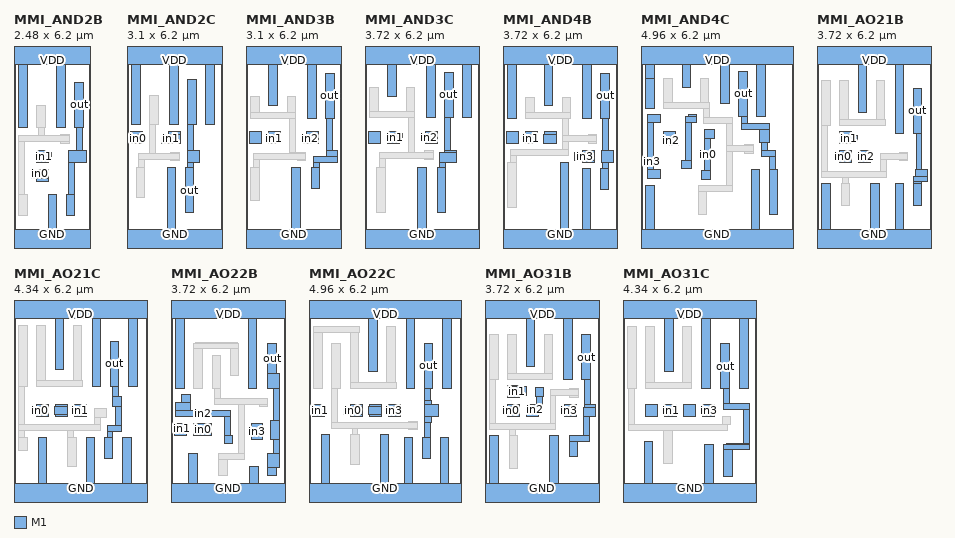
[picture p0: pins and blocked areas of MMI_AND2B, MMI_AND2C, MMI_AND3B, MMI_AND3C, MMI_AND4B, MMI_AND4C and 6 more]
MACRO MMI_AND2B
	CLASS CORE ;
	FOREIGN MMI_AND2B 0 0 ;
	SIZE 2.48 BY 6.2 ;
	SYMMETRY X Y ;
	SITE CORE1 ;
	PIN out
		DIRECTION output ;
		USE SIGNAL ;
		PORT
			LAYER M1 ;
			RECT 1.99 3.745 2.27 5.215 ;
			LAYER M1 ;
			RECT 2.04 2.98 2.23 3.745 ;
			LAYER M1 ;
			RECT 1.785 2.6 2.36 2.98 ;
			LAYER M1 ;
			RECT 1.785 1.55 1.98 2.6 ;
			LAYER M1 ;
			RECT 1.71 0.85 1.99 1.55 ;
		END
		AntennaDiffArea 0.91245 ;
	END out
	PIN in1
		DIRECTION input ;
		USE SIGNAL ;
		PORT
			LAYER M1 ;
			RECT 0.74 2.93 1.12 2.98 ;
			LAYER M1 ;
			RECT 0.74 2.65 1.225 2.93 ;
			LAYER M1 ;
			RECT 0.74 2.6 1.12 2.65 ;
		END
		AntennaGateArea 0.231 ;
	END in1
	PIN GND
		DIRECTION inout ;
		USE GROUND ;
		PORT
			LAYER M1 ;
			RECT 1.12 0.42 1.4 1.55 ;
			LAYER M1 ;
			RECT 0.0 -0.42 2.48 0.42 ;
		END
	END GND
	PIN VDD
		DIRECTION inout ;
		USE POWER ;
		PORT
			LAYER M1 ;
			RECT 0.0 5.78 2.48 6.62 ;
			LAYER M1 ;
			RECT 0.16 3.745 0.44 5.78 ;
			LAYER M1 ;
			RECT 1.4 3.745 1.68 5.78 ;
		END
	END VDD
	PIN in0
		DIRECTION input ;
		USE SIGNAL ;
		PORT
			LAYER M1 ;
			RECT 0.56 2.08 1.12 2.36 ;
			LAYER M1 ;
			RECT 0.74 1.98 1.12 2.08 ;
		END
		AntennaGateArea 0.231 ;
	END in0
	OBS
		LAYER M1 ;
		RECT 0.75 3.745 1.03 4.445 ;
		LAYER M1 ;
		RECT 0.79 3.465 0.98 3.745 ;
		LAYER M1 ;
		RECT 1.52 3.465 1.8 3.51 ;
		LAYER M1 ;
		RECT 0.16 3.27 1.8 3.465 ;
		LAYER M1 ;
		RECT 0.16 1.55 0.355 3.27 ;
		LAYER M1 ;
		RECT 1.52 3.23 1.8 3.27 ;
		LAYER M1 ;
		RECT 0.16 0.85 0.44 1.55 ;
	END
END MMI_AND2B
MACRO MMI_AND2C
	CLASS CORE ;
	FOREIGN MMI_AND2C 0 0 ;
	SIZE 3.1 BY 6.2 ;
	SYMMETRY X Y ;
	SITE CORE1 ;
	PIN out
		DIRECTION output ;
		USE SIGNAL ;
		PORT
			LAYER M1 ;
			RECT 1.985 3.82 2.265 5.29 ;
			LAYER M1 ;
			RECT 1.99 2.98 2.18 3.82 ;
			LAYER M1 ;
			RECT 1.99 2.6 2.36 2.98 ;
			LAYER M1 ;
			RECT 1.99 2.43 2.18 2.6 ;
			LAYER M1 ;
			RECT 1.9 0.96 2.18 2.43 ;
		END
		AntennaDiffArea 1.2859 ;
	END out
	PIN in1
		DIRECTION input ;
		USE SIGNAL ;
		PORT
			LAYER M1 ;
			RECT 1.36 3.51 1.74 3.6 ;
			LAYER M1 ;
			RECT 1.135 3.23 1.74 3.51 ;
			LAYER M1 ;
			RECT 1.36 3.22 1.74 3.23 ;
		END
		AntennaGateArea 0.312 ;
	END in1
	PIN GND
		DIRECTION inout ;
		USE GROUND ;
		PORT
			LAYER M1 ;
			RECT 1.31 0.42 1.59 2.43 ;
			LAYER M1 ;
			RECT 0.0 -0.42 3.1 0.42 ;
		END
	END GND
	PIN VDD
		DIRECTION inout ;
		USE POWER ;
		PORT
			LAYER M1 ;
			RECT 0.0 5.78 3.1 6.62 ;
			LAYER M1 ;
			RECT 0.155 3.82 0.435 5.78 ;
			LAYER M1 ;
			RECT 1.395 3.82 1.675 5.78 ;
			LAYER M1 ;
			RECT 2.575 3.82 2.855 5.78 ;
		END
	END VDD
	PIN in0
		DIRECTION input ;
		USE SIGNAL ;
		PORT
			LAYER M1 ;
			RECT 0.12 3.51 0.5 3.6 ;
			LAYER M1 ;
			RECT 0.12 3.23 0.505 3.51 ;
			LAYER M1 ;
			RECT 0.12 3.22 0.5 3.23 ;
		END
		AntennaGateArea 0.312 ;
	END in0
	OBS
		LAYER M1 ;
		RECT 0.745 3.82 1.025 4.79 ;
		LAYER M1 ;
		RECT 0.745 2.885 0.935 3.82 ;
		LAYER M1 ;
		RECT 1.435 2.885 1.715 2.93 ;
		LAYER M1 ;
		RECT 0.39 2.695 1.715 2.885 ;
		LAYER M1 ;
		RECT 0.39 2.435 0.58 2.695 ;
		LAYER M1 ;
		RECT 1.435 2.65 1.715 2.695 ;
		LAYER M1 ;
		RECT 0.3 1.465 0.58 2.435 ;
	END
END MMI_AND2C
MACRO MMI_AND3B
	CLASS CORE ;
	FOREIGN MMI_AND3B 0 0 ;
	SIZE 3.1 BY 6.2 ;
	SYMMETRY X Y ;
	SITE CORE1 ;
	PIN out
		DIRECTION output ;
		USE SIGNAL ;
		PORT
			LAYER M1 ;
			RECT 2.595 4.04 2.875 5.51 ;
			LAYER M1 ;
			RECT 2.635 2.98 2.825 4.04 ;
			LAYER M1 ;
			RECT 2.635 2.795 2.98 2.98 ;
			LAYER M1 ;
			RECT 2.215 2.6 2.98 2.795 ;
			LAYER M1 ;
			RECT 2.215 2.445 2.405 2.6 ;
			LAYER M1 ;
			RECT 2.125 1.745 2.405 2.445 ;
		END
		AntennaDiffArea 0.91245 ;
	END out
	PIN in1
		DIRECTION input ;
		USE SIGNAL ;
		PORT
			LAYER M1 ;
			RECT 0.74 3.51 1.12 3.6 ;
			LAYER M1 ;
			RECT 0.725 3.23 1.12 3.51 ;
			LAYER M1 ;
			RECT 0.74 3.22 1.12 3.23 ;
		END
		AntennaGateArea 0.28875 ;
	END in1
	PIN GND
		DIRECTION inout ;
		USE GROUND ;
		PORT
			LAYER M1 ;
			RECT 1.49 0.42 1.77 2.445 ;
			LAYER M1 ;
			RECT 0.0 -0.42 3.1 0.42 ;
		END
	END GND
	PIN in2
		DIRECTION input ;
		USE SIGNAL ;
		PORT
			LAYER M1 ;
			RECT 1.98 3.51 2.36 3.6 ;
			LAYER M1 ;
			RECT 1.83 3.23 2.36 3.51 ;
			LAYER M1 ;
			RECT 1.98 3.22 2.36 3.23 ;
		END
		AntennaGateArea 0.28875 ;
	END in2
	PIN VDD
		DIRECTION inout ;
		USE POWER ;
		PORT
			LAYER M1 ;
			RECT 0.0 5.78 3.1 6.62 ;
			LAYER M1 ;
			RECT 0.75 4.46 1.03 5.78 ;
			LAYER M1 ;
			RECT 2.005 4.04 2.285 5.78 ;
		END
	END VDD
	PIN in0
		DIRECTION input ;
		USE SIGNAL ;
		PORT
			LAYER M1 ;
			RECT 0.12 3.22 0.5 3.6 ;
		END
		AntennaGateArea 0.28875 ;
	END in0
	OBS
		LAYER M1 ;
		RECT 0.16 4.23 0.44 4.74 ;
		LAYER M1 ;
		RECT 1.34 4.23 1.62 4.74 ;
		LAYER M1 ;
		RECT 0.15 4.04 1.62 4.23 ;
		LAYER M1 ;
		RECT 1.42 2.93 1.61 4.04 ;
		LAYER M1 ;
		RECT 1.42 2.885 1.945 2.93 ;
		LAYER M1 ;
		RECT 0.245 2.695 1.945 2.885 ;
		LAYER M1 ;
		RECT 0.245 2.445 0.435 2.695 ;
		LAYER M1 ;
		RECT 1.665 2.65 1.945 2.695 ;
		LAYER M1 ;
		RECT 0.16 1.36 0.44 2.445 ;
	END
END MMI_AND3B
MACRO MMI_AND3C
	CLASS CORE ;
	FOREIGN MMI_AND3C 0 0 ;
	SIZE 3.72 BY 6.2 ;
	SYMMETRY X Y ;
	SITE CORE1 ;
	PIN out
		DIRECTION output ;
		USE SIGNAL ;
		PORT
			LAYER M1 ;
			RECT 2.595 4.07 2.875 5.54 ;
			LAYER M1 ;
			RECT 2.6 2.98 2.79 4.07 ;
			LAYER M1 ;
			RECT 2.6 2.93 2.98 2.98 ;
			LAYER M1 ;
			RECT 2.435 2.6 2.98 2.93 ;
			LAYER M1 ;
			RECT 2.435 2.445 2.63 2.6 ;
			LAYER M1 ;
			RECT 2.35 0.975 2.63 2.445 ;
		END
		AntennaDiffArea 1.2859 ;
	END out
	PIN in1
		DIRECTION input ;
		USE SIGNAL ;
		PORT
			LAYER M1 ;
			RECT 0.74 3.545 1.12 3.6 ;
			LAYER M1 ;
			RECT 0.74 3.265 1.23 3.545 ;
			LAYER M1 ;
			RECT 0.74 3.22 1.12 3.265 ;
		END
		AntennaGateArea 0.39 ;
	END in1
	PIN GND
		DIRECTION inout ;
		USE GROUND ;
		PORT
			LAYER M1 ;
			RECT 1.715 0.42 1.995 2.445 ;
			LAYER M1 ;
			RECT 0.0 -0.42 3.72 0.42 ;
		END
	END GND
	PIN in2
		DIRECTION input ;
		USE SIGNAL ;
		PORT
			LAYER M1 ;
			RECT 1.98 3.55 2.36 3.6 ;
			LAYER M1 ;
			RECT 1.82 3.27 2.36 3.55 ;
			LAYER M1 ;
			RECT 1.98 3.22 2.36 3.27 ;
		END
		AntennaGateArea 0.39 ;
	END in2
	PIN VDD
		DIRECTION inout ;
		USE POWER ;
		PORT
			LAYER M1 ;
			RECT 0.0 5.78 3.72 6.62 ;
			LAYER M1 ;
			RECT 0.75 4.76 1.03 5.78 ;
			LAYER M1 ;
			RECT 2.005 4.07 2.285 5.78 ;
			LAYER M1 ;
			RECT 3.185 4.07 3.465 5.78 ;
		END
	END VDD
	PIN in0
		DIRECTION input ;
		USE SIGNAL ;
		PORT
			LAYER M1 ;
			RECT 0.12 3.22 0.5 3.6 ;
		END
		AntennaGateArea 0.39 ;
	END in0
	OBS
		LAYER M1 ;
		RECT 0.16 4.26 0.44 5.04 ;
		LAYER M1 ;
		RECT 1.34 4.26 1.62 5.04 ;
		LAYER M1 ;
		RECT 0.16 4.07 1.62 4.26 ;
		LAYER M1 ;
		RECT 1.43 2.93 1.62 4.07 ;
		LAYER M1 ;
		RECT 1.95 2.93 2.23 2.97 ;
		LAYER M1 ;
		RECT 0.465 2.735 2.23 2.93 ;
		LAYER M1 ;
		RECT 0.465 2.445 0.66 2.735 ;
		LAYER M1 ;
		RECT 1.95 2.69 2.23 2.735 ;
		LAYER M1 ;
		RECT 0.385 0.955 0.665 2.445 ;
	END
END MMI_AND3C
MACRO MMI_AND4B
	CLASS CORE ;
	FOREIGN MMI_AND4B 0 0 ;
	SIZE 3.72 BY 6.2 ;
	SYMMETRY X Y ;
	SITE CORE1 ;
	PIN out
		DIRECTION output ;
		USE SIGNAL ;
		PORT
			LAYER M1 ;
			RECT 3.195 4.03 3.475 5.5 ;
			LAYER M1 ;
			RECT 3.26 2.98 3.455 4.03 ;
			LAYER M1 ;
			RECT 3.22 2.6 3.6 2.98 ;
			LAYER M1 ;
			RECT 3.26 2.4 3.455 2.6 ;
			LAYER M1 ;
			RECT 3.175 1.7 3.455 2.4 ;
		END
		AntennaDiffArea 0.91245 ;
	END out
	PIN in1
		DIRECTION input ;
		USE SIGNAL ;
		PORT
			LAYER M1 ;
			RECT 0.74 3.505 1.12 3.6 ;
			LAYER M1 ;
			RECT 0.725 3.225 1.12 3.505 ;
			LAYER M1 ;
			RECT 0.74 3.22 1.12 3.225 ;
		END
		AntennaGateArea 0.3465 ;
	END in1
	PIN GND
		DIRECTION inout ;
		USE GROUND ;
		PORT
			LAYER M1 ;
			RECT 1.86 0.42 2.14 2.605 ;
			LAYER M1 ;
			RECT 2.585 0.42 2.865 2.4 ;
			LAYER M1 ;
			RECT 0.0 -0.42 3.72 0.42 ;
		END
	END GND
	PIN in2
		DIRECTION input ;
		USE SIGNAL ;
		PORT
			LAYER M1 ;
			RECT 1.36 3.5 1.74 3.6 ;
			LAYER M1 ;
			RECT 1.32 3.22 1.74 3.5 ;
		END
		AntennaGateArea 0.3465 ;
	END in2
	PIN VDD
		DIRECTION inout ;
		USE POWER ;
		PORT
			LAYER M1 ;
			RECT 0.0 5.78 3.72 6.62 ;
			LAYER M1 ;
			RECT 0.16 4.03 0.44 5.78 ;
			LAYER M1 ;
			RECT 1.34 4.45 1.62 5.78 ;
			LAYER M1 ;
			RECT 2.605 4.03 2.885 5.78 ;
		END
	END VDD
	PIN in3
		DIRECTION input ;
		USE SIGNAL ;
		PORT
			LAYER M1 ;
			RECT 2.6 2.93 2.98 2.98 ;
			LAYER M1 ;
			RECT 2.34 2.65 2.98 2.93 ;
			LAYER M1 ;
			RECT 2.6 2.6 2.98 2.65 ;
		END
		AntennaGateArea 0.3465 ;
	END in3
	PIN in0
		DIRECTION input ;
		USE SIGNAL ;
		PORT
			LAYER M1 ;
			RECT 0.12 3.22 0.5 3.6 ;
		END
		AntennaGateArea 0.3465 ;
	END in0
	OBS
		LAYER M1 ;
		RECT 0.75 4.225 1.03 4.73 ;
		LAYER M1 ;
		RECT 1.93 4.225 2.21 4.73 ;
		LAYER M1 ;
		RECT 0.75 4.03 2.21 4.225 ;
		LAYER M1 ;
		RECT 1.94 3.465 2.135 4.03 ;
		LAYER M1 ;
		RECT 2.775 3.465 3.055 3.51 ;
		LAYER M1 ;
		RECT 1.94 3.27 3.055 3.465 ;
		LAYER M1 ;
		RECT 1.94 3.015 2.135 3.27 ;
		LAYER M1 ;
		RECT 2.775 3.23 3.055 3.27 ;
		LAYER M1 ;
		RECT 0.245 2.82 2.135 3.015 ;
		LAYER M1 ;
		RECT 0.245 2.605 0.435 2.82 ;
		LAYER M1 ;
		RECT 0.16 1.135 0.44 2.605 ;
	END
END MMI_AND4B
MACRO MMI_AND4C
	CLASS CORE ;
	FOREIGN MMI_AND4C 0 0 ;
	SIZE 4.96 BY 6.2 ;
	SYMMETRY X Y ;
	SITE CORE1 ;
	PIN out
		DIRECTION output ;
		USE SIGNAL ;
		PORT
			LAYER M1 ;
			RECT 3.195 4.11 3.475 5.58 ;
			LAYER M1 ;
			RECT 3.275 3.875 3.465 4.11 ;
			LAYER M1 ;
			RECT 3.275 3.68 4.19 3.875 ;
			LAYER M1 ;
			RECT 3.865 3.255 4.19 3.68 ;
			LAYER M1 ;
			RECT 3.935 2.985 4.125 3.255 ;
			LAYER M1 ;
			RECT 3.935 2.79 4.385 2.985 ;
			LAYER M1 ;
			RECT 4.19 2.355 4.385 2.79 ;
			LAYER M1 ;
			RECT 4.19 0.885 4.47 2.355 ;
		END
		AntennaDiffArea 1.2859 ;
	END out
	PIN in1
		DIRECTION input ;
		USE SIGNAL ;
		PORT
			LAYER M1 ;
			RECT 1.535 4.08 1.815 4.165 ;
			LAYER M1 ;
			RECT 1.455 3.885 1.815 4.08 ;
			LAYER M1 ;
			RECT 1.455 2.675 1.645 3.885 ;
			LAYER M1 ;
			RECT 1.33 2.395 1.645 2.675 ;
		END
		AntennaGateArea 0.468 ;
	END in1
	PIN GND
		DIRECTION inout ;
		USE GROUND ;
		PORT
			LAYER M1 ;
			RECT 0.16 0.42 0.44 1.855 ;
			LAYER M1 ;
			RECT 3.6 0.42 3.88 2.355 ;
			LAYER M1 ;
			RECT 0.0 -0.42 4.96 0.42 ;
		END
	END GND
	PIN in2
		DIRECTION input ;
		USE SIGNAL ;
		PORT
			LAYER M1 ;
			RECT 0.74 3.43 1.12 3.6 ;
			LAYER M1 ;
			RECT 0.74 3.22 1.21 3.43 ;
			LAYER M1 ;
			RECT 0.93 3.15 1.21 3.22 ;
		END
		AntennaGateArea 0.468 ;
	END in2
	PIN VDD
		DIRECTION inout ;
		USE POWER ;
		PORT
			LAYER M1 ;
			RECT 0.0 5.78 4.96 6.62 ;
			LAYER M1 ;
			RECT 0.15 5.335 0.43 5.78 ;
			LAYER M1 ;
			RECT 0.16 4.365 0.44 5.335 ;
			LAYER M1 ;
			RECT 1.34 5.055 1.62 5.78 ;
			LAYER M1 ;
			RECT 2.605 4.52 2.885 5.78 ;
			LAYER M1 ;
			RECT 3.785 4.11 4.065 5.78 ;
		END
	END VDD
	PIN in3
		DIRECTION input ;
		USE SIGNAL ;
		PORT
			LAYER M1 ;
			RECT 0.215 3.885 0.635 4.165 ;
			LAYER M1 ;
			RECT 0.215 2.355 0.405 3.885 ;
			LAYER M1 ;
			RECT 0.215 2.075 0.635 2.355 ;
		END
		AntennaGateArea 0.468 ;
	END in3
	PIN in0
		DIRECTION input ;
		USE SIGNAL ;
		PORT
			LAYER M1 ;
			RECT 2.075 3.375 2.405 3.655 ;
			LAYER M1 ;
			RECT 2.075 2.335 2.265 3.375 ;
			LAYER M1 ;
			RECT 1.985 2.055 2.265 2.335 ;
		END
		AntennaGateArea 0.468 ;
	END in0
	OBS
		LAYER M1 ;
		RECT 0.75 4.56 1.03 5.335 ;
		LAYER M1 ;
		RECT 1.93 4.56 2.21 5.335 ;
		LAYER M1 ;
		RECT 0.75 4.365 2.245 4.56 ;
		LAYER M1 ;
		RECT 2.055 4.06 2.245 4.365 ;
		LAYER M1 ;
		RECT 2.055 3.865 2.99 4.06 ;
		LAYER M1 ;
		RECT 2.8 3.14 2.99 3.865 ;
		LAYER M1 ;
		RECT 3.385 3.14 3.665 3.18 ;
		LAYER M1 ;
		RECT 2.8 2.945 3.665 3.14 ;
		LAYER M1 ;
		RECT 2.8 1.855 2.99 2.945 ;
		LAYER M1 ;
		RECT 3.385 2.9 3.665 2.945 ;
		LAYER M1 ;
		RECT 1.86 1.66 2.99 1.855 ;
		LAYER M1 ;
		RECT 1.86 0.885 2.14 1.66 ;
	END
END MMI_AND4C
MACRO MMI_AO21B
	CLASS CORE ;
	FOREIGN MMI_AO21B 0 0 ;
	SIZE 3.72 BY 6.2 ;
	SYMMETRY X Y ;
	SITE CORE1 ;
	PIN out
		DIRECTION output ;
		USE SIGNAL ;
		PORT
			LAYER M1 ;
			RECT 3.145 3.54 3.425 5.01 ;
			LAYER M1 ;
			RECT 3.235 2.36 3.425 3.54 ;
			LAYER M1 ;
			RECT 3.22 2.13 3.6 2.36 ;
			LAYER M1 ;
			RECT 3.15 1.98 3.6 2.13 ;
			LAYER M1 ;
			RECT 3.15 1.905 3.425 1.98 ;
			LAYER M1 ;
			RECT 3.145 1.205 3.425 1.905 ;
		END
		AntennaDiffArea 0.91245 ;
	END out
	PIN in1
		DIRECTION input ;
		USE SIGNAL ;
		PORT
			LAYER M1 ;
			RECT 0.74 3.51 1.12 3.6 ;
			LAYER M1 ;
			RECT 0.74 3.465 1.27 3.51 ;
			LAYER M1 ;
			RECT 0.74 3.27 1.33 3.465 ;
			LAYER M1 ;
			RECT 0.74 3.23 1.27 3.27 ;
			LAYER M1 ;
			RECT 0.74 3.22 1.12 3.23 ;
		END
		AntennaGateArea 0.3465 ;
	END in1
	PIN GND
		DIRECTION inout ;
		USE GROUND ;
		PORT
			LAYER M1 ;
			RECT 0.16 0.42 0.44 1.905 ;
			LAYER M1 ;
			RECT 1.755 0.42 2.035 1.905 ;
			LAYER M1 ;
			RECT 2.555 0.42 2.835 1.905 ;
			LAYER M1 ;
			RECT 0.0 -0.42 3.72 0.42 ;
		END
	END GND
	PIN in2
		DIRECTION input ;
		USE SIGNAL ;
		PORT
			LAYER M1 ;
			RECT 1.36 2.93 1.74 2.98 ;
			LAYER M1 ;
			RECT 1.36 2.65 1.84 2.93 ;
			LAYER M1 ;
			RECT 1.36 2.6 1.74 2.65 ;
		END
		AntennaGateArea 0.3465 ;
	END in2
	PIN VDD
		DIRECTION inout ;
		USE POWER ;
		PORT
			LAYER M1 ;
			RECT 0.0 5.78 3.72 6.62 ;
			LAYER M1 ;
			RECT 1.34 4.225 1.62 5.78 ;
			LAYER M1 ;
			RECT 2.555 3.54 2.835 5.78 ;
		END
	END VDD
	PIN in0
		DIRECTION input ;
		USE SIGNAL ;
		PORT
			LAYER M1 ;
			RECT 0.74 2.93 1.12 2.98 ;
			LAYER M1 ;
			RECT 0.56 2.65 1.12 2.93 ;
			LAYER M1 ;
			RECT 0.74 2.6 1.12 2.65 ;
		END
		AntennaGateArea 0.28875 ;
	END in0
	OBS
		LAYER M1 ;
		RECT 0.16 3.815 0.44 5.285 ;
		LAYER M1 ;
		RECT 0.75 4.005 1.03 5.285 ;
		LAYER M1 ;
		RECT 1.93 4.005 2.21 5.285 ;
		LAYER M1 ;
		RECT 0.75 3.815 2.245 4.005 ;
		LAYER M1 ;
		RECT 0.16 2.31 0.355 3.815 ;
		LAYER M1 ;
		RECT 2.68 2.885 2.96 2.93 ;
		LAYER M1 ;
		RECT 2.075 2.695 2.96 2.885 ;
		LAYER M1 ;
		RECT 2.075 2.31 2.265 2.695 ;
		LAYER M1 ;
		RECT 2.68 2.65 2.96 2.695 ;
		LAYER M1 ;
		RECT 0.16 2.115 2.265 2.31 ;
		LAYER M1 ;
		RECT 0.84 1.905 1.03 2.115 ;
		LAYER M1 ;
		RECT 0.795 1.205 1.075 1.905 ;
	END
END MMI_AO21B
MACRO MMI_AO21C
	CLASS CORE ;
	FOREIGN MMI_AO21C 0 0 ;
	SIZE 4.34 BY 6.2 ;
	SYMMETRY X Y ;
	SITE CORE1 ;
	PIN out
		DIRECTION output ;
		USE SIGNAL ;
		PORT
			LAYER M1 ;
			RECT 3.145 3.58 3.425 5.05 ;
			LAYER M1 ;
			RECT 3.23 3.24 3.425 3.58 ;
			LAYER M1 ;
			RECT 3.23 2.915 3.515 3.24 ;
			LAYER M1 ;
			RECT 3.325 2.315 3.515 2.915 ;
			LAYER M1 ;
			RECT 3.035 2.12 3.515 2.315 ;
			LAYER M1 ;
			RECT 3.035 1.915 3.225 2.12 ;
			LAYER M1 ;
			RECT 2.95 1.215 3.23 1.915 ;
		END
		AntennaDiffArea 1.0164 ;
	END out
	PIN in1
		DIRECTION input ;
		USE SIGNAL ;
		PORT
			LAYER M1 ;
			RECT 1.98 2.93 2.36 2.98 ;
			LAYER M1 ;
			RECT 1.95 2.65 2.36 2.93 ;
			LAYER M1 ;
			RECT 1.98 2.6 2.36 2.65 ;
		END
		AntennaGateArea 0.468 ;
	END in1
	PIN GND
		DIRECTION inout ;
		USE GROUND ;
		PORT
			LAYER M1 ;
			RECT 0.795 0.42 1.075 1.92 ;
			LAYER M1 ;
			RECT 2.36 0.42 2.64 1.915 ;
			LAYER M1 ;
			RECT 3.54 0.42 3.82 1.915 ;
			LAYER M1 ;
			RECT 0.0 -0.42 4.34 0.42 ;
		END
	END GND
	PIN in2
		DIRECTION input ;
		USE SIGNAL ;
		PORT
			LAYER M1 ;
			RECT 1.36 2.93 1.74 2.98 ;
			LAYER M1 ;
			RECT 1.33 2.65 1.74 2.93 ;
			LAYER M1 ;
			RECT 1.36 2.6 1.74 2.65 ;
		END
		AntennaGateArea 0.468 ;
	END in2
	PIN VDD
		DIRECTION inout ;
		USE POWER ;
		PORT
			LAYER M1 ;
			RECT 0.0 5.78 4.34 6.62 ;
			LAYER M1 ;
			RECT 1.34 4.13 1.62 5.78 ;
			LAYER M1 ;
			RECT 2.555 3.58 2.835 5.78 ;
			LAYER M1 ;
			RECT 3.735 3.58 4.015 5.78 ;
		END
	END VDD
	PIN in0
		DIRECTION input ;
		USE SIGNAL ;
		PORT
			LAYER M1 ;
			RECT 0.74 2.93 1.12 2.98 ;
			LAYER M1 ;
			RECT 0.555 2.65 1.12 2.93 ;
			LAYER M1 ;
			RECT 0.74 2.6 1.12 2.65 ;
		END
		AntennaGateArea 0.39 ;
	END in0
	OBS
		LAYER M1 ;
		RECT 0.16 3.57 0.44 5.58 ;
		LAYER M1 ;
		RECT 0.75 3.76 1.03 5.58 ;
		LAYER M1 ;
		RECT 1.93 3.76 2.21 5.58 ;
		LAYER M1 ;
		RECT 0.75 3.57 2.245 3.76 ;
		LAYER M1 ;
		RECT 0.16 2.32 0.355 3.57 ;
		LAYER M1 ;
		RECT 2.62 2.565 3.03 2.845 ;
		LAYER M1 ;
		RECT 2.62 2.32 2.81 2.565 ;
		LAYER M1 ;
		RECT 0.16 2.125 2.81 2.32 ;
		LAYER M1 ;
		RECT 0.16 1.92 0.355 2.125 ;
		LAYER M1 ;
		RECT 1.75 1.92 1.945 2.125 ;
		LAYER M1 ;
		RECT 0.16 1.47 0.44 1.92 ;
		LAYER M1 ;
		RECT 1.755 0.95 2.035 1.92 ;
	END
END MMI_AO21C
MACRO MMI_AO22B
	CLASS CORE ;
	FOREIGN MMI_AO22B 0 0 ;
	SIZE 3.72 BY 6.2 ;
	SYMMETRY X Y ;
	SITE CORE1 ;
	PIN out
		DIRECTION output ;
		USE SIGNAL ;
		PORT
			LAYER M1 ;
			RECT 3.165 4.01 3.445 4.99 ;
			LAYER M1 ;
			RECT 3.165 3.52 3.555 4.01 ;
			LAYER M1 ;
			RECT 3.36 2.48 3.555 3.52 ;
			LAYER M1 ;
			RECT 3.245 1.86 3.555 2.48 ;
			LAYER M1 ;
			RECT 3.36 1.385 3.555 1.86 ;
			LAYER M1 ;
			RECT 3.165 0.935 3.555 1.385 ;
			LAYER M1 ;
			RECT 3.165 0.685 3.445 0.935 ;
		END
		AntennaDiffArea 0.91245 ;
	END out
	PIN in1
		DIRECTION input ;
		USE SIGNAL ;
		PORT
			LAYER M1 ;
			RECT 0.12 2.35 0.5 2.36 ;
			LAYER M1 ;
			RECT 0.12 2.07 0.53 2.35 ;
			LAYER M1 ;
			RECT 0.12 1.98 0.5 2.07 ;
		END
		AntennaGateArea 0.3465 ;
	END in1
	PIN GND
		DIRECTION inout ;
		USE GROUND ;
		PORT
			LAYER M1 ;
			RECT 0.58 0.42 0.86 1.385 ;
			LAYER M1 ;
			RECT 2.575 0.42 2.855 0.965 ;
			LAYER M1 ;
			RECT 0.0 -0.42 3.72 0.42 ;
		END
	END GND
	PIN in2
		DIRECTION input ;
		USE SIGNAL ;
		PORT
			LAYER M1 ;
			RECT 0.355 3.04 0.635 3.315 ;
			LAYER M1 ;
			RECT 0.16 2.8 0.635 3.04 ;
			LAYER M1 ;
			RECT 0.16 2.605 1.945 2.8 ;
			LAYER M1 ;
			RECT 1.75 1.98 1.945 2.605 ;
			LAYER M1 ;
			RECT 1.73 1.7 2.01 1.98 ;
		END
		AntennaGateArea 0.3465 ;
	END in2
	PIN VDD
		DIRECTION inout ;
		USE POWER ;
		PORT
			LAYER M1 ;
			RECT 0.0 5.78 3.72 6.62 ;
			LAYER M1 ;
			RECT 0.16 3.52 0.44 5.78 ;
			LAYER M1 ;
			RECT 2.52 3.52 2.8 5.78 ;
		END
	END VDD
	PIN in3
		DIRECTION input ;
		USE SIGNAL ;
		PORT
			LAYER M1 ;
			RECT 2.625 1.845 2.98 2.36 ;
		END
		AntennaGateArea 0.3465 ;
	END in3
	PIN in0
		DIRECTION input ;
		USE SIGNAL ;
		PORT
			LAYER M1 ;
			RECT 0.74 1.98 1.33 2.36 ;
		END
		AntennaGateArea 0.3465 ;
	END in0
	OBS
		LAYER M1 ;
		RECT 0.81 4.99 2.185 4.995 ;
		LAYER M1 ;
		RECT 0.75 4.8 2.21 4.99 ;
		LAYER M1 ;
		RECT 0.75 3.52 1.03 4.8 ;
		LAYER M1 ;
		RECT 1.34 3.52 1.62 4.58 ;
		LAYER M1 ;
		RECT 1.93 3.93 2.21 4.8 ;
		LAYER M1 ;
		RECT 1.42 3.195 1.615 3.52 ;
		LAYER M1 ;
		RECT 1.42 3.0 3.16 3.195 ;
		LAYER M1 ;
		RECT 2.21 1.385 2.4 3.0 ;
		LAYER M1 ;
		RECT 2.88 2.915 3.16 3.0 ;
		LAYER M1 ;
		RECT 1.56 1.195 2.4 1.385 ;
		LAYER M1 ;
		RECT 1.56 0.685 1.84 1.195 ;
	END
END MMI_AO22B
MACRO MMI_AO22C
	CLASS CORE ;
	FOREIGN MMI_AO22C 0 0 ;
	SIZE 4.96 BY 6.2 ;
	SYMMETRY X Y ;
	SITE CORE1 ;
	PIN out
		DIRECTION output ;
		USE SIGNAL ;
		PORT
			LAYER M1 ;
			RECT 3.765 3.515 4.045 4.985 ;
			LAYER M1 ;
			RECT 3.78 3.13 3.97 3.515 ;
			LAYER M1 ;
			RECT 3.78 2.98 3.985 3.13 ;
			LAYER M1 ;
			RECT 3.78 2.6 4.22 2.98 ;
			LAYER M1 ;
			RECT 3.78 2.39 3.985 2.6 ;
			LAYER M1 ;
			RECT 3.78 1.91 3.97 2.39 ;
			LAYER M1 ;
			RECT 3.695 1.21 3.975 1.91 ;
		END
		AntennaDiffArea 1.0164 ;
	END out
	PIN in1
		DIRECTION input ;
		USE SIGNAL ;
		PORT
			LAYER M1 ;
			RECT 0.12 2.6 0.5 2.98 ;
		END
		AntennaGateArea 0.468 ;
	END in1
	PIN GND
		DIRECTION inout ;
		USE GROUND ;
		PORT
			LAYER M1 ;
			RECT 0.395 0.42 0.675 2.01 ;
			LAYER M1 ;
			RECT 2.325 0.42 2.605 2.01 ;
			LAYER M1 ;
			RECT 3.105 0.42 3.385 1.91 ;
			LAYER M1 ;
			RECT 4.285 0.42 4.565 1.91 ;
			LAYER M1 ;
			RECT 0.0 -0.42 4.96 0.42 ;
		END
	END GND
	PIN in2
		DIRECTION input ;
		USE SIGNAL ;
		PORT
			LAYER M1 ;
			RECT 1.98 2.93 2.36 2.98 ;
			LAYER M1 ;
			RECT 1.94 2.65 2.36 2.93 ;
			LAYER M1 ;
			RECT 1.98 2.6 2.36 2.65 ;
		END
		AntennaGateArea 0.468 ;
	END in2
	PIN VDD
		DIRECTION inout ;
		USE POWER ;
		PORT
			LAYER M1 ;
			RECT 0.0 5.78 4.96 6.62 ;
			LAYER M1 ;
			RECT 1.955 4.075 2.235 5.78 ;
			LAYER M1 ;
			RECT 3.175 3.515 3.455 5.78 ;
			LAYER M1 ;
			RECT 4.355 3.515 4.635 5.78 ;
		END
	END VDD
	PIN in3
		DIRECTION input ;
		USE SIGNAL ;
		PORT
			LAYER M1 ;
			RECT 2.6 2.935 2.98 2.98 ;
			LAYER M1 ;
			RECT 2.57 2.655 2.98 2.935 ;
			LAYER M1 ;
			RECT 2.6 2.6 2.98 2.655 ;
		END
		AntennaGateArea 0.468 ;
	END in3
	PIN in0
		DIRECTION input ;
		USE SIGNAL ;
		PORT
			LAYER M1 ;
			RECT 1.36 2.93 1.74 2.98 ;
			LAYER M1 ;
			RECT 1.14 2.65 1.74 2.93 ;
			LAYER M1 ;
			RECT 1.36 2.6 1.74 2.65 ;
		END
		AntennaGateArea 0.468 ;
	END in0
	OBS
		LAYER M1 ;
		RECT 0.16 5.52 0.44 5.525 ;
		LAYER M1 ;
		RECT 1.34 5.52 1.62 5.525 ;
		LAYER M1 ;
		RECT 0.15 5.33 1.64 5.52 ;
		LAYER M1 ;
		RECT 0.16 3.515 0.44 5.33 ;
		LAYER M1 ;
		RECT 0.75 3.515 1.03 4.965 ;
		LAYER M1 ;
		RECT 1.34 3.705 1.62 5.33 ;
		LAYER M1 ;
		RECT 2.545 3.705 2.825 5.525 ;
		LAYER M1 ;
		RECT 1.34 3.515 2.85 3.705 ;
		LAYER M1 ;
		RECT 0.75 2.4 0.94 3.515 ;
		LAYER M1 ;
		RECT 1.36 3.51 2.85 3.515 ;
		LAYER M1 ;
		RECT 3.25 2.4 3.53 2.435 ;
		LAYER M1 ;
		RECT 0.75 2.21 3.53 2.4 ;
		LAYER M1 ;
		RECT 1.405 2.01 1.595 2.21 ;
		LAYER M1 ;
		RECT 3.25 2.155 3.53 2.21 ;
		LAYER M1 ;
		RECT 1.365 1.04 1.645 2.01 ;
	END
END MMI_AO22C
MACRO MMI_AO31B
	CLASS CORE ;
	FOREIGN MMI_AO31B 0 0 ;
	SIZE 3.72 BY 6.2 ;
	SYMMETRY X Y ;
	SITE CORE1 ;
	PIN out
		DIRECTION output ;
		USE SIGNAL ;
		PORT
			LAYER M1 ;
			RECT 3.165 3.8 3.445 5.27 ;
			LAYER M1 ;
			RECT 3.25 2.98 3.445 3.8 ;
			LAYER M1 ;
			RECT 3.25 2.885 3.6 2.98 ;
			LAYER M1 ;
			RECT 3.22 2.6 3.6 2.885 ;
			LAYER M1 ;
			RECT 3.22 1.98 3.415 2.6 ;
			LAYER M1 ;
			RECT 2.84 1.975 3.415 1.98 ;
			LAYER M1 ;
			RECT 2.75 1.785 3.415 1.975 ;
			LAYER M1 ;
			RECT 2.75 1.275 3.03 1.785 ;
		END
		AntennaDiffArea 0.91245 ;
	END out
	PIN in1
		DIRECTION input ;
		USE SIGNAL ;
		PORT
			LAYER M1 ;
			RECT 0.74 3.56 1.12 3.6 ;
			LAYER M1 ;
			RECT 0.74 3.28 1.345 3.56 ;
			LAYER M1 ;
			RECT 0.74 3.27 1.33 3.28 ;
			LAYER M1 ;
			RECT 0.74 3.22 1.12 3.27 ;
		END
		AntennaGateArea 0.40425 ;
	END in1
	PIN GND
		DIRECTION inout ;
		USE GROUND ;
		PORT
			LAYER M1 ;
			RECT 0.16 0.42 0.44 1.975 ;
			LAYER M1 ;
			RECT 2.12 0.42 2.4 1.975 ;
			LAYER M1 ;
			RECT 0.0 -0.42 3.72 0.42 ;
		END
	END GND
	PIN in2
		DIRECTION input ;
		USE SIGNAL ;
		PORT
			LAYER M1 ;
			RECT 1.645 3.245 1.925 3.525 ;
			LAYER M1 ;
			RECT 1.695 2.98 1.89 3.245 ;
			LAYER M1 ;
			RECT 1.36 2.695 1.89 2.98 ;
			LAYER M1 ;
			RECT 1.36 2.6 1.74 2.695 ;
		END
		AntennaGateArea 0.40425 ;
	END in2
	PIN VDD
		DIRECTION inout ;
		USE POWER ;
		PORT
			LAYER M1 ;
			RECT 0.0 5.78 3.72 6.62 ;
			LAYER M1 ;
			RECT 1.34 4.21 1.62 5.78 ;
			LAYER M1 ;
			RECT 2.575 3.8 2.855 5.78 ;
		END
	END VDD
	PIN in3
		DIRECTION input ;
		USE SIGNAL ;
		PORT
			LAYER M1 ;
			RECT 2.6 2.93 2.98 2.98 ;
			LAYER M1 ;
			RECT 2.515 2.65 2.98 2.93 ;
			LAYER M1 ;
			RECT 2.6 2.6 2.98 2.65 ;
		END
		AntennaGateArea 0.40425 ;
	END in3
	PIN in0
		DIRECTION input ;
		USE SIGNAL ;
		PORT
			LAYER M1 ;
			RECT 0.74 2.93 1.12 2.98 ;
			LAYER M1 ;
			RECT 0.555 2.65 1.12 2.93 ;
			LAYER M1 ;
			RECT 0.74 2.6 1.12 2.65 ;
		END
		AntennaGateArea 0.28875 ;
	END in0
	OBS
		LAYER M1 ;
		RECT 0.16 3.8 0.44 5.27 ;
		LAYER M1 ;
		RECT 0.75 3.995 1.03 5.27 ;
		LAYER M1 ;
		RECT 1.93 3.995 2.21 5.27 ;
		LAYER M1 ;
		RECT 0.75 3.8 2.21 3.995 ;
		LAYER M1 ;
		RECT 0.16 2.375 0.355 3.8 ;
		LAYER M1 ;
		RECT 2.755 3.465 3.035 3.51 ;
		LAYER M1 ;
		RECT 2.125 3.27 3.035 3.465 ;
		LAYER M1 ;
		RECT 2.125 2.375 2.315 3.27 ;
		LAYER M1 ;
		RECT 2.755 3.23 3.035 3.27 ;
		LAYER M1 ;
		RECT 0.16 2.185 2.315 2.375 ;
		LAYER M1 ;
		RECT 0.795 1.975 0.985 2.185 ;
		LAYER M1 ;
		RECT 0.79 0.89 1.07 1.975 ;
	END
END MMI_AO31B
MACRO MMI_AO31C
	CLASS CORE ;
	FOREIGN MMI_AO31C 0 0 ;
	SIZE 4.34 BY 6.2 ;
	SYMMETRY X Y ;
	SITE CORE1 ;
	PIN out
		DIRECTION output ;
		USE SIGNAL ;
		PORT
			LAYER M1 ;
			RECT 3.195 3.505 3.475 4.975 ;
			LAYER M1 ;
			RECT 3.285 3.03 3.475 3.505 ;
			LAYER M1 ;
			RECT 3.285 2.835 4.125 3.03 ;
			LAYER M1 ;
			RECT 3.935 1.7 4.125 2.835 ;
			LAYER M1 ;
			RECT 3.375 1.69 4.125 1.7 ;
			LAYER M1 ;
			RECT 3.295 1.51 4.125 1.69 ;
			LAYER M1 ;
			RECT 3.295 0.63 3.575 1.51 ;
		END
		AntennaDiffArea 1.309 ;
	END out
	PIN in1
		DIRECTION input ;
		USE SIGNAL ;
		PORT
			LAYER M1 ;
			RECT 1.36 2.6 1.74 2.98 ;
		END
		AntennaGateArea 0.546 ;
	END in1
	PIN GND
		DIRECTION inout ;
		USE GROUND ;
		PORT
			LAYER M1 ;
			RECT 0.695 0.42 0.975 1.77 ;
			LAYER M1 ;
			RECT 2.66 0.42 2.94 1.675 ;
			LAYER M1 ;
			RECT 0.0 -0.42 4.34 0.42 ;
		END
	END GND
	PIN in2
		DIRECTION input ;
		USE SIGNAL ;
		PORT
			LAYER M1 ;
			RECT 1.98 2.6 2.36 2.98 ;
		END
		AntennaGateArea 0.546 ;
	END in2
	PIN VDD
		DIRECTION inout ;
		USE POWER ;
		PORT
			LAYER M1 ;
			RECT 0.0 5.78 4.34 6.62 ;
			LAYER M1 ;
			RECT 1.365 4.065 1.645 5.78 ;
			LAYER M1 ;
			RECT 2.56 3.505 2.84 5.78 ;
			LAYER M1 ;
			RECT 3.8 3.505 4.08 5.78 ;
		END
	END VDD
	PIN in3
		DIRECTION input ;
		USE SIGNAL ;
		PORT
			LAYER M1 ;
			RECT 2.6 2.6 2.98 2.98 ;
		END
		AntennaGateArea 0.546 ;
	END in3
	PIN in0
		DIRECTION input ;
		USE SIGNAL ;
		PORT
			LAYER M1 ;
			RECT 0.74 2.6 1.12 2.98 ;
		END
		AntennaGateArea 0.39 ;
	END in0
	OBS
		LAYER M1 ;
		RECT 0.16 3.505 0.44 5.515 ;
		LAYER M1 ;
		RECT 0.75 3.695 1.03 5.515 ;
		LAYER M1 ;
		RECT 1.955 3.695 2.235 5.515 ;
		LAYER M1 ;
		RECT 0.75 3.505 2.235 3.695 ;
		LAYER M1 ;
		RECT 0.195 2.325 0.39 3.505 ;
		LAYER M1 ;
		RECT 3.235 2.33 3.515 2.61 ;
		LAYER M1 ;
		RECT 3.235 2.325 3.425 2.33 ;
		LAYER M1 ;
		RECT 0.195 2.135 3.425 2.325 ;
		LAYER M1 ;
		RECT 1.33 1.045 1.61 2.135 ;
	END
END MMI_AO31C
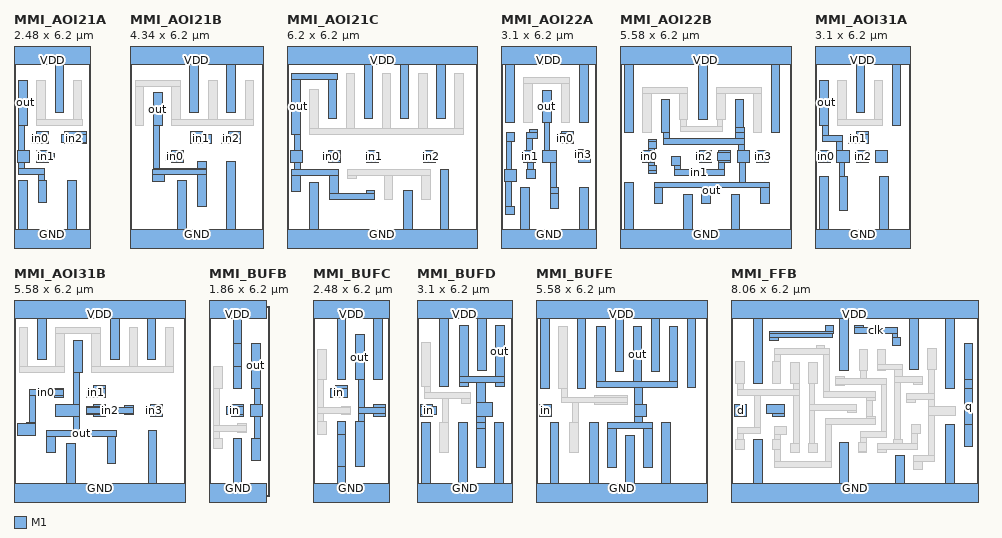
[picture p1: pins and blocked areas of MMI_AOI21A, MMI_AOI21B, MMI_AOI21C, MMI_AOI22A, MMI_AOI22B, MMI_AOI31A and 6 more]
MACRO MMI_AOI21A
	CLASS CORE ;
	FOREIGN MMI_AOI21A 0 0 ;
	SIZE 2.48 BY 6.2 ;
	SYMMETRY X Y ;
	SITE CORE1 ;
	PIN out
		DIRECTION output ;
		USE SIGNAL ;
		PORT
			LAYER M1 ;
			RECT 0.16 3.815 0.44 5.285 ;
			LAYER M1 ;
			RECT 0.16 2.98 0.355 3.815 ;
			LAYER M1 ;
			RECT 0.12 2.6 0.5 2.98 ;
			LAYER M1 ;
			RECT 0.16 2.395 0.355 2.6 ;
			LAYER M1 ;
			RECT 0.16 2.2 0.985 2.395 ;
			LAYER M1 ;
			RECT 0.795 1.995 0.985 2.2 ;
			LAYER M1 ;
			RECT 0.795 1.295 1.075 1.995 ;
		END
		AntennaDiffArea 0.948 ;
	END out
	PIN in1
		DIRECTION input ;
		USE SIGNAL ;
		PORT
			LAYER M1 ;
			RECT 0.74 2.93 1.12 2.98 ;
			LAYER M1 ;
			RECT 0.74 2.885 1.27 2.93 ;
			LAYER M1 ;
			RECT 0.74 2.695 1.33 2.885 ;
			LAYER M1 ;
			RECT 0.74 2.65 1.27 2.695 ;
			LAYER M1 ;
			RECT 0.74 2.6 1.12 2.65 ;
		END
		AntennaGateArea 0.3465 ;
	END in1
	PIN GND
		DIRECTION inout ;
		USE GROUND ;
		PORT
			LAYER M1 ;
			RECT 0.16 0.42 0.44 2.0 ;
			LAYER M1 ;
			RECT 1.755 0.42 2.035 1.995 ;
			LAYER M1 ;
			RECT 0.0 -0.42 2.48 0.42 ;
		END
	END GND
	PIN in2
		DIRECTION input ;
		USE SIGNAL ;
		PORT
			LAYER M1 ;
			RECT 1.65 3.515 2.36 3.6 ;
			LAYER M1 ;
			RECT 1.56 3.235 2.36 3.515 ;
			LAYER M1 ;
			RECT 1.65 3.22 2.36 3.235 ;
		END
		AntennaGateArea 0.3465 ;
	END in2
	PIN VDD
		DIRECTION inout ;
		USE POWER ;
		PORT
			LAYER M1 ;
			RECT 0.0 5.78 2.48 6.62 ;
			LAYER M1 ;
			RECT 1.34 4.225 1.62 5.78 ;
		END
	END VDD
	PIN in0
		DIRECTION input ;
		USE SIGNAL ;
		PORT
			LAYER M1 ;
			RECT 0.74 3.51 1.12 3.6 ;
			LAYER M1 ;
			RECT 0.555 3.23 1.12 3.51 ;
			LAYER M1 ;
			RECT 0.74 3.22 1.12 3.23 ;
		END
		AntennaGateArea 0.28875 ;
	END in0
	OBS
		LAYER M1 ;
		RECT 0.75 4.01 1.03 5.285 ;
		LAYER M1 ;
		RECT 1.93 4.01 2.21 5.285 ;
		LAYER M1 ;
		RECT 0.75 3.815 2.245 4.01 ;
	END
END MMI_AOI21A
MACRO MMI_AOI21B
	CLASS CORE ;
	FOREIGN MMI_AOI21B 0 0 ;
	SIZE 4.34 BY 6.2 ;
	SYMMETRY X Y ;
	SITE CORE1 ;
	PIN out
		DIRECTION output ;
		USE SIGNAL ;
		PORT
			LAYER M1 ;
			RECT 0.765 3.81 1.045 4.87 ;
			LAYER M1 ;
			RECT 0.765 2.39 0.955 3.81 ;
			LAYER M1 ;
			RECT 2.205 2.39 2.485 2.62 ;
			LAYER M1 ;
			RECT 0.765 2.36 2.485 2.39 ;
			LAYER M1 ;
			RECT 0.74 2.195 2.485 2.36 ;
			LAYER M1 ;
			RECT 0.74 1.98 1.12 2.195 ;
			LAYER M1 ;
			RECT 2.205 1.15 2.485 2.195 ;
		END
		AntennaDiffArea 1.36675 ;
	END out
	PIN in1
		DIRECTION input ;
		USE SIGNAL ;
		PORT
			LAYER M1 ;
			RECT 1.98 3.51 2.36 3.6 ;
			LAYER M1 ;
			RECT 1.98 3.23 2.675 3.51 ;
			LAYER M1 ;
			RECT 1.98 3.225 2.405 3.23 ;
			LAYER M1 ;
			RECT 1.98 3.22 2.36 3.225 ;
		END
		AntennaGateArea 0.693 ;
	END in1
	PIN GND
		DIRECTION inout ;
		USE GROUND ;
		PORT
			LAYER M1 ;
			RECT 1.555 0.42 1.835 1.995 ;
			LAYER M1 ;
			RECT 3.165 0.42 3.445 2.62 ;
			LAYER M1 ;
			RECT 0.0 -0.42 4.34 0.42 ;
		END
	END GND
	PIN in2
		DIRECTION input ;
		USE SIGNAL ;
		PORT
			LAYER M1 ;
			RECT 3.22 3.51 3.6 3.6 ;
			LAYER M1 ;
			RECT 2.97 3.23 3.6 3.51 ;
			LAYER M1 ;
			RECT 3.22 3.22 3.6 3.23 ;
		END
		AntennaGateArea 0.693 ;
	END in2
	PIN VDD
		DIRECTION inout ;
		USE POWER ;
		PORT
			LAYER M1 ;
			RECT 0.0 5.78 4.34 6.62 ;
			LAYER M1 ;
			RECT 1.945 4.22 2.225 5.78 ;
			LAYER M1 ;
			RECT 3.165 4.22 3.445 5.78 ;
		END
	END VDD
	PIN in0
		DIRECTION input ;
		USE SIGNAL ;
		PORT
			LAYER M1 ;
			RECT 1.36 2.93 1.74 2.98 ;
			LAYER M1 ;
			RECT 1.165 2.65 1.74 2.93 ;
			LAYER M1 ;
			RECT 1.36 2.6 1.74 2.65 ;
		END
		AntennaGateArea 0.5775 ;
	END in0
	OBS
		LAYER M1 ;
		RECT 0.165 5.09 1.64 5.285 ;
		LAYER M1 ;
		RECT 0.175 3.81 0.455 5.09 ;
		LAYER M1 ;
		RECT 1.355 4.0 1.635 5.09 ;
		LAYER M1 ;
		RECT 2.575 4.0 2.855 5.28 ;
		LAYER M1 ;
		RECT 3.755 4.0 4.035 5.28 ;
		LAYER M1 ;
		RECT 1.355 3.81 4.045 4.0 ;
	END
END MMI_AOI21B
MACRO MMI_AOI21C
	CLASS CORE ;
	FOREIGN MMI_AOI21C 0 0 ;
	SIZE 6.2 BY 6.2 ;
	SYMMETRY X Y ;
	SITE CORE1 ;
	PIN out
		DIRECTION output ;
		USE SIGNAL ;
		PORT
			LAYER M1 ;
			RECT 0.15 5.315 1.64 5.505 ;
			LAYER M1 ;
			RECT 0.16 3.515 0.44 5.315 ;
			LAYER M1 ;
			RECT 1.34 4.045 1.62 5.315 ;
			LAYER M1 ;
			RECT 0.245 2.98 0.435 3.515 ;
			LAYER M1 ;
			RECT 0.12 2.6 0.5 2.98 ;
			LAYER M1 ;
			RECT 0.245 2.35 0.435 2.6 ;
			LAYER M1 ;
			RECT 0.16 2.16 1.68 2.35 ;
			LAYER M1 ;
			RECT 0.16 1.65 0.44 2.16 ;
			LAYER M1 ;
			RECT 1.4 1.585 1.68 2.16 ;
			LAYER M1 ;
			RECT 2.58 1.585 2.86 1.675 ;
			LAYER M1 ;
			RECT 1.4 1.39 2.86 1.585 ;
		END
		AntennaDiffArea 2.9568 ;
	END out
	PIN in1
		DIRECTION input ;
		USE SIGNAL ;
		PORT
			LAYER M1 ;
			RECT 2.6 2.93 2.98 2.98 ;
			LAYER M1 ;
			RECT 2.6 2.65 3.05 2.93 ;
			LAYER M1 ;
			RECT 2.6 2.6 2.98 2.65 ;
		END
		AntennaGateArea 1.386 ;
	END in1
	PIN GND
		DIRECTION inout ;
		USE GROUND ;
		PORT
			LAYER M1 ;
			RECT 0.75 0.42 1.03 1.93 ;
			LAYER M1 ;
			RECT 3.815 0.42 4.095 1.675 ;
			LAYER M1 ;
			RECT 4.995 0.42 5.275 2.35 ;
			LAYER M1 ;
			RECT 0.0 -0.42 6.2 0.42 ;
		END
	END GND
	PIN in2
		DIRECTION input ;
		USE SIGNAL ;
		PORT
			LAYER M1 ;
			RECT 4.46 2.93 4.84 2.98 ;
			LAYER M1 ;
			RECT 4.46 2.885 4.86 2.93 ;
			LAYER M1 ;
			RECT 4.46 2.695 4.915 2.885 ;
			LAYER M1 ;
			RECT 4.46 2.65 4.86 2.695 ;
			LAYER M1 ;
			RECT 4.46 2.6 4.84 2.65 ;
		END
		AntennaGateArea 1.386 ;
	END in2
	PIN VDD
		DIRECTION inout ;
		USE POWER ;
		PORT
			LAYER M1 ;
			RECT 0.0 5.78 6.2 6.62 ;
			LAYER M1 ;
			RECT 2.52 4.045 2.8 5.78 ;
			LAYER M1 ;
			RECT 3.7 4.045 3.98 5.78 ;
			LAYER M1 ;
			RECT 4.88 4.045 5.16 5.78 ;
		END
	END VDD
	PIN in0
		DIRECTION input ;
		USE SIGNAL ;
		PORT
			LAYER M1 ;
			RECT 1.36 2.93 1.74 2.98 ;
			LAYER M1 ;
			RECT 1.16 2.65 1.74 2.93 ;
			LAYER M1 ;
			RECT 1.36 2.6 1.74 2.65 ;
		END
		AntennaGateArea 1.15575 ;
	END in0
	OBS
		LAYER M1 ;
		RECT 0.75 3.71 1.03 4.965 ;
		LAYER M1 ;
		RECT 1.93 3.71 2.21 5.5 ;
		LAYER M1 ;
		RECT 3.11 3.71 3.39 5.5 ;
		LAYER M1 ;
		RECT 4.29 3.71 4.57 5.5 ;
		LAYER M1 ;
		RECT 5.47 3.71 5.75 5.5 ;
		LAYER M1 ;
		RECT 0.75 3.515 5.77 3.71 ;
		LAYER M1 ;
		RECT 1.99 2.16 4.685 2.35 ;
		LAYER M1 ;
		RECT 1.99 2.065 2.27 2.16 ;
		LAYER M1 ;
		RECT 3.17 1.395 3.45 2.16 ;
		LAYER M1 ;
		RECT 4.405 1.395 4.685 2.16 ;
	END
END MMI_AOI21C
MACRO MMI_AOI22A
	CLASS CORE ;
	FOREIGN MMI_AOI22A 0 0 ;
	SIZE 3.1 BY 6.2 ;
	SYMMETRY X Y ;
	SITE CORE1 ;
	PIN out
		DIRECTION output ;
		USE SIGNAL ;
		PORT
			LAYER M1 ;
			RECT 1.355 3.885 1.635 4.945 ;
			LAYER M1 ;
			RECT 1.405 2.98 1.595 3.885 ;
			LAYER M1 ;
			RECT 1.36 2.6 1.795 2.98 ;
			LAYER M1 ;
			RECT 1.6 1.78 1.795 2.6 ;
			LAYER M1 ;
			RECT 1.6 1.59 1.89 1.78 ;
			LAYER M1 ;
			RECT 1.61 1.08 1.89 1.59 ;
		END
		AntennaDiffArea 1.04335 ;
	END out
	PIN in1
		DIRECTION input ;
		USE SIGNAL ;
		PORT
			LAYER M1 ;
			RECT 0.925 3.58 1.205 3.67 ;
			LAYER M1 ;
			RECT 0.82 3.39 1.205 3.58 ;
			LAYER M1 ;
			RECT 0.82 3.385 1.15 3.39 ;
			LAYER M1 ;
			RECT 0.82 2.98 1.015 3.385 ;
			LAYER M1 ;
			RECT 0.74 2.6 1.12 2.98 ;
			LAYER M1 ;
			RECT 0.875 2.35 1.07 2.6 ;
			LAYER M1 ;
			RECT 0.83 2.07 1.11 2.35 ;
		END
		AntennaGateArea 0.3465 ;
	END in1
	PIN GND
		DIRECTION inout ;
		USE GROUND ;
		PORT
			LAYER M1 ;
			RECT 0.635 0.42 0.915 1.78 ;
			LAYER M1 ;
			RECT 2.57 0.42 2.85 1.78 ;
			LAYER M1 ;
			RECT 0.0 -0.42 3.1 0.42 ;
		END
	END GND
	PIN in2
		DIRECTION input ;
		USE SIGNAL ;
		PORT
			LAYER M1 ;
			RECT 0.165 3.295 0.445 3.575 ;
			LAYER M1 ;
			RECT 0.165 2.36 0.355 3.295 ;
			LAYER M1 ;
			RECT 0.12 1.98 0.5 2.36 ;
			LAYER M1 ;
			RECT 0.155 1.17 0.35 1.98 ;
			LAYER M1 ;
			RECT 0.155 0.89 0.435 1.17 ;
		END
		AntennaGateArea 0.3465 ;
	END in2
	PIN VDD
		DIRECTION inout ;
		USE POWER ;
		PORT
			LAYER M1 ;
			RECT 0.0 5.78 3.1 6.62 ;
			LAYER M1 ;
			RECT 0.16 3.885 0.44 5.78 ;
			LAYER M1 ;
			RECT 2.56 3.885 2.84 5.78 ;
		END
	END VDD
	PIN in3
		DIRECTION input ;
		USE SIGNAL ;
		PORT
			LAYER M1 ;
			RECT 2.435 2.975 2.715 3.015 ;
			LAYER M1 ;
			RECT 2.435 2.735 2.91 2.975 ;
			LAYER M1 ;
			RECT 2.535 2.6 2.91 2.735 ;
		END
		AntennaGateArea 0.3465 ;
	END in3
	PIN in0
		DIRECTION input ;
		USE SIGNAL ;
		PORT
			LAYER M1 ;
			RECT 1.98 3.53 2.36 3.6 ;
			LAYER M1 ;
			RECT 1.795 3.25 2.36 3.53 ;
			LAYER M1 ;
			RECT 1.98 3.22 2.36 3.25 ;
		END
		AntennaGateArea 0.3465 ;
	END in0
	OBS
		LAYER M1 ;
		RECT 0.755 5.355 2.245 5.36 ;
		LAYER M1 ;
		RECT 0.75 5.165 2.25 5.355 ;
		LAYER M1 ;
		RECT 0.75 3.885 1.03 5.165 ;
		LAYER M1 ;
		RECT 1.97 3.885 2.25 5.165 ;
	END
END MMI_AOI22A
MACRO MMI_AOI22B
	CLASS CORE ;
	FOREIGN MMI_AOI22B 0 0 ;
	SIZE 5.58 BY 6.2 ;
	SYMMETRY X Y ;
	SITE CORE1 ;
	PIN out
		DIRECTION output ;
		USE SIGNAL ;
		PORT
			LAYER M1 ;
			RECT 1.34 3.585 1.62 4.645 ;
			LAYER M1 ;
			RECT 3.755 3.73 4.035 4.645 ;
			LAYER M1 ;
			RECT 3.755 3.585 4.055 3.73 ;
			LAYER M1 ;
			RECT 1.425 3.375 1.615 3.585 ;
			LAYER M1 ;
			RECT 3.77 3.375 4.055 3.585 ;
			LAYER M1 ;
			RECT 1.425 3.18 4.055 3.375 ;
			LAYER M1 ;
			RECT 3.865 2.98 4.055 3.18 ;
			LAYER M1 ;
			RECT 3.84 2.6 4.22 2.98 ;
			LAYER M1 ;
			RECT 3.9 1.955 4.095 2.6 ;
			LAYER M1 ;
			RECT 1.115 1.765 4.875 1.955 ;
			LAYER M1 ;
			RECT 1.12 1.255 1.4 1.765 ;
			LAYER M1 ;
			RECT 2.67 1.255 2.95 1.765 ;
			LAYER M1 ;
			RECT 4.59 1.255 4.87 1.765 ;
		END
		AntennaDiffArea 2.3023 ;
	END out
	PIN in1
		DIRECTION input ;
		USE SIGNAL ;
		PORT
			LAYER M1 ;
			RECT 3.22 2.93 3.6 2.98 ;
			LAYER M1 ;
			RECT 1.685 2.51 1.965 2.79 ;
			LAYER M1 ;
			RECT 3.18 2.65 3.6 2.93 ;
			LAYER M1 ;
			RECT 1.775 2.36 1.965 2.51 ;
			LAYER M1 ;
			RECT 3.215 2.6 3.6 2.65 ;
			LAYER M1 ;
			RECT 3.215 2.36 3.405 2.6 ;
			LAYER M1 ;
			RECT 1.775 2.165 3.405 2.36 ;
		END
		AntennaGateArea 0.693 ;
	END in1
	PIN GND
		DIRECTION inout ;
		USE GROUND ;
		PORT
			LAYER M1 ;
			RECT 0.16 0.42 0.44 1.955 ;
			LAYER M1 ;
			RECT 2.08 0.42 2.36 1.535 ;
			LAYER M1 ;
			RECT 3.63 0.42 3.91 1.535 ;
			LAYER M1 ;
			RECT 0.0 -0.42 5.58 0.42 ;
		END
	END GND
	PIN in2
		DIRECTION input ;
		USE SIGNAL ;
		PORT
			LAYER M1 ;
			RECT 2.6 2.93 2.98 2.98 ;
			LAYER M1 ;
			RECT 2.53 2.65 2.98 2.93 ;
			LAYER M1 ;
			RECT 2.6 2.6 2.98 2.65 ;
		END
		AntennaGateArea 0.693 ;
	END in2
	PIN VDD
		DIRECTION inout ;
		USE POWER ;
		PORT
			LAYER M1 ;
			RECT 0.0 5.78 5.58 6.62 ;
			LAYER M1 ;
			RECT 0.16 3.585 0.44 5.78 ;
			LAYER M1 ;
			RECT 2.575 3.985 2.855 5.78 ;
			LAYER M1 ;
			RECT 4.935 3.585 5.215 5.78 ;
		END
	END VDD
	PIN in3
		DIRECTION input ;
		USE SIGNAL ;
		PORT
			LAYER M1 ;
			RECT 4.46 2.6 4.84 2.98 ;
		END
		AntennaGateArea 0.693 ;
	END in3
	PIN in0
		DIRECTION input ;
		USE SIGNAL ;
		PORT
			LAYER M1 ;
			RECT 0.925 3.265 1.205 3.34 ;
			LAYER M1 ;
			RECT 0.915 3.06 1.205 3.265 ;
			LAYER M1 ;
			RECT 0.915 2.98 1.12 3.06 ;
			LAYER M1 ;
			RECT 0.74 2.6 1.12 2.98 ;
			LAYER M1 ;
			RECT 0.92 2.51 1.12 2.6 ;
			LAYER M1 ;
			RECT 0.92 2.32 1.205 2.51 ;
			LAYER M1 ;
			RECT 0.925 2.23 1.205 2.32 ;
		END
		AntennaGateArea 0.693 ;
	END in0
	OBS
		LAYER M1 ;
		RECT 0.75 5.045 1.03 5.055 ;
		LAYER M1 ;
		RECT 1.93 5.045 2.21 5.055 ;
		LAYER M1 ;
		RECT 0.75 4.85 2.21 5.045 ;
		LAYER M1 ;
		RECT 0.75 3.585 1.03 4.85 ;
		LAYER M1 ;
		RECT 1.93 3.995 2.21 4.85 ;
		LAYER M1 ;
		RECT 1.98 3.785 2.175 3.995 ;
		LAYER M1 ;
		RECT 3.165 5.05 3.445 5.055 ;
		LAYER M1 ;
		RECT 4.345 5.05 4.625 5.055 ;
		LAYER M1 ;
		RECT 3.165 4.855 4.625 5.05 ;
		LAYER M1 ;
		RECT 3.165 3.985 3.445 4.855 ;
		LAYER M1 ;
		RECT 3.17 3.785 3.36 3.985 ;
		LAYER M1 ;
		RECT 1.98 3.59 3.36 3.785 ;
		LAYER M1 ;
		RECT 4.345 3.585 4.625 4.855 ;
	END
END MMI_AOI22B
MACRO MMI_AOI31A
	CLASS CORE ;
	FOREIGN MMI_AOI31A 0 0 ;
	SIZE 3.1 BY 6.2 ;
	SYMMETRY X Y ;
	SITE CORE1 ;
	PIN out
		DIRECTION output ;
		USE SIGNAL ;
		PORT
			LAYER M1 ;
			RECT 0.16 3.81 0.44 5.28 ;
			LAYER M1 ;
			RECT 0.25 3.465 0.44 3.81 ;
			LAYER M1 ;
			RECT 0.25 3.27 0.895 3.465 ;
			LAYER M1 ;
			RECT 0.7 2.98 0.895 3.27 ;
			LAYER M1 ;
			RECT 0.7 2.6 1.12 2.98 ;
			LAYER M1 ;
			RECT 0.785 2.125 0.975 2.6 ;
			LAYER M1 ;
			RECT 0.785 1.04 1.065 2.125 ;
		END
		AntennaDiffArea 1.09725 ;
	END out
	PIN in1
		DIRECTION input ;
		USE SIGNAL ;
		PORT
			LAYER M1 ;
			RECT 1.36 3.51 1.74 3.6 ;
			LAYER M1 ;
			RECT 1.095 3.23 1.74 3.51 ;
			LAYER M1 ;
			RECT 1.36 3.22 1.74 3.23 ;
		END
		AntennaGateArea 0.40425 ;
	END in1
	PIN GND
		DIRECTION inout ;
		USE GROUND ;
		PORT
			LAYER M1 ;
			RECT 0.155 0.42 0.435 2.125 ;
			LAYER M1 ;
			RECT 2.115 0.42 2.395 2.125 ;
			LAYER M1 ;
			RECT 0.0 -0.42 3.1 0.42 ;
		END
	END GND
	PIN in2
		DIRECTION input ;
		USE SIGNAL ;
		PORT
			LAYER M1 ;
			RECT 1.36 2.93 1.74 2.98 ;
			LAYER M1 ;
			RECT 1.36 2.65 1.745 2.93 ;
			LAYER M1 ;
			RECT 1.36 2.6 1.74 2.65 ;
		END
		AntennaGateArea 0.40425 ;
	END in2
	PIN VDD
		DIRECTION inout ;
		USE POWER ;
		PORT
			LAYER M1 ;
			RECT 0.0 5.78 3.1 6.62 ;
			LAYER M1 ;
			RECT 1.34 4.22 1.62 5.78 ;
			LAYER M1 ;
			RECT 2.52 3.81 2.8 5.78 ;
		END
	END VDD
	PIN in3
		DIRECTION input ;
		USE SIGNAL ;
		PORT
			LAYER M1 ;
			RECT 1.98 2.6 2.36 2.98 ;
		END
		AntennaGateArea 0.40425 ;
	END in3
	PIN in0
		DIRECTION input ;
		USE SIGNAL ;
		PORT
			LAYER M1 ;
			RECT 0.12 2.6 0.5 2.98 ;
		END
		AntennaGateArea 0.28875 ;
	END in0
	OBS
		LAYER M1 ;
		RECT 0.75 4.0 1.03 5.28 ;
		LAYER M1 ;
		RECT 1.93 4.0 2.21 5.28 ;
		LAYER M1 ;
		RECT 0.75 3.81 2.21 4.0 ;
	END
END MMI_AOI31A
MACRO MMI_AOI31B
	CLASS CORE ;
	FOREIGN MMI_AOI31B 0 0 ;
	SIZE 5.58 BY 6.2 ;
	SYMMETRY X Y ;
	SITE CORE1 ;
	PIN out
		DIRECTION output ;
		USE SIGNAL ;
		PORT
			LAYER M1 ;
			RECT 1.945 4.03 2.225 5.09 ;
			LAYER M1 ;
			RECT 1.945 2.98 2.14 4.03 ;
			LAYER M1 ;
			RECT 1.36 2.6 2.14 2.98 ;
			LAYER M1 ;
			RECT 1.945 2.135 2.14 2.6 ;
			LAYER M1 ;
			RECT 1.175 2.13 3.335 2.135 ;
			LAYER M1 ;
			RECT 1.075 1.94 3.335 2.13 ;
			LAYER M1 ;
			RECT 1.075 1.43 1.355 1.94 ;
			LAYER M1 ;
			RECT 3.045 1.045 3.325 1.94 ;
		END
		AntennaDiffArea 1.48995 ;
	END out
	PIN in1
		DIRECTION input ;
		USE SIGNAL ;
		PORT
			LAYER M1 ;
			RECT 2.6 3.505 2.98 3.6 ;
			LAYER M1 ;
			RECT 2.35 3.225 2.98 3.505 ;
			LAYER M1 ;
			RECT 2.6 3.22 2.98 3.225 ;
		END
		AntennaGateArea 0.8085 ;
	END in1
	PIN GND
		DIRECTION inout ;
		USE GROUND ;
		PORT
			LAYER M1 ;
			RECT 1.715 0.42 1.995 1.715 ;
			LAYER M1 ;
			RECT 4.38 0.42 4.66 2.13 ;
			LAYER M1 ;
			RECT 0.0 -0.42 5.58 0.42 ;
		END
	END GND
	PIN in2
		DIRECTION input ;
		USE SIGNAL ;
		PORT
			LAYER M1 ;
			RECT 2.6 2.935 2.98 2.98 ;
			LAYER M1 ;
			RECT 2.35 2.885 2.98 2.935 ;
			LAYER M1 ;
			RECT 3.615 2.885 3.895 2.95 ;
			LAYER M1 ;
			RECT 2.35 2.695 3.895 2.885 ;
			LAYER M1 ;
			RECT 2.35 2.655 2.98 2.695 ;
			LAYER M1 ;
			RECT 3.615 2.67 3.895 2.695 ;
			LAYER M1 ;
			RECT 2.6 2.6 2.98 2.655 ;
		END
		AntennaGateArea 0.8085 ;
	END in2
	PIN VDD
		DIRECTION inout ;
		USE POWER ;
		PORT
			LAYER M1 ;
			RECT 0.0 5.78 5.58 6.62 ;
			LAYER M1 ;
			RECT 0.765 4.44 1.045 5.78 ;
			LAYER M1 ;
			RECT 3.165 4.44 3.445 5.78 ;
			LAYER M1 ;
			RECT 4.345 4.44 4.625 5.78 ;
		END
	END VDD
	PIN in3
		DIRECTION input ;
		USE SIGNAL ;
		PORT
			LAYER M1 ;
			RECT 4.46 2.93 4.84 2.98 ;
			LAYER M1 ;
			RECT 4.275 2.65 4.84 2.93 ;
			LAYER M1 ;
			RECT 4.46 2.6 4.84 2.65 ;
		END
		AntennaGateArea 0.8085 ;
	END in3
	PIN in0
		DIRECTION input ;
		USE SIGNAL ;
		PORT
			LAYER M1 ;
			RECT 1.335 3.465 1.615 3.505 ;
			LAYER M1 ;
			RECT 0.5 3.27 1.615 3.465 ;
			LAYER M1 ;
			RECT 0.5 2.405 0.69 3.27 ;
			LAYER M1 ;
			RECT 1.335 3.225 1.615 3.27 ;
			LAYER M1 ;
			RECT 0.41 2.36 0.69 2.405 ;
			LAYER M1 ;
			RECT 0.12 1.98 0.69 2.36 ;
		END
		AntennaGateArea 0.5775 ;
	END in0
	OBS
		LAYER M1 ;
		RECT 0.175 4.225 0.455 5.5 ;
		LAYER M1 ;
		RECT 1.355 5.315 2.815 5.505 ;
		LAYER M1 ;
		RECT 1.355 4.225 1.635 5.315 ;
		LAYER M1 ;
		RECT 0.175 4.03 1.635 4.225 ;
		LAYER M1 ;
		RECT 2.535 4.225 2.815 5.315 ;
		LAYER M1 ;
		RECT 3.755 4.225 4.035 5.5 ;
		LAYER M1 ;
		RECT 4.935 4.225 5.215 5.5 ;
		LAYER M1 ;
		RECT 2.535 4.03 5.215 4.225 ;
	END
END MMI_AOI31B
MACRO MMI_BUFB
	CLASS CORE ;
	FOREIGN MMI_BUFB 0 0 ;
	SIZE 1.86 BY 6.2 ;
	SYMMETRY X Y ;
	SITE CORE1 ;
	PIN out
		DIRECTION output ;
		USE SIGNAL ;
		PORT
			LAYER M1 ;
			RECT 1.385 3.52 1.665 4.99 ;
			LAYER M1 ;
			RECT 1.475 2.98 1.665 3.52 ;
			LAYER M1 ;
			RECT 1.36 2.6 1.74 2.98 ;
			LAYER M1 ;
			RECT 1.475 1.865 1.665 2.6 ;
			LAYER M1 ;
			RECT 1.385 1.165 1.665 1.865 ;
		END
		AntennaDiffArea 0.91245 ;
	END out
	PIN GND
		DIRECTION inout ;
		USE GROUND ;
		PORT
			LAYER M1 ;
			RECT 0.795 0.42 1.075 1.865 ;
			LAYER M1 ;
			RECT 0.0 -0.42 1.86 0.42 ;
		END
	END GND
	PIN VDD
		DIRECTION inout ;
		USE POWER ;
		PORT
			LAYER M1 ;
			RECT 0.0 5.78 1.86 6.62 ;
			LAYER M1 ;
			RECT 0.79 4.99 1.07 5.78 ;
			LAYER M1 ;
			RECT 0.79 4.225 1.075 4.99 ;
			LAYER M1 ;
			RECT 0.795 3.52 1.075 4.225 ;
		END
	END VDD
	PIN in
		DIRECTION input ;
		USE SIGNAL ;
		PORT
			LAYER M1 ;
			RECT 0.74 2.93 1.12 2.98 ;
			LAYER M1 ;
			RECT 0.555 2.65 1.12 2.93 ;
			LAYER M1 ;
			RECT 0.74 2.6 1.12 2.65 ;
		END
		AntennaGateArea 0.17325 ;
	END in
	OBS
		LAYER M1 ;
		RECT 0.16 3.52 0.44 4.22 ;
		LAYER M1 ;
		RECT 0.16 2.31 0.355 3.52 ;
		LAYER M1 ;
		RECT 0.935 2.31 1.215 2.35 ;
		LAYER M1 ;
		RECT 0.16 2.115 1.215 2.31 ;
		LAYER M1 ;
		RECT 0.16 1.865 0.355 2.115 ;
		LAYER M1 ;
		RECT 0.935 2.07 1.215 2.115 ;
		LAYER M1 ;
		RECT 0.16 1.55 0.44 1.865 ;
	END
END MMI_BUFB
MACRO MMI_BUFC
	CLASS CORE ;
	FOREIGN MMI_BUFC 0 0 ;
	SIZE 2.48 BY 6.2 ;
	SYMMETRY X Y ;
	SITE CORE1 ;
	PIN out
		DIRECTION output ;
		USE SIGNAL ;
		PORT
			LAYER M1 ;
			RECT 1.385 3.8 1.665 5.27 ;
			LAYER M1 ;
			RECT 1.475 2.885 1.665 3.8 ;
			LAYER M1 ;
			RECT 1.98 2.885 2.36 2.98 ;
			LAYER M1 ;
			RECT 1.475 2.695 2.36 2.885 ;
			LAYER M1 ;
			RECT 1.475 2.445 1.665 2.695 ;
			LAYER M1 ;
			RECT 1.98 2.6 2.36 2.695 ;
			LAYER M1 ;
			RECT 1.385 0.975 1.665 2.445 ;
		END
		AntennaDiffArea 1.2859 ;
	END out
	PIN GND
		DIRECTION inout ;
		USE GROUND ;
		PORT
			LAYER M1 ;
			RECT 0.795 1.995 1.075 2.445 ;
			LAYER M1 ;
			RECT 0.79 0.975 1.075 1.995 ;
			LAYER M1 ;
			RECT 0.79 0.42 1.07 0.975 ;
			LAYER M1 ;
			RECT 0.0 -0.42 2.48 0.42 ;
		END
	END GND
	PIN VDD
		DIRECTION inout ;
		USE POWER ;
		PORT
			LAYER M1 ;
			RECT 0.0 5.78 2.48 6.62 ;
			LAYER M1 ;
			RECT 0.795 3.8 1.075 5.78 ;
			LAYER M1 ;
			RECT 1.975 3.8 2.255 5.78 ;
		END
	END VDD
	PIN in
		DIRECTION input ;
		USE SIGNAL ;
		PORT
			LAYER M1 ;
			RECT 0.74 3.51 1.12 3.6 ;
			LAYER M1 ;
			RECT 0.56 3.23 1.12 3.51 ;
			LAYER M1 ;
			RECT 0.74 3.22 1.12 3.23 ;
		END
		AntennaGateArea 0.234 ;
	END in
	OBS
		LAYER M1 ;
		RECT 0.16 3.8 0.44 4.77 ;
		LAYER M1 ;
		RECT 0.16 2.885 0.355 3.8 ;
		LAYER M1 ;
		RECT 0.93 2.885 1.21 2.93 ;
		LAYER M1 ;
		RECT 0.16 2.695 1.21 2.885 ;
		LAYER M1 ;
		RECT 0.16 2.445 0.355 2.695 ;
		LAYER M1 ;
		RECT 0.93 2.65 1.21 2.695 ;
		LAYER M1 ;
		RECT 0.16 1.995 0.44 2.445 ;
	END
END MMI_BUFC
MACRO MMI_BUFD
	CLASS CORE ;
	FOREIGN MMI_BUFD 0 0 ;
	SIZE 3.1 BY 6.2 ;
	SYMMETRY X Y ;
	SITE CORE1 ;
	PIN out
		DIRECTION output ;
		USE SIGNAL ;
		PORT
			LAYER M1 ;
			RECT 1.385 3.885 1.665 5.56 ;
			LAYER M1 ;
			RECT 2.565 3.885 2.845 5.56 ;
			LAYER M1 ;
			RECT 1.385 3.695 2.845 3.885 ;
			LAYER M1 ;
			RECT 1.385 3.575 1.665 3.695 ;
			LAYER M1 ;
			RECT 1.955 3.05 2.235 3.695 ;
			LAYER M1 ;
			RECT 2.565 3.575 2.845 3.695 ;
			LAYER M1 ;
			RECT 1.955 2.6 2.45 3.05 ;
			LAYER M1 ;
			RECT 1.955 2.395 2.235 2.6 ;
			LAYER M1 ;
			RECT 1.95 2.205 2.235 2.395 ;
			LAYER M1 ;
			RECT 1.95 0.925 2.23 2.205 ;
		END
		AntennaDiffArea 2.393525 ;
	END out
	PIN GND
		DIRECTION inout ;
		USE GROUND ;
		PORT
			LAYER M1 ;
			RECT 0.16 0.42 0.44 2.395 ;
			LAYER M1 ;
			RECT 1.36 0.42 1.64 2.395 ;
			LAYER M1 ;
			RECT 2.54 0.42 2.82 2.395 ;
			LAYER M1 ;
			RECT 0.0 -0.42 3.1 0.42 ;
		END
	END GND
	PIN VDD
		DIRECTION inout ;
		USE POWER ;
		PORT
			LAYER M1 ;
			RECT 0.0 5.78 3.1 6.62 ;
			LAYER M1 ;
			RECT 0.75 3.575 1.03 5.78 ;
			LAYER M1 ;
			RECT 1.975 4.105 2.255 5.78 ;
		END
	END VDD
	PIN in
		DIRECTION input ;
		USE SIGNAL ;
		PORT
			LAYER M1 ;
			RECT 0.12 2.93 0.5 2.98 ;
			LAYER M1 ;
			RECT 0.12 2.65 0.635 2.93 ;
			LAYER M1 ;
			RECT 0.12 2.6 0.5 2.65 ;
		END
		AntennaGateArea 0.468 ;
	END in
	OBS
		LAYER M1 ;
		RECT 0.16 3.575 0.44 5.025 ;
		LAYER M1 ;
		RECT 0.245 3.375 0.435 3.575 ;
		LAYER M1 ;
		RECT 0.245 3.18 1.745 3.375 ;
		LAYER M1 ;
		RECT 0.84 2.395 1.03 3.18 ;
		LAYER M1 ;
		RECT 1.465 3.015 1.745 3.18 ;
		LAYER M1 ;
		RECT 0.75 1.425 1.03 2.395 ;
	END
END MMI_BUFD
MACRO MMI_BUFE
	CLASS CORE ;
	FOREIGN MMI_BUFE 0 0 ;
	SIZE 5.58 BY 6.2 ;
	SYMMETRY X Y ;
	SITE CORE1 ;
	PIN out
		DIRECTION output ;
		USE SIGNAL ;
		PORT
			LAYER M1 ;
			RECT 1.99 3.725 2.27 5.52 ;
			LAYER M1 ;
			RECT 3.17 3.725 3.45 5.52 ;
			LAYER M1 ;
			RECT 4.35 3.725 4.63 5.52 ;
			LAYER M1 ;
			RECT 1.99 3.535 4.63 3.725 ;
			LAYER M1 ;
			RECT 1.995 3.53 4.63 3.535 ;
			LAYER M1 ;
			RECT 3.2 2.98 3.485 3.53 ;
			LAYER M1 ;
			RECT 3.2 2.6 3.6 2.98 ;
			LAYER M1 ;
			RECT 3.2 2.4 3.485 2.6 ;
			LAYER M1 ;
			RECT 2.34 2.205 3.8 2.4 ;
			LAYER M1 ;
			RECT 2.34 0.93 2.62 2.205 ;
			LAYER M1 ;
			RECT 3.52 0.93 3.8 2.205 ;
		END
		AntennaDiffArea 4.0678 ;
	END out
	PIN GND
		DIRECTION inout ;
		USE GROUND ;
		PORT
			LAYER M1 ;
			RECT 0.47 0.42 0.75 2.4 ;
			LAYER M1 ;
			RECT 1.75 0.42 2.03 2.4 ;
			LAYER M1 ;
			RECT 2.93 0.42 3.21 1.99 ;
			LAYER M1 ;
			RECT 4.11 0.42 4.39 2.4 ;
			LAYER M1 ;
			RECT 0.0 -0.42 5.58 0.42 ;
		END
	END GND
	PIN VDD
		DIRECTION inout ;
		USE POWER ;
		PORT
			LAYER M1 ;
			RECT 0.0 5.78 5.58 6.62 ;
			LAYER M1 ;
			RECT 0.16 3.515 0.44 5.78 ;
			LAYER M1 ;
			RECT 1.34 3.515 1.62 5.78 ;
			LAYER M1 ;
			RECT 2.58 4.065 2.86 5.78 ;
			LAYER M1 ;
			RECT 3.76 4.065 4.04 5.78 ;
			LAYER M1 ;
			RECT 4.94 3.535 5.22 5.78 ;
		END
	END VDD
	PIN in
		DIRECTION input ;
		USE SIGNAL ;
		PORT
			LAYER M1 ;
			RECT 0.12 2.6 0.5 2.98 ;
		END
		AntennaGateArea 0.936 ;
	END in
	OBS
		LAYER M1 ;
		RECT 0.75 3.515 1.03 5.525 ;
		LAYER M1 ;
		RECT 0.835 3.23 1.03 3.515 ;
		LAYER M1 ;
		RECT 1.92 3.23 2.98 3.275 ;
		LAYER M1 ;
		RECT 0.835 3.04 2.98 3.23 ;
		LAYER M1 ;
		RECT 1.19 2.4 1.38 3.04 ;
		LAYER M1 ;
		RECT 1.92 2.995 2.98 3.04 ;
		LAYER M1 ;
		RECT 1.1 1.43 1.38 2.4 ;
	END
END MMI_BUFE
MACRO MMI_FFB
	CLASS CORE ;
	FOREIGN MMI_FFB 0 0 ;
	SIZE 8.06 BY 6.2 ;
	SYMMETRY X Y ;
	SITE CORE1 ;
	PIN d
		DIRECTION input ;
		USE SIGNAL ;
		PORT
			LAYER M1 ;
			RECT 0.12 2.585 0.5 2.985 ;
		END
		AntennaGateArea 0.17325 ;
	END d
	PIN GND
		DIRECTION inout ;
		USE GROUND ;
		PORT
			LAYER M1 ;
			RECT 0.75 0.42 1.03 1.84 ;
			LAYER M1 ;
			RECT 3.555 0.42 3.835 1.745 ;
			LAYER M1 ;
			RECT 5.38 0.42 5.66 1.32 ;
			LAYER M1 ;
			RECT 7.015 0.42 7.295 2.32 ;
			LAYER M1 ;
			RECT 0.0 -0.42 8.06 0.42 ;
		END
	END GND
	PIN q
		DIRECTION output ;
		USE SIGNAL ;
		PORT
			LAYER M1 ;
			RECT 7.605 3.79 7.885 4.98 ;
			LAYER M1 ;
			RECT 7.605 3.51 7.895 3.79 ;
			LAYER M1 ;
			RECT 7.61 2.32 7.895 3.51 ;
			LAYER M1 ;
			RECT 7.605 1.63 7.895 2.32 ;
			LAYER M1 ;
			RECT 7.605 1.62 7.885 1.63 ;
		END
		AntennaDiffArea 0.91245 ;
	END q
	PIN VDD
		DIRECTION inout ;
		USE POWER ;
		PORT
			LAYER M1 ;
			RECT 0.0 5.78 8.06 6.62 ;
			LAYER M1 ;
			RECT 0.75 3.685 1.03 5.78 ;
			LAYER M1 ;
			RECT 3.55 4.09 3.83 5.78 ;
			LAYER M1 ;
			RECT 5.825 4.115 6.105 5.78 ;
			LAYER M1 ;
			RECT 7.015 3.51 7.295 5.78 ;
		END
	END VDD
	PIN clk
		DIRECTION input ;
		USE CLOCK ;
		PORT
			LAYER M1 ;
			RECT 3.07 5.365 3.35 5.58 ;
			LAYER M1 ;
			RECT 1.34 5.36 3.35 5.365 ;
			LAYER M1 ;
			RECT 1.27 5.3 3.35 5.36 ;
			LAYER M1 ;
			RECT 4.03 5.5 4.31 5.58 ;
			LAYER M1 ;
			RECT 4.03 5.31 5.445 5.5 ;
			LAYER M1 ;
			RECT 4.03 5.3 4.31 5.31 ;
			LAYER M1 ;
			RECT 1.27 5.17 3.31 5.3 ;
			LAYER M1 ;
			RECT 5.255 5.185 5.445 5.31 ;
			LAYER M1 ;
			RECT 1.27 5.08 1.55 5.17 ;
			LAYER M1 ;
			RECT 5.255 4.905 5.535 5.185 ;
			LAYER M1 ;
			RECT 1.365 2.975 1.745 2.98 ;
			LAYER M1 ;
			RECT 1.16 2.695 1.745 2.975 ;
			LAYER M1 ;
			RECT 1.365 2.6 1.745 2.695 ;
		END
		AntennaGateArea 0.44625 ;
	END clk
	OBS
		LAYER M1 ;
		RECT 0.16 3.685 0.44 4.385 ;
		LAYER M1 ;
		RECT 2.785 4.805 3.065 4.92 ;
		LAYER M1 ;
		RECT 1.43 4.615 3.215 4.805 ;
		LAYER M1 ;
		RECT 1.43 4.385 1.62 4.615 ;
		LAYER M1 ;
		RECT 1.34 3.685 1.62 4.385 ;
		LAYER M1 ;
		RECT 0.2 3.47 0.395 3.685 ;
		LAYER M1 ;
		RECT 1.955 3.67 2.235 4.37 ;
		LAYER M1 ;
		RECT 2.545 3.67 2.825 4.37 ;
		LAYER M1 ;
		RECT 2.03 3.47 2.225 3.67 ;
		LAYER M1 ;
		RECT 0.2 3.275 2.225 3.47 ;
		LAYER M1 ;
		RECT 0.765 2.23 0.955 3.275 ;
		LAYER M1 ;
		RECT 0.21 2.04 0.955 2.23 ;
		LAYER M1 ;
		RECT 0.21 1.84 0.4 2.04 ;
		LAYER M1 ;
		RECT 1.435 1.995 1.815 2.275 ;
		LAYER M1 ;
		RECT 1.435 1.84 1.625 1.995 ;
		LAYER M1 ;
		RECT 0.16 1.525 0.44 1.84 ;
		LAYER M1 ;
		RECT 1.34 1.525 1.625 1.84 ;
		LAYER M1 ;
		RECT 2.03 1.71 2.225 3.275 ;
		LAYER M1 ;
		RECT 2.55 2.995 2.74 3.67 ;
		LAYER M1 ;
		RECT 3.025 3.4 3.215 4.615 ;
		LAYER M1 ;
		RECT 4.185 4.09 4.465 4.79 ;
		LAYER M1 ;
		RECT 4.775 4.305 5.055 4.79 ;
		LAYER M1 ;
		RECT 4.775 4.115 5.6 4.305 ;
		LAYER M1 ;
		RECT 6.415 4.115 6.695 4.815 ;
		LAYER M1 ;
		RECT 4.775 4.09 5.055 4.115 ;
		LAYER M1 ;
		RECT 3.415 3.83 3.695 3.89 ;
		LAYER M1 ;
		RECT 4.22 3.83 4.415 4.09 ;
		LAYER M1 ;
		RECT 5.34 3.91 5.6 4.115 ;
		LAYER M1 ;
		RECT 3.415 3.635 5.09 3.83 ;
		LAYER M1 ;
		RECT 3.415 3.61 3.695 3.635 ;
		LAYER M1 ;
		RECT 3.025 3.205 4.7 3.4 ;
		LAYER M1 ;
		RECT 4.42 3.12 4.7 3.205 ;
		LAYER M1 ;
		RECT 2.55 2.8 4.085 2.995 ;
		LAYER M1 ;
		RECT 2.55 1.71 2.74 2.8 ;
		LAYER M1 ;
		RECT 3.805 2.715 4.085 2.8 ;
		LAYER M1 ;
		RECT 4.43 2.605 4.62 3.12 ;
		LAYER M1 ;
		RECT 4.42 2.515 4.7 2.605 ;
		LAYER M1 ;
		RECT 3.085 2.325 4.7 2.515 ;
		LAYER M1 ;
		RECT 1.435 1.12 1.625 1.525 ;
		LAYER M1 ;
		RECT 1.955 1.43 2.235 1.71 ;
		LAYER M1 ;
		RECT 2.545 1.43 2.825 1.71 ;
		LAYER M1 ;
		RECT 3.085 1.12 3.275 2.325 ;
		LAYER M1 ;
		RECT 4.9 2.105 5.09 3.635 ;
		LAYER M1 ;
		RECT 4.24 1.91 5.09 2.105 ;
		LAYER M1 ;
		RECT 5.34 3.72 6.245 3.91 ;
		LAYER M1 ;
		RECT 4.24 1.745 4.435 1.91 ;
		LAYER M1 ;
		RECT 5.34 1.84 5.535 3.72 ;
		LAYER M1 ;
		RECT 5.965 3.63 6.245 3.72 ;
		LAYER M1 ;
		RECT 6.445 3.34 6.635 4.115 ;
		LAYER M1 ;
		RECT 5.82 3.335 6.635 3.34 ;
		LAYER M1 ;
		RECT 5.735 3.145 6.635 3.335 ;
		LAYER M1 ;
		RECT 5.735 3.055 6.015 3.145 ;
		LAYER M1 ;
		RECT 6.445 2.91 6.635 3.145 ;
		LAYER M1 ;
		RECT 6.445 2.63 7.34 2.91 ;
		LAYER M1 ;
		RECT 6.445 2.625 6.97 2.63 ;
		LAYER M1 ;
		RECT 5.89 2.04 6.17 2.32 ;
		LAYER M1 ;
		RECT 1.435 0.93 3.275 1.12 ;
		LAYER M1 ;
		RECT 4.145 1.455 4.435 1.745 ;
		LAYER M1 ;
		RECT 5.305 1.71 5.585 1.84 ;
		LAYER M1 ;
		RECT 5.89 1.71 6.085 2.04 ;
		LAYER M1 ;
		RECT 4.78 1.52 6.085 1.71 ;
		LAYER M1 ;
		RECT 4.145 1.43 4.425 1.455 ;
		LAYER M1 ;
		RECT 4.78 1.43 5.06 1.52 ;
		LAYER M1 ;
		RECT 6.445 1.32 6.635 2.625 ;
		LAYER M1 ;
		RECT 5.97 1.13 6.635 1.32 ;
		LAYER M1 ;
		RECT 5.97 0.87 6.25 1.13 ;
	END
END MMI_FFB
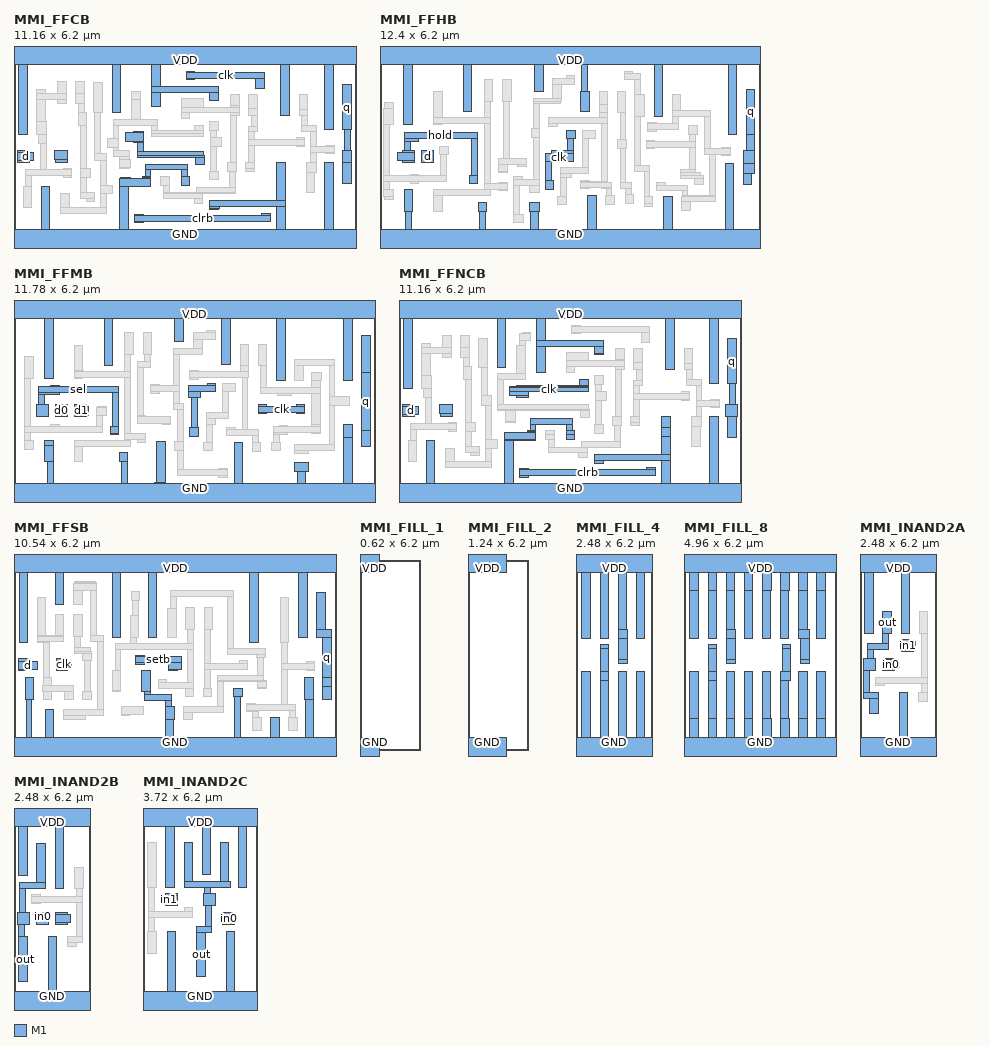
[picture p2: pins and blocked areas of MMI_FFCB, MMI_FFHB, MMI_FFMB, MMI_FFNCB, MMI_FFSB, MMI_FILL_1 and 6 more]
MACRO MMI_FFCB
	CLASS CORE ;
	FOREIGN MMI_FFCB 0 0 ;
	SIZE 11.16 BY 6.2 ;
	SYMMETRY X Y ;
	SITE CORE1 ;
	PIN d
		DIRECTION input ;
		USE SIGNAL ;
		PORT
			LAYER M1 ;
			RECT 0.12 2.925 0.5 2.98 ;
			LAYER M1 ;
			RECT 0.12 2.645 0.635 2.925 ;
			LAYER M1 ;
			RECT 0.12 2.6 0.5 2.645 ;
		END
		AntennaGateArea 0.3465 ;
	END d
	PIN GND
		DIRECTION inout ;
		USE GROUND ;
		PORT
			LAYER M1 ;
			RECT 4.275 2.355 5.655 2.545 ;
			LAYER M1 ;
			RECT 4.275 2.145 4.465 2.355 ;
			LAYER M1 ;
			RECT 5.46 2.145 5.655 2.355 ;
			LAYER M1 ;
			RECT 4.19 2.11 4.47 2.145 ;
			LAYER M1 ;
			RECT 3.485 2.085 3.8 2.11 ;
			LAYER M1 ;
			RECT 4.185 2.085 4.47 2.11 ;
			LAYER M1 ;
			RECT 0.885 0.42 1.165 1.82 ;
			LAYER M1 ;
			RECT 3.45 1.8 4.47 2.085 ;
			LAYER M1 ;
			RECT 5.46 1.83 5.74 2.145 ;
			LAYER M1 ;
			RECT 3.45 0.42 3.73 1.8 ;
			LAYER M1 ;
			RECT 6.38 1.345 6.66 1.35 ;
			LAYER M1 ;
			RECT 8.57 1.345 8.85 2.595 ;
			LAYER M1 ;
			RECT 6.38 1.15 8.85 1.345 ;
			LAYER M1 ;
			RECT 6.38 1.1 6.695 1.15 ;
			LAYER M1 ;
			RECT 6.38 1.07 6.66 1.1 ;
			LAYER M1 ;
			RECT 8.57 0.42 8.85 1.15 ;
			LAYER M1 ;
			RECT 10.13 0.42 10.41 2.6 ;
			LAYER M1 ;
			RECT 0.0 -0.42 11.16 0.42 ;
		END
	END GND
	PIN q
		DIRECTION output ;
		USE SIGNAL ;
		PORT
			LAYER M1 ;
			RECT 10.72 3.66 11.0 5.13 ;
			LAYER M1 ;
			RECT 10.775 2.98 10.97 3.66 ;
			LAYER M1 ;
			RECT 10.725 2.6 11.01 2.98 ;
			LAYER M1 ;
			RECT 10.72 1.9 11.0 2.6 ;
		END
		AntennaDiffArea 0.91245 ;
	END q
	PIN VDD
		DIRECTION inout ;
		USE POWER ;
		PORT
			LAYER M1 ;
			RECT 0.0 5.78 11.16 6.62 ;
			LAYER M1 ;
			RECT 0.16 3.515 0.44 5.78 ;
			LAYER M1 ;
			RECT 3.2 4.22 3.48 5.78 ;
			LAYER M1 ;
			RECT 4.49 5.085 4.77 5.78 ;
			LAYER M1 ;
			RECT 4.49 4.89 6.665 5.085 ;
			LAYER M1 ;
			RECT 4.49 4.415 4.77 4.89 ;
			LAYER M1 ;
			RECT 6.38 4.605 6.665 4.89 ;
			LAYER M1 ;
			RECT 8.71 4.115 8.99 5.78 ;
			LAYER M1 ;
			RECT 10.13 3.66 10.41 5.78 ;
		END
	END VDD
	PIN clk
		DIRECTION input ;
		USE CLOCK ;
		PORT
			LAYER M1 ;
			RECT 5.625 5.54 5.905 5.575 ;
			LAYER M1 ;
			RECT 5.625 5.345 8.18 5.54 ;
			LAYER M1 ;
			RECT 5.625 5.295 5.905 5.345 ;
			LAYER M1 ;
			RECT 7.895 5.015 8.18 5.345 ;
			LAYER M1 ;
			RECT 3.89 3.565 4.225 3.6 ;
			LAYER M1 ;
			RECT 3.645 3.285 4.225 3.565 ;
			LAYER M1 ;
			RECT 3.89 3.25 4.225 3.285 ;
			LAYER M1 ;
			RECT 4.03 2.94 4.225 3.25 ;
			LAYER M1 ;
			RECT 4.03 2.825 6.19 2.94 ;
			LAYER M1 ;
			RECT 4.03 2.75 6.215 2.825 ;
			LAYER M1 ;
			RECT 5.935 2.545 6.215 2.75 ;
		END
		AntennaGateArea 0.44625 ;
	END clk
	PIN clrb
		DIRECTION input ;
		USE SIGNAL ;
		PORT
			LAYER M1 ;
			RECT 1.36 2.975 1.74 2.98 ;
			LAYER M1 ;
			RECT 1.325 2.695 1.74 2.975 ;
			LAYER M1 ;
			RECT 1.36 2.6 1.74 2.695 ;
			LAYER M1 ;
			RECT 3.935 0.865 4.215 0.91 ;
			LAYER M1 ;
			RECT 8.09 0.865 8.37 0.935 ;
			LAYER M1 ;
			RECT 3.935 0.67 8.37 0.865 ;
			LAYER M1 ;
			RECT 3.935 0.63 4.215 0.67 ;
			LAYER M1 ;
			RECT 8.09 0.655 8.37 0.67 ;
		END
		AntennaGateArea 0.5055 ;
	END clrb
	OBS
		LAYER M1 ;
		RECT 0.75 4.85 1.03 4.985 ;
		LAYER M1 ;
		RECT 1.42 4.85 1.7 5.235 ;
		LAYER M1 ;
		RECT 0.75 4.655 1.7 4.85 ;
		LAYER M1 ;
		RECT 0.75 3.925 1.03 4.655 ;
		LAYER M1 ;
		RECT 1.42 4.535 1.7 4.655 ;
		LAYER M1 ;
		RECT 2.01 4.83 2.29 5.235 ;
		LAYER M1 ;
		RECT 2.01 4.535 2.3 4.83 ;
		LAYER M1 ;
		RECT 2.11 4.23 2.3 4.535 ;
		LAYER M1 ;
		RECT 0.75 3.515 1.065 3.925 ;
		LAYER M1 ;
		RECT 2.11 3.805 2.365 4.23 ;
		LAYER M1 ;
		RECT 2.61 4.22 2.89 5.19 ;
		LAYER M1 ;
		RECT 3.84 4.655 4.12 4.915 ;
		LAYER M1 ;
		RECT 0.805 3.205 1.065 3.515 ;
		LAYER M1 ;
		RECT 0.87 2.355 1.065 3.205 ;
		LAYER M1 ;
		RECT 2.17 2.4 2.365 3.805 ;
		LAYER M1 ;
		RECT 2.64 2.885 2.83 4.22 ;
		LAYER M1 ;
		RECT 3.84 4.01 4.125 4.655 ;
		LAYER M1 ;
		RECT 5.9 4.685 6.18 4.69 ;
		LAYER M1 ;
		RECT 5.46 4.405 6.18 4.685 ;
		LAYER M1 ;
		RECT 7.07 4.445 7.35 4.815 ;
		LAYER M1 ;
		RECT 7.06 4.405 7.35 4.445 ;
		LAYER M1 ;
		RECT 5.46 4.21 7.35 4.405 ;
		LAYER M1 ;
		RECT 5.46 4.015 5.74 4.21 ;
		LAYER M1 ;
		RECT 7.06 4.115 7.35 4.21 ;
		LAYER M1 ;
		RECT 7.66 4.35 7.94 4.815 ;
		LAYER M1 ;
		RECT 7.66 4.115 7.95 4.35 ;
		LAYER M1 ;
		RECT 9.3 4.32 9.58 4.815 ;
		LAYER M1 ;
		RECT 9.3 4.115 9.585 4.32 ;
		LAYER M1 ;
		RECT 3.235 3.815 4.695 4.01 ;
		LAYER M1 ;
		RECT 3.235 3.365 3.425 3.815 ;
		LAYER M1 ;
		RECT 4.5 3.625 4.695 3.815 ;
		LAYER M1 ;
		RECT 5.905 3.625 6.185 3.815 ;
		LAYER M1 ;
		RECT 6.385 3.645 6.665 3.925 ;
		LAYER M1 ;
		RECT 3.04 3.085 3.425 3.365 ;
		LAYER M1 ;
		RECT 4.5 3.535 6.185 3.625 ;
		LAYER M1 ;
		RECT 4.5 3.43 6.18 3.535 ;
		LAYER M1 ;
		RECT 3.235 3.0 3.425 3.085 ;
		LAYER M1 ;
		RECT 2.64 2.675 3.025 2.885 ;
		LAYER M1 ;
		RECT 3.235 2.805 3.755 3.0 ;
		LAYER M1 ;
		RECT 1.61 2.355 1.89 2.4 ;
		LAYER M1 ;
		RECT 0.375 2.16 1.89 2.355 ;
		LAYER M1 ;
		RECT 0.375 1.82 0.57 2.16 ;
		LAYER M1 ;
		RECT 1.61 2.12 1.89 2.16 ;
		LAYER M1 ;
		RECT 2.17 2.12 2.48 2.4 ;
		LAYER M1 ;
		RECT 0.295 1.12 0.575 1.82 ;
		LAYER M1 ;
		RECT 2.17 1.625 2.365 2.12 ;
		LAYER M1 ;
		RECT 2.83 1.85 3.025 2.675 ;
		LAYER M1 ;
		RECT 3.435 2.7 3.755 2.805 ;
		LAYER M1 ;
		RECT 6.425 3.395 6.62 3.645 ;
		LAYER M1 ;
		RECT 6.425 3.115 6.755 3.395 ;
		LAYER M1 ;
		RECT 3.435 2.42 3.8 2.7 ;
		LAYER M1 ;
		RECT 3.435 2.405 3.755 2.42 ;
		LAYER M1 ;
		RECT 6.425 2.31 6.62 3.115 ;
		LAYER M1 ;
		RECT 7.06 2.59 7.255 4.115 ;
		LAYER M1 ;
		RECT 7.755 3.785 7.95 4.115 ;
		LAYER M1 ;
		RECT 7.665 3.59 7.95 3.785 ;
		LAYER M1 ;
		RECT 9.395 3.805 9.585 4.115 ;
		LAYER M1 ;
		RECT 9.395 3.61 9.88 3.805 ;
		LAYER M1 ;
		RECT 7.665 3.355 7.855 3.59 ;
		LAYER M1 ;
		RECT 9.205 3.355 9.485 3.4 ;
		LAYER M1 ;
		RECT 7.665 3.165 9.485 3.355 ;
		LAYER M1 ;
		RECT 7.665 2.59 7.855 3.165 ;
		LAYER M1 ;
		RECT 9.205 3.12 9.485 3.165 ;
		LAYER M1 ;
		RECT 9.685 3.13 9.88 3.61 ;
		LAYER M1 ;
		RECT 10.175 3.13 10.455 3.165 ;
		LAYER M1 ;
		RECT 9.685 2.935 10.455 3.13 ;
		LAYER M1 ;
		RECT 9.685 2.595 9.88 2.935 ;
		LAYER M1 ;
		RECT 10.175 2.885 10.455 2.935 ;
		LAYER M1 ;
		RECT 6.975 2.31 7.255 2.59 ;
		LAYER M1 ;
		RECT 7.565 2.39 7.855 2.59 ;
		LAYER M1 ;
		RECT 7.565 2.31 7.845 2.39 ;
		LAYER M1 ;
		RECT 2.17 1.61 2.54 1.625 ;
		LAYER M1 ;
		RECT 1.52 1.13 1.8 1.57 ;
		LAYER M1 ;
		RECT 2.17 1.435 2.63 1.61 ;
		LAYER M1 ;
		RECT 2.35 1.33 2.63 1.435 ;
		LAYER M1 ;
		RECT 2.83 1.57 3.23 1.85 ;
		LAYER M1 ;
		RECT 4.78 1.83 5.06 2.145 ;
		LAYER M1 ;
		RECT 6.38 2.03 6.66 2.31 ;
		LAYER M1 ;
		RECT 2.83 1.13 3.025 1.57 ;
		LAYER M1 ;
		RECT 1.52 0.94 3.025 1.13 ;
		LAYER M1 ;
		RECT 4.87 1.615 5.06 1.83 ;
		LAYER M1 ;
		RECT 7.04 1.79 7.23 2.31 ;
		LAYER M1 ;
		RECT 5.96 1.615 7.23 1.79 ;
		LAYER M1 ;
		RECT 4.87 1.595 7.23 1.615 ;
		LAYER M1 ;
		RECT 4.87 1.425 6.16 1.595 ;
		LAYER M1 ;
		RECT 5.88 1.265 6.16 1.425 ;
		LAYER M1 ;
		RECT 9.535 2.275 9.88 2.595 ;
		LAYER M1 ;
		RECT 9.535 1.625 9.815 2.275 ;
	END
END MMI_FFCB
MACRO MMI_FFHB
	CLASS CORE ;
	FOREIGN MMI_FFHB 0 0 ;
	SIZE 12.4 BY 6.2 ;
	SYMMETRY X Y ;
	SITE CORE1 ;
	PIN d
		DIRECTION input ;
		USE SIGNAL ;
		PORT
			LAYER M1 ;
			RECT 1.36 2.6 1.74 2.98 ;
		END
		AntennaGateArea 0.3465 ;
	END d
	PIN GND
		DIRECTION inout ;
		USE GROUND ;
		PORT
			LAYER M1 ;
			RECT 0.785 1.0 1.065 1.7 ;
			LAYER M1 ;
			RECT 3.21 1.005 3.49 1.285 ;
			LAYER M1 ;
			RECT 4.875 1.01 5.19 1.29 ;
			LAYER M1 ;
			RECT 0.83 0.42 1.025 1.0 ;
			LAYER M1 ;
			RECT 3.245 0.42 3.44 1.005 ;
			LAYER M1 ;
			RECT 4.9 0.42 5.18 1.01 ;
			LAYER M1 ;
			RECT 6.78 0.42 7.06 1.53 ;
			LAYER M1 ;
			RECT 9.26 0.42 9.54 1.47 ;
			LAYER M1 ;
			RECT 11.265 0.42 11.545 2.575 ;
			LAYER M1 ;
			RECT 0.0 -0.42 12.4 0.42 ;
		END
	END GND
	PIN q
		DIRECTION output ;
		USE SIGNAL ;
		PORT
			LAYER M1 ;
			RECT 11.95 3.515 12.23 4.985 ;
			LAYER M1 ;
			RECT 11.955 2.975 12.23 3.515 ;
			LAYER M1 ;
			RECT 11.86 2.575 12.23 2.975 ;
			LAYER M1 ;
			RECT 11.855 2.24 12.23 2.575 ;
			LAYER M1 ;
			RECT 11.855 1.875 12.135 2.24 ;
		END
		AntennaDiffArea 0.91245 ;
	END q
	PIN VDD
		DIRECTION inout ;
		USE POWER ;
		PORT
			LAYER M1 ;
			RECT 0.0 5.78 12.4 6.62 ;
			LAYER M1 ;
			RECT 0.78 3.845 1.06 5.78 ;
			LAYER M1 ;
			RECT 2.72 4.255 3.0 5.78 ;
			LAYER M1 ;
			RECT 5.04 4.895 5.32 5.78 ;
			LAYER M1 ;
			RECT 6.59 4.92 6.78 5.78 ;
			LAYER M1 ;
			RECT 6.545 4.25 6.825 4.92 ;
			LAYER M1 ;
			RECT 8.95 4.11 9.23 5.78 ;
			LAYER M1 ;
			RECT 11.36 3.515 11.64 5.78 ;
		END
	END VDD
	PIN clk
		DIRECTION input ;
		USE CLOCK ;
		PORT
			LAYER M1 ;
			RECT 6.085 3.37 6.365 3.65 ;
			LAYER M1 ;
			RECT 6.11 2.99 6.3 3.37 ;
			LAYER M1 ;
			RECT 5.58 2.885 6.3 2.99 ;
			LAYER M1 ;
			RECT 5.39 2.625 6.3 2.885 ;
			LAYER M1 ;
			RECT 5.39 2.0 5.58 2.625 ;
			LAYER M1 ;
			RECT 5.39 1.72 5.67 2.0 ;
		END
		AntennaGateArea 0.44625 ;
	END clk
	PIN hold
		DIRECTION input ;
		USE SIGNAL ;
		PORT
			LAYER M1 ;
			RECT 0.795 3.38 3.18 3.575 ;
			LAYER M1 ;
			RECT 0.795 3.295 1.255 3.38 ;
			LAYER M1 ;
			RECT 0.795 2.98 0.99 3.295 ;
			LAYER M1 ;
			RECT 0.735 2.925 1.11 2.98 ;
			LAYER M1 ;
			RECT 0.555 2.645 1.11 2.925 ;
			LAYER M1 ;
			RECT 0.735 2.6 1.11 2.645 ;
			LAYER M1 ;
			RECT 2.99 2.18 3.18 3.38 ;
			LAYER M1 ;
			RECT 2.915 1.9 3.195 2.18 ;
		END
		AntennaGateArea 0.51975 ;
	END hold
	OBS
		LAYER M1 ;
		RECT 0.15 4.365 0.43 4.545 ;
		LAYER M1 ;
		RECT 0.13 3.845 0.43 4.365 ;
		LAYER M1 ;
		RECT 1.755 4.055 2.035 4.91 ;
		LAYER M1 ;
		RECT 3.405 4.59 3.685 5.29 ;
		LAYER M1 ;
		RECT 3.995 4.59 4.275 5.29 ;
		LAYER M1 ;
		RECT 6.08 5.34 6.36 5.43 ;
		LAYER M1 ;
		RECT 5.64 5.15 6.36 5.34 ;
		LAYER M1 ;
		RECT 5.64 4.695 5.92 5.15 ;
		LAYER M1 ;
		RECT 7.965 5.485 8.245 5.575 ;
		LAYER M1 ;
		RECT 7.965 5.295 8.485 5.485 ;
		LAYER M1 ;
		RECT 5.0 4.59 5.92 4.695 ;
		LAYER M1 ;
		RECT 3.405 4.055 3.595 4.59 ;
		LAYER M1 ;
		RECT 1.755 3.865 3.595 4.055 ;
		LAYER M1 ;
		RECT 1.755 3.85 2.035 3.865 ;
		LAYER M1 ;
		RECT 0.13 2.155 0.325 3.845 ;
		LAYER M1 ;
		RECT 1.95 2.845 2.23 3.125 ;
		LAYER M1 ;
		RECT 0.99 2.155 1.27 2.195 ;
		LAYER M1 ;
		RECT 1.96 2.155 2.155 2.845 ;
		LAYER M1 ;
		RECT 0.13 1.96 2.155 2.155 ;
		LAYER M1 ;
		RECT 0.13 1.7 0.325 1.96 ;
		LAYER M1 ;
		RECT 0.99 1.915 1.27 1.96 ;
		LAYER M1 ;
		RECT 3.405 1.915 3.595 3.865 ;
		LAYER M1 ;
		RECT 4.02 2.725 4.21 4.59 ;
		LAYER M1 ;
		RECT 5.0 4.505 5.88 4.59 ;
		LAYER M1 ;
		RECT 5.0 3.695 5.19 4.505 ;
		LAYER M1 ;
		RECT 7.155 4.495 7.435 4.92 ;
		LAYER M1 ;
		RECT 7.15 4.22 7.435 4.495 ;
		LAYER M1 ;
		RECT 7.745 4.22 8.025 4.92 ;
		LAYER M1 ;
		RECT 5.51 4.05 5.79 4.065 ;
		LAYER M1 ;
		RECT 7.15 4.05 7.43 4.22 ;
		LAYER M1 ;
		RECT 5.51 3.855 7.43 4.05 ;
		LAYER M1 ;
		RECT 5.51 3.785 5.79 3.855 ;
		LAYER M1 ;
		RECT 4.94 3.415 5.22 3.695 ;
		LAYER M1 ;
		RECT 4.5 2.725 4.78 2.74 ;
		LAYER M1 ;
		RECT 3.865 2.535 4.78 2.725 ;
		LAYER M1 ;
		RECT 3.865 2.3 4.15 2.535 ;
		LAYER M1 ;
		RECT 4.5 2.46 4.78 2.535 ;
		LAYER M1 ;
		RECT 3.87 2.255 4.15 2.3 ;
		LAYER M1 ;
		RECT 4.365 2.05 4.645 2.14 ;
		LAYER M1 ;
		RECT 5.0 2.05 5.19 3.415 ;
		LAYER M1 ;
		RECT 6.595 3.37 7.03 3.65 ;
		LAYER M1 ;
		RECT 3.87 1.915 4.15 1.945 ;
		LAYER M1 ;
		RECT 3.405 1.72 4.15 1.915 ;
		LAYER M1 ;
		RECT 3.405 1.7 3.595 1.72 ;
		LAYER M1 ;
		RECT 0.13 1.47 0.43 1.7 ;
		LAYER M1 ;
		RECT 0.15 1.385 0.43 1.47 ;
		LAYER M1 ;
		RECT 1.75 1.51 3.595 1.7 ;
		LAYER M1 ;
		RECT 3.87 1.665 4.15 1.72 ;
		LAYER M1 ;
		RECT 4.365 1.855 5.19 2.05 ;
		LAYER M1 ;
		RECT 1.76 1.0 2.04 1.51 ;
		LAYER M1 ;
		RECT 4.365 0.905 4.56 1.855 ;
		LAYER M1 ;
		RECT 4.875 1.6 5.19 1.855 ;
		LAYER M1 ;
		RECT 6.595 2.415 6.79 3.37 ;
		LAYER M1 ;
		RECT 5.875 2.22 6.79 2.415 ;
		LAYER M1 ;
		RECT 5.875 2.1 6.24 2.22 ;
		LAYER M1 ;
		RECT 5.875 1.495 6.07 2.1 ;
		LAYER M1 ;
		RECT 6.545 1.975 6.825 2.01 ;
		LAYER M1 ;
		RECT 7.24 1.975 7.43 3.855 ;
		LAYER M1 ;
		RECT 7.835 3.33 8.025 4.22 ;
		LAYER M1 ;
		RECT 8.29 4.81 8.485 5.295 ;
		LAYER M1 ;
		RECT 8.29 4.11 8.64 4.81 ;
		LAYER M1 ;
		RECT 9.54 4.3 9.82 4.81 ;
		LAYER M1 ;
		RECT 9.54 4.11 10.8 4.3 ;
		LAYER M1 ;
		RECT 7.755 3.05 8.035 3.33 ;
		LAYER M1 ;
		RECT 6.545 1.93 7.435 1.975 ;
		LAYER M1 ;
		RECT 7.835 1.94 8.025 3.05 ;
		LAYER M1 ;
		RECT 8.29 2.485 8.485 4.11 ;
		LAYER M1 ;
		RECT 9.545 4.105 10.8 4.11 ;
		LAYER M1 ;
		RECT 8.74 3.87 9.02 3.9 ;
		LAYER M1 ;
		RECT 9.545 3.87 9.74 4.105 ;
		LAYER M1 ;
		RECT 8.74 3.68 9.74 3.87 ;
		LAYER M1 ;
		RECT 8.74 3.62 9.02 3.68 ;
		LAYER M1 ;
		RECT 10.08 3.515 10.36 3.795 ;
		LAYER M1 ;
		RECT 8.69 3.28 8.97 3.325 ;
		LAYER M1 ;
		RECT 10.1 3.28 10.29 3.515 ;
		LAYER M1 ;
		RECT 8.69 3.085 10.29 3.28 ;
		LAYER M1 ;
		RECT 8.69 3.045 8.97 3.085 ;
		LAYER M1 ;
		RECT 8.29 2.29 8.805 2.485 ;
		LAYER M1 ;
		RECT 10.1 2.35 10.29 3.085 ;
		LAYER M1 ;
		RECT 10.605 3.045 10.8 4.105 ;
		LAYER M1 ;
		RECT 11.155 3.045 11.435 3.09 ;
		LAYER M1 ;
		RECT 10.605 2.855 11.435 3.045 ;
		LAYER M1 ;
		RECT 6.545 1.78 7.565 1.93 ;
		LAYER M1 ;
		RECT 6.545 1.73 6.825 1.78 ;
		LAYER M1 ;
		RECT 7.24 1.74 7.565 1.78 ;
		LAYER M1 ;
		RECT 7.835 1.745 8.205 1.94 ;
		LAYER M1 ;
		RECT 7.375 1.53 7.565 1.74 ;
		LAYER M1 ;
		RECT 8.01 1.54 8.205 1.745 ;
		LAYER M1 ;
		RECT 5.78 1.215 6.07 1.495 ;
		LAYER M1 ;
		RECT 4.365 0.625 4.67 0.905 ;
		LAYER M1 ;
		RECT 7.37 1.215 7.65 1.53 ;
		LAYER M1 ;
		RECT 8.005 1.26 8.285 1.54 ;
		LAYER M1 ;
		RECT 8.615 1.47 8.805 2.29 ;
		LAYER M1 ;
		RECT 9.82 2.26 10.29 2.35 ;
		LAYER M1 ;
		RECT 9.82 2.155 10.47 2.26 ;
		LAYER M1 ;
		RECT 9.82 2.07 10.545 2.155 ;
		LAYER M1 ;
		RECT 9.02 1.86 9.3 1.95 ;
		LAYER M1 ;
		RECT 10.265 1.875 10.545 2.07 ;
		LAYER M1 ;
		RECT 9.02 1.67 10.05 1.86 ;
		LAYER M1 ;
		RECT 9.855 1.51 10.05 1.67 ;
		LAYER M1 ;
		RECT 10.745 1.51 10.935 2.855 ;
		LAYER M1 ;
		RECT 11.155 2.81 11.435 2.855 ;
		LAYER M1 ;
		RECT 9.855 1.47 10.935 1.51 ;
		LAYER M1 ;
		RECT 8.615 1.26 8.905 1.47 ;
		LAYER M1 ;
		RECT 8.625 1.155 8.905 1.26 ;
		LAYER M1 ;
		RECT 9.85 1.315 10.935 1.47 ;
		LAYER M1 ;
		RECT 9.85 1.02 10.13 1.315 ;
	END
END MMI_FFHB
MACRO MMI_FFMB
	CLASS CORE ;
	FOREIGN MMI_FFMB 0 0 ;
	SIZE 11.78 BY 6.2 ;
	SYMMETRY X Y ;
	SITE CORE1 ;
	PIN d0
		DIRECTION input ;
		USE SIGNAL ;
		PORT
			LAYER M1 ;
			RECT 1.36 2.6 1.74 2.98 ;
		END
		AntennaGateArea 0.3465 ;
	END d0
	PIN sel
		DIRECTION input ;
		USE SIGNAL ;
		PORT
			LAYER M1 ;
			RECT 1.2 3.575 1.48 3.59 ;
			LAYER M1 ;
			RECT 0.815 3.38 3.42 3.575 ;
			LAYER M1 ;
			RECT 0.815 3.31 1.48 3.38 ;
			LAYER M1 ;
			RECT 0.815 2.98 1.005 3.31 ;
			LAYER M1 ;
			RECT 0.735 2.6 1.11 2.98 ;
			LAYER M1 ;
			RECT 3.225 2.275 3.42 3.38 ;
			LAYER M1 ;
			RECT 3.135 2.04 3.42 2.275 ;
			LAYER M1 ;
			RECT 3.135 1.995 3.415 2.04 ;
		END
		AntennaGateArea 0.51975 ;
	END sel
	PIN GND
		DIRECTION inout ;
		USE GROUND ;
		PORT
			LAYER M1 ;
			RECT 10.75 1.925 11.03 2.325 ;
			LAYER M1 ;
			RECT 1.005 1.635 1.285 1.825 ;
			LAYER M1 ;
			RECT 1.005 1.125 1.29 1.635 ;
			LAYER M1 ;
			RECT 3.43 1.125 3.71 1.405 ;
			LAYER M1 ;
			RECT 1.1 0.42 1.29 1.125 ;
			LAYER M1 ;
			RECT 3.52 0.42 3.71 1.125 ;
			LAYER M1 ;
			RECT 4.655 0.425 4.935 1.79 ;
			LAYER M1 ;
			RECT 4.595 0.42 4.935 0.425 ;
			LAYER M1 ;
			RECT 7.185 0.42 7.465 1.76 ;
			LAYER M1 ;
			RECT 9.15 0.81 9.6 1.09 ;
			LAYER M1 ;
			RECT 9.235 0.42 9.515 0.81 ;
			LAYER M1 ;
			RECT 10.745 0.42 11.03 1.925 ;
			LAYER M1 ;
			RECT 0.0 -0.42 11.78 0.42 ;
		END
	END GND
	PIN q
		DIRECTION output ;
		USE SIGNAL ;
		PORT
			LAYER M1 ;
			RECT 11.34 4.04 11.62 5.225 ;
			LAYER M1 ;
			RECT 11.34 2.145 11.625 4.04 ;
			LAYER M1 ;
			RECT 11.34 1.625 11.62 2.145 ;
		END
		AntennaDiffArea 0.91245 ;
	END q
	PIN d1
		DIRECTION input ;
		USE SIGNAL ;
		PORT
			LAYER M1 ;
			RECT 1.98 2.92 2.36 2.98 ;
			LAYER M1 ;
			RECT 1.98 2.64 2.42 2.92 ;
			LAYER M1 ;
			RECT 1.98 2.6 2.36 2.64 ;
		END
		AntennaGateArea 0.3465 ;
	END d1
	PIN VDD
		DIRECTION inout ;
		USE POWER ;
		PORT
			LAYER M1 ;
			RECT 0.0 5.78 11.78 6.62 ;
			LAYER M1 ;
			RECT 1.005 3.845 1.285 5.78 ;
			LAYER M1 ;
			RECT 2.945 4.255 3.225 5.78 ;
			LAYER M1 ;
			RECT 5.25 5.04 5.53 5.78 ;
			LAYER M1 ;
			RECT 6.78 4.28 7.06 5.78 ;
			LAYER M1 ;
			RECT 8.565 3.755 8.845 5.78 ;
			LAYER M1 ;
			RECT 10.75 3.755 11.03 5.78 ;
		END
	END VDD
	PIN clk
		DIRECTION input ;
		USE CLOCK ;
		PORT
			LAYER M1 ;
			RECT 6.3 3.595 6.58 3.675 ;
			LAYER M1 ;
			RECT 5.705 3.4 6.58 3.595 ;
			LAYER M1 ;
			RECT 5.705 3.22 6.08 3.4 ;
			LAYER M1 ;
			RECT 6.3 3.395 6.58 3.4 ;
			LAYER M1 ;
			RECT 5.795 2.235 5.99 3.22 ;
			LAYER M1 ;
			RECT 7.975 2.91 8.255 2.97 ;
			LAYER M1 ;
			RECT 9.21 2.91 9.49 2.975 ;
			LAYER M1 ;
			RECT 7.975 2.72 9.49 2.91 ;
			LAYER M1 ;
			RECT 7.975 2.69 8.255 2.72 ;
			LAYER M1 ;
			RECT 9.21 2.695 9.49 2.72 ;
			LAYER M1 ;
			RECT 5.735 1.955 6.015 2.235 ;
		END
		AntennaGateArea 0.44625 ;
	END clk
	OBS
		LAYER M1 ;
		RECT 0.34 3.845 0.62 4.545 ;
		LAYER M1 ;
		RECT 1.97 4.08 2.25 4.91 ;
		LAYER M1 ;
		RECT 3.62 4.62 3.9 5.32 ;
		LAYER M1 ;
		RECT 4.21 4.62 4.49 5.32 ;
		LAYER M1 ;
		RECT 6.29 5.32 6.57 5.395 ;
		LAYER M1 ;
		RECT 5.855 5.115 6.57 5.32 ;
		LAYER M1 ;
		RECT 5.855 4.81 6.135 5.115 ;
		LAYER M1 ;
		RECT 5.205 4.62 6.135 4.81 ;
		LAYER M1 ;
		RECT 1.97 4.055 2.255 4.08 ;
		LAYER M1 ;
		RECT 3.62 4.055 3.81 4.62 ;
		LAYER M1 ;
		RECT 4.25 4.38 4.44 4.62 ;
		LAYER M1 ;
		RECT 1.97 3.865 3.81 4.055 ;
		LAYER M1 ;
		RECT 1.97 3.85 2.25 3.865 ;
		LAYER M1 ;
		RECT 0.345 2.28 0.535 3.845 ;
		LAYER M1 ;
		RECT 2.735 2.89 3.015 2.91 ;
		LAYER M1 ;
		RECT 2.705 2.63 3.015 2.89 ;
		LAYER M1 ;
		RECT 1.2 2.28 1.48 2.345 ;
		LAYER M1 ;
		RECT 2.705 2.28 2.895 2.63 ;
		LAYER M1 ;
		RECT 0.345 2.085 2.895 2.28 ;
		LAYER M1 ;
		RECT 0.345 1.825 0.535 2.085 ;
		LAYER M1 ;
		RECT 1.2 2.065 1.48 2.085 ;
		LAYER M1 ;
		RECT 3.62 2.04 3.81 3.865 ;
		LAYER M1 ;
		RECT 4.025 4.185 4.44 4.38 ;
		LAYER M1 ;
		RECT 4.025 2.63 4.22 4.185 ;
		LAYER M1 ;
		RECT 4.455 3.595 4.735 3.64 ;
		LAYER M1 ;
		RECT 5.205 3.595 5.395 4.62 ;
		LAYER M1 ;
		RECT 7.375 4.255 7.655 4.955 ;
		LAYER M1 ;
		RECT 7.965 4.255 8.245 4.955 ;
		LAYER M1 ;
		RECT 5.725 4.075 6.005 4.08 ;
		LAYER M1 ;
		RECT 7.375 4.075 7.645 4.255 ;
		LAYER M1 ;
		RECT 5.725 3.88 7.645 4.075 ;
		LAYER M1 ;
		RECT 5.725 3.8 6.005 3.88 ;
		LAYER M1 ;
		RECT 4.455 3.4 5.395 3.595 ;
		LAYER M1 ;
		RECT 4.455 3.36 4.735 3.4 ;
		LAYER M1 ;
		RECT 5.205 3.02 5.395 3.4 ;
		LAYER M1 ;
		RECT 6.815 3.4 7.235 3.68 ;
		LAYER M1 ;
		RECT 5.205 2.83 5.515 3.02 ;
		LAYER M1 ;
		RECT 4.02 2.595 4.3 2.63 ;
		LAYER M1 ;
		RECT 4.83 2.595 5.11 2.61 ;
		LAYER M1 ;
		RECT 4.02 2.35 5.115 2.595 ;
		LAYER M1 ;
		RECT 4.83 2.33 5.11 2.35 ;
		LAYER M1 ;
		RECT 3.62 1.85 4.3 2.04 ;
		LAYER M1 ;
		RECT 0.34 1.51 0.62 1.825 ;
		LAYER M1 ;
		RECT 1.965 1.795 2.245 1.825 ;
		LAYER M1 ;
		RECT 3.62 1.795 3.81 1.85 ;
		LAYER M1 ;
		RECT 1.965 1.605 3.81 1.795 ;
		LAYER M1 ;
		RECT 4.02 1.76 4.3 1.85 ;
		LAYER M1 ;
		RECT 5.32 1.79 5.515 2.83 ;
		LAYER M1 ;
		RECT 6.815 2.73 7.005 3.4 ;
		LAYER M1 ;
		RECT 6.27 2.535 7.005 2.73 ;
		LAYER M1 ;
		RECT 6.27 2.325 6.585 2.535 ;
		LAYER M1 ;
		RECT 1.965 1.125 2.245 1.605 ;
		LAYER M1 ;
		RECT 5.245 1.475 5.525 1.79 ;
		LAYER M1 ;
		RECT 6.27 1.755 6.465 2.325 ;
		LAYER M1 ;
		RECT 6.945 2.155 7.225 2.24 ;
		LAYER M1 ;
		RECT 7.44 2.155 7.635 3.88 ;
		LAYER M1 ;
		RECT 8.05 3.55 8.245 4.255 ;
		LAYER M1 ;
		RECT 9.155 4.26 10.47 4.455 ;
		LAYER M1 ;
		RECT 9.155 3.755 9.435 4.26 ;
		LAYER M1 ;
		RECT 9.705 4.035 9.99 4.04 ;
		LAYER M1 ;
		RECT 9.705 3.755 10.025 4.035 ;
		LAYER M1 ;
		RECT 9.705 3.55 9.99 3.755 ;
		LAYER M1 ;
		RECT 8.05 3.355 9.99 3.55 ;
		LAYER M1 ;
		RECT 8.61 3.265 9.04 3.355 ;
		LAYER M1 ;
		RECT 9.705 2.32 9.99 3.355 ;
		LAYER M1 ;
		RECT 10.28 3.24 10.47 4.26 ;
		LAYER M1 ;
		RECT 10.28 3.235 10.805 3.24 ;
		LAYER M1 ;
		RECT 10.28 2.955 10.94 3.235 ;
		LAYER M1 ;
		RECT 8.66 2.275 8.94 2.3 ;
		LAYER M1 ;
		RECT 9.705 2.275 9.995 2.32 ;
		LAYER M1 ;
		RECT 6.945 1.96 7.975 2.155 ;
		LAYER M1 ;
		RECT 7.78 1.76 7.975 1.96 ;
		LAYER M1 ;
		RECT 8.47 2.08 9.995 2.275 ;
		LAYER M1 ;
		RECT 8.47 2.02 8.94 2.08 ;
		LAYER M1 ;
		RECT 9.715 2.04 9.995 2.08 ;
		LAYER M1 ;
		RECT 8.47 1.76 8.66 2.02 ;
		LAYER M1 ;
		RECT 6.18 1.48 6.465 1.755 ;
		LAYER M1 ;
		RECT 6.18 1.475 6.46 1.48 ;
		LAYER M1 ;
		RECT 5.32 0.86 5.515 1.475 ;
		LAYER M1 ;
		RECT 6.68 0.86 6.96 0.9 ;
		LAYER M1 ;
		RECT 5.32 0.665 6.96 0.86 ;
		LAYER M1 ;
		RECT 6.68 0.62 6.96 0.665 ;
		LAYER M1 ;
		RECT 7.775 1.445 8.055 1.76 ;
		LAYER M1 ;
		RECT 8.415 1.48 8.695 1.76 ;
		LAYER M1 ;
		RECT 10.28 1.685 10.47 2.955 ;
		LAYER M1 ;
		RECT 9.38 1.68 10.47 1.685 ;
		LAYER M1 ;
		RECT 9.15 1.49 10.47 1.68 ;
		LAYER M1 ;
		RECT 9.15 1.4 9.6 1.49 ;
	END
END MMI_FFMB
MACRO MMI_FFNCB
	CLASS CORE ;
	FOREIGN MMI_FFNCB 0 0 ;
	SIZE 11.16 BY 6.2 ;
	SYMMETRY X Y ;
	SITE CORE1 ;
	PIN d
		DIRECTION input ;
		USE SIGNAL ;
		PORT
			LAYER M1 ;
			RECT 0.12 2.925 0.5 2.98 ;
			LAYER M1 ;
			RECT 0.12 2.645 0.635 2.925 ;
			LAYER M1 ;
			RECT 0.12 2.6 0.5 2.645 ;
		END
		AntennaGateArea 0.3465 ;
	END d
	PIN GND
		DIRECTION inout ;
		USE GROUND ;
		PORT
			LAYER M1 ;
			RECT 4.275 2.345 5.65 2.535 ;
			LAYER M1 ;
			RECT 4.275 2.145 4.465 2.345 ;
			LAYER M1 ;
			RECT 5.455 2.145 5.65 2.345 ;
			LAYER M1 ;
			RECT 8.57 2.24 8.85 2.595 ;
			LAYER M1 ;
			RECT 4.19 2.11 4.47 2.145 ;
			LAYER M1 ;
			RECT 3.45 2.08 3.73 2.085 ;
			LAYER M1 ;
			RECT 4.18 2.08 4.47 2.11 ;
			LAYER M1 ;
			RECT 3.45 1.83 4.47 2.08 ;
			LAYER M1 ;
			RECT 5.455 2.01 5.74 2.145 ;
			LAYER M1 ;
			RECT 5.46 1.83 5.74 2.01 ;
			LAYER M1 ;
			RECT 8.57 1.955 8.86 2.24 ;
			LAYER M1 ;
			RECT 0.885 0.42 1.165 1.82 ;
			LAYER M1 ;
			RECT 3.45 1.795 4.465 1.83 ;
			LAYER M1 ;
			RECT 3.45 0.42 3.73 1.795 ;
			LAYER M1 ;
			RECT 6.385 1.345 6.665 1.35 ;
			LAYER M1 ;
			RECT 8.57 1.345 8.85 1.955 ;
			LAYER M1 ;
			RECT 6.385 1.15 8.85 1.345 ;
			LAYER M1 ;
			RECT 6.385 1.07 6.665 1.15 ;
			LAYER M1 ;
			RECT 8.57 0.42 8.85 1.15 ;
			LAYER M1 ;
			RECT 10.135 0.42 10.415 2.6 ;
			LAYER M1 ;
			RECT 0.0 -0.42 11.16 0.42 ;
		END
	END GND
	PIN q
		DIRECTION output ;
		USE SIGNAL ;
		PORT
			LAYER M1 ;
			RECT 10.725 3.66 11.005 5.13 ;
			LAYER M1 ;
			RECT 10.775 2.99 10.97 3.66 ;
			LAYER M1 ;
			RECT 10.66 2.61 11.04 2.99 ;
			LAYER M1 ;
			RECT 10.725 1.9 11.005 2.61 ;
		END
		AntennaDiffArea 0.91245 ;
	END q
	PIN VDD
		DIRECTION inout ;
		USE POWER ;
		PORT
			LAYER M1 ;
			RECT 0.0 5.78 11.16 6.62 ;
			LAYER M1 ;
			RECT 0.16 3.515 0.44 5.78 ;
			LAYER M1 ;
			RECT 3.2 4.205 3.48 5.78 ;
			LAYER M1 ;
			RECT 4.5 5.085 4.78 5.78 ;
			LAYER M1 ;
			RECT 4.5 4.89 6.67 5.085 ;
			LAYER M1 ;
			RECT 4.5 4.025 4.78 4.89 ;
			LAYER M1 ;
			RECT 6.385 4.635 6.67 4.89 ;
			LAYER M1 ;
			RECT 6.385 4.61 6.665 4.635 ;
			LAYER M1 ;
			RECT 8.71 4.115 8.99 5.78 ;
			LAYER M1 ;
			RECT 10.135 3.66 10.415 5.78 ;
		END
	END VDD
	PIN clk
		DIRECTION input ;
		USE CLOCK ;
		PORT
			LAYER M1 ;
			RECT 5.905 3.61 6.185 3.815 ;
			LAYER M1 ;
			RECT 3.84 3.565 6.185 3.61 ;
			LAYER M1 ;
			RECT 3.61 3.535 6.185 3.565 ;
			LAYER M1 ;
			RECT 3.61 3.42 6.18 3.535 ;
			LAYER M1 ;
			RECT 3.61 3.285 4.22 3.42 ;
			LAYER M1 ;
			RECT 3.84 3.23 4.22 3.285 ;
		END
		AntennaGateArea 0.44625 ;
	END clk
	PIN clrb
		DIRECTION input ;
		USE SIGNAL ;
		PORT
			LAYER M1 ;
			RECT 1.36 2.975 1.74 2.98 ;
			LAYER M1 ;
			RECT 1.325 2.695 1.74 2.975 ;
			LAYER M1 ;
			RECT 1.36 2.6 1.74 2.695 ;
			LAYER M1 ;
			RECT 3.935 0.87 4.215 0.9 ;
			LAYER M1 ;
			RECT 8.09 0.87 8.37 0.935 ;
			LAYER M1 ;
			RECT 3.935 0.675 8.37 0.87 ;
			LAYER M1 ;
			RECT 3.935 0.62 4.215 0.675 ;
			LAYER M1 ;
			RECT 8.09 0.655 8.37 0.675 ;
		END
		AntennaGateArea 0.498 ;
	END clrb
	OBS
		LAYER M1 ;
		RECT 0.75 4.85 1.03 4.985 ;
		LAYER M1 ;
		RECT 1.42 4.85 1.7 5.235 ;
		LAYER M1 ;
		RECT 0.75 4.655 1.7 4.85 ;
		LAYER M1 ;
		RECT 0.75 3.925 1.03 4.655 ;
		LAYER M1 ;
		RECT 1.42 4.535 1.7 4.655 ;
		LAYER M1 ;
		RECT 2.01 4.83 2.29 5.235 ;
		LAYER M1 ;
		RECT 2.01 4.535 2.3 4.83 ;
		LAYER M1 ;
		RECT 2.11 4.23 2.3 4.535 ;
		LAYER M1 ;
		RECT 0.75 3.515 1.065 3.925 ;
		LAYER M1 ;
		RECT 2.11 3.805 2.365 4.23 ;
		LAYER M1 ;
		RECT 2.61 4.205 2.89 5.14 ;
		LAYER M1 ;
		RECT 4.015 5.315 4.295 5.34 ;
		LAYER M1 ;
		RECT 3.93 5.06 4.295 5.315 ;
		LAYER M1 ;
		RECT 5.635 5.54 5.915 5.575 ;
		LAYER M1 ;
		RECT 5.635 5.345 8.185 5.54 ;
		LAYER M1 ;
		RECT 5.635 5.295 5.915 5.345 ;
		LAYER M1 ;
		RECT 3.93 4.9 4.12 5.06 ;
		LAYER M1 ;
		RECT 0.805 3.205 1.065 3.515 ;
		LAYER M1 ;
		RECT 0.87 2.36 1.065 3.205 ;
		LAYER M1 ;
		RECT 2.17 2.395 2.365 3.805 ;
		LAYER M1 ;
		RECT 2.695 3.29 2.885 4.205 ;
		LAYER M1 ;
		RECT 3.84 4.005 4.12 4.9 ;
		LAYER M1 ;
		RECT 7.9 5.015 8.185 5.345 ;
		LAYER M1 ;
		RECT 5.585 4.685 6.185 4.69 ;
		LAYER M1 ;
		RECT 5.46 4.41 6.185 4.685 ;
		LAYER M1 ;
		RECT 7.07 4.445 7.35 4.815 ;
		LAYER M1 ;
		RECT 7.06 4.41 7.35 4.445 ;
		LAYER M1 ;
		RECT 5.46 4.215 7.35 4.41 ;
		LAYER M1 ;
		RECT 5.46 4.015 5.74 4.215 ;
		LAYER M1 ;
		RECT 7.06 4.115 7.35 4.215 ;
		LAYER M1 ;
		RECT 7.66 4.35 7.94 4.815 ;
		LAYER M1 ;
		RECT 7.66 4.115 7.95 4.35 ;
		LAYER M1 ;
		RECT 9.3 4.32 9.58 4.815 ;
		LAYER M1 ;
		RECT 9.3 4.115 9.585 4.32 ;
		LAYER M1 ;
		RECT 3.22 3.81 4.12 4.005 ;
		LAYER M1 ;
		RECT 2.695 2.94 3.02 3.29 ;
		LAYER M1 ;
		RECT 1.61 2.36 1.89 2.395 ;
		LAYER M1 ;
		RECT 0.375 2.165 1.89 2.36 ;
		LAYER M1 ;
		RECT 0.375 1.82 0.57 2.165 ;
		LAYER M1 ;
		RECT 1.61 2.115 1.89 2.165 ;
		LAYER M1 ;
		RECT 2.17 2.115 2.48 2.395 ;
		LAYER M1 ;
		RECT 0.295 1.12 0.575 1.82 ;
		LAYER M1 ;
		RECT 2.17 1.625 2.365 2.115 ;
		LAYER M1 ;
		RECT 2.825 1.84 3.02 2.94 ;
		LAYER M1 ;
		RECT 3.22 3.0 3.41 3.81 ;
		LAYER M1 ;
		RECT 6.385 3.645 6.665 3.925 ;
		LAYER M1 ;
		RECT 6.425 3.405 6.62 3.645 ;
		LAYER M1 ;
		RECT 6.425 3.125 6.765 3.405 ;
		LAYER M1 ;
		RECT 3.22 2.835 6.19 3.0 ;
		LAYER M1 ;
		RECT 3.22 2.805 6.215 2.835 ;
		LAYER M1 ;
		RECT 3.485 2.445 3.805 2.805 ;
		LAYER M1 ;
		RECT 5.935 2.555 6.215 2.805 ;
		LAYER M1 ;
		RECT 3.49 2.39 3.805 2.445 ;
		LAYER M1 ;
		RECT 6.425 2.32 6.62 3.125 ;
		LAYER M1 ;
		RECT 7.06 2.59 7.255 4.115 ;
		LAYER M1 ;
		RECT 7.755 3.785 7.95 4.115 ;
		LAYER M1 ;
		RECT 7.665 3.59 7.95 3.785 ;
		LAYER M1 ;
		RECT 9.395 3.805 9.585 4.115 ;
		LAYER M1 ;
		RECT 9.395 3.61 9.885 3.805 ;
		LAYER M1 ;
		RECT 7.665 3.355 7.855 3.59 ;
		LAYER M1 ;
		RECT 9.215 3.355 9.495 3.4 ;
		LAYER M1 ;
		RECT 7.665 3.165 9.495 3.355 ;
		LAYER M1 ;
		RECT 7.665 2.59 7.855 3.165 ;
		LAYER M1 ;
		RECT 9.215 3.12 9.495 3.165 ;
		LAYER M1 ;
		RECT 9.695 3.13 9.885 3.61 ;
		LAYER M1 ;
		RECT 10.18 3.13 10.46 3.165 ;
		LAYER M1 ;
		RECT 9.695 2.935 10.46 3.13 ;
		LAYER M1 ;
		RECT 9.695 2.595 9.885 2.935 ;
		LAYER M1 ;
		RECT 10.18 2.885 10.46 2.935 ;
		LAYER M1 ;
		RECT 2.17 1.605 2.54 1.625 ;
		LAYER M1 ;
		RECT 1.52 1.12 1.8 1.555 ;
		LAYER M1 ;
		RECT 2.17 1.435 2.625 1.605 ;
		LAYER M1 ;
		RECT 2.345 1.325 2.625 1.435 ;
		LAYER M1 ;
		RECT 2.825 1.56 3.23 1.84 ;
		LAYER M1 ;
		RECT 4.78 2.02 5.06 2.145 ;
		LAYER M1 ;
		RECT 4.78 1.83 5.065 2.02 ;
		LAYER M1 ;
		RECT 6.385 2.04 6.665 2.32 ;
		LAYER M1 ;
		RECT 6.975 2.31 7.255 2.59 ;
		LAYER M1 ;
		RECT 7.565 2.39 7.855 2.59 ;
		LAYER M1 ;
		RECT 7.565 2.31 7.845 2.39 ;
		LAYER M1 ;
		RECT 2.825 1.12 3.02 1.56 ;
		LAYER M1 ;
		RECT 1.525 0.93 3.02 1.12 ;
		LAYER M1 ;
		RECT 4.875 1.595 5.065 1.83 ;
		LAYER M1 ;
		RECT 7.04 1.785 7.23 2.31 ;
		LAYER M1 ;
		RECT 5.955 1.595 7.23 1.785 ;
		LAYER M1 ;
		RECT 4.875 1.59 7.23 1.595 ;
		LAYER M1 ;
		RECT 9.545 2.275 9.885 2.595 ;
		LAYER M1 ;
		RECT 4.875 1.405 6.145 1.59 ;
		LAYER M1 ;
		RECT 5.865 1.265 6.145 1.405 ;
		LAYER M1 ;
		RECT 9.545 1.625 9.825 2.275 ;
	END
END MMI_FFNCB
MACRO MMI_FFSB
	CLASS CORE ;
	FOREIGN MMI_FFSB 0 0 ;
	SIZE 10.54 BY 6.2 ;
	SYMMETRY X Y ;
	SITE CORE1 ;
	PIN d
		DIRECTION input ;
		USE SIGNAL ;
		PORT
			LAYER M1 ;
			RECT 0.16 2.9 0.535 2.98 ;
			LAYER M1 ;
			RECT 0.16 2.62 0.76 2.9 ;
			LAYER M1 ;
			RECT 0.16 2.6 0.535 2.62 ;
		END
		AntennaGateArea 0.3465 ;
	END d
	PIN GND
		DIRECTION inout ;
		USE GROUND ;
		PORT
			LAYER M1 ;
			RECT 0.36 1.65 0.64 2.35 ;
			LAYER M1 ;
			RECT 4.165 1.905 4.455 2.605 ;
			LAYER M1 ;
			RECT 4.26 1.82 4.455 1.905 ;
			LAYER M1 ;
			RECT 0.395 0.42 0.585 1.65 ;
			LAYER M1 ;
			RECT 4.26 1.625 5.13 1.82 ;
			LAYER M1 ;
			RECT 7.175 1.74 7.455 2.02 ;
			LAYER M1 ;
			RECT 4.935 1.43 5.13 1.625 ;
			LAYER M1 ;
			RECT 1.025 0.42 1.305 1.315 ;
			LAYER M1 ;
			RECT 4.935 0.995 5.23 1.43 ;
			LAYER M1 ;
			RECT 4.935 0.42 5.215 0.995 ;
			LAYER M1 ;
			RECT 7.185 0.42 7.38 1.74 ;
			LAYER M1 ;
			RECT 9.48 1.65 9.76 2.35 ;
			LAYER M1 ;
			RECT 8.37 0.42 8.65 1.075 ;
			LAYER M1 ;
			RECT 9.525 0.42 9.76 1.65 ;
			LAYER M1 ;
			RECT 0.0 -0.42 10.54 0.42 ;
		END
	END GND
	PIN q
		DIRECTION output ;
		USE SIGNAL ;
		PORT
			LAYER M1 ;
			RECT 9.88 3.945 10.16 5.135 ;
			LAYER M1 ;
			RECT 9.88 3.665 10.36 3.945 ;
			LAYER M1 ;
			RECT 9.9 3.66 10.36 3.665 ;
			LAYER M1 ;
			RECT 10.075 2.35 10.36 3.66 ;
			LAYER M1 ;
			RECT 10.07 2.065 10.36 2.35 ;
			LAYER M1 ;
			RECT 10.07 1.65 10.35 2.065 ;
		END
		AntennaDiffArea 0.91245 ;
	END q
	PIN VDD
		DIRECTION inout ;
		USE POWER ;
		PORT
			LAYER M1 ;
			RECT 0.0 5.78 10.54 6.62 ;
			LAYER M1 ;
			RECT 0.17 3.52 0.45 5.78 ;
			LAYER M1 ;
			RECT 1.35 4.74 1.63 5.78 ;
			LAYER M1 ;
			RECT 3.205 3.675 3.485 5.78 ;
			LAYER M1 ;
			RECT 4.385 3.675 4.665 5.78 ;
			LAYER M1 ;
			RECT 7.7 3.515 7.98 5.78 ;
			LAYER M1 ;
			RECT 9.29 3.665 9.57 5.78 ;
		END
	END VDD
	PIN setb
		DIRECTION input ;
		USE SIGNAL ;
		PORT
			LAYER M1 ;
			RECT 3.98 3.05 4.26 3.085 ;
			LAYER M1 ;
			RECT 3.98 2.86 5.46 3.05 ;
			LAYER M1 ;
			RECT 3.98 2.805 4.26 2.86 ;
			LAYER M1 ;
			RECT 5.045 2.62 5.46 2.86 ;
			LAYER M1 ;
			RECT 5.045 2.59 5.325 2.62 ;
		END
		AntennaGateArea 0.4575 ;
	END setb
	PIN clk
		DIRECTION input ;
		USE CLOCK ;
		PORT
			LAYER M1 ;
			RECT 1.375 2.93 1.75 2.98 ;
			LAYER M1 ;
			RECT 1.375 2.645 1.875 2.93 ;
			LAYER M1 ;
			RECT 1.375 2.6 1.75 2.645 ;
		END
		AntennaGateArea 0.44625 ;
	END clk
	OBS
		LAYER M1 ;
		RECT 0.76 3.745 1.04 4.99 ;
		LAYER M1 ;
		RECT 1.99 5.49 2.46 5.495 ;
		LAYER M1 ;
		RECT 1.99 5.455 2.66 5.49 ;
		LAYER M1 ;
		RECT 1.99 5.44 2.695 5.455 ;
		LAYER M1 ;
		RECT 1.94 5.21 2.695 5.44 ;
		LAYER M1 ;
		RECT 1.94 4.74 2.22 5.21 ;
		LAYER M1 ;
		RECT 1.35 3.745 1.63 4.415 ;
		LAYER M1 ;
		RECT 0.76 3.715 1.63 3.745 ;
		LAYER M1 ;
		RECT 1.94 3.715 2.22 4.415 ;
		LAYER M1 ;
		RECT 2.5 3.75 2.695 5.21 ;
		LAYER M1 ;
		RECT 0.76 3.555 1.625 3.715 ;
		LAYER M1 ;
		RECT 0.76 3.52 1.16 3.555 ;
		LAYER M1 ;
		RECT 0.97 2.35 1.16 3.52 ;
		LAYER M1 ;
		RECT 1.98 3.35 2.17 3.715 ;
		LAYER M1 ;
		RECT 2.5 3.555 2.925 3.75 ;
		LAYER M1 ;
		RECT 3.82 4.885 4.1 5.165 ;
		LAYER M1 ;
		RECT 3.865 4.375 4.055 4.885 ;
		LAYER M1 ;
		RECT 3.795 3.675 4.075 4.375 ;
		LAYER M1 ;
		RECT 5.1 5.01 7.165 5.205 ;
		LAYER M1 ;
		RECT 5.1 4.61 5.29 5.01 ;
		LAYER M1 ;
		RECT 5.01 3.675 5.29 4.61 ;
		LAYER M1 ;
		RECT 5.61 3.935 5.89 4.635 ;
		LAYER M1 ;
		RECT 6.2 3.935 6.48 4.635 ;
		LAYER M1 ;
		RECT 1.98 3.2 2.485 3.35 ;
		LAYER M1 ;
		RECT 1.98 3.155 2.515 3.2 ;
		LAYER M1 ;
		RECT 2.235 2.92 2.515 3.155 ;
		LAYER M1 ;
		RECT 0.95 2.115 1.23 2.35 ;
		LAYER M1 ;
		RECT 0.945 1.92 1.935 2.115 ;
		LAYER M1 ;
		RECT 2.29 1.92 2.485 2.92 ;
		LAYER M1 ;
		RECT 0.95 1.65 1.23 1.92 ;
		LAYER M1 ;
		RECT 1.66 1.64 1.94 1.92 ;
		LAYER M1 ;
		RECT 2.25 1.64 2.53 1.92 ;
		LAYER M1 ;
		RECT 2.73 1.315 2.925 3.555 ;
		LAYER M1 ;
		RECT 3.81 3.475 4.0 3.675 ;
		LAYER M1 ;
		RECT 5.66 3.475 5.855 3.935 ;
		LAYER M1 ;
		RECT 3.3 3.285 5.855 3.475 ;
		LAYER M1 ;
		RECT 3.3 2.605 3.49 3.285 ;
		LAYER M1 ;
		RECT 3.205 1.955 3.49 2.605 ;
		LAYER M1 ;
		RECT 3.205 1.905 3.485 1.955 ;
		LAYER M1 ;
		RECT 4.705 2.215 4.985 2.3 ;
		LAYER M1 ;
		RECT 5.66 2.215 5.855 3.285 ;
		LAYER M1 ;
		RECT 4.705 2.02 5.855 2.215 ;
		LAYER M1 ;
		RECT 6.21 2.83 6.4 3.935 ;
		LAYER M1 ;
		RECT 6.97 3.31 7.165 5.01 ;
		LAYER M1 ;
		RECT 8.685 3.505 8.965 4.975 ;
		LAYER M1 ;
		RECT 6.97 3.115 8.2 3.31 ;
		LAYER M1 ;
		RECT 7.92 3.03 8.2 3.115 ;
		LAYER M1 ;
		RECT 7.35 2.83 7.63 2.905 ;
		LAYER M1 ;
		RECT 6.21 2.635 7.63 2.83 ;
		LAYER M1 ;
		RECT 6.21 2.02 6.4 2.635 ;
		LAYER M1 ;
		RECT 7.35 2.625 7.63 2.635 ;
		LAYER M1 ;
		RECT 7.94 2.425 8.135 3.03 ;
		LAYER M1 ;
		RECT 6.655 2.28 8.135 2.425 ;
		LAYER M1 ;
		RECT 8.745 2.83 8.935 3.505 ;
		LAYER M1 ;
		RECT 9.535 2.83 9.815 2.885 ;
		LAYER M1 ;
		RECT 8.745 2.635 9.815 2.83 ;
		LAYER M1 ;
		RECT 6.655 2.235 8.225 2.28 ;
		LAYER M1 ;
		RECT 5.58 1.74 5.86 2.02 ;
		LAYER M1 ;
		RECT 6.17 1.74 6.45 2.02 ;
		LAYER M1 ;
		RECT 1.615 1.125 2.925 1.315 ;
		LAYER M1 ;
		RECT 3.505 1.145 4.225 1.425 ;
		LAYER M1 ;
		RECT 1.615 1.0 2.34 1.125 ;
		LAYER M1 ;
		RECT 3.505 1.115 3.785 1.145 ;
		LAYER M1 ;
		RECT 1.66 0.995 2.34 1.0 ;
		LAYER M1 ;
		RECT 5.54 1.425 5.82 1.43 ;
		LAYER M1 ;
		RECT 6.655 1.425 6.845 2.235 ;
		LAYER M1 ;
		RECT 7.94 2.05 8.225 2.235 ;
		LAYER M1 ;
		RECT 7.945 2.0 8.225 2.05 ;
		LAYER M1 ;
		RECT 5.54 1.23 6.845 1.425 ;
		LAYER M1 ;
		RECT 5.54 0.995 5.82 1.23 ;
		LAYER M1 ;
		RECT 7.6 1.47 7.88 1.53 ;
		LAYER M1 ;
		RECT 8.745 1.47 8.935 2.635 ;
		LAYER M1 ;
		RECT 9.535 2.605 9.815 2.635 ;
		LAYER M1 ;
		RECT 7.6 1.28 9.195 1.47 ;
		LAYER M1 ;
		RECT 7.6 1.25 7.975 1.28 ;
		LAYER M1 ;
		RECT 7.78 1.075 7.975 1.25 ;
		LAYER M1 ;
		RECT 9.005 1.075 9.195 1.28 ;
		LAYER M1 ;
		RECT 7.78 0.625 8.06 1.075 ;
		LAYER M1 ;
		RECT 8.96 0.625 9.24 1.075 ;
	END
END MMI_FFSB
MACRO MMI_FILL_1
	CLASS CORE ;
	FOREIGN MMI_FILL_1 0 0 ;
	SIZE 0.62 BY 6.2 ;
	SYMMETRY X Y ;
	SITE CORE1 ;
	PIN GND
		DIRECTION inout ;
		USE GROUND ;
		PORT
			LAYER M1 ;
			RECT 0.0 -0.42 0.62 0.42 ;
		END
	END GND
	PIN VDD
		DIRECTION inout ;
		USE POWER ;
		PORT
			LAYER M1 ;
			RECT 0.0 5.78 0.62 6.62 ;
		END
	END VDD
	OBS
	END
END MMI_FILL_1
MACRO MMI_FILL_2
	CLASS CORE ;
	FOREIGN MMI_FILL_2 0 0 ;
	SIZE 1.24 BY 6.2 ;
	SYMMETRY X Y ;
	SITE CORE1 ;
	PIN GND
		DIRECTION inout ;
		USE GROUND ;
		PORT
			LAYER M1 ;
			RECT 0.0 -0.42 1.24 0.42 ;
		END
	END GND
	PIN VDD
		DIRECTION inout ;
		USE POWER ;
		PORT
			LAYER M1 ;
			RECT 0.0 5.78 1.24 6.62 ;
		END
	END VDD
	OBS
	END
END MMI_FILL_2
MACRO MMI_FILL_4
	CLASS CORE ;
	FOREIGN MMI_FILL_4 0 0 ;
	SIZE 2.48 BY 6.2 ;
	SYMMETRY X Y ;
	SITE CORE1 ;
	PIN GND
		DIRECTION inout ;
		USE GROUND ;
		PORT
			LAYER M1 ;
			RECT 0.79 3.31 1.07 3.445 ;
			LAYER M1 ;
			RECT 0.79 2.555 1.075 3.31 ;
			LAYER M1 ;
			RECT 0.195 0.42 0.475 2.555 ;
			LAYER M1 ;
			RECT 0.785 2.27 1.075 2.555 ;
			LAYER M1 ;
			RECT 0.785 0.42 1.065 2.27 ;
			LAYER M1 ;
			RECT 1.375 0.42 1.655 2.555 ;
			LAYER M1 ;
			RECT 1.965 0.42 2.245 2.555 ;
			LAYER M1 ;
			RECT 0.0 -0.42 2.48 0.42 ;
		END
	END GND
	PIN VDD
		DIRECTION inout ;
		USE POWER ;
		PORT
			LAYER M1 ;
			RECT 0.0 5.78 2.48 6.62 ;
			LAYER M1 ;
			RECT 0.195 3.645 0.475 5.78 ;
			LAYER M1 ;
			RECT 0.785 3.645 1.065 5.78 ;
			LAYER M1 ;
			RECT 1.375 3.93 1.655 5.78 ;
			LAYER M1 ;
			RECT 1.375 3.645 1.675 3.93 ;
			LAYER M1 ;
			RECT 1.965 3.645 2.245 5.78 ;
			LAYER M1 ;
			RECT 1.39 2.955 1.675 3.645 ;
			LAYER M1 ;
			RECT 1.395 2.835 1.675 2.955 ;
		END
	END VDD
	OBS
	END
END MMI_FILL_4
MACRO MMI_FILL_8
	CLASS CORE ;
	FOREIGN MMI_FILL_8 0 0 ;
	SIZE 4.96 BY 6.2 ;
	SYMMETRY X Y ;
	SITE CORE1 ;
	PIN GND
		DIRECTION inout ;
		USE GROUND ;
		PORT
			LAYER M1 ;
			RECT 0.79 3.31 1.07 3.445 ;
			LAYER M1 ;
			RECT 3.205 3.31 3.485 3.445 ;
			LAYER M1 ;
			RECT 0.79 2.555 1.075 3.31 ;
			LAYER M1 ;
			RECT 3.2 2.555 3.485 3.31 ;
			LAYER M1 ;
			RECT 0.195 1.02 0.475 2.555 ;
			LAYER M1 ;
			RECT 0.19 0.42 0.475 1.02 ;
			LAYER M1 ;
			RECT 0.785 2.27 1.075 2.555 ;
			LAYER M1 ;
			RECT 0.785 1.02 1.065 2.27 ;
			LAYER M1 ;
			RECT 1.375 1.02 1.655 2.555 ;
			LAYER M1 ;
			RECT 1.965 1.02 2.245 2.555 ;
			LAYER M1 ;
			RECT 2.555 1.02 2.835 2.555 ;
			LAYER M1 ;
			RECT 3.145 2.27 3.485 2.555 ;
			LAYER M1 ;
			RECT 3.145 1.02 3.425 2.27 ;
			LAYER M1 ;
			RECT 3.735 1.02 4.015 2.555 ;
			LAYER M1 ;
			RECT 4.325 1.02 4.605 2.555 ;
			LAYER M1 ;
			RECT 0.785 0.42 1.07 1.02 ;
			LAYER M1 ;
			RECT 1.375 0.42 1.66 1.02 ;
			LAYER M1 ;
			RECT 1.965 0.42 2.25 1.02 ;
			LAYER M1 ;
			RECT 2.555 0.42 2.84 1.02 ;
			LAYER M1 ;
			RECT 3.145 0.42 3.43 1.02 ;
			LAYER M1 ;
			RECT 3.735 0.42 4.02 1.02 ;
			LAYER M1 ;
			RECT 4.325 0.42 4.61 1.02 ;
			LAYER M1 ;
			RECT 0.0 -0.42 4.96 0.42 ;
		END
	END GND
	PIN VDD
		DIRECTION inout ;
		USE POWER ;
		PORT
			LAYER M1 ;
			RECT 0.0 5.78 4.96 6.62 ;
			LAYER M1 ;
			RECT 0.19 5.21 0.475 5.78 ;
			LAYER M1 ;
			RECT 0.195 3.645 0.475 5.21 ;
			LAYER M1 ;
			RECT 0.785 5.21 1.07 5.78 ;
			LAYER M1 ;
			RECT 1.375 5.21 1.66 5.78 ;
			LAYER M1 ;
			RECT 1.965 5.21 2.25 5.78 ;
			LAYER M1 ;
			RECT 2.555 5.21 2.84 5.78 ;
			LAYER M1 ;
			RECT 3.145 5.21 3.43 5.78 ;
			LAYER M1 ;
			RECT 3.735 5.21 4.02 5.78 ;
			LAYER M1 ;
			RECT 4.325 5.21 4.61 5.78 ;
			LAYER M1 ;
			RECT 0.785 3.645 1.065 5.21 ;
			LAYER M1 ;
			RECT 1.375 3.93 1.655 5.21 ;
			LAYER M1 ;
			RECT 1.375 3.645 1.675 3.93 ;
			LAYER M1 ;
			RECT 1.965 3.645 2.245 5.21 ;
			LAYER M1 ;
			RECT 2.555 3.645 2.835 5.21 ;
			LAYER M1 ;
			RECT 3.145 3.645 3.425 5.21 ;
			LAYER M1 ;
			RECT 3.735 3.93 4.015 5.21 ;
			LAYER M1 ;
			RECT 3.735 3.645 4.09 3.93 ;
			LAYER M1 ;
			RECT 4.325 3.645 4.605 5.21 ;
			LAYER M1 ;
			RECT 1.39 2.955 1.675 3.645 ;
			LAYER M1 ;
			RECT 1.395 2.835 1.675 2.955 ;
			LAYER M1 ;
			RECT 3.805 2.955 4.09 3.645 ;
			LAYER M1 ;
			RECT 3.805 2.835 4.085 2.955 ;
		END
	END VDD
	OBS
	END
END MMI_FILL_8
MACRO MMI_INAND2A
	CLASS CORE ;
	FOREIGN MMI_INAND2A 0 0 ;
	SIZE 2.48 BY 6.2 ;
	SYMMETRY X Y ;
	SITE CORE1 ;
	PIN out
		DIRECTION output ;
		USE SIGNAL ;
		PORT
			LAYER M1 ;
			RECT 0.75 3.815 1.03 4.515 ;
			LAYER M1 ;
			RECT 0.75 3.465 0.94 3.815 ;
			LAYER M1 ;
			RECT 0.245 3.27 0.94 3.465 ;
			LAYER M1 ;
			RECT 0.245 2.98 0.435 3.27 ;
			LAYER M1 ;
			RECT 0.12 2.58 0.5 2.98 ;
			LAYER M1 ;
			RECT 0.12 1.89 0.315 2.58 ;
			LAYER M1 ;
			RECT 0.12 1.885 0.59 1.89 ;
			LAYER M1 ;
			RECT 0.12 1.695 0.595 1.885 ;
			LAYER M1 ;
			RECT 0.315 1.185 0.595 1.695 ;
		END
		AntennaDiffArea 0.64295 ;
	END out
	PIN in1
		DIRECTION input ;
		USE SIGNAL ;
		PORT
			LAYER M1 ;
			RECT 1.36 3.54 1.74 3.6 ;
			LAYER M1 ;
			RECT 1.36 3.26 1.8 3.54 ;
			LAYER M1 ;
			RECT 1.36 3.22 1.74 3.26 ;
		END
		AntennaGateArea 0.17325 ;
	END in1
	PIN GND
		DIRECTION inout ;
		USE GROUND ;
		PORT
			LAYER M1 ;
			RECT 1.28 0.42 1.56 1.885 ;
			LAYER M1 ;
			RECT 0.0 -0.42 2.48 0.42 ;
		END
	END GND
	PIN VDD
		DIRECTION inout ;
		USE POWER ;
		PORT
			LAYER M1 ;
			RECT 0.0 5.78 2.48 6.62 ;
			LAYER M1 ;
			RECT 0.16 3.815 0.44 5.78 ;
			LAYER M1 ;
			RECT 1.34 3.815 1.62 5.78 ;
		END
	END VDD
	PIN in0
		DIRECTION input ;
		USE SIGNAL ;
		PORT
			LAYER M1 ;
			RECT 0.74 2.945 1.12 2.98 ;
			LAYER M1 ;
			RECT 0.74 2.885 1.24 2.945 ;
			LAYER M1 ;
			RECT 0.74 2.695 1.295 2.885 ;
			LAYER M1 ;
			RECT 0.74 2.665 1.24 2.695 ;
			LAYER M1 ;
			RECT 0.74 2.6 1.12 2.665 ;
		END
		AntennaGateArea 0.231 ;
	END in0
	OBS
		LAYER M1 ;
		RECT 1.93 3.815 2.21 4.515 ;
		LAYER M1 ;
		RECT 2.005 2.37 2.195 3.815 ;
		LAYER M1 ;
		RECT 0.515 2.18 2.195 2.37 ;
		LAYER M1 ;
		RECT 0.515 2.09 0.795 2.18 ;
		LAYER M1 ;
		RECT 2.005 1.89 2.195 2.18 ;
		LAYER M1 ;
		RECT 1.915 1.575 2.195 1.89 ;
	END
END MMI_INAND2A
MACRO MMI_INAND2B
	CLASS CORE ;
	FOREIGN MMI_INAND2B 0 0 ;
	SIZE 2.48 BY 6.2 ;
	SYMMETRY X Y ;
	SITE CORE1 ;
	PIN out
		DIRECTION output ;
		USE SIGNAL ;
		PORT
			LAYER M1 ;
			RECT 0.75 3.965 1.03 5.24 ;
			LAYER M1 ;
			RECT 0.17 3.775 1.03 3.965 ;
			LAYER M1 ;
			RECT 0.17 2.98 0.365 3.775 ;
			LAYER M1 ;
			RECT 0.75 3.77 1.03 3.775 ;
			LAYER M1 ;
			RECT 0.12 2.6 0.5 2.98 ;
			LAYER M1 ;
			RECT 0.16 2.19 0.355 2.6 ;
			LAYER M1 ;
			RECT 0.16 0.72 0.44 2.19 ;
		END
		AntennaDiffArea 1.2859 ;
	END out
	PIN in1
		DIRECTION input ;
		USE SIGNAL ;
		PORT
			LAYER M1 ;
			RECT 1.36 2.925 1.74 2.98 ;
			LAYER M1 ;
			RECT 1.36 2.645 1.835 2.925 ;
			LAYER M1 ;
			RECT 1.36 2.6 1.74 2.645 ;
		END
		AntennaGateArea 0.17325 ;
	END in1
	PIN GND
		DIRECTION inout ;
		USE GROUND ;
		PORT
			LAYER M1 ;
			RECT 1.12 0.42 1.4 2.19 ;
			LAYER M1 ;
			RECT 0.0 -0.42 2.48 0.42 ;
		END
	END GND
	PIN VDD
		DIRECTION inout ;
		USE POWER ;
		PORT
			LAYER M1 ;
			RECT 0.0 5.78 2.48 6.62 ;
			LAYER M1 ;
			RECT 0.16 4.18 0.44 5.78 ;
			LAYER M1 ;
			RECT 1.34 3.77 1.62 5.78 ;
		END
	END VDD
	PIN in0
		DIRECTION input ;
		USE SIGNAL ;
		PORT
			LAYER M1 ;
			RECT 0.88 2.98 1.16 3.0 ;
			LAYER M1 ;
			RECT 0.74 2.72 1.16 2.98 ;
			LAYER M1 ;
			RECT 0.74 2.6 1.12 2.72 ;
		END
		AntennaGateArea 0.462 ;
	END in0
	OBS
		LAYER M1 ;
		RECT 1.99 3.77 2.27 4.47 ;
		LAYER M1 ;
		RECT 0.57 3.5 0.85 3.57 ;
		LAYER M1 ;
		RECT 2.035 3.5 2.225 3.77 ;
		LAYER M1 ;
		RECT 0.57 3.305 2.225 3.5 ;
		LAYER M1 ;
		RECT 0.57 3.29 0.85 3.305 ;
		LAYER M1 ;
		RECT 2.035 2.195 2.225 3.305 ;
		LAYER M1 ;
		RECT 1.755 2.005 2.225 2.195 ;
		LAYER M1 ;
		RECT 1.755 1.88 2.035 2.005 ;
	END
END MMI_INAND2B
MACRO MMI_INAND2C
	CLASS CORE ;
	FOREIGN MMI_INAND2C 0 0 ;
	SIZE 3.72 BY 6.2 ;
	SYMMETRY X Y ;
	SITE CORE1 ;
	PIN out
		DIRECTION output ;
		USE SIGNAL ;
		PORT
			LAYER M1 ;
			RECT 1.34 3.995 1.62 5.27 ;
			LAYER M1 ;
			RECT 2.52 3.995 2.8 5.27 ;
			LAYER M1 ;
			RECT 1.34 3.8 2.85 3.995 ;
			LAYER M1 ;
			RECT 2.015 3.6 2.21 3.8 ;
			LAYER M1 ;
			RECT 1.98 3.22 2.36 3.6 ;
			LAYER M1 ;
			RECT 2.03 2.52 2.225 3.22 ;
			LAYER M1 ;
			RECT 1.76 2.33 2.225 2.52 ;
			LAYER M1 ;
			RECT 1.76 0.885 2.04 2.33 ;
		END
		AntennaDiffArea 2.0328 ;
	END out
	PIN in1
		DIRECTION input ;
		USE SIGNAL ;
		PORT
			LAYER M1 ;
			RECT 0.74 3.55 1.12 3.6 ;
			LAYER M1 ;
			RECT 0.575 3.27 1.12 3.55 ;
			LAYER M1 ;
			RECT 0.74 3.22 1.12 3.27 ;
		END
		AntennaGateArea 0.3465 ;
	END in1
	PIN GND
		DIRECTION inout ;
		USE GROUND ;
		PORT
			LAYER M1 ;
			RECT 0.795 0.42 1.075 2.355 ;
			LAYER M1 ;
			RECT 2.72 0.42 3.0 2.355 ;
			LAYER M1 ;
			RECT 0.0 -0.42 3.72 0.42 ;
		END
	END GND
	PIN VDD
		DIRECTION inout ;
		USE POWER ;
		PORT
			LAYER M1 ;
			RECT 0.0 5.78 3.72 6.62 ;
			LAYER M1 ;
			RECT 0.75 3.8 1.03 5.78 ;
			LAYER M1 ;
			RECT 1.93 4.21 2.21 5.78 ;
			LAYER M1 ;
			RECT 3.11 3.8 3.39 5.78 ;
		END
	END VDD
	PIN in0
		DIRECTION input ;
		USE SIGNAL ;
		PORT
			LAYER M1 ;
			RECT 2.6 2.6 2.98 2.98 ;
		END
		AntennaGateArea 0.924 ;
	END in0
	OBS
		LAYER M1 ;
		RECT 0.16 3.8 0.44 5.27 ;
		LAYER M1 ;
		RECT 0.185 3.015 0.375 3.8 ;
		LAYER M1 ;
		RECT 1.345 3.015 1.625 3.145 ;
		LAYER M1 ;
		RECT 0.185 2.825 1.625 3.015 ;
		LAYER M1 ;
		RECT 0.185 2.355 0.375 2.825 ;
		LAYER M1 ;
		RECT 0.16 1.655 0.44 2.355 ;
	END
END MMI_INAND2C
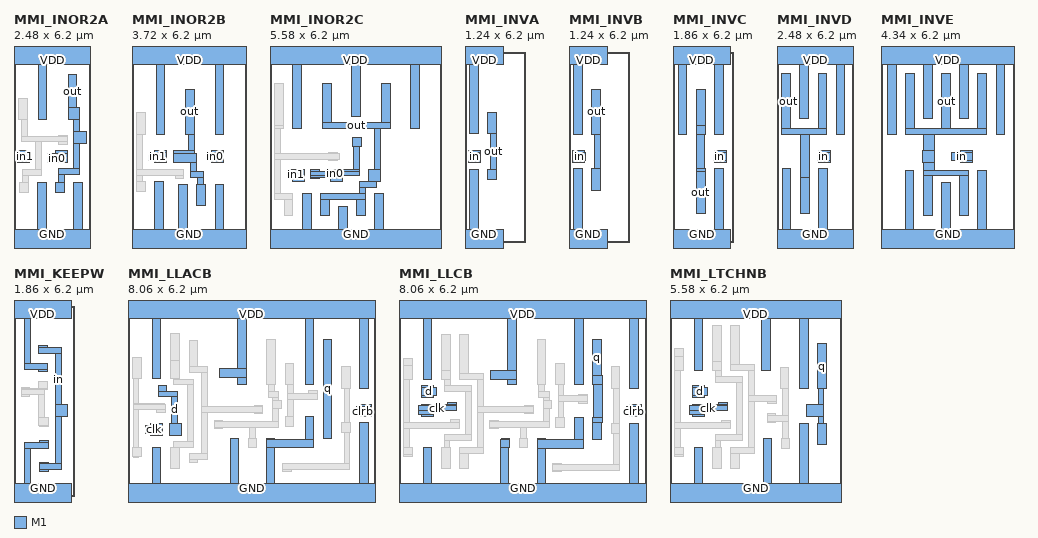
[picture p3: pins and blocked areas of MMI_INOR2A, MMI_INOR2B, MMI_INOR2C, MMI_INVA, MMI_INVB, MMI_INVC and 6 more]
MACRO MMI_INOR2A
	CLASS CORE ;
	FOREIGN MMI_INOR2A 0 0 ;
	SIZE 2.48 BY 6.2 ;
	SYMMETRY X Y ;
	SITE CORE1 ;
	PIN out
		DIRECTION output ;
		USE SIGNAL ;
		PORT
			LAYER M1 ;
			RECT 1.765 4.385 2.045 5.455 ;
			LAYER M1 ;
			RECT 1.765 3.985 2.145 4.385 ;
			LAYER M1 ;
			RECT 1.95 3.6 2.145 3.985 ;
			LAYER M1 ;
			RECT 1.95 3.22 2.36 3.6 ;
			LAYER M1 ;
			RECT 1.95 2.39 2.145 3.22 ;
			LAYER M1 ;
			RECT 1.455 2.195 2.145 2.39 ;
			LAYER M1 ;
			RECT 1.455 1.945 1.645 2.195 ;
			LAYER M1 ;
			RECT 1.365 1.63 1.645 1.945 ;
		END
		AntennaDiffArea 0.7777 ;
	END out
	PIN in1
		DIRECTION input ;
		USE SIGNAL ;
		PORT
			LAYER M1 ;
			RECT 0.12 2.6 0.5 2.98 ;
		END
		AntennaGateArea 0.17325 ;
	END in1
	PIN GND
		DIRECTION inout ;
		USE GROUND ;
		PORT
			LAYER M1 ;
			RECT 0.775 0.42 1.055 1.945 ;
			LAYER M1 ;
			RECT 1.955 0.42 2.235 1.945 ;
			LAYER M1 ;
			RECT 0.0 -0.42 2.48 0.42 ;
		END
	END GND
	PIN VDD
		DIRECTION inout ;
		USE POWER ;
		PORT
			LAYER M1 ;
			RECT 0.0 5.78 2.48 6.62 ;
			LAYER M1 ;
			RECT 0.795 3.985 1.075 5.78 ;
		END
	END VDD
	PIN in0
		DIRECTION input ;
		USE SIGNAL ;
		PORT
			LAYER M1 ;
			RECT 1.36 2.885 1.74 2.98 ;
			LAYER M1 ;
			RECT 1.125 2.88 1.74 2.885 ;
			LAYER M1 ;
			RECT 1.095 2.6 1.74 2.88 ;
		END
		AntennaGateArea 0.28875 ;
	END in0
	OBS
		LAYER M1 ;
		RECT 0.16 3.985 0.44 4.685 ;
		LAYER M1 ;
		RECT 0.25 3.455 0.44 3.985 ;
		LAYER M1 ;
		RECT 1.45 3.455 1.73 3.46 ;
		LAYER M1 ;
		RECT 0.25 3.265 1.73 3.455 ;
		LAYER M1 ;
		RECT 0.7 2.37 0.89 3.265 ;
		LAYER M1 ;
		RECT 1.45 3.18 1.73 3.265 ;
		LAYER M1 ;
		RECT 0.275 2.175 0.89 2.37 ;
		LAYER M1 ;
		RECT 0.275 1.945 0.465 2.175 ;
		LAYER M1 ;
		RECT 0.185 1.63 0.465 1.945 ;
	END
END MMI_INOR2A
MACRO MMI_INOR2B
	CLASS CORE ;
	FOREIGN MMI_INOR2B 0 0 ;
	SIZE 3.72 BY 6.2 ;
	SYMMETRY X Y ;
	SITE CORE1 ;
	PIN out
		DIRECTION output ;
		USE SIGNAL ;
		PORT
			LAYER M1 ;
			RECT 1.745 3.515 2.025 4.985 ;
			LAYER M1 ;
			RECT 1.835 2.98 2.025 3.515 ;
			LAYER M1 ;
			RECT 1.36 2.885 2.025 2.98 ;
			LAYER M1 ;
			RECT 1.36 2.6 2.105 2.885 ;
			LAYER M1 ;
			RECT 1.91 2.31 2.105 2.6 ;
			LAYER M1 ;
			RECT 1.91 2.115 2.32 2.31 ;
			LAYER M1 ;
			RECT 2.125 1.875 2.32 2.115 ;
			LAYER M1 ;
			RECT 2.12 1.175 2.4 1.875 ;
		END
		AntennaDiffArea 1.0164 ;
	END out
	PIN in1
		DIRECTION input ;
		USE SIGNAL ;
		PORT
			LAYER M1 ;
			RECT 0.74 2.93 1.12 2.98 ;
			LAYER M1 ;
			RECT 0.55 2.65 1.12 2.93 ;
			LAYER M1 ;
			RECT 0.74 2.6 1.12 2.65 ;
		END
		AntennaGateArea 0.17325 ;
	END in1
	PIN GND
		DIRECTION inout ;
		USE GROUND ;
		PORT
			LAYER M1 ;
			RECT 0.745 0.42 1.025 1.965 ;
			LAYER M1 ;
			RECT 1.53 0.42 1.81 1.875 ;
			LAYER M1 ;
			RECT 2.71 0.42 2.99 1.875 ;
			LAYER M1 ;
			RECT 0.0 -0.42 3.72 0.42 ;
		END
	END GND
	PIN VDD
		DIRECTION inout ;
		USE POWER ;
		PORT
			LAYER M1 ;
			RECT 0.0 5.78 3.72 6.62 ;
			LAYER M1 ;
			RECT 0.785 3.515 1.065 5.78 ;
			LAYER M1 ;
			RECT 2.71 3.515 2.99 5.78 ;
		END
	END VDD
	PIN in0
		DIRECTION input ;
		USE SIGNAL ;
		PORT
			LAYER M1 ;
			RECT 2.6 2.93 2.98 2.98 ;
			LAYER M1 ;
			RECT 2.455 2.65 2.98 2.93 ;
			LAYER M1 ;
			RECT 2.6 2.6 2.98 2.65 ;
		END
		AntennaGateArea 0.5775 ;
	END in0
	OBS
		LAYER M1 ;
		RECT 0.155 3.515 0.435 4.215 ;
		LAYER M1 ;
		RECT 0.155 2.36 0.35 3.515 ;
		LAYER M1 ;
		RECT 0.155 2.165 1.69 2.36 ;
		LAYER M1 ;
		RECT 0.155 1.965 0.35 2.165 ;
		LAYER M1 ;
		RECT 1.405 2.075 1.685 2.165 ;
		LAYER M1 ;
		RECT 0.155 1.65 0.435 1.965 ;
	END
END MMI_INOR2B
MACRO MMI_INOR2C
	CLASS CORE ;
	FOREIGN MMI_INOR2C 0 0 ;
	SIZE 5.58 BY 6.2 ;
	SYMMETRY X Y ;
	SITE CORE1 ;
	PIN out
		DIRECTION output ;
		USE SIGNAL ;
		PORT
			LAYER M1 ;
			RECT 1.715 3.89 1.995 5.165 ;
			LAYER M1 ;
			RECT 3.64 3.89 3.92 5.165 ;
			LAYER M1 ;
			RECT 1.715 3.695 3.92 3.89 ;
			LAYER M1 ;
			RECT 3.4 2.36 3.595 3.695 ;
			LAYER M1 ;
			RECT 3.22 1.98 3.595 2.36 ;
			LAYER M1 ;
			RECT 3.22 1.97 3.47 1.98 ;
			LAYER M1 ;
			RECT 2.925 1.775 3.47 1.97 ;
			LAYER M1 ;
			RECT 2.925 1.575 3.115 1.775 ;
			LAYER M1 ;
			RECT 1.65 1.385 3.115 1.575 ;
			LAYER M1 ;
			RECT 1.65 0.875 1.93 1.385 ;
			LAYER M1 ;
			RECT 2.83 0.875 3.11 1.385 ;
		END
		AntennaDiffArea 2.0328 ;
	END out
	PIN in1
		DIRECTION input ;
		USE SIGNAL ;
		PORT
			LAYER M1 ;
			RECT 0.74 2.35 1.12 2.36 ;
			LAYER M1 ;
			RECT 0.555 2.07 1.12 2.35 ;
			LAYER M1 ;
			RECT 0.74 1.98 1.12 2.07 ;
		END
		AntennaGateArea 0.3465 ;
	END in1
	PIN GND
		DIRECTION inout ;
		USE GROUND ;
		PORT
			LAYER M1 ;
			RECT 1.06 0.42 1.34 1.575 ;
			LAYER M1 ;
			RECT 2.24 0.42 2.52 1.155 ;
			LAYER M1 ;
			RECT 3.42 0.42 3.7 1.575 ;
			LAYER M1 ;
			RECT 0.0 -0.42 5.58 0.42 ;
		END
	END GND
	PIN VDD
		DIRECTION inout ;
		USE POWER ;
		PORT
			LAYER M1 ;
			RECT 0.0 5.78 5.58 6.62 ;
			LAYER M1 ;
			RECT 0.75 3.695 1.03 5.78 ;
			LAYER M1 ;
			RECT 2.675 4.105 2.955 5.78 ;
			LAYER M1 ;
			RECT 4.6 3.695 4.88 5.78 ;
		END
	END VDD
	PIN in0
		DIRECTION input ;
		USE SIGNAL ;
		PORT
			LAYER M1 ;
			RECT 2.69 3.125 2.97 3.405 ;
			LAYER M1 ;
			RECT 2.73 2.365 2.92 3.125 ;
			LAYER M1 ;
			RECT 1.32 2.31 1.6 2.35 ;
			LAYER M1 ;
			RECT 1.98 2.31 2.92 2.365 ;
			LAYER M1 ;
			RECT 1.32 2.17 2.92 2.31 ;
			LAYER M1 ;
			RECT 1.32 2.115 2.36 2.17 ;
			LAYER M1 ;
			RECT 1.32 2.07 1.6 2.115 ;
			LAYER M1 ;
			RECT 1.98 1.98 2.36 2.115 ;
		END
		AntennaGateArea 1.155 ;
	END in0
	OBS
		LAYER M1 ;
		RECT 0.16 3.79 0.44 5.165 ;
		LAYER M1 ;
		RECT 0.155 3.695 0.44 3.79 ;
		LAYER M1 ;
		RECT 0.155 2.885 0.35 3.695 ;
		LAYER M1 ;
		RECT 1.92 2.885 2.2 2.93 ;
		LAYER M1 ;
		RECT 0.155 2.695 2.26 2.885 ;
		LAYER M1 ;
		RECT 0.155 1.575 0.35 2.695 ;
		LAYER M1 ;
		RECT 1.92 2.65 2.2 2.695 ;
		LAYER M1 ;
		RECT 0.155 1.385 0.75 1.575 ;
		LAYER M1 ;
		RECT 0.47 0.875 0.75 1.385 ;
	END
END MMI_INOR2C
MACRO MMI_INVA
	CLASS CORE ;
	FOREIGN MMI_INVA 0 0 ;
	SIZE 1.24 BY 6.2 ;
	SYMMETRY X Y ;
	SITE CORE1 ;
	PIN out
		DIRECTION output ;
		USE SIGNAL ;
		PORT
			LAYER M1 ;
			RECT 0.75 3.535 1.03 4.235 ;
			LAYER M1 ;
			RECT 0.835 2.365 1.03 3.535 ;
			LAYER M1 ;
			RECT 0.75 2.05 1.03 2.365 ;
		END
		AntennaDiffArea 0.456225 ;
	END out
	PIN GND
		DIRECTION inout ;
		USE GROUND ;
		PORT
			LAYER M1 ;
			RECT 0.16 0.42 0.44 2.365 ;
			LAYER M1 ;
			RECT 0.0 -0.42 1.24 0.42 ;
		END
	END GND
	PIN VDD
		DIRECTION inout ;
		USE POWER ;
		PORT
			LAYER M1 ;
			RECT 0.0 5.78 1.24 6.62 ;
			LAYER M1 ;
			RECT 0.16 3.535 0.44 5.78 ;
		END
	END VDD
	PIN in
		DIRECTION input ;
		USE SIGNAL ;
		PORT
			LAYER M1 ;
			RECT 0.12 2.93 0.5 2.98 ;
			LAYER M1 ;
			RECT 0.12 2.885 0.515 2.93 ;
			LAYER M1 ;
			RECT 0.12 2.695 0.52 2.885 ;
			LAYER M1 ;
			RECT 0.12 2.65 0.515 2.695 ;
			LAYER M1 ;
			RECT 0.12 2.6 0.5 2.65 ;
		END
		AntennaGateArea 0.17325 ;
	END in
	OBS
	END
END MMI_INVA
MACRO MMI_INVB
	CLASS CORE ;
	FOREIGN MMI_INVB 0 0 ;
	SIZE 1.24 BY 6.2 ;
	SYMMETRY X Y ;
	SITE CORE1 ;
	PIN out
		DIRECTION output ;
		USE SIGNAL ;
		PORT
			LAYER M1 ;
			RECT 0.75 3.515 1.03 4.985 ;
			LAYER M1 ;
			RECT 0.835 2.395 1.03 3.515 ;
			LAYER M1 ;
			RECT 0.75 1.695 1.03 2.395 ;
		END
		AntennaDiffArea 0.91245 ;
	END out
	PIN GND
		DIRECTION inout ;
		USE GROUND ;
		PORT
			LAYER M1 ;
			RECT 0.16 0.42 0.44 2.395 ;
			LAYER M1 ;
			RECT 0.0 -0.42 1.24 0.42 ;
		END
	END GND
	PIN VDD
		DIRECTION inout ;
		USE POWER ;
		PORT
			LAYER M1 ;
			RECT 0.0 5.78 1.24 6.62 ;
			LAYER M1 ;
			RECT 0.16 3.515 0.44 5.78 ;
		END
	END VDD
	PIN in
		DIRECTION input ;
		USE SIGNAL ;
		PORT
			LAYER M1 ;
			RECT 0.12 2.93 0.5 2.98 ;
			LAYER M1 ;
			RECT 0.12 2.65 0.535 2.93 ;
			LAYER M1 ;
			RECT 0.12 2.6 0.5 2.65 ;
		END
		AntennaGateArea 0.3465 ;
	END in
	OBS
	END
END MMI_INVB
MACRO MMI_INVC
	CLASS CORE ;
	FOREIGN MMI_INVC 0 0 ;
	SIZE 1.86 BY 6.2 ;
	SYMMETRY X Y ;
	SITE CORE1 ;
	PIN out
		DIRECTION output ;
		USE SIGNAL ;
		PORT
			LAYER M1 ;
			RECT 0.765 3.795 1.045 4.985 ;
			LAYER M1 ;
			RECT 0.755 3.515 1.045 3.795 ;
			LAYER M1 ;
			RECT 0.755 2.4 1.04 3.515 ;
			LAYER M1 ;
			RECT 0.755 2.31 1.045 2.4 ;
			LAYER M1 ;
			RECT 0.765 0.93 1.045 2.31 ;
		END
		AntennaDiffArea 1.2859 ;
	END out
	PIN GND
		DIRECTION inout ;
		USE GROUND ;
		PORT
			LAYER M1 ;
			RECT 1.355 0.42 1.635 2.4 ;
			LAYER M1 ;
			RECT 0.0 -0.42 1.86 0.42 ;
		END
	END GND
	PIN VDD
		DIRECTION inout ;
		USE POWER ;
		PORT
			LAYER M1 ;
			RECT 0.0 5.78 1.86 6.62 ;
			LAYER M1 ;
			RECT 0.175 3.515 0.455 5.78 ;
			LAYER M1 ;
			RECT 1.355 3.515 1.635 5.78 ;
		END
	END VDD
	PIN in
		DIRECTION input ;
		USE SIGNAL ;
		PORT
			LAYER M1 ;
			RECT 1.36 2.93 1.74 2.98 ;
			LAYER M1 ;
			RECT 1.31 2.65 1.74 2.93 ;
			LAYER M1 ;
			RECT 1.36 2.6 1.74 2.65 ;
		END
		AntennaGateArea 0.693 ;
	END in
	OBS
	END
END MMI_INVC
MACRO MMI_INVD
	CLASS CORE ;
	FOREIGN MMI_INVD 0 0 ;
	SIZE 2.48 BY 6.2 ;
	SYMMETRY X Y ;
	SITE CORE1 ;
	PIN out
		DIRECTION output ;
		USE SIGNAL ;
		PORT
			LAYER M1 ;
			RECT 0.16 3.69 0.44 5.485 ;
			LAYER M1 ;
			RECT 1.34 3.69 1.62 5.485 ;
			LAYER M1 ;
			RECT 0.16 3.5 1.62 3.69 ;
			LAYER M1 ;
			RECT 0.76 2.115 1.045 3.5 ;
			LAYER M1 ;
			RECT 0.765 0.925 1.045 2.115 ;
		END
		AntennaDiffArea 2.393525 ;
	END out
	PIN GND
		DIRECTION inout ;
		USE GROUND ;
		PORT
			LAYER M1 ;
			RECT 0.175 0.42 0.455 2.395 ;
			LAYER M1 ;
			RECT 1.355 0.42 1.635 2.395 ;
			LAYER M1 ;
			RECT 0.0 -0.42 2.48 0.42 ;
		END
	END GND
	PIN VDD
		DIRECTION inout ;
		USE POWER ;
		PORT
			LAYER M1 ;
			RECT 0.0 5.78 2.48 6.62 ;
			LAYER M1 ;
			RECT 0.75 4.03 1.03 5.78 ;
			LAYER M1 ;
			RECT 1.93 3.5 2.21 5.78 ;
		END
	END VDD
	PIN in
		DIRECTION input ;
		USE SIGNAL ;
		PORT
			LAYER M1 ;
			RECT 1.36 2.93 1.74 2.98 ;
			LAYER M1 ;
			RECT 1.31 2.65 1.74 2.93 ;
			LAYER M1 ;
			RECT 1.36 2.6 1.74 2.65 ;
		END
		AntennaGateArea 1.38675 ;
	END in
	OBS
	END
END MMI_INVD
MACRO MMI_INVE
	CLASS CORE ;
	FOREIGN MMI_INVE 0 0 ;
	SIZE 4.34 BY 6.2 ;
	SYMMETRY X Y ;
	SITE CORE1 ;
	PIN out
		DIRECTION output ;
		USE SIGNAL ;
		PORT
			LAYER M1 ;
			RECT 0.805 3.695 1.085 5.49 ;
			LAYER M1 ;
			RECT 1.985 3.695 2.265 5.49 ;
			LAYER M1 ;
			RECT 3.165 3.695 3.445 5.49 ;
			LAYER M1 ;
			RECT 0.805 3.505 3.445 3.695 ;
			LAYER M1 ;
			RECT 1.375 2.98 1.74 3.505 ;
			LAYER M1 ;
			RECT 1.36 2.6 1.74 2.98 ;
			LAYER M1 ;
			RECT 1.375 2.345 1.74 2.6 ;
			LAYER M1 ;
			RECT 1.375 2.155 2.865 2.345 ;
			LAYER M1 ;
			RECT 1.385 0.875 1.665 2.155 ;
			LAYER M1 ;
			RECT 2.565 0.875 2.845 2.155 ;
		END
		AntennaDiffArea 4.0678 ;
	END out
	PIN GND
		DIRECTION inout ;
		USE GROUND ;
		PORT
			LAYER M1 ;
			RECT 0.795 0.42 1.075 2.345 ;
			LAYER M1 ;
			RECT 1.975 0.42 2.255 1.935 ;
			LAYER M1 ;
			RECT 3.155 0.42 3.435 2.345 ;
			LAYER M1 ;
			RECT 0.0 -0.42 4.34 0.42 ;
		END
	END GND
	PIN VDD
		DIRECTION inout ;
		USE POWER ;
		PORT
			LAYER M1 ;
			RECT 0.0 5.78 4.34 6.62 ;
			LAYER M1 ;
			RECT 0.215 3.505 0.495 5.78 ;
			LAYER M1 ;
			RECT 1.395 4.035 1.675 5.78 ;
			LAYER M1 ;
			RECT 2.575 4.035 2.855 5.78 ;
			LAYER M1 ;
			RECT 3.755 3.505 4.035 5.78 ;
		END
	END VDD
	PIN in
		DIRECTION input ;
		USE SIGNAL ;
		PORT
			LAYER M1 ;
			RECT 2.6 2.93 2.98 2.98 ;
			LAYER M1 ;
			RECT 2.29 2.65 2.98 2.93 ;
			LAYER M1 ;
			RECT 2.6 2.6 2.98 2.65 ;
		END
		AntennaGateArea 2.7735 ;
	END in
	OBS
	END
END MMI_INVE
MACRO MMI_KEEPW
	CLASS CORE ;
	FOREIGN MMI_KEEPW 0 0 ;
	SIZE 1.86 BY 6.2 ;
	SYMMETRY X Y ;
	SITE CORE1 ;
	PIN GND
		DIRECTION inout ;
		USE GROUND ;
		PORT
			LAYER M1 ;
			RECT 0.83 1.73 1.11 1.82 ;
			LAYER M1 ;
			RECT 0.33 1.54 1.11 1.73 ;
			LAYER M1 ;
			RECT 0.33 0.42 0.525 1.54 ;
			LAYER M1 ;
			RECT 0.0 -0.42 1.86 0.42 ;
		END
	END GND
	PIN VDD
		DIRECTION inout ;
		USE POWER ;
		PORT
			LAYER M1 ;
			RECT 0.0 5.78 1.86 6.62 ;
			LAYER M1 ;
			RECT 0.355 4.33 0.55 5.78 ;
			LAYER M1 ;
			RECT 0.355 4.14 1.08 4.33 ;
			LAYER M1 ;
			RECT 0.8 4.05 1.08 4.14 ;
		END
	END VDD
	PIN in
		DIRECTION inout ;
		USE SIGNAL ;
		PORT
			LAYER M1 ;
			RECT 0.8 4.83 1.08 4.92 ;
			LAYER M1 ;
			RECT 0.8 4.64 1.555 4.83 ;
			LAYER M1 ;
			RECT 1.36 2.98 1.555 4.64 ;
			LAYER M1 ;
			RECT 1.36 2.6 1.74 2.98 ;
			LAYER M1 ;
			RECT 0.83 1.065 1.11 1.08 ;
			LAYER M1 ;
			RECT 1.36 1.065 1.555 2.6 ;
			LAYER M1 ;
			RECT 0.83 0.87 1.555 1.065 ;
			LAYER M1 ;
			RECT 0.83 0.8 1.11 0.87 ;
		END
		AntennaGateArea 0.1575 ;
		AntennaDiffArea 0.2765 ;
	END in
	OBS
		LAYER M1 ;
		RECT 0.23 3.5 0.51 3.535 ;
		LAYER M1 ;
		RECT 0.8 3.5 1.08 3.74 ;
		LAYER M1 ;
		RECT 0.23 3.46 1.08 3.5 ;
		LAYER M1 ;
		RECT 0.23 3.305 1.0 3.46 ;
		LAYER M1 ;
		RECT 0.23 3.255 0.51 3.305 ;
		LAYER M1 ;
		RECT 0.81 2.56 1.0 3.305 ;
		LAYER M1 ;
		RECT 0.81 2.285 1.11 2.56 ;
		LAYER M1 ;
		RECT 0.83 2.28 1.11 2.285 ;
	END
END MMI_KEEPW
MACRO MMI_LLACB
	CLASS CORE ;
	FOREIGN MMI_LLACB 0 0 ;
	SIZE 8.06 BY 6.2 ;
	SYMMETRY X Y ;
	SITE CORE1 ;
	PIN d
		DIRECTION input ;
		USE SIGNAL ;
		PORT
			LAYER M1 ;
			RECT 0.99 3.425 1.27 3.59 ;
			LAYER M1 ;
			RECT 0.99 3.235 1.62 3.425 ;
			LAYER M1 ;
			RECT 1.425 2.38 1.62 3.235 ;
			LAYER M1 ;
			RECT 1.34 2.355 1.62 2.38 ;
			LAYER M1 ;
			RECT 1.34 1.98 1.74 2.355 ;
		END
		AntennaGateArea 0.3465 ;
	END d
	PIN GND
		DIRECTION inout ;
		USE GROUND ;
		PORT
			LAYER M1 ;
			RECT 0.795 0.42 1.075 1.59 ;
			LAYER M1 ;
			RECT 3.33 0.42 3.61 1.885 ;
			LAYER M1 ;
			RECT 4.51 1.85 4.79 1.885 ;
			LAYER M1 ;
			RECT 5.785 1.85 6.065 2.58 ;
			LAYER M1 ;
			RECT 4.51 1.57 6.065 1.85 ;
			LAYER M1 ;
			RECT 4.51 0.42 4.79 1.57 ;
			LAYER M1 ;
			RECT 7.555 0.42 7.835 2.385 ;
			LAYER M1 ;
			RECT 0.0 -0.42 8.06 0.42 ;
		END
	END GND
	PIN q
		DIRECTION output ;
		USE SIGNAL ;
		PORT
			LAYER M1 ;
			RECT 6.375 1.88 6.655 5.105 ;
		END
		AntennaDiffArea 0.91245 ;
	END q
	PIN VDD
		DIRECTION inout ;
		USE POWER ;
		PORT
			LAYER M1 ;
			RECT 0.0 5.78 8.06 6.62 ;
			LAYER M1 ;
			RECT 0.795 3.835 1.075 5.78 ;
			LAYER M1 ;
			RECT 3.575 4.145 3.855 5.78 ;
			LAYER M1 ;
			RECT 2.99 3.86 3.855 4.145 ;
			LAYER M1 ;
			RECT 3.575 3.635 3.855 3.86 ;
			LAYER M1 ;
			RECT 5.785 3.635 6.065 5.78 ;
			LAYER M1 ;
			RECT 7.555 3.52 7.835 5.78 ;
		END
	END VDD
	PIN clk
		DIRECTION input ;
		USE CLOCK ;
		PORT
			LAYER M1 ;
			RECT 0.735 2.305 1.12 2.355 ;
			LAYER M1 ;
			RECT 0.575 2.025 1.12 2.305 ;
			LAYER M1 ;
			RECT 0.735 1.98 1.12 2.025 ;
		END
		AntennaGateArea 0.34125 ;
	END clk
	PIN clrb
		DIRECTION input ;
		USE SIGNAL ;
		PORT
			LAYER M1 ;
			RECT 7.56 2.905 7.94 2.98 ;
			LAYER M1 ;
			RECT 7.445 2.625 7.94 2.905 ;
			LAYER M1 ;
			RECT 7.56 2.6 7.94 2.625 ;
		END
		AntennaGateArea 0.17325 ;
	END clrb
	OBS
		LAYER M1 ;
		RECT 0.16 3.835 0.44 4.535 ;
		LAYER M1 ;
		RECT 1.385 4.435 1.665 5.305 ;
		LAYER M1 ;
		RECT 1.385 3.835 1.67 4.435 ;
		LAYER M1 ;
		RECT 1.995 4.21 2.275 5.075 ;
		LAYER M1 ;
		RECT 1.995 4.015 2.6 4.21 ;
		LAYER M1 ;
		RECT 0.165 3.015 0.355 3.835 ;
		LAYER M1 ;
		RECT 1.475 3.815 1.67 3.835 ;
		LAYER M1 ;
		RECT 1.475 3.625 2.145 3.815 ;
		LAYER M1 ;
		RECT 0.165 2.99 1.195 3.015 ;
		LAYER M1 ;
		RECT 0.165 2.825 1.21 2.99 ;
		LAYER M1 ;
		RECT 0.165 1.59 0.355 2.825 ;
		LAYER M1 ;
		RECT 0.93 2.71 1.21 2.825 ;
		LAYER M1 ;
		RECT 1.95 1.77 2.145 3.625 ;
		LAYER M1 ;
		RECT 1.475 1.59 2.145 1.77 ;
		LAYER M1 ;
		RECT 0.16 1.275 0.44 1.59 ;
		LAYER M1 ;
		RECT 0.165 1.255 0.355 1.275 ;
		LAYER M1 ;
		RECT 1.385 1.575 2.145 1.59 ;
		LAYER M1 ;
		RECT 2.405 2.91 2.6 4.015 ;
		LAYER M1 ;
		RECT 4.535 3.635 4.815 5.105 ;
		LAYER M1 ;
		RECT 5.125 3.635 5.405 4.335 ;
		LAYER M1 ;
		RECT 4.57 3.415 4.765 3.635 ;
		LAYER M1 ;
		RECT 4.57 3.22 4.925 3.415 ;
		LAYER M1 ;
		RECT 4.73 3.13 4.925 3.22 ;
		LAYER M1 ;
		RECT 5.215 3.345 5.405 3.635 ;
		LAYER M1 ;
		RECT 5.895 3.345 6.175 3.435 ;
		LAYER M1 ;
		RECT 5.215 3.155 6.175 3.345 ;
		LAYER M1 ;
		RECT 5.215 3.15 6.05 3.155 ;
		LAYER M1 ;
		RECT 4.115 2.91 4.395 2.96 ;
		LAYER M1 ;
		RECT 2.405 2.715 4.395 2.91 ;
		LAYER M1 ;
		RECT 1.385 0.89 1.665 1.575 ;
		LAYER M1 ;
		RECT 2.405 1.375 2.6 2.715 ;
		LAYER M1 ;
		RECT 4.115 2.68 4.395 2.715 ;
		LAYER M1 ;
		RECT 4.73 2.85 5.015 3.13 ;
		LAYER M1 ;
		RECT 2.81 2.42 3.09 2.47 ;
		LAYER M1 ;
		RECT 4.73 2.42 4.925 2.85 ;
		LAYER M1 ;
		RECT 5.215 2.585 5.405 3.15 ;
		LAYER M1 ;
		RECT 2.81 2.23 4.925 2.42 ;
		LAYER M1 ;
		RECT 5.125 2.27 5.405 2.585 ;
		LAYER M1 ;
		RECT 2.81 2.19 3.09 2.23 ;
		LAYER M1 ;
		RECT 3.975 1.885 4.17 2.23 ;
		LAYER M1 ;
		RECT 1.995 1.18 2.6 1.375 ;
		LAYER M1 ;
		RECT 1.995 1.095 2.275 1.18 ;
		LAYER M1 ;
		RECT 3.92 1.57 4.2 1.885 ;
		LAYER M1 ;
		RECT 6.965 3.52 7.245 4.22 ;
		LAYER M1 ;
		RECT 7.05 2.385 7.24 3.52 ;
		LAYER M1 ;
		RECT 6.965 2.07 7.245 2.385 ;
		LAYER M1 ;
		RECT 7.05 1.065 7.24 2.07 ;
		LAYER M1 ;
		RECT 5.04 0.875 7.24 1.065 ;
		LAYER M1 ;
		RECT 5.04 0.785 5.32 0.875 ;
	END
END MMI_LLACB
MACRO MMI_LLCB
	CLASS CORE ;
	FOREIGN MMI_LLCB 0 0 ;
	SIZE 8.06 BY 6.2 ;
	SYMMETRY X Y ;
	SITE CORE1 ;
	PIN d
		DIRECTION input ;
		USE SIGNAL ;
		PORT
			LAYER M1 ;
			RECT 0.74 3.545 1.12 3.6 ;
			LAYER M1 ;
			RECT 0.74 3.265 1.235 3.545 ;
			LAYER M1 ;
			RECT 0.74 3.22 1.12 3.265 ;
		END
		AntennaGateArea 0.3465 ;
	END d
	PIN GND
		DIRECTION inout ;
		USE GROUND ;
		PORT
			LAYER M1 ;
			RECT 3.33 1.85 3.61 1.885 ;
			LAYER M1 ;
			RECT 0.795 0.42 1.075 1.595 ;
			LAYER M1 ;
			RECT 3.3 1.57 3.61 1.85 ;
			LAYER M1 ;
			RECT 4.51 1.84 4.79 1.885 ;
			LAYER M1 ;
			RECT 5.74 1.84 6.02 2.56 ;
			LAYER M1 ;
			RECT 3.3 0.42 3.58 1.57 ;
			LAYER M1 ;
			RECT 4.51 1.56 6.02 1.84 ;
			LAYER M1 ;
			RECT 4.51 0.42 4.79 1.56 ;
			LAYER M1 ;
			RECT 7.52 0.42 7.8 2.355 ;
			LAYER M1 ;
			RECT 0.0 -0.42 8.06 0.42 ;
		END
	END GND
	PIN q
		DIRECTION output ;
		USE SIGNAL ;
		PORT
			LAYER M1 ;
			RECT 6.33 3.92 6.61 5.105 ;
			LAYER M1 ;
			RECT 6.33 3.635 6.635 3.92 ;
			LAYER M1 ;
			RECT 6.35 2.56 6.635 3.635 ;
			LAYER M1 ;
			RECT 6.33 2.41 6.635 2.56 ;
			LAYER M1 ;
			RECT 6.33 1.86 6.61 2.41 ;
		END
		AntennaDiffArea 0.91245 ;
	END q
	PIN VDD
		DIRECTION inout ;
		USE POWER ;
		PORT
			LAYER M1 ;
			RECT 0.0 5.78 8.06 6.62 ;
			LAYER M1 ;
			RECT 0.795 3.8 1.075 5.78 ;
			LAYER M1 ;
			RECT 3.55 4.085 3.83 5.78 ;
			LAYER M1 ;
			RECT 2.99 3.8 3.83 4.085 ;
			LAYER M1 ;
			RECT 3.55 3.635 3.83 3.8 ;
			LAYER M1 ;
			RECT 5.74 3.635 6.02 5.78 ;
			LAYER M1 ;
			RECT 7.52 3.52 7.8 5.78 ;
		END
	END VDD
	PIN clk
		DIRECTION input ;
		USE CLOCK ;
		PORT
			LAYER M1 ;
			RECT 1.595 2.98 1.875 3.065 ;
			LAYER M1 ;
			RECT 0.74 2.94 1.875 2.98 ;
			LAYER M1 ;
			RECT 0.62 2.785 1.875 2.94 ;
			LAYER M1 ;
			RECT 0.62 2.66 1.12 2.785 ;
			LAYER M1 ;
			RECT 0.74 2.6 1.12 2.66 ;
		END
		AntennaGateArea 0.45675 ;
	END clk
	PIN clrb
		DIRECTION input ;
		USE SIGNAL ;
		PORT
			LAYER M1 ;
			RECT 7.535 2.905 7.915 2.985 ;
			LAYER M1 ;
			RECT 7.415 2.625 7.915 2.905 ;
			LAYER M1 ;
			RECT 7.535 2.61 7.915 2.625 ;
		END
		AntennaGateArea 0.17325 ;
	END clrb
	OBS
		LAYER M1 ;
		RECT 0.16 4.25 0.44 4.5 ;
		LAYER M1 ;
		RECT 0.15 3.8 0.44 4.25 ;
		LAYER M1 ;
		RECT 1.385 4.085 1.665 5.27 ;
		LAYER M1 ;
		RECT 1.385 3.8 1.675 4.085 ;
		LAYER M1 ;
		RECT 1.975 4.0 2.255 5.27 ;
		LAYER M1 ;
		RECT 1.975 3.805 2.76 4.0 ;
		LAYER M1 ;
		RECT 1.975 3.8 2.255 3.805 ;
		LAYER M1 ;
		RECT 0.15 2.4 0.345 3.8 ;
		LAYER M1 ;
		RECT 1.485 3.6 1.675 3.8 ;
		LAYER M1 ;
		RECT 1.485 3.405 2.37 3.6 ;
		LAYER M1 ;
		RECT 1.695 2.4 1.975 2.485 ;
		LAYER M1 ;
		RECT 0.15 2.205 1.975 2.4 ;
		LAYER M1 ;
		RECT 0.15 1.595 0.345 2.205 ;
		LAYER M1 ;
		RECT 2.18 2.005 2.37 3.405 ;
		LAYER M1 ;
		RECT 1.47 1.81 2.37 2.005 ;
		LAYER M1 ;
		RECT 2.57 2.91 2.76 3.805 ;
		LAYER M1 ;
		RECT 4.51 3.635 4.79 5.105 ;
		LAYER M1 ;
		RECT 5.105 3.635 5.385 4.335 ;
		LAYER M1 ;
		RECT 4.545 3.415 4.74 3.635 ;
		LAYER M1 ;
		RECT 4.545 3.22 4.9 3.415 ;
		LAYER M1 ;
		RECT 4.705 3.13 4.9 3.22 ;
		LAYER M1 ;
		RECT 5.19 3.275 5.38 3.635 ;
		LAYER M1 ;
		RECT 5.87 3.275 6.15 3.31 ;
		LAYER M1 ;
		RECT 4.1 2.91 4.38 2.96 ;
		LAYER M1 ;
		RECT 2.57 2.715 4.38 2.91 ;
		LAYER M1 ;
		RECT 1.47 1.595 1.66 1.81 ;
		LAYER M1 ;
		RECT 0.15 1.365 0.44 1.595 ;
		LAYER M1 ;
		RECT 0.16 1.28 0.44 1.365 ;
		LAYER M1 ;
		RECT 1.385 0.895 1.665 1.595 ;
		LAYER M1 ;
		RECT 1.975 1.57 2.255 1.595 ;
		LAYER M1 ;
		RECT 2.57 1.57 2.76 2.715 ;
		LAYER M1 ;
		RECT 4.1 2.68 4.38 2.715 ;
		LAYER M1 ;
		RECT 4.705 2.85 4.99 3.13 ;
		LAYER M1 ;
		RECT 5.19 3.085 6.15 3.275 ;
		LAYER M1 ;
		RECT 2.96 2.42 3.24 2.48 ;
		LAYER M1 ;
		RECT 4.705 2.42 4.9 2.85 ;
		LAYER M1 ;
		RECT 5.19 2.565 5.38 3.085 ;
		LAYER M1 ;
		RECT 5.87 3.03 6.15 3.085 ;
		LAYER M1 ;
		RECT 2.96 2.23 4.9 2.42 ;
		LAYER M1 ;
		RECT 5.105 2.25 5.385 2.565 ;
		LAYER M1 ;
		RECT 6.93 3.52 7.21 4.22 ;
		LAYER M1 ;
		RECT 2.96 2.2 3.24 2.23 ;
		LAYER M1 ;
		RECT 3.95 1.885 4.145 2.23 ;
		LAYER M1 ;
		RECT 1.975 1.38 2.76 1.57 ;
		LAYER M1 ;
		RECT 3.92 1.57 4.2 1.885 ;
		LAYER M1 ;
		RECT 7.015 2.355 7.205 3.52 ;
		LAYER M1 ;
		RECT 6.93 2.04 7.21 2.355 ;
		LAYER M1 ;
		RECT 1.975 0.895 2.255 1.38 ;
		LAYER M1 ;
		RECT 5.02 1.035 5.3 1.065 ;
		LAYER M1 ;
		RECT 5.02 1.02 5.305 1.035 ;
		LAYER M1 ;
		RECT 7.015 1.02 7.205 2.04 ;
		LAYER M1 ;
		RECT 5.02 0.83 7.205 1.02 ;
		LAYER M1 ;
		RECT 5.02 0.785 5.3 0.83 ;
	END
END MMI_LLCB
MACRO MMI_LTCHNB
	CLASS CORE ;
	FOREIGN MMI_LTCHNB 0 0 ;
	SIZE 5.58 BY 6.2 ;
	SYMMETRY X Y ;
	SITE CORE1 ;
	PIN d
		DIRECTION input ;
		USE SIGNAL ;
		PORT
			LAYER M1 ;
			RECT 0.74 3.545 1.12 3.6 ;
			LAYER M1 ;
			RECT 0.74 3.265 1.235 3.545 ;
			LAYER M1 ;
			RECT 0.74 3.22 1.12 3.265 ;
		END
		AntennaGateArea 0.3465 ;
	END d
	PIN GND
		DIRECTION inout ;
		USE GROUND ;
		PORT
			LAYER M1 ;
			RECT 0.795 0.42 1.075 1.59 ;
			LAYER M1 ;
			RECT 3.04 0.42 3.32 1.875 ;
			LAYER M1 ;
			RECT 4.225 0.42 4.505 2.38 ;
			LAYER M1 ;
			RECT 0.0 -0.42 5.58 0.42 ;
		END
	END GND
	PIN q
		DIRECTION output ;
		USE SIGNAL ;
		PORT
			LAYER M1 ;
			RECT 4.825 3.505 5.105 4.975 ;
			LAYER M1 ;
			RECT 4.83 2.98 5.02 3.505 ;
			LAYER M1 ;
			RECT 4.46 2.6 5.02 2.98 ;
			LAYER M1 ;
			RECT 4.83 2.38 5.02 2.6 ;
			LAYER M1 ;
			RECT 4.815 1.68 5.095 2.38 ;
		END
		AntennaDiffArea 0.91245 ;
	END q
	PIN VDD
		DIRECTION inout ;
		USE POWER ;
		PORT
			LAYER M1 ;
			RECT 0.0 5.78 5.58 6.62 ;
			LAYER M1 ;
			RECT 0.795 4.105 1.075 5.78 ;
			LAYER M1 ;
			RECT 3.0 4.105 3.28 5.78 ;
			LAYER M1 ;
			RECT 4.235 3.505 4.515 5.78 ;
		END
	END VDD
	PIN clk
		DIRECTION input ;
		USE CLOCK ;
		PORT
			LAYER M1 ;
			RECT 1.595 2.98 1.875 3.065 ;
			LAYER M1 ;
			RECT 0.74 2.94 1.875 2.98 ;
			LAYER M1 ;
			RECT 0.62 2.785 1.875 2.94 ;
			LAYER M1 ;
			RECT 0.62 2.66 1.12 2.785 ;
			LAYER M1 ;
			RECT 0.74 2.6 1.12 2.66 ;
		END
		AntennaGateArea 0.45675 ;
	END clk
	OBS
		LAYER M1 ;
		RECT 0.16 4.565 0.44 4.805 ;
		LAYER M1 ;
		RECT 0.15 4.105 0.44 4.565 ;
		LAYER M1 ;
		RECT 1.385 4.4 1.665 5.575 ;
		LAYER M1 ;
		RECT 1.385 4.105 1.675 4.4 ;
		LAYER M1 ;
		RECT 1.975 4.295 2.255 5.575 ;
		LAYER M1 ;
		RECT 1.975 4.105 2.765 4.295 ;
		LAYER M1 ;
		RECT 0.15 2.395 0.345 4.105 ;
		LAYER M1 ;
		RECT 1.485 3.9 1.675 4.105 ;
		LAYER M1 ;
		RECT 1.485 3.71 2.37 3.9 ;
		LAYER M1 ;
		RECT 1.695 2.395 1.975 2.48 ;
		LAYER M1 ;
		RECT 0.15 2.2 1.975 2.395 ;
		LAYER M1 ;
		RECT 0.15 1.59 0.345 2.2 ;
		LAYER M1 ;
		RECT 2.18 1.995 2.37 3.71 ;
		LAYER M1 ;
		RECT 1.47 1.8 2.37 1.995 ;
		LAYER M1 ;
		RECT 2.575 3.265 2.765 4.105 ;
		LAYER M1 ;
		RECT 3.595 3.505 3.875 4.205 ;
		LAYER M1 ;
		RECT 3.185 3.265 3.465 3.295 ;
		LAYER M1 ;
		RECT 2.575 3.07 3.465 3.265 ;
		LAYER M1 ;
		RECT 1.47 1.59 1.66 1.8 ;
		LAYER M1 ;
		RECT 0.15 1.365 0.44 1.59 ;
		LAYER M1 ;
		RECT 0.16 1.275 0.44 1.365 ;
		LAYER M1 ;
		RECT 1.385 0.89 1.665 1.59 ;
		LAYER M1 ;
		RECT 1.975 1.57 2.255 1.59 ;
		LAYER M1 ;
		RECT 2.575 1.57 2.765 3.07 ;
		LAYER M1 ;
		RECT 3.185 3.015 3.465 3.07 ;
		LAYER M1 ;
		RECT 3.175 2.635 3.455 2.685 ;
		LAYER M1 ;
		RECT 3.67 2.635 3.865 3.505 ;
		LAYER M1 ;
		RECT 3.175 2.445 3.865 2.635 ;
		LAYER M1 ;
		RECT 3.175 2.405 3.455 2.445 ;
		LAYER M1 ;
		RECT 3.67 1.875 3.865 2.445 ;
		LAYER M1 ;
		RECT 1.975 1.38 2.765 1.57 ;
		LAYER M1 ;
		RECT 1.975 0.89 2.255 1.38 ;
		LAYER M1 ;
		RECT 3.63 1.56 3.91 1.875 ;
	END
END MMI_LTCHNB
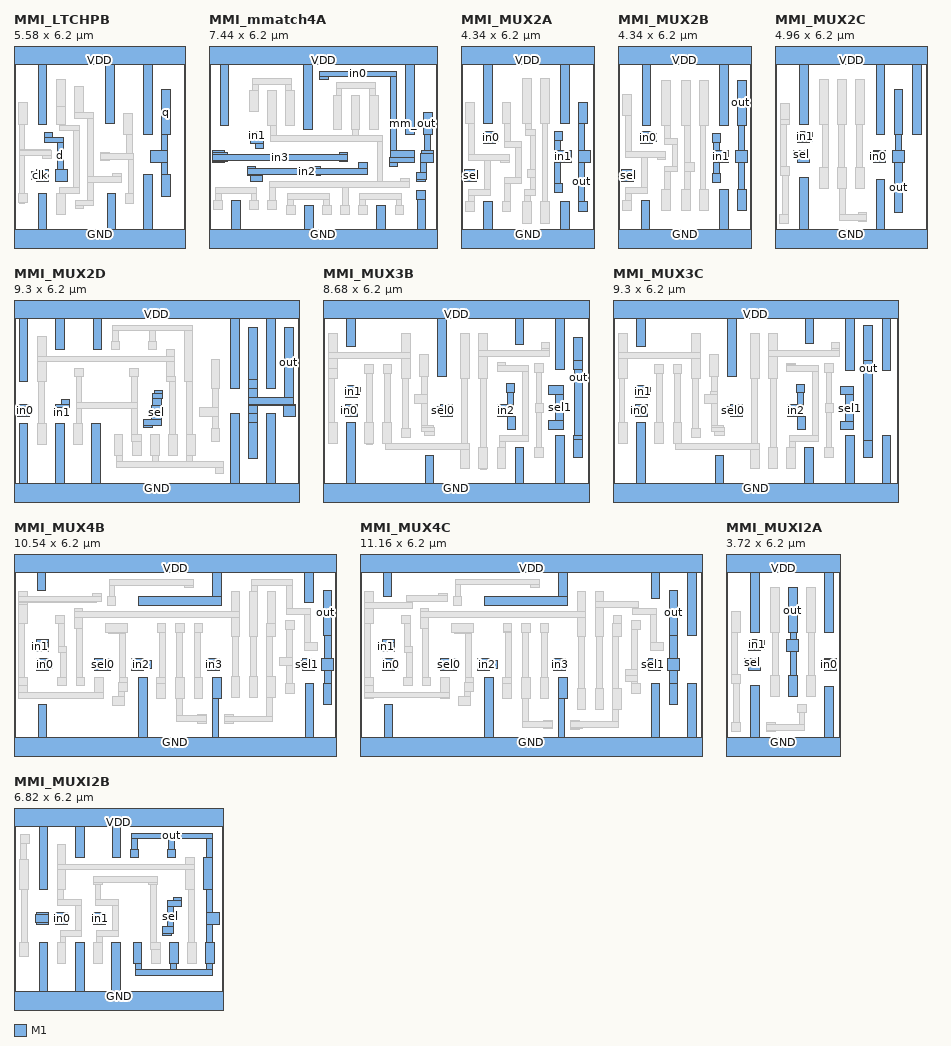
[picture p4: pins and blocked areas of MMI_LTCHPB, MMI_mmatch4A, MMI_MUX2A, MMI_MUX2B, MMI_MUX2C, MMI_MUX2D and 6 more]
MACRO MMI_LTCHPB
	CLASS CORE ;
	FOREIGN MMI_LTCHPB 0 0 ;
	SIZE 5.58 BY 6.2 ;
	SYMMETRY X Y ;
	SITE CORE1 ;
	PIN d
		DIRECTION input ;
		USE SIGNAL ;
		PORT
			LAYER M1 ;
			RECT 0.99 3.425 1.27 3.58 ;
			LAYER M1 ;
			RECT 0.99 3.235 1.605 3.425 ;
			LAYER M1 ;
			RECT 1.41 2.38 1.605 3.235 ;
			LAYER M1 ;
			RECT 1.34 2.355 1.62 2.38 ;
			LAYER M1 ;
			RECT 1.34 1.98 1.74 2.355 ;
		END
		AntennaGateArea 0.3465 ;
	END d
	PIN GND
		DIRECTION inout ;
		USE GROUND ;
		PORT
			LAYER M1 ;
			RECT 0.795 0.42 1.075 1.59 ;
			LAYER M1 ;
			RECT 3.035 0.42 3.315 1.57 ;
			LAYER M1 ;
			RECT 4.225 0.42 4.505 2.195 ;
			LAYER M1 ;
			RECT 0.0 -0.42 5.58 0.42 ;
		END
	END GND
	PIN q
		DIRECTION output ;
		USE SIGNAL ;
		PORT
			LAYER M1 ;
			RECT 4.815 3.505 5.095 4.975 ;
			LAYER M1 ;
			RECT 4.82 2.98 5.01 3.505 ;
			LAYER M1 ;
			RECT 4.46 2.6 5.01 2.98 ;
			LAYER M1 ;
			RECT 4.82 2.195 5.01 2.6 ;
			LAYER M1 ;
			RECT 4.815 1.495 5.095 2.195 ;
		END
		AntennaDiffArea 0.91245 ;
	END q
	PIN VDD
		DIRECTION inout ;
		USE POWER ;
		PORT
			LAYER M1 ;
			RECT 0.0 5.78 5.58 6.62 ;
			LAYER M1 ;
			RECT 0.795 3.84 1.075 5.78 ;
			LAYER M1 ;
			RECT 2.995 3.86 3.275 5.78 ;
			LAYER M1 ;
			RECT 4.225 3.505 4.505 5.78 ;
		END
	END VDD
	PIN clk
		DIRECTION input ;
		USE CLOCK ;
		PORT
			LAYER M1 ;
			RECT 0.735 2.305 1.12 2.355 ;
			LAYER M1 ;
			RECT 0.575 2.025 1.12 2.305 ;
			LAYER M1 ;
			RECT 0.735 1.98 1.12 2.025 ;
		END
		AntennaGateArea 0.34125 ;
	END clk
	OBS
		LAYER M1 ;
		RECT 0.16 3.84 0.44 4.54 ;
		LAYER M1 ;
		RECT 1.385 4.435 1.665 5.31 ;
		LAYER M1 ;
		RECT 1.385 3.84 1.67 4.435 ;
		LAYER M1 ;
		RECT 1.98 4.21 2.26 5.075 ;
		LAYER M1 ;
		RECT 1.98 4.015 2.6 4.21 ;
		LAYER M1 ;
		RECT 0.165 3.015 0.355 3.84 ;
		LAYER M1 ;
		RECT 1.475 3.815 1.67 3.84 ;
		LAYER M1 ;
		RECT 1.475 3.625 2.145 3.815 ;
		LAYER M1 ;
		RECT 0.165 2.99 1.195 3.015 ;
		LAYER M1 ;
		RECT 0.165 2.825 1.21 2.99 ;
		LAYER M1 ;
		RECT 0.165 1.59 0.355 2.825 ;
		LAYER M1 ;
		RECT 0.93 2.71 1.21 2.825 ;
		LAYER M1 ;
		RECT 1.95 1.77 2.145 3.625 ;
		LAYER M1 ;
		RECT 1.475 1.59 2.145 1.77 ;
		LAYER M1 ;
		RECT 0.16 1.275 0.44 1.59 ;
		LAYER M1 ;
		RECT 0.165 1.255 0.355 1.275 ;
		LAYER M1 ;
		RECT 1.385 1.58 2.145 1.59 ;
		LAYER M1 ;
		RECT 2.405 2.135 2.6 4.015 ;
		LAYER M1 ;
		RECT 3.585 3.505 3.865 4.205 ;
		LAYER M1 ;
		RECT 2.825 2.885 3.105 2.925 ;
		LAYER M1 ;
		RECT 3.67 2.885 3.865 3.505 ;
		LAYER M1 ;
		RECT 2.825 2.695 3.915 2.885 ;
		LAYER M1 ;
		RECT 2.825 2.645 3.105 2.695 ;
		LAYER M1 ;
		RECT 3.23 2.135 3.51 2.22 ;
		LAYER M1 ;
		RECT 2.405 1.94 3.51 2.135 ;
		LAYER M1 ;
		RECT 1.385 0.89 1.665 1.58 ;
		LAYER M1 ;
		RECT 2.405 1.37 2.6 1.94 ;
		LAYER M1 ;
		RECT 3.72 1.57 3.915 2.695 ;
		LAYER M1 ;
		RECT 2.09 1.365 2.6 1.37 ;
		LAYER M1 ;
		RECT 1.995 1.175 2.6 1.365 ;
		LAYER M1 ;
		RECT 1.995 1.085 2.275 1.175 ;
		LAYER M1 ;
		RECT 3.625 1.255 3.915 1.57 ;
		LAYER M1 ;
		RECT 3.72 1.25 3.915 1.255 ;
	END
END MMI_LTCHPB
MACRO MMI_mmatch4A
	CLASS CORE ;
	FOREIGN MMI_mmatch4A 0 0 ;
	SIZE 7.44 BY 6.2 ;
	SYMMETRY X Y ;
	SITE CORE1 ;
	PIN in1
		DIRECTION input ;
		USE SIGNAL ;
		PORT
			LAYER M1 ;
			RECT 1.36 3.345 1.74 3.6 ;
			LAYER M1 ;
			RECT 1.36 3.22 1.785 3.345 ;
			LAYER M1 ;
			RECT 1.505 3.065 1.785 3.22 ;
		END
		AntennaGateArea 0.4755 ;
	END in1
	PIN GND
		DIRECTION inout ;
		USE GROUND ;
		PORT
			LAYER M1 ;
			RECT 6.76 1.395 7.075 1.675 ;
			LAYER M1 ;
			RECT 0.745 0.42 1.025 1.36 ;
			LAYER M1 ;
			RECT 3.12 0.42 3.4 1.2 ;
			LAYER M1 ;
			RECT 5.48 0.42 5.76 1.2 ;
			LAYER M1 ;
			RECT 6.795 0.42 7.075 1.395 ;
			LAYER M1 ;
			RECT 0.0 -0.42 7.44 0.42 ;
		END
	END GND
	PIN mm_out
		DIRECTION output ;
		USE SIGNAL ;
		PORT
			LAYER M1 ;
			RECT 7.005 3.52 7.285 4.22 ;
			LAYER M1 ;
			RECT 7.03 2.98 7.22 3.52 ;
			LAYER M1 ;
			RECT 6.94 2.89 7.32 2.98 ;
			LAYER M1 ;
			RECT 6.9 2.6 7.32 2.89 ;
			LAYER M1 ;
			RECT 6.9 2.265 7.09 2.6 ;
			LAYER M1 ;
			RECT 6.76 2.05 7.09 2.265 ;
			LAYER M1 ;
			RECT 6.76 1.985 7.075 2.05 ;
		END
		AntennaDiffArea 0.456225 ;
	END mm_out
	PIN in2
		DIRECTION input ;
		USE SIGNAL ;
		PORT
			LAYER M1 ;
			RECT 1.24 2.39 1.52 2.45 ;
			LAYER M1 ;
			RECT 3.355 2.39 3.635 2.465 ;
			LAYER M1 ;
			RECT 4.885 2.39 5.165 2.605 ;
			LAYER M1 ;
			RECT 1.24 2.2 5.165 2.39 ;
			LAYER M1 ;
			RECT 1.24 2.17 1.74 2.2 ;
			LAYER M1 ;
			RECT 3.355 2.185 3.635 2.2 ;
			LAYER M1 ;
			RECT 1.36 1.98 1.74 2.17 ;
		END
		AntennaGateArea 0.53325 ;
	END in2
	PIN VDD
		DIRECTION inout ;
		USE POWER ;
		PORT
			LAYER M1 ;
			RECT 0.0 5.78 7.44 6.62 ;
			LAYER M1 ;
			RECT 0.365 3.81 0.645 5.78 ;
			LAYER M1 ;
			RECT 3.095 3.66 3.375 5.78 ;
			LAYER M1 ;
			RECT 6.415 3.52 6.695 5.78 ;
		END
	END VDD
	PIN in3
		DIRECTION input ;
		USE SIGNAL ;
		PORT
			LAYER M1 ;
			RECT 0.12 2.905 0.5 2.98 ;
			LAYER M1 ;
			RECT 0.12 2.865 0.615 2.905 ;
			LAYER M1 ;
			RECT 4.245 2.865 4.525 2.905 ;
			LAYER M1 ;
			RECT 0.12 2.675 4.525 2.865 ;
			LAYER M1 ;
			RECT 0.12 2.625 0.615 2.675 ;
			LAYER M1 ;
			RECT 4.245 2.625 4.525 2.675 ;
			LAYER M1 ;
			RECT 0.12 2.6 0.5 2.625 ;
		END
		AntennaGateArea 0.4755 ;
	END in3
	PIN in0
		DIRECTION input ;
		USE SIGNAL ;
		PORT
			LAYER M1 ;
			RECT 3.605 5.39 6.125 5.58 ;
			LAYER M1 ;
			RECT 3.605 5.3 3.885 5.39 ;
			LAYER M1 ;
			RECT 5.935 2.98 6.125 5.39 ;
			LAYER M1 ;
			RECT 5.935 2.76 6.7 2.98 ;
			LAYER M1 ;
			RECT 5.875 2.6 6.7 2.76 ;
			LAYER M1 ;
			RECT 5.875 2.48 6.155 2.6 ;
		END
		AntennaGateArea 0.4755 ;
	END in0
	OBS
		LAYER M1 ;
		RECT 1.415 5.14 2.695 5.33 ;
		LAYER M1 ;
		RECT 1.415 4.94 1.605 5.14 ;
		LAYER M1 ;
		RECT 2.505 4.94 2.695 5.14 ;
		LAYER M1 ;
		RECT 1.325 4.27 1.605 4.94 ;
		LAYER M1 ;
		RECT 1.915 3.81 2.195 4.94 ;
		LAYER M1 ;
		RECT 2.505 3.81 2.785 4.94 ;
		LAYER M1 ;
		RECT 2.0 3.46 2.19 3.81 ;
		LAYER M1 ;
		RECT 4.145 5.0 5.425 5.19 ;
		LAYER M1 ;
		RECT 4.145 4.79 4.335 5.0 ;
		LAYER M1 ;
		RECT 5.235 4.79 5.425 5.0 ;
		LAYER M1 ;
		RECT 4.055 3.66 4.335 4.79 ;
		LAYER M1 ;
		RECT 4.645 3.66 4.925 4.79 ;
		LAYER M1 ;
		RECT 5.235 3.66 5.515 4.79 ;
		LAYER M1 ;
		RECT 4.685 3.46 4.875 3.66 ;
		LAYER M1 ;
		RECT 2.0 3.27 5.675 3.46 ;
		LAYER M1 ;
		RECT 5.485 1.98 5.675 3.27 ;
		LAYER M1 ;
		RECT 6.255 1.98 6.535 2.07 ;
		LAYER M1 ;
		RECT 1.965 1.79 6.535 1.98 ;
		LAYER M1 ;
		RECT 0.215 1.58 1.565 1.77 ;
		LAYER M1 ;
		RECT 0.215 1.36 0.405 1.58 ;
		LAYER M1 ;
		RECT 1.375 1.36 1.565 1.58 ;
		LAYER M1 ;
		RECT 1.965 1.36 2.155 1.79 ;
		LAYER M1 ;
		RECT 2.57 1.4 3.94 1.59 ;
		LAYER M1 ;
		RECT 0.155 1.045 0.435 1.36 ;
		LAYER M1 ;
		RECT 1.335 1.045 1.615 1.36 ;
		LAYER M1 ;
		RECT 1.925 1.045 2.205 1.36 ;
		LAYER M1 ;
		RECT 2.57 1.2 2.76 1.4 ;
		LAYER M1 ;
		RECT 3.75 1.2 3.94 1.4 ;
		LAYER M1 ;
		RECT 4.35 1.2 4.54 1.79 ;
		LAYER M1 ;
		RECT 4.925 1.4 6.295 1.59 ;
		LAYER M1 ;
		RECT 4.925 1.2 5.115 1.4 ;
		LAYER M1 ;
		RECT 6.105 1.2 6.295 1.4 ;
		LAYER M1 ;
		RECT 2.53 0.885 2.81 1.2 ;
		LAYER M1 ;
		RECT 3.71 0.885 3.99 1.2 ;
		LAYER M1 ;
		RECT 4.3 0.885 4.58 1.2 ;
		LAYER M1 ;
		RECT 4.89 0.885 5.17 1.2 ;
		LAYER M1 ;
		RECT 6.07 0.885 6.35 1.2 ;
	END
END MMI_mmatch4A
MACRO MMI_MUX2A
	CLASS CORE ;
	FOREIGN MMI_MUX2A 0 0 ;
	SIZE 4.34 BY 6.2 ;
	SYMMETRY X Y ;
	SITE CORE1 ;
	PIN out
		DIRECTION output ;
		USE SIGNAL ;
		PORT
			LAYER M1 ;
			RECT 3.835 3.855 4.115 4.555 ;
			LAYER M1 ;
			RECT 3.84 2.98 4.03 3.855 ;
			LAYER M1 ;
			RECT 3.84 2.6 4.22 2.98 ;
			LAYER M1 ;
			RECT 3.84 1.32 4.03 2.6 ;
			LAYER M1 ;
			RECT 3.835 1.005 4.115 1.32 ;
		END
		AntennaDiffArea 0.456225 ;
	END out
	PIN sel
		DIRECTION input ;
		USE SIGNAL ;
		PORT
			LAYER M1 ;
			RECT 0.12 1.98 0.5 2.36 ;
		END
		AntennaGateArea 0.40425 ;
	END sel
	PIN in1
		DIRECTION input ;
		USE SIGNAL ;
		PORT
			LAYER M1 ;
			RECT 3.035 3.32 3.315 3.6 ;
			LAYER M1 ;
			RECT 3.06 2.98 3.25 3.32 ;
			LAYER M1 ;
			RECT 3.06 2.6 3.6 2.98 ;
			LAYER M1 ;
			RECT 3.06 1.91 3.25 2.6 ;
			LAYER M1 ;
			RECT 3.035 1.63 3.315 1.91 ;
		END
		AntennaGateArea 0.17325 ;
	END in1
	PIN GND
		DIRECTION inout ;
		USE GROUND ;
		PORT
			LAYER M1 ;
			RECT 0.75 0.42 1.03 1.32 ;
			LAYER M1 ;
			RECT 3.245 0.42 3.525 1.32 ;
			LAYER M1 ;
			RECT 0.0 -0.42 4.34 0.42 ;
		END
	END GND
	PIN VDD
		DIRECTION inout ;
		USE POWER ;
		PORT
			LAYER M1 ;
			RECT 0.0 5.78 4.34 6.62 ;
			LAYER M1 ;
			RECT 0.75 3.855 1.03 5.78 ;
			LAYER M1 ;
			RECT 3.245 3.855 3.525 5.78 ;
		END
	END VDD
	PIN in0
		DIRECTION input ;
		USE SIGNAL ;
		PORT
			LAYER M1 ;
			RECT 0.74 3.555 1.12 3.6 ;
			LAYER M1 ;
			RECT 0.74 3.275 1.225 3.555 ;
			LAYER M1 ;
			RECT 0.74 3.22 1.12 3.275 ;
		END
		AntennaGateArea 0.17325 ;
	END in0
	OBS
		LAYER M1 ;
		RECT 0.155 3.855 0.435 4.555 ;
		LAYER M1 ;
		RECT 1.34 3.855 1.62 4.555 ;
		LAYER M1 ;
		RECT 2.005 3.855 2.285 5.325 ;
		LAYER M1 ;
		RECT 2.595 3.855 2.875 5.325 ;
		LAYER M1 ;
		RECT 0.245 2.87 0.435 3.855 ;
		LAYER M1 ;
		RECT 1.425 3.265 1.615 3.855 ;
		LAYER M1 ;
		RECT 2.09 3.655 2.285 3.855 ;
		LAYER M1 ;
		RECT 2.09 3.465 2.445 3.655 ;
		LAYER M1 ;
		RECT 1.425 3.075 1.96 3.265 ;
		LAYER M1 ;
		RECT 0.245 2.675 1.57 2.87 ;
		LAYER M1 ;
		RECT 0.775 1.715 0.97 2.675 ;
		LAYER M1 ;
		RECT 1.29 2.59 1.57 2.675 ;
		LAYER M1 ;
		RECT 1.77 2.11 1.96 3.075 ;
		LAYER M1 ;
		RECT 2.255 2.375 2.445 3.465 ;
		LAYER M1 ;
		RECT 0.245 1.52 0.97 1.715 ;
		LAYER M1 ;
		RECT 1.425 1.92 1.96 2.11 ;
		LAYER M1 ;
		RECT 2.165 2.095 2.445 2.375 ;
		LAYER M1 ;
		RECT 0.245 1.32 0.435 1.52 ;
		LAYER M1 ;
		RECT 1.425 1.32 1.615 1.92 ;
		LAYER M1 ;
		RECT 2.255 1.71 2.445 2.095 ;
		LAYER M1 ;
		RECT 2.085 1.52 2.445 1.71 ;
		LAYER M1 ;
		RECT 2.085 1.32 2.28 1.52 ;
		LAYER M1 ;
		RECT 2.645 1.32 2.835 3.855 ;
		LAYER M1 ;
		RECT 0.155 1.005 0.435 1.32 ;
		LAYER M1 ;
		RECT 1.34 1.005 1.62 1.32 ;
		LAYER M1 ;
		RECT 2.005 0.62 2.285 1.32 ;
		LAYER M1 ;
		RECT 2.595 0.62 2.875 1.32 ;
	END
END MMI_MUX2A
MACRO MMI_MUX2B
	CLASS CORE ;
	FOREIGN MMI_MUX2B 0 0 ;
	SIZE 4.34 BY 6.2 ;
	SYMMETRY X Y ;
	SITE CORE1 ;
	PIN out
		DIRECTION output ;
		USE SIGNAL ;
		PORT
			LAYER M1 ;
			RECT 3.9 3.815 4.18 5.285 ;
			LAYER M1 ;
			RECT 3.945 2.98 4.14 3.815 ;
			LAYER M1 ;
			RECT 3.84 2.6 4.22 2.98 ;
			LAYER M1 ;
			RECT 3.945 1.725 4.14 2.6 ;
			LAYER M1 ;
			RECT 3.9 1.025 4.18 1.725 ;
		END
		AntennaDiffArea 0.91245 ;
	END out
	PIN sel
		DIRECTION input ;
		USE SIGNAL ;
		PORT
			LAYER M1 ;
			RECT 0.12 1.98 0.5 2.36 ;
		END
		AntennaGateArea 0.51975 ;
	END sel
	PIN in1
		DIRECTION input ;
		USE SIGNAL ;
		PORT
			LAYER M1 ;
			RECT 3.07 3.26 3.35 3.54 ;
			LAYER M1 ;
			RECT 3.115 2.98 3.305 3.26 ;
			LAYER M1 ;
			RECT 3.115 2.6 3.6 2.98 ;
			LAYER M1 ;
			RECT 3.115 2.225 3.305 2.6 ;
			LAYER M1 ;
			RECT 3.07 1.945 3.35 2.225 ;
		END
		AntennaGateArea 0.3465 ;
	END in1
	PIN GND
		DIRECTION inout ;
		USE GROUND ;
		PORT
			LAYER M1 ;
			RECT 0.755 0.42 1.035 1.34 ;
			LAYER M1 ;
			RECT 3.31 0.42 3.59 1.725 ;
			LAYER M1 ;
			RECT 0.0 -0.42 4.34 0.42 ;
		END
	END GND
	PIN VDD
		DIRECTION inout ;
		USE POWER ;
		PORT
			LAYER M1 ;
			RECT 0.0 5.78 4.34 6.62 ;
			LAYER M1 ;
			RECT 0.795 3.815 1.075 5.78 ;
			LAYER M1 ;
			RECT 3.31 3.815 3.59 5.78 ;
		END
	END VDD
	PIN in0
		DIRECTION input ;
		USE SIGNAL ;
		PORT
			LAYER M1 ;
			RECT 0.74 3.555 1.12 3.6 ;
			LAYER M1 ;
			RECT 0.74 3.275 1.24 3.555 ;
			LAYER M1 ;
			RECT 0.74 3.22 1.12 3.275 ;
		END
		AntennaGateArea 0.3465 ;
	END in0
	OBS
		LAYER M1 ;
		RECT 0.16 4.12 0.44 4.82 ;
		LAYER M1 ;
		RECT 0.245 2.955 0.435 4.12 ;
		LAYER M1 ;
		RECT 1.435 3.815 1.715 5.285 ;
		LAYER M1 ;
		RECT 2.07 3.815 2.35 5.285 ;
		LAYER M1 ;
		RECT 2.66 3.815 2.94 5.285 ;
		LAYER M1 ;
		RECT 1.52 3.37 1.715 3.815 ;
		LAYER M1 ;
		RECT 1.52 3.175 1.955 3.37 ;
		LAYER M1 ;
		RECT 1.285 2.955 1.565 2.96 ;
		LAYER M1 ;
		RECT 0.245 2.76 1.565 2.955 ;
		LAYER M1 ;
		RECT 0.775 1.78 0.97 2.76 ;
		LAYER M1 ;
		RECT 1.285 2.68 1.565 2.76 ;
		LAYER M1 ;
		RECT 1.765 2.475 1.955 3.175 ;
		LAYER M1 ;
		RECT 0.245 1.585 0.97 1.78 ;
		LAYER M1 ;
		RECT 1.52 2.285 1.955 2.475 ;
		LAYER M1 ;
		RECT 2.16 2.59 2.35 3.815 ;
		LAYER M1 ;
		RECT 2.16 2.31 2.48 2.59 ;
		LAYER M1 ;
		RECT 1.52 1.725 1.715 2.285 ;
		LAYER M1 ;
		RECT 2.16 1.725 2.35 2.31 ;
		LAYER M1 ;
		RECT 2.68 1.725 2.87 3.815 ;
		LAYER M1 ;
		RECT 0.245 1.34 0.435 1.585 ;
		LAYER M1 ;
		RECT 0.16 1.025 0.44 1.34 ;
		LAYER M1 ;
		RECT 1.435 1.025 1.715 1.725 ;
		LAYER M1 ;
		RECT 2.07 1.025 2.35 1.725 ;
		LAYER M1 ;
		RECT 2.66 1.025 2.94 1.725 ;
	END
END MMI_MUX2B
MACRO MMI_MUX2C
	CLASS CORE ;
	FOREIGN MMI_MUX2C 0 0 ;
	SIZE 4.96 BY 6.2 ;
	SYMMETRY X Y ;
	SITE CORE1 ;
	PIN out
		DIRECTION output ;
		USE SIGNAL ;
		PORT
			LAYER M1 ;
			RECT 3.895 3.495 4.175 4.965 ;
			LAYER M1 ;
			RECT 3.93 2.98 4.125 3.495 ;
			LAYER M1 ;
			RECT 3.84 2.6 4.22 2.98 ;
			LAYER M1 ;
			RECT 3.895 0.975 4.175 2.6 ;
		END
		AntennaDiffArea 1.2859 ;
	END out
	PIN sel
		DIRECTION input ;
		USE SIGNAL ;
		PORT
			LAYER M1 ;
			RECT 0.595 2.98 0.875 2.99 ;
			LAYER M1 ;
			RECT 0.595 2.71 1.12 2.98 ;
			LAYER M1 ;
			RECT 0.745 2.6 1.12 2.71 ;
		END
		AntennaGateArea 0.51975 ;
	END sel
	PIN in1
		DIRECTION input ;
		USE SIGNAL ;
		PORT
			LAYER M1 ;
			RECT 0.745 3.57 1.125 3.615 ;
			LAYER M1 ;
			RECT 0.745 3.29 1.225 3.57 ;
			LAYER M1 ;
			RECT 0.745 3.24 1.125 3.29 ;
		END
		AntennaGateArea 0.34575 ;
	END in1
	PIN GND
		DIRECTION inout ;
		USE GROUND ;
		PORT
			LAYER M1 ;
			RECT 0.81 0.42 1.095 2.09 ;
			LAYER M1 ;
			RECT 3.305 0.42 3.585 2.035 ;
			LAYER M1 ;
			RECT 0.0 -0.42 4.96 0.42 ;
		END
	END GND
	PIN VDD
		DIRECTION inout ;
		USE POWER ;
		PORT
			LAYER M1 ;
			RECT 0.0 5.78 4.96 6.62 ;
			LAYER M1 ;
			RECT 0.815 3.835 1.095 5.78 ;
			LAYER M1 ;
			RECT 3.305 3.495 3.585 5.78 ;
			LAYER M1 ;
			RECT 4.485 3.495 4.765 5.78 ;
		END
	END VDD
	PIN in0
		DIRECTION input ;
		USE SIGNAL ;
		PORT
			LAYER M1 ;
			RECT 3.22 2.94 3.6 2.985 ;
			LAYER M1 ;
			RECT 3.13 2.66 3.6 2.94 ;
			LAYER M1 ;
			RECT 3.22 2.6 3.6 2.66 ;
		END
		AntennaGateArea 0.3465 ;
	END in0
	OBS
		LAYER M1 ;
		RECT 0.18 4.01 0.46 4.535 ;
		LAYER M1 ;
		RECT 0.175 3.835 0.46 4.01 ;
		LAYER M1 ;
		RECT 1.455 3.835 1.735 5.305 ;
		LAYER M1 ;
		RECT 2.045 3.835 2.325 5.305 ;
		LAYER M1 ;
		RECT 2.635 3.835 2.915 5.305 ;
		LAYER M1 ;
		RECT 0.175 2.47 0.37 3.835 ;
		LAYER M1 ;
		RECT 0.175 2.185 0.46 2.47 ;
		LAYER M1 ;
		RECT 1.54 2.445 1.73 3.835 ;
		LAYER M1 ;
		RECT 2.085 2.445 2.275 3.835 ;
		LAYER M1 ;
		RECT 2.675 2.445 2.865 3.835 ;
		LAYER M1 ;
		RECT 0.18 2.155 0.46 2.185 ;
		LAYER M1 ;
		RECT 0.23 0.9 0.425 2.155 ;
		LAYER M1 ;
		RECT 0.155 0.62 0.435 0.9 ;
		LAYER M1 ;
		RECT 1.455 1.745 1.735 2.445 ;
		LAYER M1 ;
		RECT 2.045 1.745 2.325 2.445 ;
		LAYER M1 ;
		RECT 2.635 1.745 2.915 2.445 ;
		LAYER M1 ;
		RECT 2.1 0.895 2.29 1.745 ;
		LAYER M1 ;
		RECT 2.72 0.895 3.0 0.95 ;
		LAYER M1 ;
		RECT 2.1 0.705 3.0 0.895 ;
		LAYER M1 ;
		RECT 2.72 0.67 3.0 0.705 ;
	END
END MMI_MUX2C
MACRO MMI_MUX2D
	CLASS CORE ;
	FOREIGN MMI_MUX2D 0 0 ;
	SIZE 9.3 BY 6.2 ;
	SYMMETRY X Y ;
	SITE CORE1 ;
	PIN out
		DIRECTION output ;
		USE SIGNAL ;
		PORT
			LAYER M1 ;
			RECT 7.655 3.815 7.935 5.485 ;
			LAYER M1 ;
			RECT 7.655 3.5 7.945 3.815 ;
			LAYER M1 ;
			RECT 7.66 3.225 7.945 3.5 ;
			LAYER M1 ;
			RECT 8.835 3.225 9.115 5.485 ;
			LAYER M1 ;
			RECT 7.66 2.98 9.115 3.225 ;
			LAYER M1 ;
			RECT 7.66 2.94 9.18 2.98 ;
			LAYER M1 ;
			RECT 7.66 2.68 7.945 2.94 ;
			LAYER M1 ;
			RECT 7.655 2.395 7.945 2.68 ;
			LAYER M1 ;
			RECT 8.8 2.6 9.18 2.94 ;
			LAYER M1 ;
			RECT 7.655 1.21 7.935 2.395 ;
		END
		AntennaDiffArea 2.393525 ;
	END out
	PIN sel
		DIRECTION input ;
		USE SIGNAL ;
		PORT
			LAYER M1 ;
			RECT 4.58 3.36 4.86 3.45 ;
			LAYER M1 ;
			RECT 4.525 3.17 4.86 3.36 ;
			LAYER M1 ;
			RECT 4.525 2.95 4.8 3.17 ;
			LAYER M1 ;
			RECT 4.49 2.51 4.8 2.95 ;
			LAYER M1 ;
			RECT 4.24 2.315 4.8 2.51 ;
			LAYER M1 ;
			RECT 4.24 2.23 4.52 2.315 ;
		END
		AntennaGateArea 0.927 ;
	END sel
	PIN in1
		DIRECTION input ;
		USE SIGNAL ;
		PORT
			LAYER M1 ;
			RECT 1.535 2.98 1.815 3.16 ;
			LAYER M1 ;
			RECT 1.36 2.88 1.815 2.98 ;
			LAYER M1 ;
			RECT 1.36 2.6 1.74 2.88 ;
		END
		AntennaGateArea 0.693 ;
	END in1
	PIN GND
		DIRECTION inout ;
		USE GROUND ;
		PORT
			LAYER M1 ;
			RECT 0.175 0.42 0.455 2.38 ;
			LAYER M1 ;
			RECT 1.355 0.42 1.635 2.38 ;
			LAYER M1 ;
			RECT 2.535 0.42 2.815 2.38 ;
			LAYER M1 ;
			RECT 7.065 0.42 7.345 2.68 ;
			LAYER M1 ;
			RECT 8.245 0.42 8.525 2.68 ;
			LAYER M1 ;
			RECT 0.0 -0.42 9.3 0.42 ;
		END
	END GND
	PIN VDD
		DIRECTION inout ;
		USE POWER ;
		PORT
			LAYER M1 ;
			RECT 0.0 5.78 9.3 6.62 ;
			LAYER M1 ;
			RECT 0.175 3.73 0.455 5.78 ;
			LAYER M1 ;
			RECT 1.355 4.77 1.635 5.78 ;
			LAYER M1 ;
			RECT 2.585 4.77 2.865 5.78 ;
			LAYER M1 ;
			RECT 7.065 3.5 7.345 5.78 ;
			LAYER M1 ;
			RECT 8.245 3.5 8.525 5.78 ;
		END
	END VDD
	PIN in0
		DIRECTION input ;
		USE SIGNAL ;
		PORT
			LAYER M1 ;
			RECT 0.12 2.93 0.5 2.98 ;
			LAYER M1 ;
			RECT 0.12 2.65 0.54 2.93 ;
			LAYER M1 ;
			RECT 0.12 2.6 0.5 2.65 ;
		END
		AntennaGateArea 0.693 ;
	END in0
	OBS
		LAYER M1 ;
		RECT 0.765 4.565 1.045 5.2 ;
		LAYER M1 ;
		RECT 3.21 5.385 5.84 5.58 ;
		LAYER M1 ;
		RECT 3.21 5.05 3.4 5.385 ;
		LAYER M1 ;
		RECT 3.175 4.77 3.455 5.05 ;
		LAYER M1 ;
		RECT 4.415 5.045 4.61 5.385 ;
		LAYER M1 ;
		RECT 4.375 4.765 4.655 5.045 ;
		LAYER M1 ;
		RECT 4.97 4.565 5.25 4.79 ;
		LAYER M1 ;
		RECT 0.765 4.375 5.25 4.565 ;
		LAYER M1 ;
		RECT 0.765 3.73 1.045 4.375 ;
		LAYER M1 ;
		RECT 1.98 3.89 2.26 4.17 ;
		LAYER M1 ;
		RECT 3.775 3.89 4.055 4.17 ;
		LAYER M1 ;
		RECT 4.97 3.9 5.25 4.375 ;
		LAYER M1 ;
		RECT 0.815 2.38 1.005 3.73 ;
		LAYER M1 ;
		RECT 2.025 3.045 2.215 3.89 ;
		LAYER M1 ;
		RECT 3.85 3.045 4.04 3.89 ;
		LAYER M1 ;
		RECT 4.97 3.73 5.255 3.9 ;
		LAYER M1 ;
		RECT 5.56 3.73 5.84 5.385 ;
		LAYER M1 ;
		RECT 2.025 2.855 4.04 3.045 ;
		LAYER M1 ;
		RECT 2.025 2.38 2.215 2.855 ;
		LAYER M1 ;
		RECT 0.765 1.68 1.045 2.38 ;
		LAYER M1 ;
		RECT 1.945 1.68 2.225 2.38 ;
		LAYER M1 ;
		RECT 3.85 2.02 4.04 2.855 ;
		LAYER M1 ;
		RECT 5.06 2.02 5.255 3.73 ;
		LAYER M1 ;
		RECT 5.645 2.02 5.84 3.73 ;
		LAYER M1 ;
		RECT 6.43 3.495 6.71 4.465 ;
		LAYER M1 ;
		RECT 6.475 2.885 6.665 3.495 ;
		LAYER M1 ;
		RECT 6.065 2.88 6.665 2.885 ;
		LAYER M1 ;
		RECT 6.055 2.6 6.665 2.88 ;
		LAYER M1 ;
		RECT 6.475 2.215 6.665 2.6 ;
		LAYER M1 ;
		RECT 3.275 1.32 3.555 2.02 ;
		LAYER M1 ;
		RECT 3.85 1.785 4.145 2.02 ;
		LAYER M1 ;
		RECT 3.865 1.32 4.145 1.785 ;
		LAYER M1 ;
		RECT 4.455 1.32 4.735 2.02 ;
		LAYER M1 ;
		RECT 5.055 1.32 5.335 2.02 ;
		LAYER M1 ;
		RECT 5.645 1.32 5.925 2.02 ;
		LAYER M1 ;
		RECT 6.43 1.765 6.71 2.215 ;
		LAYER M1 ;
		RECT 3.36 1.115 3.55 1.32 ;
		LAYER M1 ;
		RECT 4.51 1.115 4.7 1.32 ;
		LAYER M1 ;
		RECT 5.645 1.115 5.84 1.32 ;
		LAYER M1 ;
		RECT 3.36 0.925 6.845 1.115 ;
		LAYER M1 ;
		RECT 6.565 0.75 6.845 0.925 ;
	END
END MMI_MUX2D
MACRO MMI_MUX3B
	CLASS CORE ;
	FOREIGN MMI_MUX3B 0 0 ;
	SIZE 8.68 BY 6.2 ;
	SYMMETRY X Y ;
	SITE CORE1 ;
	PIN out
		DIRECTION output ;
		USE SIGNAL ;
		PORT
			LAYER M1 ;
			RECT 8.19 4.43 8.47 5.175 ;
			LAYER M1 ;
			RECT 8.19 4.115 8.48 4.43 ;
			LAYER M1 ;
			RECT 8.195 1.965 8.48 4.115 ;
			LAYER M1 ;
			RECT 8.19 1.835 8.48 1.965 ;
			LAYER M1 ;
			RECT 8.19 1.265 8.47 1.835 ;
		END
		AntennaDiffArea 0.91245 ;
	END out
	PIN in1
		DIRECTION input ;
		USE SIGNAL ;
		PORT
			LAYER M1 ;
			RECT 0.74 3.55 1.12 3.6 ;
			LAYER M1 ;
			RECT 0.74 3.27 1.23 3.55 ;
			LAYER M1 ;
			RECT 0.74 3.22 1.12 3.27 ;
		END
		AntennaGateArea 0.3465 ;
	END in1
	PIN sel0
		DIRECTION input ;
		USE SIGNAL ;
		PORT
			LAYER M1 ;
			RECT 3.84 2.93 4.22 2.98 ;
			LAYER M1 ;
			RECT 3.595 2.65 4.22 2.93 ;
			LAYER M1 ;
			RECT 3.84 2.6 4.22 2.65 ;
		END
		AntennaGateArea 0.51975 ;
	END sel0
	PIN GND
		DIRECTION inout ;
		USE GROUND ;
		PORT
			LAYER M1 ;
			RECT 0.775 0.42 1.055 2.4 ;
			LAYER M1 ;
			RECT 3.335 0.42 3.62 1.31 ;
			LAYER M1 ;
			RECT 6.27 0.42 6.55 1.585 ;
			LAYER M1 ;
			RECT 7.6 0.42 7.88 1.965 ;
			LAYER M1 ;
			RECT 0.0 -0.42 8.68 0.42 ;
		END
	END GND
	PIN in2
		DIRECTION input ;
		USE SIGNAL ;
		PORT
			LAYER M1 ;
			RECT 5.975 3.385 6.255 3.665 ;
			LAYER M1 ;
			RECT 6.03 2.975 6.22 3.385 ;
			LAYER M1 ;
			RECT 5.705 2.6 6.22 2.975 ;
			LAYER M1 ;
			RECT 6.005 2.18 6.285 2.6 ;
		END
		AntennaGateArea 0.3465 ;
	END in2
	PIN sel1
		DIRECTION input ;
		USE SIGNAL ;
		PORT
			LAYER M1 ;
			RECT 7.65 3.59 7.845 3.605 ;
			LAYER M1 ;
			RECT 7.37 3.31 7.845 3.59 ;
			LAYER M1 ;
			RECT 7.59 2.45 7.845 3.31 ;
			LAYER M1 ;
			RECT 7.37 2.17 7.845 2.45 ;
			LAYER M1 ;
			RECT 7.65 2.165 7.845 2.17 ;
		END
		AntennaGateArea 0.51975 ;
	END sel1
	PIN VDD
		DIRECTION inout ;
		USE POWER ;
		PORT
			LAYER M1 ;
			RECT 0.0 5.78 8.68 6.62 ;
			LAYER M1 ;
			RECT 0.775 4.88 1.055 5.78 ;
			LAYER M1 ;
			RECT 3.75 3.915 4.03 5.78 ;
			LAYER M1 ;
			RECT 6.275 4.96 6.555 5.78 ;
			LAYER M1 ;
			RECT 7.6 4.115 7.88 5.78 ;
		END
	END VDD
	PIN in0
		DIRECTION input ;
		USE SIGNAL ;
		PORT
			LAYER M1 ;
			RECT 0.74 2.93 1.12 2.98 ;
			LAYER M1 ;
			RECT 0.58 2.65 1.12 2.93 ;
			LAYER M1 ;
			RECT 0.74 2.6 1.12 2.65 ;
		END
		AntennaGateArea 0.3465 ;
	END in0
	OBS
		LAYER M1 ;
		RECT 0.185 4.675 0.465 5.315 ;
		LAYER M1 ;
		RECT 2.57 4.675 2.85 5.315 ;
		LAYER M1 ;
		RECT 0.185 4.485 2.85 4.675 ;
		LAYER M1 ;
		RECT 0.185 4.145 0.465 4.485 ;
		LAYER M1 ;
		RECT 0.17 3.845 0.465 4.145 ;
		LAYER M1 ;
		RECT 1.365 4.0 1.645 4.28 ;
		LAYER M1 ;
		RECT 1.965 4.0 2.245 4.28 ;
		LAYER M1 ;
		RECT 0.17 2.4 0.36 3.845 ;
		LAYER M1 ;
		RECT 1.43 2.4 1.62 4.0 ;
		LAYER M1 ;
		RECT 2.01 2.4 2.205 4.0 ;
		LAYER M1 ;
		RECT 2.57 3.845 2.85 4.485 ;
		LAYER M1 ;
		RECT 3.16 3.915 3.44 4.615 ;
		LAYER M1 ;
		RECT 0.17 1.71 0.465 2.4 ;
		LAYER M1 ;
		RECT 0.185 1.7 0.465 1.71 ;
		LAYER M1 ;
		RECT 1.365 1.7 1.645 2.4 ;
		LAYER M1 ;
		RECT 1.955 1.705 2.235 2.4 ;
		LAYER M1 ;
		RECT 2.595 2.195 2.785 3.845 ;
		LAYER M1 ;
		RECT 3.2 3.3 3.395 3.915 ;
		LAYER M1 ;
		RECT 4.5 3.835 4.78 5.305 ;
		LAYER M1 ;
		RECT 5.09 4.745 5.37 5.305 ;
		LAYER M1 ;
		RECT 7.115 4.81 7.395 5.0 ;
		LAYER M1 ;
		RECT 7.115 4.745 7.4 4.81 ;
		LAYER M1 ;
		RECT 5.09 4.55 7.4 4.745 ;
		LAYER M1 ;
		RECT 5.09 3.835 5.37 4.55 ;
		LAYER M1 ;
		RECT 5.68 4.265 5.96 4.345 ;
		LAYER M1 ;
		RECT 5.68 4.075 6.705 4.265 ;
		LAYER M1 ;
		RECT 5.68 4.065 5.96 4.075 ;
		LAYER M1 ;
		RECT 2.985 3.02 3.395 3.3 ;
		LAYER M1 ;
		RECT 3.2 2.285 3.395 3.02 ;
		LAYER M1 ;
		RECT 3.2 2.24 3.59 2.285 ;
		LAYER M1 ;
		RECT 2.56 1.915 2.84 2.195 ;
		LAYER M1 ;
		RECT 3.2 2.09 3.63 2.24 ;
		LAYER M1 ;
		RECT 3.315 1.96 3.63 2.09 ;
		LAYER M1 ;
		RECT 2.595 1.91 2.785 1.915 ;
		LAYER M1 ;
		RECT 4.53 1.705 4.72 3.835 ;
		LAYER M1 ;
		RECT 1.955 1.7 4.78 1.705 ;
		LAYER M1 ;
		RECT 1.43 1.67 1.62 1.7 ;
		LAYER M1 ;
		RECT 2.045 1.515 4.78 1.7 ;
		LAYER M1 ;
		RECT 5.125 1.585 5.32 3.835 ;
		LAYER M1 ;
		RECT 6.515 1.98 6.705 4.075 ;
		LAYER M1 ;
		RECT 6.91 4.045 7.19 4.325 ;
		LAYER M1 ;
		RECT 6.955 3.02 7.145 4.045 ;
		LAYER M1 ;
		RECT 6.93 2.74 7.21 3.02 ;
		LAYER M1 ;
		RECT 5.76 1.785 6.705 1.98 ;
		LAYER M1 ;
		RECT 5.76 1.585 5.955 1.785 ;
		LAYER M1 ;
		RECT 6.955 1.585 7.145 2.74 ;
		LAYER M1 ;
		RECT 4.5 0.885 4.78 1.515 ;
		LAYER M1 ;
		RECT 5.09 0.885 5.37 1.585 ;
		LAYER M1 ;
		RECT 5.68 0.885 5.96 1.585 ;
		LAYER M1 ;
		RECT 5.125 0.87 5.32 0.885 ;
		LAYER M1 ;
		RECT 6.905 1.27 7.185 1.585 ;
	END
END MMI_MUX3B
MACRO MMI_MUX3C
	CLASS CORE ;
	FOREIGN MMI_MUX3C 0 0 ;
	SIZE 9.3 BY 6.2 ;
	SYMMETRY X Y ;
	SITE CORE1 ;
	PIN out
		DIRECTION output ;
		USE SIGNAL ;
		PORT
			LAYER M1 ;
			RECT 8.19 4.43 8.47 5.575 ;
			LAYER M1 ;
			RECT 8.19 1.825 8.475 4.43 ;
			LAYER M1 ;
			RECT 8.19 1.26 8.47 1.825 ;
		END
		AntennaDiffArea 1.0164 ;
	END out
	PIN sel0
		DIRECTION input ;
		USE SIGNAL ;
		PORT
			LAYER M1 ;
			RECT 3.84 2.93 4.22 2.98 ;
			LAYER M1 ;
			RECT 3.595 2.65 4.22 2.93 ;
			LAYER M1 ;
			RECT 3.84 2.6 4.22 2.65 ;
		END
		AntennaGateArea 0.51975 ;
	END sel0
	PIN in1
		DIRECTION input ;
		USE SIGNAL ;
		PORT
			LAYER M1 ;
			RECT 0.74 3.55 1.12 3.6 ;
			LAYER M1 ;
			RECT 0.74 3.27 1.235 3.55 ;
			LAYER M1 ;
			RECT 0.74 3.22 1.12 3.27 ;
		END
		AntennaGateArea 0.3465 ;
	END in1
	PIN GND
		DIRECTION inout ;
		USE GROUND ;
		PORT
			LAYER M1 ;
			RECT 0.78 0.42 1.06 2.4 ;
			LAYER M1 ;
			RECT 3.335 0.42 3.62 1.31 ;
			LAYER M1 ;
			RECT 6.255 0.42 6.535 1.585 ;
			LAYER M1 ;
			RECT 7.6 0.42 7.88 1.96 ;
			LAYER M1 ;
			RECT 8.78 0.42 9.06 1.96 ;
			LAYER M1 ;
			RECT 0.0 -0.42 9.3 0.42 ;
		END
	END GND
	PIN in2
		DIRECTION input ;
		USE SIGNAL ;
		PORT
			LAYER M1 ;
			RECT 5.975 3.365 6.255 3.645 ;
			LAYER M1 ;
			RECT 6.03 2.975 6.22 3.365 ;
			LAYER M1 ;
			RECT 5.705 2.6 6.22 2.975 ;
			LAYER M1 ;
			RECT 6.005 2.185 6.285 2.6 ;
		END
		AntennaGateArea 0.3465 ;
	END in2
	PIN sel1
		DIRECTION input ;
		USE SIGNAL ;
		PORT
			LAYER M1 ;
			RECT 7.425 3.3 7.845 3.58 ;
			LAYER M1 ;
			RECT 7.59 2.44 7.845 3.3 ;
			LAYER M1 ;
			RECT 7.42 2.16 7.845 2.44 ;
		END
		AntennaGateArea 0.51975 ;
	END sel1
	PIN VDD
		DIRECTION inout ;
		USE POWER ;
		PORT
			LAYER M1 ;
			RECT 0.0 5.78 9.3 6.62 ;
			LAYER M1 ;
			RECT 0.78 4.88 1.06 5.78 ;
			LAYER M1 ;
			RECT 3.75 3.915 4.03 5.78 ;
			LAYER M1 ;
			RECT 6.275 4.965 6.555 5.78 ;
			LAYER M1 ;
			RECT 7.6 4.105 7.88 5.78 ;
			LAYER M1 ;
			RECT 8.78 4.105 9.06 5.78 ;
		END
	END VDD
	PIN in0
		DIRECTION input ;
		USE SIGNAL ;
		PORT
			LAYER M1 ;
			RECT 0.74 2.93 1.12 2.98 ;
			LAYER M1 ;
			RECT 0.595 2.65 1.12 2.93 ;
			LAYER M1 ;
			RECT 0.74 2.6 1.12 2.65 ;
		END
		AntennaGateArea 0.3465 ;
	END in0
	OBS
		LAYER M1 ;
		RECT 0.19 4.675 0.47 5.315 ;
		LAYER M1 ;
		RECT 2.57 4.675 2.85 5.315 ;
		LAYER M1 ;
		RECT 0.19 4.485 2.85 4.675 ;
		LAYER M1 ;
		RECT 0.19 3.845 0.47 4.485 ;
		LAYER M1 ;
		RECT 1.37 4.0 1.65 4.28 ;
		LAYER M1 ;
		RECT 1.965 4.0 2.245 4.28 ;
		LAYER M1 ;
		RECT 0.2 2.4 0.39 3.845 ;
		LAYER M1 ;
		RECT 1.435 2.4 1.625 4.0 ;
		LAYER M1 ;
		RECT 2.01 2.4 2.205 4.0 ;
		LAYER M1 ;
		RECT 2.57 3.845 2.85 4.485 ;
		LAYER M1 ;
		RECT 3.16 3.915 3.44 4.615 ;
		LAYER M1 ;
		RECT 0.19 1.7 0.47 2.4 ;
		LAYER M1 ;
		RECT 1.37 1.7 1.65 2.4 ;
		LAYER M1 ;
		RECT 1.96 1.705 2.24 2.4 ;
		LAYER M1 ;
		RECT 2.595 2.195 2.785 3.845 ;
		LAYER M1 ;
		RECT 3.2 3.415 3.395 3.915 ;
		LAYER M1 ;
		RECT 4.485 3.83 4.765 5.3 ;
		LAYER M1 ;
		RECT 5.075 4.74 5.355 5.3 ;
		LAYER M1 ;
		RECT 7.115 4.805 7.395 5.0 ;
		LAYER M1 ;
		RECT 7.115 4.74 7.4 4.805 ;
		LAYER M1 ;
		RECT 5.075 4.545 7.4 4.74 ;
		LAYER M1 ;
		RECT 5.075 3.83 5.355 4.545 ;
		LAYER M1 ;
		RECT 5.67 4.29 5.95 4.34 ;
		LAYER M1 ;
		RECT 5.67 4.26 5.955 4.29 ;
		LAYER M1 ;
		RECT 5.67 4.07 6.715 4.26 ;
		LAYER M1 ;
		RECT 5.67 4.06 5.95 4.07 ;
		LAYER M1 ;
		RECT 3.195 3.3 3.395 3.415 ;
		LAYER M1 ;
		RECT 2.985 3.02 3.395 3.3 ;
		LAYER M1 ;
		RECT 3.2 2.285 3.395 3.02 ;
		LAYER M1 ;
		RECT 3.2 2.24 3.59 2.285 ;
		LAYER M1 ;
		RECT 2.565 1.915 2.845 2.195 ;
		LAYER M1 ;
		RECT 3.2 2.09 3.63 2.24 ;
		LAYER M1 ;
		RECT 3.315 1.96 3.63 2.09 ;
		LAYER M1 ;
		RECT 2.595 1.91 2.785 1.915 ;
		LAYER M1 ;
		RECT 4.53 1.705 4.72 3.83 ;
		LAYER M1 ;
		RECT 1.96 1.7 4.765 1.705 ;
		LAYER M1 ;
		RECT 2.05 1.515 4.765 1.7 ;
		LAYER M1 ;
		RECT 5.125 1.585 5.32 3.83 ;
		LAYER M1 ;
		RECT 6.525 1.98 6.715 4.07 ;
		LAYER M1 ;
		RECT 6.915 4.04 7.195 4.32 ;
		LAYER M1 ;
		RECT 6.955 3.01 7.145 4.04 ;
		LAYER M1 ;
		RECT 6.93 2.73 7.21 3.01 ;
		LAYER M1 ;
		RECT 5.75 1.785 6.715 1.98 ;
		LAYER M1 ;
		RECT 5.75 1.585 5.945 1.785 ;
		LAYER M1 ;
		RECT 6.955 1.585 7.145 2.73 ;
		LAYER M1 ;
		RECT 4.485 0.885 4.765 1.515 ;
		LAYER M1 ;
		RECT 5.075 0.885 5.355 1.585 ;
		LAYER M1 ;
		RECT 5.665 0.885 5.945 1.585 ;
		LAYER M1 ;
		RECT 6.905 1.27 7.185 1.585 ;
	END
END MMI_MUX3C
MACRO MMI_MUX4B
	CLASS CORE ;
	FOREIGN MMI_MUX4B 0 0 ;
	SIZE 10.54 BY 6.2 ;
	SYMMETRY X Y ;
	SITE CORE1 ;
	PIN out
		DIRECTION output ;
		USE SIGNAL ;
		PORT
			LAYER M1 ;
			RECT 10.095 3.745 10.375 5.215 ;
			LAYER M1 ;
			RECT 10.13 2.98 10.37 3.745 ;
			LAYER M1 ;
			RECT 10.04 2.6 10.42 2.98 ;
			LAYER M1 ;
			RECT 10.13 2.17 10.37 2.6 ;
			LAYER M1 ;
			RECT 10.095 1.47 10.375 2.17 ;
		END
		AntennaDiffArea 0.91245 ;
	END out
	PIN sel0
		DIRECTION input ;
		USE SIGNAL ;
		PORT
			LAYER M1 ;
			RECT 2.64 2.595 3.145 2.985 ;
		END
		AntennaGateArea 0.927 ;
	END sel0
	PIN in1
		DIRECTION input ;
		USE SIGNAL ;
		PORT
			LAYER M1 ;
			RECT 0.74 3.52 1.12 3.6 ;
			LAYER M1 ;
			RECT 0.555 3.24 1.12 3.52 ;
			LAYER M1 ;
			RECT 0.74 3.22 1.12 3.24 ;
		END
		AntennaGateArea 0.3465 ;
	END in1
	PIN GND
		DIRECTION inout ;
		USE GROUND ;
		PORT
			LAYER M1 ;
			RECT 0.79 0.42 1.07 1.49 ;
			LAYER M1 ;
			RECT 4.075 0.42 4.355 2.37 ;
			LAYER M1 ;
			RECT 6.475 1.67 6.755 2.37 ;
			LAYER M1 ;
			RECT 6.475 0.42 6.665 1.67 ;
			LAYER M1 ;
			RECT 9.505 0.42 9.785 2.17 ;
			LAYER M1 ;
			RECT 0.0 -0.42 10.54 0.42 ;
		END
	END GND
	PIN in2
		DIRECTION input ;
		USE SIGNAL ;
		PORT
			LAYER M1 ;
			RECT 3.84 2.93 4.22 2.98 ;
			LAYER M1 ;
			RECT 3.84 2.65 4.48 2.93 ;
			LAYER M1 ;
			RECT 3.84 2.6 4.22 2.65 ;
		END
		AntennaGateArea 0.3465 ;
	END in2
	PIN sel1
		DIRECTION input ;
		USE SIGNAL ;
		PORT
			LAYER M1 ;
			RECT 9.425 2.93 9.8 2.98 ;
			LAYER M1 ;
			RECT 9.305 2.65 9.8 2.93 ;
			LAYER M1 ;
			RECT 9.425 2.6 9.8 2.65 ;
		END
		AntennaGateArea 0.51975 ;
	END sel1
	PIN VDD
		DIRECTION inout ;
		USE POWER ;
		PORT
			LAYER M1 ;
			RECT 0.0 5.78 10.54 6.62 ;
			LAYER M1 ;
			RECT 0.755 5.22 1.035 5.78 ;
			LAYER M1 ;
			RECT 6.48 5.0 6.765 5.78 ;
			LAYER M1 ;
			RECT 4.065 4.715 6.765 5.0 ;
			LAYER M1 ;
			RECT 9.495 4.815 9.775 5.78 ;
		END
	END VDD
	PIN in3
		DIRECTION input ;
		USE SIGNAL ;
		PORT
			LAYER M1 ;
			RECT 6.325 2.93 6.7 2.98 ;
			LAYER M1 ;
			RECT 6.325 2.65 6.71 2.93 ;
			LAYER M1 ;
			RECT 6.325 2.6 6.7 2.65 ;
		END
		AntennaGateArea 0.3465 ;
	END in3
	PIN in0
		DIRECTION input ;
		USE SIGNAL ;
		PORT
			LAYER M1 ;
			RECT 0.74 2.93 1.12 2.98 ;
			LAYER M1 ;
			RECT 0.74 2.65 1.265 2.93 ;
			LAYER M1 ;
			RECT 0.74 2.6 1.12 2.65 ;
		END
		AntennaGateArea 0.3465 ;
	END in0
	OBS
		LAYER M1 ;
		RECT 5.575 5.55 5.855 5.58 ;
		LAYER M1 ;
		RECT 3.1 5.36 5.855 5.55 ;
		LAYER M1 ;
		RECT 0.16 5.02 0.44 5.175 ;
		LAYER M1 ;
		RECT 2.565 5.02 2.845 5.11 ;
		LAYER M1 ;
		RECT 0.16 4.83 2.845 5.02 ;
		LAYER M1 ;
		RECT 3.1 4.995 3.295 5.36 ;
		LAYER M1 ;
		RECT 5.575 5.3 5.855 5.36 ;
		LAYER M1 ;
		RECT 7.76 5.38 9.08 5.57 ;
		LAYER M1 ;
		RECT 7.76 5.18 7.955 5.38 ;
		LAYER M1 ;
		RECT 0.16 4.825 2.695 4.83 ;
		LAYER M1 ;
		RECT 0.16 4.755 0.44 4.825 ;
		LAYER M1 ;
		RECT 0.15 4.115 0.44 4.755 ;
		LAYER M1 ;
		RECT 3.045 4.715 3.325 4.995 ;
		LAYER M1 ;
		RECT 1.965 4.515 2.245 4.625 ;
		LAYER M1 ;
		RECT 7.085 4.515 7.365 5.18 ;
		LAYER M1 ;
		RECT 1.36 4.115 1.64 4.395 ;
		LAYER M1 ;
		RECT 0.15 2.37 0.345 4.115 ;
		LAYER M1 ;
		RECT 1.45 3.37 1.64 4.115 ;
		LAYER M1 ;
		RECT 1.965 4.325 7.365 4.515 ;
		LAYER M1 ;
		RECT 1.965 3.955 2.245 4.325 ;
		LAYER M1 ;
		RECT 1.45 3.175 1.705 3.37 ;
		LAYER M1 ;
		RECT 1.51 2.37 1.705 3.175 ;
		LAYER M1 ;
		RECT 0.15 2.11 0.44 2.37 ;
		LAYER M1 ;
		RECT 0.16 1.885 0.44 2.11 ;
		LAYER M1 ;
		RECT 1.425 2.09 1.705 2.37 ;
		LAYER M1 ;
		RECT 2.03 2.37 2.225 3.955 ;
		LAYER M1 ;
		RECT 2.985 3.845 3.71 4.125 ;
		LAYER M1 ;
		RECT 4.67 3.845 4.95 4.125 ;
		LAYER M1 ;
		RECT 5.275 3.845 5.555 4.125 ;
		LAYER M1 ;
		RECT 5.875 3.845 6.155 4.125 ;
		LAYER M1 ;
		RECT 2.985 3.84 3.64 3.845 ;
		LAYER M1 ;
		RECT 2.99 3.82 3.64 3.84 ;
		LAYER M1 ;
		RECT 3.075 3.815 3.64 3.82 ;
		LAYER M1 ;
		RECT 3.45 2.37 3.64 3.815 ;
		LAYER M1 ;
		RECT 4.755 2.37 4.95 3.845 ;
		LAYER M1 ;
		RECT 5.315 2.37 5.505 3.845 ;
		LAYER M1 ;
		RECT 5.905 2.37 6.1 3.845 ;
		LAYER M1 ;
		RECT 7.085 3.71 7.365 4.325 ;
		LAYER M1 ;
		RECT 7.675 3.71 7.955 5.18 ;
		LAYER M1 ;
		RECT 8.265 4.135 8.545 5.18 ;
		LAYER M1 ;
		RECT 8.885 4.61 9.08 5.38 ;
		LAYER M1 ;
		RECT 8.885 4.415 9.66 4.61 ;
		LAYER M1 ;
		RECT 8.25 3.71 8.545 4.135 ;
		LAYER M1 ;
		RECT 8.86 3.93 9.14 4.21 ;
		LAYER M1 ;
		RECT 7.125 2.41 7.32 3.71 ;
		LAYER M1 ;
		RECT 7.715 2.41 7.905 3.71 ;
		LAYER M1 ;
		RECT 8.25 2.41 8.445 3.71 ;
		LAYER M1 ;
		RECT 8.9 3.03 9.09 3.93 ;
		LAYER M1 ;
		RECT 9.47 3.52 9.66 4.415 ;
		LAYER M1 ;
		RECT 9.47 3.24 9.91 3.52 ;
		LAYER M1 ;
		RECT 8.65 2.75 9.09 3.03 ;
		LAYER M1 ;
		RECT 2.03 2.09 2.31 2.37 ;
		LAYER M1 ;
		RECT 2.625 1.885 2.905 2.37 ;
		LAYER M1 ;
		RECT 3.435 2.2 3.715 2.37 ;
		LAYER M1 ;
		RECT 0.16 1.69 2.905 1.885 ;
		LAYER M1 ;
		RECT 3.425 1.92 3.715 2.2 ;
		LAYER M1 ;
		RECT 3.425 1.745 3.62 1.92 ;
		LAYER M1 ;
		RECT 0.16 1.67 0.44 1.69 ;
		LAYER M1 ;
		RECT 2.625 1.67 2.905 1.69 ;
		LAYER M1 ;
		RECT 3.2 1.465 3.62 1.745 ;
		LAYER M1 ;
		RECT 3.265 1.46 3.62 1.465 ;
		LAYER M1 ;
		RECT 4.665 2.18 4.95 2.37 ;
		LAYER M1 ;
		RECT 4.665 1.67 4.945 2.18 ;
		LAYER M1 ;
		RECT 5.27 1.67 5.55 2.37 ;
		LAYER M1 ;
		RECT 5.885 1.67 6.165 2.37 ;
		LAYER M1 ;
		RECT 7.085 1.71 7.365 2.41 ;
		LAYER M1 ;
		RECT 7.675 1.71 7.955 2.41 ;
		LAYER M1 ;
		RECT 8.25 1.71 8.545 2.41 ;
		LAYER M1 ;
		RECT 8.9 2.17 9.09 2.75 ;
		LAYER M1 ;
		RECT 8.865 1.855 9.145 2.17 ;
		LAYER M1 ;
		RECT 5.3 1.115 5.495 1.67 ;
		LAYER M1 ;
		RECT 5.99 1.115 6.27 1.155 ;
		LAYER M1 ;
		RECT 5.3 0.92 6.27 1.115 ;
		LAYER M1 ;
		RECT 5.99 0.875 6.27 0.92 ;
		LAYER M1 ;
		RECT 6.875 1.105 7.155 1.155 ;
		LAYER M1 ;
		RECT 8.25 1.105 8.445 1.71 ;
		LAYER M1 ;
		RECT 6.875 0.915 8.445 1.105 ;
		LAYER M1 ;
		RECT 6.875 0.875 7.155 0.915 ;
	END
END MMI_MUX4B
MACRO MMI_MUX4C
	CLASS CORE ;
	FOREIGN MMI_MUX4C 0 0 ;
	SIZE 11.16 BY 6.2 ;
	SYMMETRY X Y ;
	SITE CORE1 ;
	PIN out
		DIRECTION output ;
		USE SIGNAL ;
		PORT
			LAYER M1 ;
			RECT 10.095 3.745 10.375 5.215 ;
			LAYER M1 ;
			RECT 10.115 2.98 10.355 3.745 ;
			LAYER M1 ;
			RECT 10.04 2.6 10.42 2.98 ;
			LAYER M1 ;
			RECT 10.115 2.17 10.355 2.6 ;
			LAYER M1 ;
			RECT 10.095 1.47 10.375 2.17 ;
		END
		AntennaDiffArea 1.0164 ;
	END out
	PIN sel0
		DIRECTION input ;
		USE SIGNAL ;
		PORT
			LAYER M1 ;
			RECT 2.64 2.595 3.145 2.985 ;
		END
		AntennaGateArea 0.927 ;
	END sel0
	PIN in1
		DIRECTION input ;
		USE SIGNAL ;
		PORT
			LAYER M1 ;
			RECT 0.74 3.52 1.12 3.6 ;
			LAYER M1 ;
			RECT 0.555 3.24 1.12 3.52 ;
			LAYER M1 ;
			RECT 0.74 3.22 1.12 3.24 ;
		END
		AntennaGateArea 0.3465 ;
	END in1
	PIN GND
		DIRECTION inout ;
		USE GROUND ;
		PORT
			LAYER M1 ;
			RECT 0.79 0.42 1.07 1.495 ;
			LAYER M1 ;
			RECT 4.075 0.42 4.355 2.37 ;
			LAYER M1 ;
			RECT 6.475 1.67 6.755 2.37 ;
			LAYER M1 ;
			RECT 6.48 0.42 6.67 1.67 ;
			LAYER M1 ;
			RECT 9.505 0.42 9.785 2.17 ;
			LAYER M1 ;
			RECT 10.685 0.42 10.965 2.17 ;
			LAYER M1 ;
			RECT 0.0 -0.42 11.16 0.42 ;
		END
	END GND
	PIN in2
		DIRECTION input ;
		USE SIGNAL ;
		PORT
			LAYER M1 ;
			RECT 3.84 2.93 4.22 2.98 ;
			LAYER M1 ;
			RECT 3.84 2.65 4.48 2.93 ;
			LAYER M1 ;
			RECT 3.84 2.6 4.22 2.65 ;
		END
		AntennaGateArea 0.3465 ;
	END in2
	PIN sel1
		DIRECTION input ;
		USE SIGNAL ;
		PORT
			LAYER M1 ;
			RECT 9.425 2.93 9.8 2.98 ;
			LAYER M1 ;
			RECT 9.305 2.65 9.8 2.93 ;
			LAYER M1 ;
			RECT 9.425 2.6 9.8 2.65 ;
		END
		AntennaGateArea 0.51975 ;
	END sel1
	PIN VDD
		DIRECTION inout ;
		USE POWER ;
		PORT
			LAYER M1 ;
			RECT 0.0 5.78 11.16 6.62 ;
			LAYER M1 ;
			RECT 0.755 5.025 1.035 5.78 ;
			LAYER M1 ;
			RECT 6.48 5.0 6.765 5.78 ;
			LAYER M1 ;
			RECT 4.065 4.715 6.765 5.0 ;
			LAYER M1 ;
			RECT 9.505 4.935 9.785 5.78 ;
			LAYER M1 ;
			RECT 10.685 3.745 10.965 5.78 ;
		END
	END VDD
	PIN in3
		DIRECTION input ;
		USE SIGNAL ;
		PORT
			LAYER M1 ;
			RECT 6.325 2.93 6.7 2.98 ;
			LAYER M1 ;
			RECT 6.325 2.65 6.71 2.93 ;
			LAYER M1 ;
			RECT 6.325 2.6 6.7 2.65 ;
		END
		AntennaGateArea 0.3465 ;
	END in3
	PIN in0
		DIRECTION input ;
		USE SIGNAL ;
		PORT
			LAYER M1 ;
			RECT 0.74 2.93 1.12 2.98 ;
			LAYER M1 ;
			RECT 0.74 2.65 1.265 2.93 ;
			LAYER M1 ;
			RECT 0.74 2.6 1.12 2.65 ;
		END
		AntennaGateArea 0.3465 ;
	END in0
	OBS
		LAYER M1 ;
		RECT 0.16 4.805 0.44 5.175 ;
		LAYER M1 ;
		RECT 5.575 5.575 5.855 5.58 ;
		LAYER M1 ;
		RECT 3.1 5.385 5.855 5.575 ;
		LAYER M1 ;
		RECT 2.565 5.03 2.845 5.11 ;
		LAYER M1 ;
		RECT 1.515 4.835 2.845 5.03 ;
		LAYER M1 ;
		RECT 3.1 5.0 3.295 5.385 ;
		LAYER M1 ;
		RECT 5.575 5.3 5.855 5.385 ;
		LAYER M1 ;
		RECT 1.515 4.805 1.71 4.835 ;
		LAYER M1 ;
		RECT 2.565 4.83 2.845 4.835 ;
		LAYER M1 ;
		RECT 0.15 4.615 1.71 4.805 ;
		LAYER M1 ;
		RECT 3.045 4.72 3.325 5.0 ;
		LAYER M1 ;
		RECT 0.15 4.115 0.44 4.615 ;
		LAYER M1 ;
		RECT 1.965 4.515 2.245 4.63 ;
		LAYER M1 ;
		RECT 7.085 4.515 7.365 5.18 ;
		LAYER M1 ;
		RECT 1.36 4.115 1.64 4.395 ;
		LAYER M1 ;
		RECT 0.15 2.37 0.345 4.115 ;
		LAYER M1 ;
		RECT 1.45 3.37 1.64 4.115 ;
		LAYER M1 ;
		RECT 1.965 4.325 7.365 4.515 ;
		LAYER M1 ;
		RECT 1.965 3.96 2.245 4.325 ;
		LAYER M1 ;
		RECT 1.45 3.175 1.705 3.37 ;
		LAYER M1 ;
		RECT 1.51 2.37 1.705 3.175 ;
		LAYER M1 ;
		RECT 2.035 2.37 2.23 3.96 ;
		LAYER M1 ;
		RECT 2.985 3.845 3.71 4.125 ;
		LAYER M1 ;
		RECT 4.67 3.86 4.95 4.12 ;
		LAYER M1 ;
		RECT 2.985 3.84 3.64 3.845 ;
		LAYER M1 ;
		RECT 4.67 3.84 4.955 3.86 ;
		LAYER M1 ;
		RECT 5.275 3.84 5.555 4.12 ;
		LAYER M1 ;
		RECT 5.875 3.84 6.155 4.12 ;
		LAYER M1 ;
		RECT 2.99 3.82 3.64 3.84 ;
		LAYER M1 ;
		RECT 3.075 3.815 3.64 3.82 ;
		LAYER M1 ;
		RECT 3.45 2.37 3.64 3.815 ;
		LAYER M1 ;
		RECT 4.76 2.37 4.955 3.84 ;
		LAYER M1 ;
		RECT 5.31 2.37 5.5 3.84 ;
		LAYER M1 ;
		RECT 5.92 2.37 6.115 3.84 ;
		LAYER M1 ;
		RECT 7.085 3.71 7.365 4.325 ;
		LAYER M1 ;
		RECT 7.675 4.83 7.955 5.18 ;
		LAYER M1 ;
		RECT 7.675 4.64 9.08 4.83 ;
		LAYER M1 ;
		RECT 7.675 3.71 7.955 4.64 ;
		LAYER M1 ;
		RECT 8.885 4.62 9.08 4.64 ;
		LAYER M1 ;
		RECT 8.885 4.425 9.66 4.62 ;
		LAYER M1 ;
		RECT 8.265 4.135 8.545 4.38 ;
		LAYER M1 ;
		RECT 8.25 3.71 8.545 4.135 ;
		LAYER M1 ;
		RECT 8.86 3.94 9.14 4.22 ;
		LAYER M1 ;
		RECT 0.15 2.11 0.44 2.37 ;
		LAYER M1 ;
		RECT 0.16 1.89 0.44 2.11 ;
		LAYER M1 ;
		RECT 1.425 2.09 1.705 2.37 ;
		LAYER M1 ;
		RECT 2.03 2.09 2.31 2.37 ;
		LAYER M1 ;
		RECT 2.625 1.89 2.905 2.37 ;
		LAYER M1 ;
		RECT 3.435 2.2 3.715 2.37 ;
		LAYER M1 ;
		RECT 0.16 1.7 2.905 1.89 ;
		LAYER M1 ;
		RECT 3.425 1.92 3.715 2.2 ;
		LAYER M1 ;
		RECT 3.425 1.745 3.62 1.92 ;
		LAYER M1 ;
		RECT 0.16 1.67 0.44 1.7 ;
		LAYER M1 ;
		RECT 2.625 1.67 2.905 1.7 ;
		LAYER M1 ;
		RECT 3.2 1.465 3.62 1.745 ;
		LAYER M1 ;
		RECT 3.265 1.46 3.62 1.465 ;
		LAYER M1 ;
		RECT 4.665 2.18 4.955 2.37 ;
		LAYER M1 ;
		RECT 4.665 1.67 4.945 2.18 ;
		LAYER M1 ;
		RECT 5.27 1.67 5.55 2.37 ;
		LAYER M1 ;
		RECT 5.885 1.67 6.165 2.37 ;
		LAYER M1 ;
		RECT 7.125 2.015 7.32 3.71 ;
		LAYER M1 ;
		RECT 7.715 2.015 7.91 3.71 ;
		LAYER M1 ;
		RECT 8.25 2.015 8.445 3.71 ;
		LAYER M1 ;
		RECT 8.865 2.62 9.055 3.94 ;
		LAYER M1 ;
		RECT 9.47 3.52 9.66 4.425 ;
		LAYER M1 ;
		RECT 9.47 3.24 9.91 3.52 ;
		LAYER M1 ;
		RECT 8.66 2.43 9.055 2.62 ;
		LAYER M1 ;
		RECT 8.655 2.235 9.055 2.43 ;
		LAYER M1 ;
		RECT 8.865 2.17 9.055 2.235 ;
		LAYER M1 ;
		RECT 5.315 0.925 5.51 1.67 ;
		LAYER M1 ;
		RECT 5.99 0.925 6.27 0.97 ;
		LAYER M1 ;
		RECT 5.315 0.735 6.27 0.925 ;
		LAYER M1 ;
		RECT 5.99 0.69 6.27 0.735 ;
		LAYER M1 ;
		RECT 7.085 1.315 7.365 2.015 ;
		LAYER M1 ;
		RECT 7.675 1.315 7.955 2.015 ;
		LAYER M1 ;
		RECT 8.25 1.315 8.545 2.015 ;
		LAYER M1 ;
		RECT 8.865 1.855 9.145 2.17 ;
		LAYER M1 ;
		RECT 6.875 0.92 7.155 0.965 ;
		LAYER M1 ;
		RECT 8.25 0.92 8.445 1.315 ;
		LAYER M1 ;
		RECT 6.875 0.725 8.445 0.92 ;
		LAYER M1 ;
		RECT 6.875 0.715 7.255 0.725 ;
		LAYER M1 ;
		RECT 6.875 0.685 7.155 0.715 ;
	END
END MMI_MUX4C
MACRO MMI_MUXI2A
	CLASS CORE ;
	FOREIGN MMI_MUXI2A 0 0 ;
	SIZE 3.72 BY 6.2 ;
	SYMMETRY X Y ;
	SITE CORE1 ;
	PIN out
		DIRECTION output ;
		USE SIGNAL ;
		PORT
			LAYER M1 ;
			RECT 2.045 3.82 2.325 5.29 ;
			LAYER M1 ;
			RECT 2.09 3.6 2.285 3.82 ;
			LAYER M1 ;
			RECT 1.98 3.22 2.36 3.6 ;
			LAYER M1 ;
			RECT 2.09 2.44 2.285 3.22 ;
			LAYER M1 ;
			RECT 2.045 1.74 2.325 2.44 ;
		END
		AntennaDiffArea 1.0164 ;
	END out
	PIN sel
		DIRECTION input ;
		USE SIGNAL ;
		PORT
			LAYER M1 ;
			RECT 0.595 2.98 0.875 2.99 ;
			LAYER M1 ;
			RECT 0.595 2.71 1.12 2.98 ;
			LAYER M1 ;
			RECT 0.74 2.6 1.12 2.71 ;
		END
		AntennaGateArea 0.51975 ;
	END sel
	PIN in1
		DIRECTION input ;
		USE SIGNAL ;
		PORT
			LAYER M1 ;
			RECT 0.745 3.57 1.125 3.615 ;
			LAYER M1 ;
			RECT 0.745 3.29 1.25 3.57 ;
			LAYER M1 ;
			RECT 0.745 3.24 1.125 3.29 ;
		END
		AntennaGateArea 0.34575 ;
	END in1
	PIN GND
		DIRECTION inout ;
		USE GROUND ;
		PORT
			LAYER M1 ;
			RECT 0.815 0.42 1.095 2.115 ;
			LAYER M1 ;
			RECT 3.225 0.42 3.505 2.065 ;
			LAYER M1 ;
			RECT 0.0 -0.42 3.72 0.42 ;
		END
	END GND
	PIN VDD
		DIRECTION inout ;
		USE POWER ;
		PORT
			LAYER M1 ;
			RECT 0.0 5.78 3.72 6.62 ;
			LAYER M1 ;
			RECT 0.815 3.82 1.095 5.78 ;
			LAYER M1 ;
			RECT 3.225 3.82 3.505 5.78 ;
		END
	END VDD
	PIN in0
		DIRECTION input ;
		USE SIGNAL ;
		PORT
			LAYER M1 ;
			RECT 3.22 2.94 3.6 2.985 ;
			LAYER M1 ;
			RECT 3.135 2.66 3.6 2.94 ;
			LAYER M1 ;
			RECT 3.22 2.61 3.6 2.66 ;
		END
		AntennaGateArea 0.3465 ;
	END in0
	OBS
		LAYER M1 ;
		RECT 0.18 3.82 0.46 4.52 ;
		LAYER M1 ;
		RECT 1.455 3.82 1.735 5.29 ;
		LAYER M1 ;
		RECT 2.635 3.82 2.915 5.29 ;
		LAYER M1 ;
		RECT 0.18 2.47 0.375 3.82 ;
		LAYER M1 ;
		RECT 0.18 2.155 0.46 2.47 ;
		LAYER M1 ;
		RECT 1.51 2.44 1.7 3.82 ;
		LAYER M1 ;
		RECT 2.69 2.44 2.88 3.82 ;
		LAYER M1 ;
		RECT 0.23 0.9 0.425 2.155 ;
		LAYER M1 ;
		RECT 0.19 0.62 0.47 0.9 ;
		LAYER M1 ;
		RECT 1.455 1.74 1.735 2.44 ;
		LAYER M1 ;
		RECT 2.635 1.74 2.915 2.44 ;
		LAYER M1 ;
		RECT 2.335 1.22 2.615 1.5 ;
		LAYER M1 ;
		RECT 1.325 0.835 1.605 0.9 ;
		LAYER M1 ;
		RECT 2.385 0.835 2.575 1.22 ;
		LAYER M1 ;
		RECT 1.325 0.64 2.575 0.835 ;
		LAYER M1 ;
		RECT 1.325 0.62 1.605 0.64 ;
	END
END MMI_MUXI2A
MACRO MMI_MUXI2B
	CLASS CORE ;
	FOREIGN MMI_MUXI2B 0 0 ;
	SIZE 6.82 BY 6.2 ;
	SYMMETRY X Y ;
	SITE CORE1 ;
	PIN out
		DIRECTION output ;
		USE SIGNAL ;
		PORT
			LAYER M1 ;
			RECT 3.83 5.39 6.48 5.58 ;
			LAYER M1 ;
			RECT 3.83 5.045 4.02 5.39 ;
			LAYER M1 ;
			RECT 5.035 5.045 5.23 5.39 ;
			LAYER M1 ;
			RECT 3.795 4.765 4.075 5.045 ;
			LAYER M1 ;
			RECT 4.995 4.765 5.275 5.045 ;
			LAYER M1 ;
			RECT 6.285 4.79 6.48 5.39 ;
			LAYER M1 ;
			RECT 6.185 3.73 6.48 4.79 ;
			LAYER M1 ;
			RECT 6.285 2.98 6.48 3.73 ;
			LAYER M1 ;
			RECT 6.285 2.6 6.7 2.98 ;
			LAYER M1 ;
			RECT 6.285 2.02 6.48 2.6 ;
			LAYER M1 ;
			RECT 3.895 1.32 4.175 2.02 ;
			LAYER M1 ;
			RECT 5.075 1.32 5.355 2.02 ;
			LAYER M1 ;
			RECT 6.255 1.32 6.535 2.02 ;
			LAYER M1 ;
			RECT 3.98 1.11 4.17 1.32 ;
			LAYER M1 ;
			RECT 5.12 1.11 5.31 1.32 ;
			LAYER M1 ;
			RECT 6.285 1.11 6.48 1.32 ;
			LAYER M1 ;
			RECT 3.98 0.92 6.48 1.11 ;
		END
		AntennaDiffArea 2.8644 ;
	END out
	PIN in1
		DIRECTION input ;
		USE SIGNAL ;
		PORT
			LAYER M1 ;
			RECT 2.6 2.6 2.98 2.98 ;
		END
		AntennaGateArea 0.693 ;
	END in1
	PIN sel
		DIRECTION input ;
		USE SIGNAL ;
		PORT
			LAYER M1 ;
			RECT 5.2 3.37 5.48 3.46 ;
			LAYER M1 ;
			RECT 5.015 3.18 5.48 3.37 ;
			LAYER M1 ;
			RECT 0.74 2.935 1.12 2.98 ;
			LAYER M1 ;
			RECT 0.69 2.655 1.12 2.935 ;
			LAYER M1 ;
			RECT 0.74 2.6 1.12 2.655 ;
			LAYER M1 ;
			RECT 5.015 2.515 5.21 3.18 ;
			LAYER M1 ;
			RECT 4.845 2.29 5.21 2.515 ;
			LAYER M1 ;
			RECT 4.845 2.235 5.125 2.29 ;
		END
		AntennaGateArea 0.927 ;
	END sel
	PIN GND
		DIRECTION inout ;
		USE GROUND ;
		PORT
			LAYER M1 ;
			RECT 0.825 0.42 1.105 2.01 ;
			LAYER M1 ;
			RECT 2.005 0.42 2.285 2.01 ;
			LAYER M1 ;
			RECT 3.185 0.42 3.465 2.01 ;
			LAYER M1 ;
			RECT 0.0 -0.42 6.82 0.42 ;
		END
	END GND
	PIN VDD
		DIRECTION inout ;
		USE POWER ;
		PORT
			LAYER M1 ;
			RECT 0.0 5.78 6.82 6.62 ;
			LAYER M1 ;
			RECT 0.825 3.73 1.105 5.78 ;
			LAYER M1 ;
			RECT 2.005 4.765 2.285 5.78 ;
			LAYER M1 ;
			RECT 3.205 4.765 3.485 5.78 ;
		END
	END VDD
	PIN in0
		DIRECTION input ;
		USE SIGNAL ;
		PORT
			LAYER M1 ;
			RECT 1.36 2.6 1.74 2.98 ;
		END
		AntennaGateArea 0.693 ;
	END in0
	OBS
		LAYER M1 ;
		RECT 0.22 5.24 0.5 5.52 ;
		LAYER M1 ;
		RECT 0.22 4.7 0.41 5.24 ;
		LAYER M1 ;
		RECT 0.19 3.73 0.47 4.7 ;
		LAYER M1 ;
		RECT 1.415 4.565 1.695 5.2 ;
		LAYER M1 ;
		RECT 5.595 4.565 5.875 4.79 ;
		LAYER M1 ;
		RECT 1.415 4.375 5.875 4.565 ;
		LAYER M1 ;
		RECT 1.415 3.73 1.695 4.375 ;
		LAYER M1 ;
		RECT 2.6 4.15 2.88 4.175 ;
		LAYER M1 ;
		RECT 4.395 4.15 4.675 4.175 ;
		LAYER M1 ;
		RECT 2.6 3.96 4.675 4.15 ;
		LAYER M1 ;
		RECT 2.6 3.895 2.88 3.96 ;
		LAYER M1 ;
		RECT 4.395 3.895 4.675 3.96 ;
		LAYER M1 ;
		RECT 0.245 2.01 0.435 3.73 ;
		LAYER M1 ;
		RECT 1.435 3.405 1.625 3.73 ;
		LAYER M1 ;
		RECT 2.645 3.405 2.835 3.895 ;
		LAYER M1 ;
		RECT 1.435 3.215 2.205 3.405 ;
		LAYER M1 ;
		RECT 2.645 3.215 3.4 3.405 ;
		LAYER M1 ;
		RECT 2.01 2.4 2.205 3.215 ;
		LAYER M1 ;
		RECT 3.21 2.4 3.4 3.215 ;
		LAYER M1 ;
		RECT 1.505 2.21 2.205 2.4 ;
		LAYER M1 ;
		RECT 2.68 2.21 3.4 2.4 ;
		LAYER M1 ;
		RECT 1.505 2.01 1.695 2.21 ;
		LAYER M1 ;
		RECT 2.68 2.01 2.875 2.21 ;
		LAYER M1 ;
		RECT 4.455 2.02 4.645 3.895 ;
		LAYER M1 ;
		RECT 5.595 3.73 5.875 4.375 ;
		LAYER M1 ;
		RECT 5.68 2.02 5.875 3.73 ;
		LAYER M1 ;
		RECT 0.19 1.56 0.47 2.01 ;
		LAYER M1 ;
		RECT 1.415 1.31 1.695 2.01 ;
		LAYER M1 ;
		RECT 2.595 1.31 2.875 2.01 ;
		LAYER M1 ;
		RECT 4.455 1.785 4.765 2.02 ;
		LAYER M1 ;
		RECT 4.485 1.32 4.765 1.785 ;
		LAYER M1 ;
		RECT 5.665 1.32 5.945 2.02 ;
	END
END MMI_MUXI2B
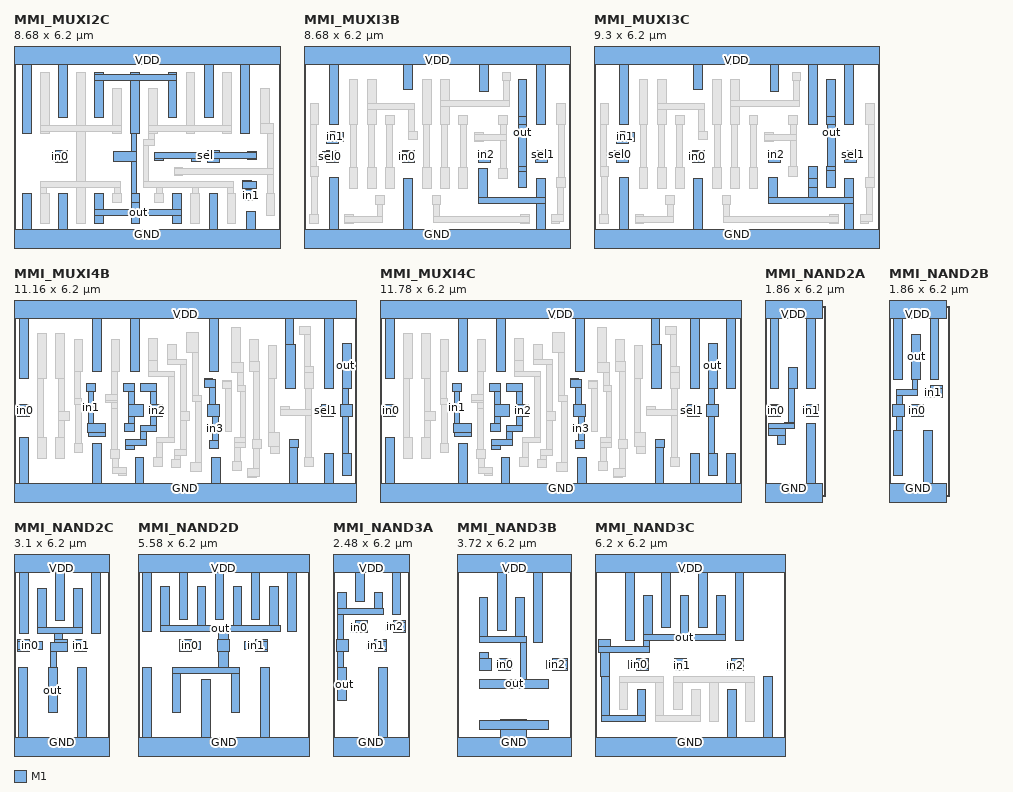
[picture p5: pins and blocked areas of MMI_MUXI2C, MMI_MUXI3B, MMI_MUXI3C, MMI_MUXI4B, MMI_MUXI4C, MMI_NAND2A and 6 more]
MACRO MMI_MUXI2C
	CLASS CORE ;
	FOREIGN MMI_MUXI2C 0 0 ;
	SIZE 8.68 BY 6.2 ;
	SYMMETRY X Y ;
	SITE CORE1 ;
	PIN out
		DIRECTION output ;
		USE SIGNAL ;
		PORT
			LAYER M1 ;
			RECT 2.635 5.455 2.915 5.53 ;
			LAYER M1 ;
			RECT 3.815 5.455 4.095 5.53 ;
			LAYER M1 ;
			RECT 5.035 5.455 5.315 5.53 ;
			LAYER M1 ;
			RECT 2.635 5.265 5.315 5.455 ;
			LAYER M1 ;
			RECT 2.635 4.075 2.915 5.265 ;
			LAYER M1 ;
			RECT 3.815 3.545 4.095 5.265 ;
			LAYER M1 ;
			RECT 5.035 4.075 5.315 5.265 ;
			LAYER M1 ;
			RECT 3.82 2.955 4.01 3.545 ;
			LAYER M1 ;
			RECT 3.245 2.625 4.01 2.955 ;
			LAYER M1 ;
			RECT 3.82 1.575 4.01 2.625 ;
			LAYER M1 ;
			RECT 2.635 1.06 2.915 1.575 ;
			LAYER M1 ;
			RECT 3.82 1.3 4.11 1.575 ;
			LAYER M1 ;
			RECT 3.83 1.06 4.11 1.3 ;
			LAYER M1 ;
			RECT 5.185 1.06 5.465 1.575 ;
			LAYER M1 ;
			RECT 2.635 0.87 5.465 1.06 ;
			LAYER M1 ;
			RECT 2.635 0.62 2.915 0.87 ;
			LAYER M1 ;
			RECT 3.83 0.62 4.11 0.87 ;
			LAYER M1 ;
			RECT 5.185 0.62 5.465 0.87 ;
		END
		AntennaDiffArea 4.101525 ;
	END out
	PIN in1
		DIRECTION input ;
		USE SIGNAL ;
		PORT
			LAYER M1 ;
			RECT 7.465 1.98 7.745 2.01 ;
			LAYER M1 ;
			RECT 7.465 1.73 7.925 1.98 ;
			LAYER M1 ;
			RECT 7.47 1.705 7.925 1.73 ;
			LAYER M1 ;
			RECT 7.57 1.36 7.925 1.705 ;
		END
		AntennaGateArea 1.386 ;
	END in1
	PIN sel
		DIRECTION input ;
		USE SIGNAL ;
		PORT
			LAYER M1 ;
			RECT 6.32 2.935 6.7 2.98 ;
			LAYER M1 ;
			RECT 7.63 2.935 7.91 2.965 ;
			LAYER M1 ;
			RECT 4.695 2.93 7.91 2.935 ;
			LAYER M1 ;
			RECT 4.6 2.74 7.91 2.93 ;
			LAYER M1 ;
			RECT 4.6 2.65 4.88 2.74 ;
			LAYER M1 ;
			RECT 5.8 2.63 6.08 2.74 ;
			LAYER M1 ;
			RECT 6.32 2.6 6.7 2.74 ;
			LAYER M1 ;
			RECT 7.63 2.685 7.91 2.74 ;
		END
		AntennaGateArea 1.7325 ;
	END sel
	PIN GND
		DIRECTION inout ;
		USE GROUND ;
		PORT
			LAYER M1 ;
			RECT 0.275 0.42 0.555 1.575 ;
			LAYER M1 ;
			RECT 1.455 0.42 1.735 1.575 ;
			LAYER M1 ;
			RECT 6.365 0.42 6.645 1.575 ;
			LAYER M1 ;
			RECT 7.6 0.42 7.88 0.99 ;
			LAYER M1 ;
			RECT 0.0 -0.42 8.68 0.42 ;
		END
	END GND
	PIN VDD
		DIRECTION inout ;
		USE POWER ;
		PORT
			LAYER M1 ;
			RECT 0.0 5.78 8.68 6.62 ;
			LAYER M1 ;
			RECT 0.275 3.545 0.555 5.78 ;
			LAYER M1 ;
			RECT 1.455 4.075 1.735 5.78 ;
			LAYER M1 ;
			RECT 6.215 4.075 6.495 5.78 ;
			LAYER M1 ;
			RECT 7.395 3.545 7.675 5.78 ;
		END
	END VDD
	PIN in0
		DIRECTION input ;
		USE SIGNAL ;
		PORT
			LAYER M1 ;
			RECT 1.36 2.915 1.74 2.98 ;
			LAYER M1 ;
			RECT 1.275 2.635 1.74 2.915 ;
			LAYER M1 ;
			RECT 1.36 2.6 1.74 2.635 ;
		END
		AntennaGateArea 1.386 ;
	END in0
	OBS
		LAYER M1 ;
		RECT 0.865 3.8 1.145 5.53 ;
		LAYER M1 ;
		RECT 2.045 3.8 2.325 5.53 ;
		LAYER M1 ;
		RECT 3.225 3.8 3.505 4.995 ;
		LAYER M1 ;
		RECT 0.865 3.61 3.505 3.8 ;
		LAYER M1 ;
		RECT 0.865 3.545 1.145 3.61 ;
		LAYER M1 ;
		RECT 2.045 1.985 2.325 3.61 ;
		LAYER M1 ;
		RECT 3.225 3.545 3.505 3.61 ;
		LAYER M1 ;
		RECT 4.405 3.795 4.685 4.995 ;
		LAYER M1 ;
		RECT 5.625 3.795 5.905 5.53 ;
		LAYER M1 ;
		RECT 6.805 3.795 7.085 5.53 ;
		LAYER M1 ;
		RECT 4.405 3.605 7.085 3.795 ;
		LAYER M1 ;
		RECT 4.405 3.545 4.685 3.605 ;
		LAYER M1 ;
		RECT 5.625 3.545 5.905 3.605 ;
		LAYER M1 ;
		RECT 6.805 3.545 7.085 3.605 ;
		LAYER M1 ;
		RECT 8.045 3.88 8.325 5.015 ;
		LAYER M1 ;
		RECT 8.045 3.545 8.465 3.88 ;
		LAYER M1 ;
		RECT 4.405 3.34 4.595 3.545 ;
		LAYER M1 ;
		RECT 0.87 1.79 3.47 1.985 ;
		LAYER M1 ;
		RECT 0.87 1.575 1.06 1.79 ;
		LAYER M1 ;
		RECT 0.865 0.62 1.145 1.575 ;
		LAYER M1 ;
		RECT 2.045 0.62 2.325 1.79 ;
		LAYER M1 ;
		RECT 3.275 1.575 3.47 1.79 ;
		LAYER M1 ;
		RECT 4.21 3.15 4.595 3.34 ;
		LAYER M1 ;
		RECT 4.21 1.965 4.4 3.15 ;
		LAYER M1 ;
		RECT 5.225 2.4 5.505 2.445 ;
		LAYER M1 ;
		RECT 8.27 2.4 8.465 3.545 ;
		LAYER M1 ;
		RECT 5.225 2.21 8.465 2.4 ;
		LAYER M1 ;
		RECT 5.225 2.165 5.505 2.21 ;
		LAYER M1 ;
		RECT 4.21 1.775 7.15 1.965 ;
		LAYER M1 ;
		RECT 4.635 1.575 4.83 1.775 ;
		LAYER M1 ;
		RECT 5.82 1.575 6.015 1.775 ;
		LAYER M1 ;
		RECT 6.955 1.575 7.15 1.775 ;
		LAYER M1 ;
		RECT 3.225 1.29 3.505 1.575 ;
		LAYER M1 ;
		RECT 4.595 1.29 4.875 1.575 ;
		LAYER M1 ;
		RECT 5.775 0.62 6.055 1.575 ;
		LAYER M1 ;
		RECT 6.955 0.62 7.235 1.575 ;
		LAYER M1 ;
		RECT 8.27 1.575 8.465 2.21 ;
		LAYER M1 ;
		RECT 8.23 0.875 8.51 1.575 ;
	END
END MMI_MUXI2C
MACRO MMI_MUXI3B
	CLASS CORE ;
	FOREIGN MMI_MUXI3B 0 0 ;
	SIZE 8.68 BY 6.2 ;
	SYMMETRY X Y ;
	SITE CORE1 ;
	PIN out
		DIRECTION output ;
		USE SIGNAL ;
		PORT
			LAYER M1 ;
			RECT 6.995 4.1 7.275 5.29 ;
			LAYER M1 ;
			RECT 6.985 3.82 7.275 4.1 ;
			LAYER M1 ;
			RECT 6.985 2.475 7.27 3.82 ;
			LAYER M1 ;
			RECT 6.985 2.305 7.275 2.475 ;
			LAYER M1 ;
			RECT 6.995 1.78 7.275 2.305 ;
		END
		AntennaDiffArea 0.910475 ;
	END out
	PIN sel0
		DIRECTION input ;
		USE SIGNAL ;
		PORT
			LAYER M1 ;
			RECT 0.74 2.945 1.12 2.98 ;
			LAYER M1 ;
			RECT 0.605 2.665 1.12 2.945 ;
			LAYER M1 ;
			RECT 0.74 2.6 1.12 2.665 ;
		END
		AntennaGateArea 0.51975 ;
	END sel0
	PIN in1
		DIRECTION input ;
		USE SIGNAL ;
		PORT
			LAYER M1 ;
			RECT 0.74 3.57 1.12 3.6 ;
			LAYER M1 ;
			RECT 0.74 3.29 1.285 3.57 ;
			LAYER M1 ;
			RECT 0.74 3.22 1.12 3.29 ;
		END
		AntennaGateArea 0.34575 ;
	END in1
	PIN GND
		DIRECTION inout ;
		USE GROUND ;
		PORT
			LAYER M1 ;
			RECT 0.84 0.42 1.12 2.12 ;
			LAYER M1 ;
			RECT 3.25 0.42 3.53 2.065 ;
			LAYER M1 ;
			RECT 5.7 1.445 5.98 2.395 ;
			LAYER M1 ;
			RECT 7.585 1.445 7.865 2.06 ;
			LAYER M1 ;
			RECT 5.7 1.255 7.865 1.445 ;
			LAYER M1 ;
			RECT 7.585 0.42 7.865 1.255 ;
			LAYER M1 ;
			RECT 0.0 -0.42 8.68 0.42 ;
		END
	END GND
	PIN in2
		DIRECTION input ;
		USE SIGNAL ;
		PORT
			LAYER M1 ;
			RECT 5.895 2.98 6.175 2.99 ;
			LAYER M1 ;
			RECT 5.7 2.71 6.175 2.98 ;
			LAYER M1 ;
			RECT 5.7 2.6 6.08 2.71 ;
		END
		AntennaGateArea 0.17325 ;
	END in2
	PIN sel1
		DIRECTION input ;
		USE SIGNAL ;
		PORT
			LAYER M1 ;
			RECT 7.56 2.7 8.06 2.98 ;
			LAYER M1 ;
			RECT 7.56 2.6 7.94 2.7 ;
		END
		AntennaGateArea 0.51975 ;
	END sel1
	PIN VDD
		DIRECTION inout ;
		USE POWER ;
		PORT
			LAYER M1 ;
			RECT 0.0 5.78 8.68 6.62 ;
			LAYER M1 ;
			RECT 0.84 3.835 1.12 5.78 ;
			LAYER M1 ;
			RECT 3.25 4.965 3.53 5.78 ;
			LAYER M1 ;
			RECT 5.74 4.915 6.02 5.78 ;
			LAYER M1 ;
			RECT 7.585 3.82 7.865 5.78 ;
		END
	END VDD
	PIN in0
		DIRECTION input ;
		USE SIGNAL ;
		PORT
			LAYER M1 ;
			RECT 3.22 2.94 3.6 2.98 ;
			LAYER M1 ;
			RECT 3.09 2.66 3.6 2.94 ;
			LAYER M1 ;
			RECT 3.22 2.6 3.6 2.66 ;
		END
		AntennaGateArea 0.3465 ;
	END in0
	OBS
		LAYER M1 ;
		RECT 0.205 3.835 0.485 4.535 ;
		LAYER M1 ;
		RECT 1.48 3.835 1.76 5.305 ;
		LAYER M1 ;
		RECT 2.07 4.52 2.35 5.305 ;
		LAYER M1 ;
		RECT 2.07 4.325 3.615 4.52 ;
		LAYER M1 ;
		RECT 2.07 3.835 2.35 4.325 ;
		LAYER M1 ;
		RECT 2.66 3.835 2.94 4.115 ;
		LAYER M1 ;
		RECT 0.205 2.465 0.395 3.835 ;
		LAYER M1 ;
		RECT 0.205 2.15 0.485 2.465 ;
		LAYER M1 ;
		RECT 1.52 2.44 1.71 3.835 ;
		LAYER M1 ;
		RECT 2.105 2.44 2.3 3.835 ;
		LAYER M1 ;
		RECT 2.7 2.44 2.89 3.835 ;
		LAYER M1 ;
		RECT 3.425 3.62 3.615 4.325 ;
		LAYER M1 ;
		RECT 3.87 3.835 4.15 5.305 ;
		LAYER M1 ;
		RECT 4.46 4.615 4.74 5.305 ;
		LAYER M1 ;
		RECT 6.525 5.535 6.715 5.54 ;
		LAYER M1 ;
		RECT 6.47 5.255 6.75 5.535 ;
		LAYER M1 ;
		RECT 6.525 4.615 6.715 5.255 ;
		LAYER M1 ;
		RECT 4.46 4.42 6.715 4.615 ;
		LAYER M1 ;
		RECT 4.46 3.835 4.74 4.42 ;
		LAYER M1 ;
		RECT 5.05 3.835 5.33 4.115 ;
		LAYER M1 ;
		RECT 6.355 3.835 6.635 4.115 ;
		LAYER M1 ;
		RECT 3.425 3.34 3.705 3.62 ;
		LAYER M1 ;
		RECT 3.915 2.44 4.11 3.835 ;
		LAYER M1 ;
		RECT 4.5 2.44 4.69 3.835 ;
		LAYER M1 ;
		RECT 5.095 2.44 5.29 3.835 ;
		LAYER M1 ;
		RECT 5.575 3.52 5.855 3.57 ;
		LAYER M1 ;
		RECT 6.42 3.52 6.61 3.835 ;
		LAYER M1 ;
		RECT 5.575 3.325 6.61 3.52 ;
		LAYER M1 ;
		RECT 5.575 3.29 5.855 3.325 ;
		LAYER M1 ;
		RECT 0.255 0.9 0.45 2.15 ;
		LAYER M1 ;
		RECT 0.19 0.62 0.47 0.9 ;
		LAYER M1 ;
		RECT 1.48 1.74 1.76 2.44 ;
		LAYER M1 ;
		RECT 2.07 1.74 2.35 2.44 ;
		LAYER M1 ;
		RECT 2.66 1.74 2.94 2.44 ;
		LAYER M1 ;
		RECT 2.335 1.23 2.615 1.51 ;
		LAYER M1 ;
		RECT 1.325 0.84 1.605 0.9 ;
		LAYER M1 ;
		RECT 2.385 0.84 2.575 1.23 ;
		LAYER M1 ;
		RECT 1.325 0.65 2.575 0.84 ;
		LAYER M1 ;
		RECT 1.325 0.62 1.605 0.65 ;
		LAYER M1 ;
		RECT 3.87 1.74 4.15 2.44 ;
		LAYER M1 ;
		RECT 4.46 1.74 4.74 2.44 ;
		LAYER M1 ;
		RECT 5.05 1.74 5.33 2.44 ;
		LAYER M1 ;
		RECT 6.42 2.395 6.61 3.325 ;
		LAYER M1 ;
		RECT 8.24 3.82 8.52 4.52 ;
		LAYER M1 ;
		RECT 4.18 1.23 4.46 1.51 ;
		LAYER M1 ;
		RECT 6.355 2.08 6.635 2.395 ;
		LAYER M1 ;
		RECT 8.29 2.095 8.485 3.82 ;
		LAYER M1 ;
		RECT 8.24 1.78 8.52 2.095 ;
		LAYER M1 ;
		RECT 4.22 0.84 4.41 1.23 ;
		LAYER M1 ;
		RECT 7.075 0.84 7.355 0.9 ;
		LAYER M1 ;
		RECT 4.22 0.65 7.355 0.84 ;
		LAYER M1 ;
		RECT 7.075 0.62 7.355 0.65 ;
		LAYER M1 ;
		RECT 8.265 0.9 8.46 1.78 ;
		LAYER M1 ;
		RECT 8.07 0.66 8.46 0.9 ;
		LAYER M1 ;
		RECT 8.07 0.62 8.35 0.66 ;
	END
END MMI_MUXI3B
MACRO MMI_MUXI3C
	CLASS CORE ;
	FOREIGN MMI_MUXI3C 0 0 ;
	SIZE 9.3 BY 6.2 ;
	SYMMETRY X Y ;
	SITE CORE1 ;
	PIN out
		DIRECTION output ;
		USE SIGNAL ;
		PORT
			LAYER M1 ;
			RECT 7.6 4.1 7.88 5.29 ;
			LAYER M1 ;
			RECT 7.6 3.82 7.89 4.1 ;
			LAYER M1 ;
			RECT 7.605 2.475 7.89 3.82 ;
			LAYER M1 ;
			RECT 7.6 2.34 7.89 2.475 ;
			LAYER M1 ;
			RECT 7.6 1.78 7.88 2.34 ;
		END
		AntennaDiffArea 1.0142 ;
	END out
	PIN in1
		DIRECTION input ;
		USE SIGNAL ;
		PORT
			LAYER M1 ;
			RECT 0.74 3.57 1.12 3.6 ;
			LAYER M1 ;
			RECT 0.74 3.29 1.31 3.57 ;
			LAYER M1 ;
			RECT 0.74 3.22 1.12 3.29 ;
		END
		AntennaGateArea 0.34575 ;
	END in1
	PIN sel0
		DIRECTION input ;
		USE SIGNAL ;
		PORT
			LAYER M1 ;
			RECT 0.605 2.98 0.885 2.99 ;
			LAYER M1 ;
			RECT 0.605 2.71 1.12 2.98 ;
			LAYER M1 ;
			RECT 0.74 2.6 1.12 2.71 ;
		END
		AntennaGateArea 0.51975 ;
	END sel0
	PIN GND
		DIRECTION inout ;
		USE GROUND ;
		PORT
			LAYER M1 ;
			RECT 0.84 0.42 1.12 2.12 ;
			LAYER M1 ;
			RECT 3.25 0.42 3.53 2.065 ;
			LAYER M1 ;
			RECT 5.705 1.445 5.99 2.12 ;
			LAYER M1 ;
			RECT 7.01 2.065 7.29 2.475 ;
			LAYER M1 ;
			RECT 7.0 1.78 7.29 2.065 ;
			LAYER M1 ;
			RECT 7.0 1.445 7.285 1.78 ;
			LAYER M1 ;
			RECT 8.19 1.445 8.47 2.065 ;
			LAYER M1 ;
			RECT 5.705 1.255 8.47 1.445 ;
			LAYER M1 ;
			RECT 8.19 0.42 8.47 1.255 ;
			LAYER M1 ;
			RECT 0.0 -0.42 9.3 0.42 ;
		END
	END GND
	PIN in2
		DIRECTION input ;
		USE SIGNAL ;
		PORT
			LAYER M1 ;
			RECT 5.895 2.98 6.175 2.99 ;
			LAYER M1 ;
			RECT 5.7 2.71 6.175 2.98 ;
			LAYER M1 ;
			RECT 5.7 2.6 6.08 2.71 ;
		END
		AntennaGateArea 0.17325 ;
	END in2
	PIN sel1
		DIRECTION input ;
		USE SIGNAL ;
		PORT
			LAYER M1 ;
			RECT 8.18 2.7 8.715 2.98 ;
			LAYER M1 ;
			RECT 8.18 2.6 8.56 2.7 ;
		END
		AntennaGateArea 0.51975 ;
	END sel1
	PIN VDD
		DIRECTION inout ;
		USE POWER ;
		PORT
			LAYER M1 ;
			RECT 0.0 5.78 9.3 6.62 ;
			LAYER M1 ;
			RECT 0.84 3.835 1.12 5.78 ;
			LAYER M1 ;
			RECT 3.25 4.965 3.53 5.78 ;
			LAYER M1 ;
			RECT 5.75 4.91 6.03 5.78 ;
			LAYER M1 ;
			RECT 7.01 3.82 7.29 5.78 ;
			LAYER M1 ;
			RECT 8.19 3.82 8.47 5.78 ;
		END
	END VDD
	PIN in0
		DIRECTION input ;
		USE SIGNAL ;
		PORT
			LAYER M1 ;
			RECT 3.22 2.94 3.6 2.98 ;
			LAYER M1 ;
			RECT 3.09 2.66 3.6 2.94 ;
			LAYER M1 ;
			RECT 3.22 2.6 3.6 2.66 ;
		END
		AntennaGateArea 0.3465 ;
	END in0
	OBS
		LAYER M1 ;
		RECT 0.205 3.835 0.485 4.535 ;
		LAYER M1 ;
		RECT 1.48 3.835 1.76 5.305 ;
		LAYER M1 ;
		RECT 2.07 4.52 2.35 5.305 ;
		LAYER M1 ;
		RECT 2.07 4.325 3.615 4.52 ;
		LAYER M1 ;
		RECT 2.07 3.835 2.35 4.325 ;
		LAYER M1 ;
		RECT 2.66 3.835 2.94 4.115 ;
		LAYER M1 ;
		RECT 0.205 2.465 0.4 3.835 ;
		LAYER M1 ;
		RECT 0.205 2.15 0.485 2.465 ;
		LAYER M1 ;
		RECT 1.525 2.44 1.715 3.835 ;
		LAYER M1 ;
		RECT 2.115 2.44 2.31 3.835 ;
		LAYER M1 ;
		RECT 2.7 2.44 2.89 3.835 ;
		LAYER M1 ;
		RECT 3.425 3.62 3.615 4.325 ;
		LAYER M1 ;
		RECT 3.87 3.835 4.15 5.305 ;
		LAYER M1 ;
		RECT 4.46 4.615 4.74 5.305 ;
		LAYER M1 ;
		RECT 6.525 5.535 6.715 5.54 ;
		LAYER M1 ;
		RECT 6.47 5.255 6.75 5.535 ;
		LAYER M1 ;
		RECT 6.525 4.615 6.715 5.255 ;
		LAYER M1 ;
		RECT 4.46 4.42 6.715 4.615 ;
		LAYER M1 ;
		RECT 4.46 3.835 4.74 4.42 ;
		LAYER M1 ;
		RECT 5.06 3.835 5.34 4.115 ;
		LAYER M1 ;
		RECT 6.355 3.835 6.635 4.115 ;
		LAYER M1 ;
		RECT 3.425 3.34 3.705 3.62 ;
		LAYER M1 ;
		RECT 3.92 2.44 4.115 3.835 ;
		LAYER M1 ;
		RECT 4.5 2.44 4.69 3.835 ;
		LAYER M1 ;
		RECT 5.1 2.44 5.295 3.835 ;
		LAYER M1 ;
		RECT 5.575 3.52 5.855 3.57 ;
		LAYER M1 ;
		RECT 6.42 3.52 6.61 3.835 ;
		LAYER M1 ;
		RECT 8.86 3.82 9.14 4.52 ;
		LAYER M1 ;
		RECT 5.575 3.325 6.61 3.52 ;
		LAYER M1 ;
		RECT 5.575 3.29 5.855 3.325 ;
		LAYER M1 ;
		RECT 6.42 2.465 6.61 3.325 ;
		LAYER M1 ;
		RECT 0.255 0.9 0.45 2.15 ;
		LAYER M1 ;
		RECT 0.19 0.62 0.47 0.9 ;
		LAYER M1 ;
		RECT 1.48 1.74 1.76 2.44 ;
		LAYER M1 ;
		RECT 2.07 1.74 2.35 2.44 ;
		LAYER M1 ;
		RECT 2.66 1.74 2.94 2.44 ;
		LAYER M1 ;
		RECT 2.345 1.23 2.625 1.51 ;
		LAYER M1 ;
		RECT 1.35 0.84 1.63 0.9 ;
		LAYER M1 ;
		RECT 2.395 0.84 2.585 1.23 ;
		LAYER M1 ;
		RECT 1.35 0.65 2.585 0.84 ;
		LAYER M1 ;
		RECT 1.35 0.62 1.63 0.65 ;
		LAYER M1 ;
		RECT 3.87 1.74 4.15 2.44 ;
		LAYER M1 ;
		RECT 4.46 1.74 4.74 2.44 ;
		LAYER M1 ;
		RECT 5.06 1.74 5.34 2.44 ;
		LAYER M1 ;
		RECT 6.355 2.15 6.635 2.465 ;
		LAYER M1 ;
		RECT 4.18 1.23 4.46 1.51 ;
		LAYER M1 ;
		RECT 8.945 2.095 9.14 3.82 ;
		LAYER M1 ;
		RECT 8.86 1.78 9.14 2.095 ;
		LAYER M1 ;
		RECT 4.22 0.84 4.41 1.23 ;
		LAYER M1 ;
		RECT 7.695 0.84 7.975 0.9 ;
		LAYER M1 ;
		RECT 4.22 0.65 7.975 0.84 ;
		LAYER M1 ;
		RECT 7.695 0.62 7.975 0.65 ;
		LAYER M1 ;
		RECT 8.885 0.9 9.08 1.78 ;
		LAYER M1 ;
		RECT 8.69 0.66 9.08 0.9 ;
		LAYER M1 ;
		RECT 8.69 0.62 8.97 0.66 ;
	END
END MMI_MUXI3C
MACRO MMI_MUXI4B
	CLASS CORE ;
	FOREIGN MMI_MUXI4B 0 0 ;
	SIZE 11.16 BY 6.2 ;
	SYMMETRY X Y ;
	SITE CORE1 ;
	PIN out
		DIRECTION output ;
		USE SIGNAL ;
		PORT
			LAYER M1 ;
			RECT 10.72 3.515 11.0 4.985 ;
			LAYER M1 ;
			RECT 10.725 2.98 10.92 3.515 ;
			LAYER M1 ;
			RECT 10.665 2.6 11.04 2.98 ;
			LAYER M1 ;
			RECT 10.725 1.375 10.92 2.6 ;
			LAYER M1 ;
			RECT 10.72 0.675 11.0 1.375 ;
		END
		AntennaDiffArea 0.91245 ;
	END out
	PIN in1
		DIRECTION input ;
		USE SIGNAL ;
		PORT
			LAYER M1 ;
			RECT 2.365 3.405 2.645 3.685 ;
			LAYER M1 ;
			RECT 2.415 2.36 2.61 3.405 ;
			LAYER M1 ;
			RECT 2.4 2.08 2.98 2.36 ;
			LAYER M1 ;
			RECT 2.415 1.955 2.98 2.08 ;
		END
		AntennaGateArea 0.3465 ;
	END in1
	PIN sel0
		DIRECTION input ;
		USE SIGNAL ;
		PORT
			LAYER M1 ;
			RECT 3.57 3.68 3.85 3.685 ;
			LAYER M1 ;
			RECT 3.57 3.405 3.925 3.68 ;
			LAYER M1 ;
			RECT 3.735 2.98 3.925 3.405 ;
			LAYER M1 ;
			RECT 3.735 2.6 4.22 2.98 ;
			LAYER M1 ;
			RECT 3.735 2.375 3.925 2.6 ;
			LAYER M1 ;
			RECT 3.6 2.11 3.925 2.375 ;
			LAYER M1 ;
			RECT 3.6 2.095 3.88 2.11 ;
		END
		AntennaGateArea 1.0395 ;
	END sel0
	PIN GND
		DIRECTION inout ;
		USE GROUND ;
		PORT
			LAYER M1 ;
			RECT 0.185 0.42 0.465 1.925 ;
			LAYER M1 ;
			RECT 8.995 1.855 9.275 1.86 ;
			LAYER M1 ;
			RECT 2.565 0.42 2.845 1.705 ;
			LAYER M1 ;
			RECT 8.98 1.58 9.275 1.855 ;
			LAYER M1 ;
			RECT 3.95 0.42 4.23 1.27 ;
			LAYER M1 ;
			RECT 6.455 0.42 6.735 1.265 ;
			LAYER M1 ;
			RECT 8.98 0.42 9.265 1.58 ;
			LAYER M1 ;
			RECT 10.13 0.42 10.41 1.375 ;
			LAYER M1 ;
			RECT 0.0 -0.42 11.16 0.42 ;
		END
	END GND
	PIN in2
		DIRECTION input ;
		USE SIGNAL ;
		PORT
			LAYER M1 ;
			RECT 4.14 3.405 4.655 3.685 ;
			LAYER M1 ;
			RECT 4.46 2.98 4.655 3.405 ;
			LAYER M1 ;
			RECT 4.46 2.6 4.84 2.98 ;
			LAYER M1 ;
			RECT 4.46 2.315 4.655 2.6 ;
			LAYER M1 ;
			RECT 4.125 2.12 4.655 2.315 ;
			LAYER M1 ;
			RECT 4.125 1.835 4.315 2.12 ;
			LAYER M1 ;
			RECT 3.645 1.64 4.315 1.835 ;
			LAYER M1 ;
			RECT 3.645 1.525 3.925 1.64 ;
		END
		AntennaGateArea 0.34425 ;
	END in2
	PIN sel1
		DIRECTION input ;
		USE SIGNAL ;
		PORT
			LAYER M1 ;
			RECT 10.045 2.93 10.42 2.98 ;
			LAYER M1 ;
			RECT 9.945 2.65 10.42 2.93 ;
			LAYER M1 ;
			RECT 10.045 2.6 10.42 2.65 ;
		END
		AntennaGateArea 0.51975 ;
	END sel1
	PIN VDD
		DIRECTION inout ;
		USE POWER ;
		PORT
			LAYER M1 ;
			RECT 0.0 5.78 11.16 6.62 ;
			LAYER M1 ;
			RECT 0.185 3.84 0.465 5.78 ;
			LAYER M1 ;
			RECT 2.565 4.055 2.845 5.78 ;
			LAYER M1 ;
			RECT 3.805 4.07 4.085 5.78 ;
			LAYER M1 ;
			RECT 6.38 4.055 6.66 5.78 ;
			LAYER M1 ;
			RECT 8.85 4.945 9.11 5.78 ;
			LAYER M1 ;
			RECT 8.85 3.5 9.175 4.945 ;
			LAYER M1 ;
			RECT 10.13 3.515 10.41 5.78 ;
			LAYER M1 ;
			RECT 8.895 3.495 9.175 3.5 ;
		END
	END VDD
	PIN in3
		DIRECTION input ;
		USE SIGNAL ;
		PORT
			LAYER M1 ;
			RECT 6.21 3.815 6.49 3.83 ;
			LAYER M1 ;
			RECT 6.21 3.55 6.585 3.815 ;
			LAYER M1 ;
			RECT 6.395 2.98 6.585 3.55 ;
			LAYER M1 ;
			RECT 6.32 2.6 6.7 2.98 ;
			LAYER M1 ;
			RECT 6.48 1.82 6.67 2.6 ;
			LAYER M1 ;
			RECT 6.375 1.555 6.67 1.82 ;
			LAYER M1 ;
			RECT 6.375 1.54 6.655 1.555 ;
		END
		AntennaGateArea 0.3465 ;
	END in3
	PIN in0
		DIRECTION input ;
		USE SIGNAL ;
		PORT
			LAYER M1 ;
			RECT 0.12 2.935 0.5 2.98 ;
			LAYER M1 ;
			RECT 0.12 2.655 0.54 2.935 ;
			LAYER M1 ;
			RECT 0.12 2.6 0.5 2.655 ;
		END
		AntennaGateArea 0.3465 ;
	END in0
	OBS
		LAYER M1 ;
		RECT 0.775 3.84 1.055 5.31 ;
		LAYER M1 ;
		RECT 1.365 3.84 1.645 5.31 ;
		LAYER M1 ;
		RECT 1.965 4.055 2.245 5.115 ;
		LAYER M1 ;
		RECT 3.18 5.115 3.37 5.12 ;
		LAYER M1 ;
		RECT 3.17 4.055 3.45 5.115 ;
		LAYER M1 ;
		RECT 5.615 5.325 5.895 5.34 ;
		LAYER M1 ;
		RECT 4.405 4.42 4.685 5.135 ;
		LAYER M1 ;
		RECT 5.01 4.47 5.29 4.95 ;
		LAYER M1 ;
		RECT 5.615 4.67 6.01 5.325 ;
		LAYER M1 ;
		RECT 4.405 4.075 4.69 4.42 ;
		LAYER M1 ;
		RECT 5.005 4.28 5.62 4.47 ;
		LAYER M1 ;
		RECT 0.775 1.925 0.965 3.84 ;
		LAYER M1 ;
		RECT 1.45 2.745 1.64 3.84 ;
		LAYER M1 ;
		RECT 1.97 3.195 2.165 4.055 ;
		LAYER M1 ;
		RECT 1.97 3.0 2.2 3.195 ;
		LAYER M1 ;
		RECT 1.45 2.465 1.81 2.745 ;
		LAYER M1 ;
		RECT 1.45 1.925 1.64 2.465 ;
		LAYER M1 ;
		RECT 0.775 1.225 1.055 1.925 ;
		LAYER M1 ;
		RECT 1.365 1.225 1.645 1.925 ;
		LAYER M1 ;
		RECT 2.01 1.705 2.2 3.0 ;
		LAYER M1 ;
		RECT 3.18 3.315 3.37 4.055 ;
		LAYER M1 ;
		RECT 4.405 3.885 5.23 4.075 ;
		LAYER M1 ;
		RECT 2.995 3.105 3.37 3.315 ;
		LAYER M1 ;
		RECT 2.995 3.035 3.375 3.105 ;
		LAYER M1 ;
		RECT 3.18 2.87 3.375 3.035 ;
		LAYER M1 ;
		RECT 1.965 1.425 2.245 1.705 ;
		LAYER M1 ;
		RECT 3.185 1.505 3.375 2.87 ;
		LAYER M1 ;
		RECT 5.04 1.92 5.23 3.885 ;
		LAYER M1 ;
		RECT 4.645 1.73 5.23 1.92 ;
		LAYER M1 ;
		RECT 5.43 2.755 5.62 4.28 ;
		LAYER M1 ;
		RECT 5.82 3.29 6.01 4.67 ;
		LAYER M1 ;
		RECT 7.1 4.35 7.38 5.49 ;
		LAYER M1 ;
		RECT 7.695 4.395 7.975 5.115 ;
		LAYER M1 ;
		RECT 9.485 5.535 9.68 5.545 ;
		LAYER M1 ;
		RECT 9.32 5.255 9.68 5.535 ;
		LAYER M1 ;
		RECT 7.1 4.02 7.495 4.35 ;
		LAYER M1 ;
		RECT 7.695 4.055 8.01 4.395 ;
		LAYER M1 ;
		RECT 5.82 3.095 6.12 3.29 ;
		LAYER M1 ;
		RECT 5.43 2.475 5.73 2.755 ;
		LAYER M1 ;
		RECT 3.165 1.225 3.445 1.505 ;
		LAYER M1 ;
		RECT 3.205 0.945 3.395 1.225 ;
		LAYER M1 ;
		RECT 3.205 0.94 3.615 0.945 ;
		LAYER M1 ;
		RECT 3.205 0.75 3.675 0.94 ;
		LAYER M1 ;
		RECT 3.395 0.66 3.675 0.75 ;
		LAYER M1 ;
		RECT 4.645 1.25 4.835 1.73 ;
		LAYER M1 ;
		RECT 5.43 1.53 5.62 2.475 ;
		LAYER M1 ;
		RECT 4.555 0.97 4.835 1.25 ;
		LAYER M1 ;
		RECT 5.245 1.335 5.62 1.53 ;
		LAYER M1 ;
		RECT 5.245 1.205 5.435 1.335 ;
		LAYER M1 ;
		RECT 5.155 0.925 5.435 1.205 ;
		LAYER M1 ;
		RECT 5.93 1.08 6.12 3.095 ;
		LAYER M1 ;
		RECT 6.815 3.735 7.095 3.775 ;
		LAYER M1 ;
		RECT 6.815 3.495 7.105 3.735 ;
		LAYER M1 ;
		RECT 6.915 2.105 7.105 3.495 ;
		LAYER M1 ;
		RECT 7.305 3.61 7.495 4.02 ;
		LAYER M1 ;
		RECT 7.305 3.4 7.57 3.61 ;
		LAYER M1 ;
		RECT 7.38 1.905 7.57 3.4 ;
		LAYER M1 ;
		RECT 7.185 1.76 7.57 1.905 ;
		LAYER M1 ;
		RECT 7.815 1.84 8.01 4.055 ;
		LAYER M1 ;
		RECT 8.3 3.84 8.58 4.9 ;
		LAYER M1 ;
		RECT 8.305 2.075 8.495 3.84 ;
		LAYER M1 ;
		RECT 9.485 4.215 9.68 5.255 ;
		LAYER M1 ;
		RECT 9.485 4.02 9.775 4.215 ;
		LAYER M1 ;
		RECT 9.495 3.515 9.775 4.02 ;
		LAYER M1 ;
		RECT 8.695 2.825 8.975 2.915 ;
		LAYER M1 ;
		RECT 9.505 2.825 9.695 3.515 ;
		LAYER M1 ;
		RECT 8.695 2.635 9.695 2.825 ;
		LAYER M1 ;
		RECT 8.715 2.63 9.695 2.635 ;
		LAYER M1 ;
		RECT 7.18 1.57 7.57 1.76 ;
		LAYER M1 ;
		RECT 5.76 0.8 6.12 1.08 ;
		LAYER M1 ;
		RECT 7.18 1.11 7.375 1.57 ;
		LAYER M1 ;
		RECT 7.785 1.56 8.065 1.84 ;
		LAYER M1 ;
		RECT 8.305 1.6 8.665 2.075 ;
		LAYER M1 ;
		RECT 7.14 0.83 7.42 1.11 ;
		LAYER M1 ;
		RECT 7.815 0.9 8.01 1.56 ;
		LAYER M1 ;
		RECT 8.385 1.375 8.665 1.6 ;
		LAYER M1 ;
		RECT 7.62 0.625 8.01 0.9 ;
		LAYER M1 ;
		RECT 7.62 0.62 7.9 0.625 ;
		LAYER M1 ;
		RECT 9.505 1.27 9.695 2.63 ;
		LAYER M1 ;
		RECT 9.495 0.955 9.775 1.27 ;
	END
END MMI_MUXI4B
MACRO MMI_MUXI4C
	CLASS CORE ;
	FOREIGN MMI_MUXI4C 0 0 ;
	SIZE 11.78 BY 6.2 ;
	SYMMETRY X Y ;
	SITE CORE1 ;
	PIN out
		DIRECTION output ;
		USE SIGNAL ;
		PORT
			LAYER M1 ;
			RECT 10.72 3.515 11.0 4.985 ;
			LAYER M1 ;
			RECT 10.725 2.98 10.92 3.515 ;
			LAYER M1 ;
			RECT 10.665 2.6 11.04 2.98 ;
			LAYER M1 ;
			RECT 10.725 1.375 10.92 2.6 ;
			LAYER M1 ;
			RECT 10.72 0.675 11.0 1.375 ;
		END
		AntennaDiffArea 1.0164 ;
	END out
	PIN in1
		DIRECTION input ;
		USE SIGNAL ;
		PORT
			LAYER M1 ;
			RECT 2.365 3.405 2.645 3.685 ;
			LAYER M1 ;
			RECT 2.415 2.36 2.61 3.405 ;
			LAYER M1 ;
			RECT 2.4 2.08 2.98 2.36 ;
			LAYER M1 ;
			RECT 2.415 1.955 2.98 2.08 ;
		END
		AntennaGateArea 0.3465 ;
	END in1
	PIN sel0
		DIRECTION input ;
		USE SIGNAL ;
		PORT
			LAYER M1 ;
			RECT 3.57 3.68 3.85 3.685 ;
			LAYER M1 ;
			RECT 3.57 3.405 3.925 3.68 ;
			LAYER M1 ;
			RECT 3.735 2.98 3.925 3.405 ;
			LAYER M1 ;
			RECT 3.735 2.6 4.22 2.98 ;
			LAYER M1 ;
			RECT 3.735 2.375 3.925 2.6 ;
			LAYER M1 ;
			RECT 3.6 2.11 3.925 2.375 ;
			LAYER M1 ;
			RECT 3.6 2.095 3.88 2.11 ;
		END
		AntennaGateArea 1.0395 ;
	END sel0
	PIN GND
		DIRECTION inout ;
		USE GROUND ;
		PORT
			LAYER M1 ;
			RECT 0.185 0.42 0.465 1.925 ;
			LAYER M1 ;
			RECT 8.995 1.855 9.275 1.86 ;
			LAYER M1 ;
			RECT 2.565 0.42 2.845 1.705 ;
			LAYER M1 ;
			RECT 8.98 1.58 9.275 1.855 ;
			LAYER M1 ;
			RECT 3.95 0.42 4.23 1.27 ;
			LAYER M1 ;
			RECT 6.455 0.42 6.735 1.265 ;
			LAYER M1 ;
			RECT 8.98 0.42 9.265 1.58 ;
			LAYER M1 ;
			RECT 10.13 0.42 10.41 1.375 ;
			LAYER M1 ;
			RECT 11.31 0.42 11.59 1.375 ;
			LAYER M1 ;
			RECT 0.0 -0.42 11.78 0.42 ;
		END
	END GND
	PIN in2
		DIRECTION input ;
		USE SIGNAL ;
		PORT
			LAYER M1 ;
			RECT 4.14 3.405 4.655 3.685 ;
			LAYER M1 ;
			RECT 4.46 2.98 4.655 3.405 ;
			LAYER M1 ;
			RECT 4.46 2.6 4.84 2.98 ;
			LAYER M1 ;
			RECT 4.46 2.315 4.655 2.6 ;
			LAYER M1 ;
			RECT 4.125 2.12 4.655 2.315 ;
			LAYER M1 ;
			RECT 4.125 1.835 4.315 2.12 ;
			LAYER M1 ;
			RECT 3.645 1.64 4.315 1.835 ;
			LAYER M1 ;
			RECT 3.645 1.525 3.925 1.64 ;
		END
		AntennaGateArea 0.34425 ;
	END in2
	PIN sel1
		DIRECTION input ;
		USE SIGNAL ;
		PORT
			LAYER M1 ;
			RECT 10.045 2.93 10.42 2.98 ;
			LAYER M1 ;
			RECT 9.945 2.65 10.42 2.93 ;
			LAYER M1 ;
			RECT 10.045 2.6 10.42 2.65 ;
		END
		AntennaGateArea 0.51975 ;
	END sel1
	PIN VDD
		DIRECTION inout ;
		USE POWER ;
		PORT
			LAYER M1 ;
			RECT 0.0 5.78 11.78 6.62 ;
			LAYER M1 ;
			RECT 0.185 3.84 0.465 5.78 ;
			LAYER M1 ;
			RECT 2.565 4.055 2.845 5.78 ;
			LAYER M1 ;
			RECT 3.805 4.07 4.085 5.78 ;
			LAYER M1 ;
			RECT 6.38 4.055 6.66 5.78 ;
			LAYER M1 ;
			RECT 8.85 4.945 9.11 5.78 ;
			LAYER M1 ;
			RECT 8.85 3.5 9.175 4.945 ;
			LAYER M1 ;
			RECT 10.13 3.515 10.41 5.78 ;
			LAYER M1 ;
			RECT 11.31 3.515 11.59 5.78 ;
			LAYER M1 ;
			RECT 8.895 3.495 9.175 3.5 ;
		END
	END VDD
	PIN in3
		DIRECTION input ;
		USE SIGNAL ;
		PORT
			LAYER M1 ;
			RECT 6.21 3.815 6.49 3.83 ;
			LAYER M1 ;
			RECT 6.21 3.55 6.585 3.815 ;
			LAYER M1 ;
			RECT 6.395 2.98 6.585 3.55 ;
			LAYER M1 ;
			RECT 6.32 2.6 6.7 2.98 ;
			LAYER M1 ;
			RECT 6.48 1.82 6.67 2.6 ;
			LAYER M1 ;
			RECT 6.375 1.555 6.67 1.82 ;
			LAYER M1 ;
			RECT 6.375 1.54 6.655 1.555 ;
		END
		AntennaGateArea 0.3465 ;
	END in3
	PIN in0
		DIRECTION input ;
		USE SIGNAL ;
		PORT
			LAYER M1 ;
			RECT 0.12 2.935 0.5 2.98 ;
			LAYER M1 ;
			RECT 0.12 2.655 0.54 2.935 ;
			LAYER M1 ;
			RECT 0.12 2.6 0.5 2.655 ;
		END
		AntennaGateArea 0.3465 ;
	END in0
	OBS
		LAYER M1 ;
		RECT 0.775 3.84 1.055 5.31 ;
		LAYER M1 ;
		RECT 1.365 3.84 1.645 5.31 ;
		LAYER M1 ;
		RECT 1.965 4.055 2.245 5.115 ;
		LAYER M1 ;
		RECT 3.18 5.115 3.37 5.12 ;
		LAYER M1 ;
		RECT 3.17 4.055 3.45 5.115 ;
		LAYER M1 ;
		RECT 5.615 5.325 5.895 5.34 ;
		LAYER M1 ;
		RECT 4.405 4.42 4.685 5.135 ;
		LAYER M1 ;
		RECT 5.01 4.47 5.29 4.95 ;
		LAYER M1 ;
		RECT 5.615 4.67 6.01 5.325 ;
		LAYER M1 ;
		RECT 4.405 4.075 4.69 4.42 ;
		LAYER M1 ;
		RECT 5.005 4.28 5.62 4.47 ;
		LAYER M1 ;
		RECT 0.775 1.925 0.965 3.84 ;
		LAYER M1 ;
		RECT 1.45 2.745 1.64 3.84 ;
		LAYER M1 ;
		RECT 1.97 3.195 2.165 4.055 ;
		LAYER M1 ;
		RECT 1.97 3.0 2.2 3.195 ;
		LAYER M1 ;
		RECT 1.45 2.465 1.81 2.745 ;
		LAYER M1 ;
		RECT 1.45 1.925 1.64 2.465 ;
		LAYER M1 ;
		RECT 0.775 1.225 1.055 1.925 ;
		LAYER M1 ;
		RECT 1.365 1.225 1.645 1.925 ;
		LAYER M1 ;
		RECT 2.01 1.705 2.2 3.0 ;
		LAYER M1 ;
		RECT 3.18 3.315 3.37 4.055 ;
		LAYER M1 ;
		RECT 4.405 3.885 5.23 4.075 ;
		LAYER M1 ;
		RECT 2.995 3.105 3.37 3.315 ;
		LAYER M1 ;
		RECT 2.995 3.035 3.375 3.105 ;
		LAYER M1 ;
		RECT 3.18 2.87 3.375 3.035 ;
		LAYER M1 ;
		RECT 1.965 1.425 2.245 1.705 ;
		LAYER M1 ;
		RECT 3.185 1.505 3.375 2.87 ;
		LAYER M1 ;
		RECT 5.04 1.92 5.23 3.885 ;
		LAYER M1 ;
		RECT 4.645 1.73 5.23 1.92 ;
		LAYER M1 ;
		RECT 5.43 2.755 5.62 4.28 ;
		LAYER M1 ;
		RECT 5.82 3.29 6.01 4.67 ;
		LAYER M1 ;
		RECT 7.1 4.35 7.38 5.49 ;
		LAYER M1 ;
		RECT 7.695 4.395 7.975 5.115 ;
		LAYER M1 ;
		RECT 9.485 5.535 9.68 5.545 ;
		LAYER M1 ;
		RECT 9.32 5.255 9.68 5.535 ;
		LAYER M1 ;
		RECT 7.1 4.02 7.495 4.35 ;
		LAYER M1 ;
		RECT 7.695 4.055 8.01 4.395 ;
		LAYER M1 ;
		RECT 5.82 3.095 6.12 3.29 ;
		LAYER M1 ;
		RECT 5.43 2.475 5.73 2.755 ;
		LAYER M1 ;
		RECT 3.165 1.225 3.445 1.505 ;
		LAYER M1 ;
		RECT 3.205 0.945 3.395 1.225 ;
		LAYER M1 ;
		RECT 3.205 0.94 3.615 0.945 ;
		LAYER M1 ;
		RECT 3.205 0.75 3.675 0.94 ;
		LAYER M1 ;
		RECT 3.395 0.66 3.675 0.75 ;
		LAYER M1 ;
		RECT 4.645 1.25 4.835 1.73 ;
		LAYER M1 ;
		RECT 5.43 1.53 5.62 2.475 ;
		LAYER M1 ;
		RECT 4.555 0.97 4.835 1.25 ;
		LAYER M1 ;
		RECT 5.245 1.335 5.62 1.53 ;
		LAYER M1 ;
		RECT 5.245 1.205 5.435 1.335 ;
		LAYER M1 ;
		RECT 5.155 0.925 5.435 1.205 ;
		LAYER M1 ;
		RECT 5.93 1.08 6.12 3.095 ;
		LAYER M1 ;
		RECT 6.815 3.735 7.095 3.775 ;
		LAYER M1 ;
		RECT 6.815 3.495 7.105 3.735 ;
		LAYER M1 ;
		RECT 6.915 2.105 7.105 3.495 ;
		LAYER M1 ;
		RECT 7.305 3.61 7.495 4.02 ;
		LAYER M1 ;
		RECT 7.305 3.4 7.57 3.61 ;
		LAYER M1 ;
		RECT 7.38 1.905 7.57 3.4 ;
		LAYER M1 ;
		RECT 7.185 1.76 7.57 1.905 ;
		LAYER M1 ;
		RECT 7.815 1.84 8.01 4.055 ;
		LAYER M1 ;
		RECT 8.3 3.84 8.58 4.9 ;
		LAYER M1 ;
		RECT 8.305 2.075 8.495 3.84 ;
		LAYER M1 ;
		RECT 9.485 4.215 9.68 5.255 ;
		LAYER M1 ;
		RECT 9.485 4.02 9.775 4.215 ;
		LAYER M1 ;
		RECT 9.495 3.515 9.775 4.02 ;
		LAYER M1 ;
		RECT 8.695 2.825 8.975 2.915 ;
		LAYER M1 ;
		RECT 9.505 2.825 9.695 3.515 ;
		LAYER M1 ;
		RECT 8.695 2.635 9.695 2.825 ;
		LAYER M1 ;
		RECT 8.715 2.63 9.695 2.635 ;
		LAYER M1 ;
		RECT 7.18 1.57 7.57 1.76 ;
		LAYER M1 ;
		RECT 5.76 0.8 6.12 1.08 ;
		LAYER M1 ;
		RECT 7.18 1.11 7.375 1.57 ;
		LAYER M1 ;
		RECT 7.785 1.56 8.065 1.84 ;
		LAYER M1 ;
		RECT 8.305 1.6 8.665 2.075 ;
		LAYER M1 ;
		RECT 7.14 0.83 7.42 1.11 ;
		LAYER M1 ;
		RECT 7.815 0.9 8.01 1.56 ;
		LAYER M1 ;
		RECT 8.385 1.375 8.665 1.6 ;
		LAYER M1 ;
		RECT 7.62 0.625 8.01 0.9 ;
		LAYER M1 ;
		RECT 7.62 0.62 7.9 0.625 ;
		LAYER M1 ;
		RECT 9.505 1.27 9.695 2.63 ;
		LAYER M1 ;
		RECT 9.495 0.955 9.775 1.27 ;
	END
END MMI_MUXI4C
MACRO MMI_NAND2A
	CLASS CORE ;
	FOREIGN MMI_NAND2A 0 0 ;
	SIZE 1.86 BY 6.2 ;
	SYMMETRY X Y ;
	SITE CORE1 ;
	PIN out
		DIRECTION output ;
		USE SIGNAL ;
		PORT
			LAYER M1 ;
			RECT 0.765 3.505 1.045 4.205 ;
			LAYER M1 ;
			RECT 0.765 2.385 0.955 3.505 ;
			LAYER M1 ;
			RECT 0.645 2.38 0.955 2.385 ;
			LAYER M1 ;
			RECT 0.395 2.36 0.955 2.38 ;
			LAYER M1 ;
			RECT 0.12 2.19 0.955 2.36 ;
			LAYER M1 ;
			RECT 0.12 1.98 0.675 2.19 ;
			LAYER M1 ;
			RECT 0.395 1.68 0.675 1.98 ;
		END
		AntennaDiffArea 0.64295 ;
	END out
	PIN in1
		DIRECTION input ;
		USE SIGNAL ;
		PORT
			LAYER M1 ;
			RECT 1.36 2.93 1.74 2.98 ;
			LAYER M1 ;
			RECT 1.27 2.65 1.74 2.93 ;
			LAYER M1 ;
			RECT 1.36 2.6 1.74 2.65 ;
		END
		AntennaGateArea 0.231 ;
	END in1
	PIN GND
		DIRECTION inout ;
		USE GROUND ;
		PORT
			LAYER M1 ;
			RECT 1.355 0.42 1.635 2.38 ;
			LAYER M1 ;
			RECT 0.0 -0.42 1.86 0.42 ;
		END
	END GND
	PIN VDD
		DIRECTION inout ;
		USE POWER ;
		PORT
			LAYER M1 ;
			RECT 0.0 5.78 1.86 6.62 ;
			LAYER M1 ;
			RECT 0.175 3.505 0.455 5.78 ;
			LAYER M1 ;
			RECT 1.355 3.505 1.635 5.78 ;
		END
	END VDD
	PIN in0
		DIRECTION input ;
		USE SIGNAL ;
		PORT
			LAYER M1 ;
			RECT 0.12 2.94 0.51 2.98 ;
			LAYER M1 ;
			RECT 0.12 2.66 0.545 2.94 ;
			LAYER M1 ;
			RECT 0.12 2.6 0.5 2.66 ;
		END
		AntennaGateArea 0.231 ;
	END in0
	OBS
	END
END MMI_NAND2A
MACRO MMI_NAND2B
	CLASS CORE ;
	FOREIGN MMI_NAND2B 0 0 ;
	SIZE 1.86 BY 6.2 ;
	SYMMETRY X Y ;
	SITE CORE1 ;
	PIN out
		DIRECTION output ;
		USE SIGNAL ;
		PORT
			LAYER M1 ;
			RECT 0.75 3.805 1.03 5.275 ;
			LAYER M1 ;
			RECT 0.755 3.465 0.945 3.805 ;
			LAYER M1 ;
			RECT 0.245 3.27 0.945 3.465 ;
			LAYER M1 ;
			RECT 0.245 2.98 0.435 3.27 ;
			LAYER M1 ;
			RECT 0.12 2.6 0.5 2.98 ;
			LAYER M1 ;
			RECT 0.245 2.125 0.435 2.6 ;
			LAYER M1 ;
			RECT 0.16 0.655 0.44 2.125 ;
		END
		AntennaDiffArea 1.2859 ;
	END out
	PIN in1
		DIRECTION input ;
		USE SIGNAL ;
		PORT
			LAYER M1 ;
			RECT 1.36 3.51 1.74 3.6 ;
			LAYER M1 ;
			RECT 1.15 3.23 1.74 3.51 ;
			LAYER M1 ;
			RECT 1.36 3.22 1.74 3.23 ;
		END
		AntennaGateArea 0.462 ;
	END in1
	PIN GND
		DIRECTION inout ;
		USE GROUND ;
		PORT
			LAYER M1 ;
			RECT 1.13 0.42 1.41 2.125 ;
			LAYER M1 ;
			RECT 0.0 -0.42 1.86 0.42 ;
		END
	END GND
	PIN VDD
		DIRECTION inout ;
		USE POWER ;
		PORT
			LAYER M1 ;
			RECT 0.0 5.78 1.86 6.62 ;
			LAYER M1 ;
			RECT 0.16 3.805 0.44 5.78 ;
			LAYER M1 ;
			RECT 1.34 3.805 1.62 5.78 ;
		END
	END VDD
	PIN in0
		DIRECTION input ;
		USE SIGNAL ;
		PORT
			LAYER M1 ;
			RECT 0.74 2.93 1.12 2.98 ;
			LAYER M1 ;
			RECT 0.7 2.65 1.12 2.93 ;
			LAYER M1 ;
			RECT 0.74 2.6 1.12 2.65 ;
		END
		AntennaGateArea 0.462 ;
	END in0
	OBS
	END
END MMI_NAND2B
MACRO MMI_NAND2C
	CLASS CORE ;
	FOREIGN MMI_NAND2C 0 0 ;
	SIZE 3.1 BY 6.2 ;
	SYMMETRY X Y ;
	SITE CORE1 ;
	PIN out
		DIRECTION output ;
		USE SIGNAL ;
		PORT
			LAYER M1 ;
			RECT 0.775 3.995 1.055 5.27 ;
			LAYER M1 ;
			RECT 1.955 3.995 2.235 5.27 ;
			LAYER M1 ;
			RECT 0.755 3.8 2.245 3.995 ;
			LAYER M1 ;
			RECT 1.31 3.6 1.595 3.8 ;
			LAYER M1 ;
			RECT 1.31 3.505 1.74 3.6 ;
			LAYER M1 ;
			RECT 1.205 3.22 1.74 3.505 ;
			LAYER M1 ;
			RECT 1.205 2.69 1.4 3.22 ;
			LAYER M1 ;
			RECT 1.125 1.22 1.405 2.69 ;
		END
		AntennaDiffArea 2.0328 ;
	END out
	PIN in1
		DIRECTION input ;
		USE SIGNAL ;
		PORT
			LAYER M1 ;
			RECT 1.98 3.22 2.36 3.6 ;
		END
		AntennaGateArea 0.924 ;
	END in1
	PIN GND
		DIRECTION inout ;
		USE GROUND ;
		PORT
			LAYER M1 ;
			RECT 0.16 0.42 0.44 2.69 ;
			LAYER M1 ;
			RECT 2.085 0.42 2.365 2.69 ;
			LAYER M1 ;
			RECT 0.0 -0.42 3.1 0.42 ;
		END
	END GND
	PIN VDD
		DIRECTION inout ;
		USE POWER ;
		PORT
			LAYER M1 ;
			RECT 0.0 5.78 3.1 6.62 ;
			LAYER M1 ;
			RECT 0.185 3.8 0.465 5.78 ;
			LAYER M1 ;
			RECT 1.365 4.21 1.645 5.78 ;
			LAYER M1 ;
			RECT 2.545 3.8 2.825 5.78 ;
		END
	END VDD
	PIN in0
		DIRECTION input ;
		USE SIGNAL ;
		PORT
			LAYER M1 ;
			RECT 0.12 3.555 0.5 3.6 ;
			LAYER M1 ;
			RECT 0.12 3.55 0.655 3.555 ;
			LAYER M1 ;
			RECT 0.12 3.27 0.935 3.55 ;
			LAYER M1 ;
			RECT 0.12 3.22 0.5 3.27 ;
		END
		AntennaGateArea 0.924 ;
	END in0
	OBS
	END
END MMI_NAND2C
MACRO MMI_NAND2D
	CLASS CORE ;
	FOREIGN MMI_NAND2D 0 0 ;
	SIZE 5.58 BY 6.2 ;
	SYMMETRY X Y ;
	SITE CORE1 ;
	PIN out
		DIRECTION output ;
		USE SIGNAL ;
		PORT
			LAYER M1 ;
			RECT 0.75 4.05 1.03 5.325 ;
			LAYER M1 ;
			RECT 1.93 4.05 2.21 5.325 ;
			LAYER M1 ;
			RECT 3.11 4.05 3.39 5.325 ;
			LAYER M1 ;
			RECT 4.29 4.05 4.57 5.325 ;
			LAYER M1 ;
			RECT 0.75 3.855 4.66 4.05 ;
			LAYER M1 ;
			RECT 2.625 3.6 2.955 3.855 ;
			LAYER M1 ;
			RECT 2.6 3.22 2.98 3.6 ;
			LAYER M1 ;
			RECT 2.625 2.7 2.955 3.22 ;
			LAYER M1 ;
			RECT 1.12 2.505 3.32 2.7 ;
			LAYER M1 ;
			RECT 1.12 1.225 1.4 2.505 ;
			LAYER M1 ;
			RECT 3.04 1.225 3.32 2.505 ;
		END
		AntennaDiffArea 4.0656 ;
	END out
	PIN in1
		DIRECTION input ;
		USE SIGNAL ;
		PORT
			LAYER M1 ;
			RECT 3.84 3.55 4.22 3.6 ;
			LAYER M1 ;
			RECT 3.48 3.27 4.22 3.55 ;
			LAYER M1 ;
			RECT 3.84 3.22 4.22 3.27 ;
		END
		AntennaGateArea 1.848 ;
	END in1
	PIN GND
		DIRECTION inout ;
		USE GROUND ;
		PORT
			LAYER M1 ;
			RECT 0.16 0.42 0.44 2.695 ;
			LAYER M1 ;
			RECT 2.08 0.42 2.36 2.285 ;
			LAYER M1 ;
			RECT 4.0 0.42 4.28 2.695 ;
			LAYER M1 ;
			RECT 0.0 -0.42 5.58 0.42 ;
		END
	END GND
	PIN VDD
		DIRECTION inout ;
		USE POWER ;
		PORT
			LAYER M1 ;
			RECT 0.0 5.78 5.58 6.62 ;
			LAYER M1 ;
			RECT 0.16 3.855 0.44 5.78 ;
			LAYER M1 ;
			RECT 1.34 4.265 1.62 5.78 ;
			LAYER M1 ;
			RECT 2.52 4.265 2.8 5.78 ;
			LAYER M1 ;
			RECT 3.7 4.265 3.98 5.78 ;
			LAYER M1 ;
			RECT 4.88 3.855 5.16 5.78 ;
		END
	END VDD
	PIN in0
		DIRECTION input ;
		USE SIGNAL ;
		PORT
			LAYER M1 ;
			RECT 1.36 3.55 1.74 3.6 ;
			LAYER M1 ;
			RECT 1.36 3.27 2.045 3.55 ;
			LAYER M1 ;
			RECT 1.36 3.22 1.74 3.27 ;
		END
		AntennaGateArea 1.848 ;
	END in0
	OBS
	END
END MMI_NAND2D
MACRO MMI_NAND3A
	CLASS CORE ;
	FOREIGN MMI_NAND3A 0 0 ;
	SIZE 2.48 BY 6.2 ;
	SYMMETRY X Y ;
	SITE CORE1 ;
	PIN out
		DIRECTION output ;
		USE SIGNAL ;
		PORT
			LAYER M1 ;
			RECT 0.16 4.62 0.44 5.13 ;
			LAYER M1 ;
			RECT 1.34 4.62 1.62 5.13 ;
			LAYER M1 ;
			RECT 0.16 4.43 1.64 4.62 ;
			LAYER M1 ;
			RECT 0.16 3.6 0.355 4.43 ;
			LAYER M1 ;
			RECT 0.12 3.22 0.5 3.6 ;
			LAYER M1 ;
			RECT 0.16 2.685 0.355 3.22 ;
			LAYER M1 ;
			RECT 0.16 1.6 0.44 2.685 ;
		END
		AntennaDiffArea 1.099175 ;
	END out
	PIN in1
		DIRECTION input ;
		USE SIGNAL ;
		PORT
			LAYER M1 ;
			RECT 1.36 3.55 1.74 3.6 ;
			LAYER M1 ;
			RECT 1.08 3.27 1.74 3.55 ;
			LAYER M1 ;
			RECT 1.36 3.22 1.74 3.27 ;
		END
		AntennaGateArea 0.28875 ;
	END in1
	PIN GND
		DIRECTION inout ;
		USE GROUND ;
		PORT
			LAYER M1 ;
			RECT 1.49 0.42 1.77 2.685 ;
			LAYER M1 ;
			RECT 0.0 -0.42 2.48 0.42 ;
		END
	END GND
	PIN in2
		DIRECTION input ;
		USE SIGNAL ;
		PORT
			LAYER M1 ;
			RECT 1.98 4.165 2.36 4.22 ;
			LAYER M1 ;
			RECT 1.71 3.885 2.36 4.165 ;
			LAYER M1 ;
			RECT 1.98 3.84 2.36 3.885 ;
		END
		AntennaGateArea 0.28875 ;
	END in2
	PIN VDD
		DIRECTION inout ;
		USE POWER ;
		PORT
			LAYER M1 ;
			RECT 0.0 5.78 2.48 6.62 ;
			LAYER M1 ;
			RECT 0.75 4.85 1.03 5.78 ;
			LAYER M1 ;
			RECT 1.93 4.43 2.21 5.78 ;
		END
	END VDD
	PIN in0
		DIRECTION input ;
		USE SIGNAL ;
		PORT
			LAYER M1 ;
			RECT 0.74 4.13 1.12 4.22 ;
			LAYER M1 ;
			RECT 0.575 3.85 1.12 4.13 ;
			LAYER M1 ;
			RECT 0.74 3.84 1.12 3.85 ;
		END
		AntennaGateArea 0.28875 ;
	END in0
	OBS
	END
END MMI_NAND3A
MACRO MMI_NAND3B
	CLASS CORE ;
	FOREIGN MMI_NAND3B 0 0 ;
	SIZE 3.72 BY 6.2 ;
	SYMMETRY X Y ;
	SITE CORE1 ;
	PIN out
		DIRECTION output ;
		USE SIGNAL ;
		PORT
			LAYER M1 ;
			RECT 0.72 3.695 1.0 4.975 ;
			LAYER M1 ;
			RECT 1.915 3.695 2.195 4.975 ;
			LAYER M1 ;
			RECT 0.72 3.505 2.265 3.695 ;
			LAYER M1 ;
			RECT 2.075 2.295 2.265 3.505 ;
			LAYER M1 ;
			RECT 0.75 2.015 2.985 2.295 ;
		END
		AntennaDiffArea 2.196375 ;
	END out
	PIN in1
		DIRECTION input ;
		USE SIGNAL ;
		PORT
			LAYER M1 ;
			RECT 0.745 2.98 1.025 3.19 ;
			LAYER M1 ;
			RECT 0.74 2.6 1.12 2.98 ;
		END
		AntennaGateArea 0.57675 ;
	END in1
	PIN GND
		DIRECTION inout ;
		USE GROUND ;
		PORT
			LAYER M1 ;
			RECT 1.43 0.965 2.27 1.01 ;
			LAYER M1 ;
			RECT 0.75 0.685 2.985 0.965 ;
			LAYER M1 ;
			RECT 1.43 0.42 2.27 0.685 ;
			LAYER M1 ;
			RECT 0.0 -0.42 3.72 0.42 ;
		END
	END GND
	PIN in2
		DIRECTION input ;
		USE SIGNAL ;
		PORT
			LAYER M1 ;
			RECT 3.1 2.93 3.6 2.98 ;
			LAYER M1 ;
			RECT 2.935 2.65 3.6 2.93 ;
			LAYER M1 ;
			RECT 3.1 2.6 3.6 2.65 ;
		END
		AntennaGateArea 0.57675 ;
	END in2
	PIN VDD
		DIRECTION inout ;
		USE POWER ;
		PORT
			LAYER M1 ;
			RECT 0.0 5.78 3.72 6.62 ;
			LAYER M1 ;
			RECT 1.325 3.915 1.605 5.78 ;
			LAYER M1 ;
			RECT 2.505 3.505 2.785 5.78 ;
		END
	END VDD
	PIN in0
		DIRECTION input ;
		USE SIGNAL ;
		PORT
			LAYER M1 ;
			RECT 1.36 2.93 1.74 2.98 ;
			LAYER M1 ;
			RECT 1.36 2.65 1.8 2.93 ;
			LAYER M1 ;
			RECT 1.36 2.6 1.74 2.65 ;
		END
		AntennaGateArea 0.57675 ;
	END in0
	OBS
	END
END MMI_NAND3B
MACRO MMI_NAND3C
	CLASS CORE ;
	FOREIGN MMI_NAND3C 0 0 ;
	SIZE 6.2 BY 6.2 ;
	SYMMETRY X Y ;
	SITE CORE1 ;
	PIN out
		DIRECTION output ;
		USE SIGNAL ;
		PORT
			LAYER M1 ;
			RECT 1.595 3.775 1.875 5.05 ;
			LAYER M1 ;
			RECT 2.775 3.775 3.055 5.05 ;
			LAYER M1 ;
			RECT 3.98 3.775 4.26 5.05 ;
			LAYER M1 ;
			RECT 0.12 3.375 0.5 3.6 ;
			LAYER M1 ;
			RECT 1.595 3.58 4.26 3.775 ;
			LAYER M1 ;
			RECT 1.595 3.375 1.79 3.58 ;
			LAYER M1 ;
			RECT 0.12 3.18 1.79 3.375 ;
			LAYER M1 ;
			RECT 0.19 2.395 0.475 3.18 ;
			LAYER M1 ;
			RECT 0.2 1.12 0.48 2.395 ;
			LAYER M1 ;
			RECT 1.38 1.12 1.66 1.985 ;
			LAYER M1 ;
			RECT 0.2 0.925 1.66 1.12 ;
		END
		AntennaDiffArea 3.3341 ;
	END out
	PIN in1
		DIRECTION input ;
		USE SIGNAL ;
		PORT
			LAYER M1 ;
			RECT 2.6 2.885 2.98 2.98 ;
			LAYER M1 ;
			RECT 2.6 2.605 3.065 2.885 ;
			LAYER M1 ;
			RECT 2.6 2.6 2.98 2.605 ;
		END
		AntennaGateArea 1.155 ;
	END in1
	PIN GND
		DIRECTION inout ;
		USE GROUND ;
		PORT
			LAYER M1 ;
			RECT 4.33 0.42 4.61 1.985 ;
			LAYER M1 ;
			RECT 5.51 0.42 5.79 2.395 ;
			LAYER M1 ;
			RECT 0.0 -0.42 6.2 0.42 ;
		END
	END GND
	PIN in2
		DIRECTION input ;
		USE SIGNAL ;
		PORT
			LAYER M1 ;
			RECT 4.46 2.885 4.84 2.98 ;
			LAYER M1 ;
			RECT 4.285 2.605 4.84 2.885 ;
			LAYER M1 ;
			RECT 4.46 2.6 4.84 2.605 ;
		END
		AntennaGateArea 1.155 ;
	END in2
	PIN VDD
		DIRECTION inout ;
		USE POWER ;
		PORT
			LAYER M1 ;
			RECT 0.0 5.78 6.2 6.62 ;
			LAYER M1 ;
			RECT 1.005 3.58 1.285 5.78 ;
			LAYER M1 ;
			RECT 2.185 3.99 2.465 5.78 ;
			LAYER M1 ;
			RECT 3.39 3.99 3.67 5.78 ;
			LAYER M1 ;
			RECT 4.57 3.58 4.85 5.78 ;
		END
	END VDD
	PIN in0
		DIRECTION input ;
		USE SIGNAL ;
		PORT
			LAYER M1 ;
			RECT 1.36 2.93 1.74 2.98 ;
			LAYER M1 ;
			RECT 1.1 2.65 1.74 2.93 ;
			LAYER M1 ;
			RECT 1.36 2.6 1.74 2.65 ;
		END
		AntennaGateArea 1.155 ;
	END in0
	OBS
		LAYER M1 ;
		RECT 0.79 2.395 2.245 2.4 ;
		LAYER M1 ;
		RECT 0.79 2.21 2.25 2.395 ;
		LAYER M1 ;
		RECT 2.555 2.21 5.2 2.4 ;
		LAYER M1 ;
		RECT 0.79 1.335 1.07 2.21 ;
		LAYER M1 ;
		RECT 1.97 1.12 2.25 2.21 ;
		LAYER M1 ;
		RECT 2.56 1.335 2.84 2.21 ;
		LAYER M1 ;
		RECT 3.15 1.12 3.43 1.985 ;
		LAYER M1 ;
		RECT 1.97 0.925 3.43 1.12 ;
		LAYER M1 ;
		RECT 3.74 0.925 4.02 2.21 ;
		LAYER M1 ;
		RECT 4.92 0.925 5.2 2.21 ;
	END
END MMI_NAND3C
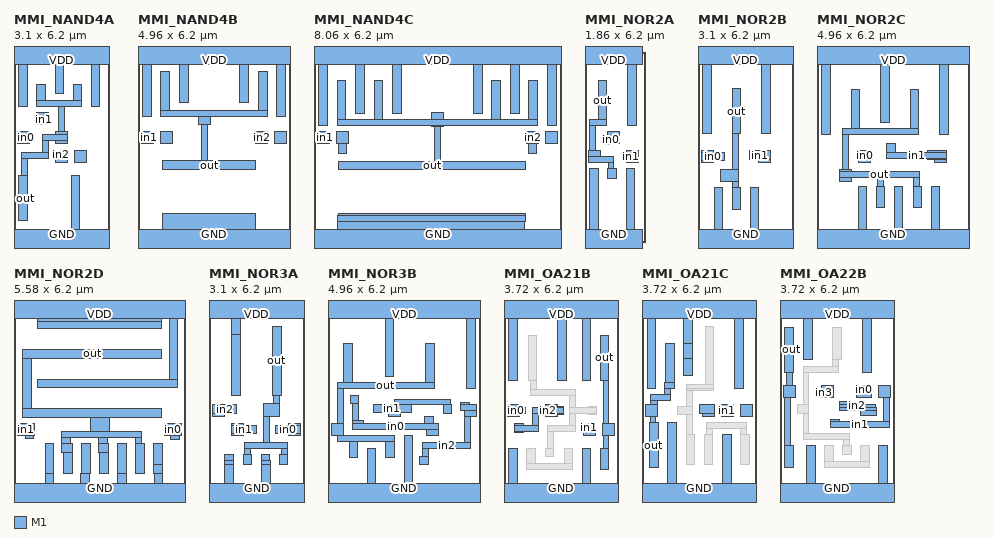
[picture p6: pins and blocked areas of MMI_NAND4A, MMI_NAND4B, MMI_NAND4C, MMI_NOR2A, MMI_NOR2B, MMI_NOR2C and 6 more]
MACRO MMI_NAND4A
	CLASS CORE ;
	FOREIGN MMI_NAND4A 0 0 ;
	SIZE 3.1 BY 6.2 ;
	SYMMETRY X Y ;
	SITE CORE1 ;
	PIN out
		DIRECTION output ;
		USE SIGNAL ;
		PORT
			LAYER M1 ;
			RECT 0.75 4.625 1.03 5.135 ;
			LAYER M1 ;
			RECT 1.93 4.625 2.21 5.135 ;
			LAYER M1 ;
			RECT 0.75 4.435 2.21 4.625 ;
			LAYER M1 ;
			RECT 1.44 3.6 1.635 4.435 ;
			LAYER M1 ;
			RECT 1.36 3.505 1.74 3.6 ;
			LAYER M1 ;
			RECT 0.92 3.315 1.74 3.505 ;
			LAYER M1 ;
			RECT 0.92 2.93 1.115 3.315 ;
			LAYER M1 ;
			RECT 1.36 3.22 1.74 3.315 ;
			LAYER M1 ;
			RECT 0.245 2.735 1.115 2.93 ;
			LAYER M1 ;
			RECT 0.245 2.165 0.435 2.735 ;
			LAYER M1 ;
			RECT 0.16 0.695 0.44 2.165 ;
		END
		AntennaDiffArea 1.2859 ;
	END out
	PIN in1
		DIRECTION input ;
		USE SIGNAL ;
		PORT
			LAYER M1 ;
			RECT 0.74 4.13 1.12 4.22 ;
			LAYER M1 ;
			RECT 0.74 3.85 1.205 4.13 ;
			LAYER M1 ;
			RECT 0.74 3.84 1.12 3.85 ;
		END
		AntennaGateArea 0.3465 ;
	END in1
	PIN GND
		DIRECTION inout ;
		USE GROUND ;
		PORT
			LAYER M1 ;
			RECT 1.86 0.42 2.14 2.165 ;
			LAYER M1 ;
			RECT 0.0 -0.42 3.1 0.42 ;
		END
	END GND
	PIN in2
		DIRECTION input ;
		USE SIGNAL ;
		PORT
			LAYER M1 ;
			RECT 1.32 2.7 1.74 2.98 ;
			LAYER M1 ;
			RECT 1.36 2.6 1.74 2.7 ;
		END
		AntennaGateArea 0.3465 ;
	END in2
	PIN VDD
		DIRECTION inout ;
		USE POWER ;
		PORT
			LAYER M1 ;
			RECT 0.0 5.78 3.1 6.62 ;
			LAYER M1 ;
			RECT 0.16 4.435 0.44 5.78 ;
			LAYER M1 ;
			RECT 1.34 4.855 1.62 5.78 ;
			LAYER M1 ;
			RECT 2.52 4.435 2.8 5.78 ;
		END
	END VDD
	PIN in3
		DIRECTION input ;
		USE SIGNAL ;
		PORT
			LAYER M1 ;
			RECT 1.98 2.6 2.36 2.98 ;
		END
		AntennaGateArea 0.3465 ;
	END in3
	PIN in0
		DIRECTION input ;
		USE SIGNAL ;
		PORT
			LAYER M1 ;
			RECT 0.12 3.55 0.5 3.6 ;
			LAYER M1 ;
			RECT 0.12 3.27 0.635 3.55 ;
			LAYER M1 ;
			RECT 0.12 3.22 0.5 3.27 ;
		END
		AntennaGateArea 0.3465 ;
	END in0
	OBS
	END
END MMI_NAND4A
MACRO MMI_NAND4B
	CLASS CORE ;
	FOREIGN MMI_NAND4B 0 0 ;
	SIZE 4.96 BY 6.2 ;
	SYMMETRY X Y ;
	SITE CORE1 ;
	PIN out
		DIRECTION output ;
		USE SIGNAL ;
		PORT
			LAYER M1 ;
			RECT 0.75 4.295 1.03 5.575 ;
			LAYER M1 ;
			RECT 3.93 4.295 4.21 5.575 ;
			LAYER M1 ;
			RECT 0.75 4.105 4.21 4.295 ;
			LAYER M1 ;
			RECT 1.98 3.83 2.36 4.105 ;
			LAYER M1 ;
			RECT 2.08 2.645 2.275 3.83 ;
			LAYER M1 ;
			RECT 0.815 2.365 3.83 2.645 ;
		END
		AntennaDiffArea 2.619975 ;
	END out
	PIN in1
		DIRECTION input ;
		USE SIGNAL ;
		PORT
			LAYER M1 ;
			RECT 0.12 3.22 0.5 3.6 ;
		END
		AntennaGateArea 0.69375 ;
	END in1
	PIN GND
		DIRECTION inout ;
		USE GROUND ;
		PORT
			LAYER M1 ;
			RECT 0.815 0.42 3.83 0.945 ;
			LAYER M1 ;
			RECT 0.0 -0.42 4.96 0.42 ;
		END
	END GND
	PIN in2
		DIRECTION input ;
		USE SIGNAL ;
		PORT
			LAYER M1 ;
			RECT 3.84 3.22 4.22 3.6 ;
		END
		AntennaGateArea 0.69375 ;
	END in2
	PIN VDD
		DIRECTION inout ;
		USE POWER ;
		PORT
			LAYER M1 ;
			RECT 0.0 5.78 4.96 6.62 ;
			LAYER M1 ;
			RECT 0.16 4.105 0.44 5.78 ;
			LAYER M1 ;
			RECT 1.36 4.56 1.64 5.78 ;
			LAYER M1 ;
			RECT 3.32 4.56 3.6 5.78 ;
			LAYER M1 ;
			RECT 4.52 4.105 4.8 5.78 ;
		END
	END VDD
	PIN in3
		DIRECTION input ;
		USE SIGNAL ;
		PORT
			LAYER M1 ;
			RECT 4.46 3.22 4.84 3.6 ;
		END
		AntennaGateArea 0.69375 ;
	END in3
	PIN in0
		DIRECTION input ;
		USE SIGNAL ;
		PORT
			LAYER M1 ;
			RECT 0.74 3.22 1.12 3.6 ;
		END
		AntennaGateArea 0.69375 ;
	END in0
	OBS
	END
END MMI_NAND4B
MACRO MMI_NAND4C
	CLASS CORE ;
	FOREIGN MMI_NAND4C 0 0 ;
	SIZE 8.06 BY 6.2 ;
	SYMMETRY X Y ;
	SITE CORE1 ;
	PIN out
		DIRECTION output ;
		USE SIGNAL ;
		PORT
			LAYER M1 ;
			RECT 0.755 3.995 1.04 5.285 ;
			LAYER M1 ;
			RECT 1.96 3.995 2.245 5.285 ;
			LAYER M1 ;
			RECT 3.84 3.995 4.22 4.23 ;
			LAYER M1 ;
			RECT 5.805 3.995 6.09 5.285 ;
			LAYER M1 ;
			RECT 7.015 3.995 7.3 5.285 ;
			LAYER M1 ;
			RECT 0.755 3.805 7.3 3.995 ;
			LAYER M1 ;
			RECT 3.84 3.78 4.22 3.805 ;
			LAYER M1 ;
			RECT 3.92 2.635 4.115 3.78 ;
			LAYER M1 ;
			RECT 0.815 2.355 6.915 2.635 ;
		END
		AntennaDiffArea 5.259475 ;
	END out
	PIN in1
		DIRECTION input ;
		USE SIGNAL ;
		PORT
			LAYER M1 ;
			RECT 0.12 3.22 0.5 3.6 ;
		END
		AntennaGateArea 1.392 ;
	END in1
	PIN GND
		DIRECTION inout ;
		USE GROUND ;
		PORT
			LAYER M1 ;
			RECT 0.815 0.855 6.915 0.935 ;
			LAYER M1 ;
			RECT 0.755 0.655 6.915 0.855 ;
			LAYER M1 ;
			RECT 0.755 0.42 6.855 0.655 ;
			LAYER M1 ;
			RECT 0.0 -0.42 8.06 0.42 ;
		END
	END GND
	PIN in2
		DIRECTION input ;
		USE SIGNAL ;
		PORT
			LAYER M1 ;
			RECT 6.94 3.22 7.32 3.6 ;
			LAYER M1 ;
			RECT 6.99 2.89 7.27 3.22 ;
		END
		AntennaGateArea 1.392 ;
	END in2
	PIN VDD
		DIRECTION inout ;
		USE POWER ;
		PORT
			LAYER M1 ;
			RECT 0.0 5.78 8.06 6.62 ;
			LAYER M1 ;
			RECT 0.15 3.81 0.43 5.78 ;
			LAYER M1 ;
			RECT 1.36 4.195 1.64 5.78 ;
			LAYER M1 ;
			RECT 2.565 4.195 2.845 5.78 ;
			LAYER M1 ;
			RECT 5.205 4.195 5.485 5.78 ;
			LAYER M1 ;
			RECT 6.41 4.195 6.69 5.78 ;
			LAYER M1 ;
			RECT 7.62 3.81 7.9 5.78 ;
		END
	END VDD
	PIN in3
		DIRECTION input ;
		USE SIGNAL ;
		PORT
			LAYER M1 ;
			RECT 7.56 3.22 7.94 3.6 ;
		END
		AntennaGateArea 1.392 ;
	END in3
	PIN in0
		DIRECTION input ;
		USE SIGNAL ;
		PORT
			LAYER M1 ;
			RECT 0.74 3.22 1.12 3.6 ;
			LAYER M1 ;
			RECT 0.79 2.895 1.07 3.22 ;
		END
		AntennaGateArea 1.392 ;
	END in0
	OBS
	END
END MMI_NAND4C
MACRO MMI_NOR2A
	CLASS CORE ;
	FOREIGN MMI_NOR2A 0 0 ;
	SIZE 1.86 BY 6.2 ;
	SYMMETRY X Y ;
	SITE CORE1 ;
	PIN out
		DIRECTION output ;
		USE SIGNAL ;
		PORT
			LAYER M1 ;
			RECT 0.435 3.995 0.715 5.27 ;
			LAYER M1 ;
			RECT 0.15 3.8 0.715 3.995 ;
			LAYER M1 ;
			RECT 0.15 2.98 0.345 3.8 ;
			LAYER M1 ;
			RECT 0.12 2.795 0.5 2.98 ;
			LAYER M1 ;
			RECT 0.12 2.6 0.945 2.795 ;
			LAYER M1 ;
			RECT 0.755 2.395 0.945 2.6 ;
			LAYER M1 ;
			RECT 0.75 2.08 1.03 2.395 ;
		END
		AntennaDiffArea 0.7777 ;
	END out
	PIN in1
		DIRECTION input ;
		USE SIGNAL ;
		PORT
			LAYER M1 ;
			RECT 1.36 2.93 1.74 2.98 ;
			LAYER M1 ;
			RECT 1.27 2.65 1.74 2.93 ;
			LAYER M1 ;
			RECT 1.36 2.6 1.74 2.65 ;
		END
		AntennaGateArea 0.28875 ;
	END in1
	PIN GND
		DIRECTION inout ;
		USE GROUND ;
		PORT
			LAYER M1 ;
			RECT 0.16 0.42 0.44 2.395 ;
			LAYER M1 ;
			RECT 1.34 0.42 1.62 2.395 ;
			LAYER M1 ;
			RECT 0.0 -0.42 1.86 0.42 ;
		END
	END GND
	PIN VDD
		DIRECTION inout ;
		USE POWER ;
		PORT
			LAYER M1 ;
			RECT 0.0 5.78 1.86 6.62 ;
			LAYER M1 ;
			RECT 1.395 3.8 1.675 5.78 ;
		END
	END VDD
	PIN in0
		DIRECTION input ;
		USE SIGNAL ;
		PORT
			LAYER M1 ;
			RECT 0.74 3.465 1.12 3.6 ;
			LAYER M1 ;
			RECT 0.555 3.22 1.12 3.465 ;
			LAYER M1 ;
			RECT 0.555 3.185 0.835 3.22 ;
		END
		AntennaGateArea 0.28875 ;
	END in0
	OBS
	END
END MMI_NOR2A
MACRO MMI_NOR2B
	CLASS CORE ;
	FOREIGN MMI_NOR2B 0 0 ;
	SIZE 3.1 BY 6.2 ;
	SYMMETRY X Y ;
	SITE CORE1 ;
	PIN out
		DIRECTION output ;
		USE SIGNAL ;
		PORT
			LAYER M1 ;
			RECT 1.12 3.53 1.4 5.0 ;
			LAYER M1 ;
			RECT 1.125 2.36 1.32 3.53 ;
			LAYER M1 ;
			RECT 0.74 1.98 1.32 2.36 ;
			LAYER M1 ;
			RECT 1.125 1.765 1.32 1.98 ;
			LAYER M1 ;
			RECT 1.12 1.065 1.4 1.765 ;
		END
		AntennaDiffArea 1.0164 ;
	END out
	PIN in1
		DIRECTION input ;
		USE SIGNAL ;
		PORT
			LAYER M1 ;
			RECT 1.98 2.975 2.36 2.98 ;
			LAYER M1 ;
			RECT 1.96 2.97 2.36 2.975 ;
			LAYER M1 ;
			RECT 1.68 2.69 2.36 2.97 ;
			LAYER M1 ;
			RECT 1.98 2.6 2.36 2.69 ;
		END
		AntennaGateArea 0.5775 ;
	END in1
	PIN GND
		DIRECTION inout ;
		USE GROUND ;
		PORT
			LAYER M1 ;
			RECT 0.53 0.42 0.81 1.765 ;
			LAYER M1 ;
			RECT 1.71 0.42 1.99 1.765 ;
			LAYER M1 ;
			RECT 0.0 -0.42 3.1 0.42 ;
		END
	END GND
	PIN VDD
		DIRECTION inout ;
		USE POWER ;
		PORT
			LAYER M1 ;
			RECT 0.0 5.78 3.1 6.62 ;
			LAYER M1 ;
			RECT 0.16 3.53 0.44 5.78 ;
			LAYER M1 ;
			RECT 2.08 3.53 2.36 5.78 ;
		END
	END VDD
	PIN in0
		DIRECTION input ;
		USE SIGNAL ;
		PORT
			LAYER M1 ;
			RECT 0.12 2.935 0.5 2.98 ;
			LAYER M1 ;
			RECT 0.12 2.93 0.595 2.935 ;
			LAYER M1 ;
			RECT 0.12 2.65 0.875 2.93 ;
			LAYER M1 ;
			RECT 0.12 2.6 0.5 2.65 ;
		END
		AntennaGateArea 0.5775 ;
	END in0
	OBS
	END
END MMI_NOR2B
MACRO MMI_NOR2C
	CLASS CORE ;
	FOREIGN MMI_NOR2C 0 0 ;
	SIZE 4.96 BY 6.2 ;
	SYMMETRY X Y ;
	SITE CORE1 ;
	PIN out
		DIRECTION output ;
		USE SIGNAL ;
		PORT
			LAYER M1 ;
			RECT 1.12 3.695 1.4 4.975 ;
			LAYER M1 ;
			RECT 3.04 3.695 3.32 4.975 ;
			LAYER M1 ;
			RECT 0.845 3.505 3.32 3.695 ;
			LAYER M1 ;
			RECT 0.845 2.36 1.04 3.505 ;
			LAYER M1 ;
			RECT 0.74 2.285 1.12 2.36 ;
			LAYER M1 ;
			RECT 0.74 2.09 3.335 2.285 ;
			LAYER M1 ;
			RECT 0.74 1.98 1.12 2.09 ;
			LAYER M1 ;
			RECT 1.97 1.815 2.165 2.09 ;
			LAYER M1 ;
			RECT 3.14 1.815 3.335 2.09 ;
			LAYER M1 ;
			RECT 1.93 1.115 2.21 1.815 ;
			LAYER M1 ;
			RECT 3.14 1.115 3.42 1.815 ;
		END
		AntennaDiffArea 2.04435 ;
	END out
	PIN in1
		DIRECTION input ;
		USE SIGNAL ;
		PORT
			LAYER M1 ;
			RECT 2.275 2.93 2.555 3.2 ;
			LAYER M1 ;
			RECT 3.84 2.97 4.22 2.98 ;
			LAYER M1 ;
			RECT 3.605 2.93 4.22 2.97 ;
			LAYER M1 ;
			RECT 2.275 2.735 4.22 2.93 ;
			LAYER M1 ;
			RECT 3.605 2.69 4.22 2.735 ;
			LAYER M1 ;
			RECT 3.84 2.6 4.22 2.69 ;
		END
		AntennaGateArea 1.155 ;
	END in1
	PIN GND
		DIRECTION inout ;
		USE GROUND ;
		PORT
			LAYER M1 ;
			RECT 1.34 0.42 1.62 1.815 ;
			LAYER M1 ;
			RECT 2.52 0.42 2.8 1.815 ;
			LAYER M1 ;
			RECT 3.73 0.42 4.01 1.815 ;
			LAYER M1 ;
			RECT 0.0 -0.42 4.96 0.42 ;
		END
	END GND
	PIN VDD
		DIRECTION inout ;
		USE POWER ;
		PORT
			LAYER M1 ;
			RECT 0.0 5.78 4.96 6.62 ;
			LAYER M1 ;
			RECT 0.16 3.505 0.44 5.78 ;
			LAYER M1 ;
			RECT 2.08 3.915 2.36 5.78 ;
			LAYER M1 ;
			RECT 4.0 3.505 4.28 5.78 ;
		END
	END VDD
	PIN in0
		DIRECTION input ;
		USE SIGNAL ;
		PORT
			LAYER M1 ;
			RECT 1.36 2.97 1.74 2.98 ;
			LAYER M1 ;
			RECT 1.36 2.69 1.795 2.97 ;
			LAYER M1 ;
			RECT 1.36 2.6 1.74 2.69 ;
		END
		AntennaGateArea 1.155 ;
	END in0
	OBS
	END
END MMI_NOR2C
MACRO MMI_NOR2D
	CLASS CORE ;
	FOREIGN MMI_NOR2D 0 0 ;
	SIZE 5.58 BY 6.2 ;
	SYMMETRY X Y ;
	SITE CORE1 ;
	PIN out
		DIRECTION output ;
		USE SIGNAL ;
		PORT
			LAYER M1 ;
			RECT 0.285 4.495 4.81 4.775 ;
			LAYER M1 ;
			RECT 0.285 2.845 0.57 4.495 ;
			LAYER M1 ;
			RECT 0.285 2.565 4.81 2.845 ;
			LAYER M1 ;
			RECT 2.51 2.11 3.11 2.565 ;
			LAYER M1 ;
			RECT 1.565 1.915 4.17 2.11 ;
			LAYER M1 ;
			RECT 1.565 1.705 1.85 1.915 ;
			LAYER M1 ;
			RECT 2.77 1.705 3.055 1.915 ;
			LAYER M1 ;
			RECT 3.98 1.705 4.17 1.915 ;
			LAYER M1 ;
			RECT 1.565 1.425 1.895 1.705 ;
			LAYER M1 ;
			RECT 2.77 1.425 3.075 1.705 ;
			LAYER M1 ;
			RECT 1.615 0.75 1.895 1.425 ;
			LAYER M1 ;
			RECT 2.795 0.75 3.075 1.425 ;
			LAYER M1 ;
			RECT 3.975 0.75 4.255 1.705 ;
		END
		AntennaDiffArea 4.8012 ;
	END out
	PIN in1
		DIRECTION input ;
		USE SIGNAL ;
		PORT
			LAYER M1 ;
			RECT 0.12 1.98 0.655 2.36 ;
			LAYER M1 ;
			RECT 0.37 1.865 0.65 1.98 ;
		END
		AntennaGateArea 2.3085 ;
	END in1
	PIN GND
		DIRECTION inout ;
		USE GROUND ;
		PORT
			LAYER M1 ;
			RECT 1.025 0.75 1.305 1.705 ;
			LAYER M1 ;
			RECT 2.205 0.75 2.485 1.705 ;
			LAYER M1 ;
			RECT 3.385 0.75 3.665 1.705 ;
			LAYER M1 ;
			RECT 4.565 1.035 4.845 1.705 ;
			LAYER M1 ;
			RECT 4.565 0.75 4.855 1.035 ;
			LAYER M1 ;
			RECT 1.015 0.42 1.3 0.75 ;
			LAYER M1 ;
			RECT 2.185 0.42 2.47 0.75 ;
			LAYER M1 ;
			RECT 3.39 0.42 3.675 0.75 ;
			LAYER M1 ;
			RECT 4.57 0.42 4.855 0.75 ;
			LAYER M1 ;
			RECT 0.0 -0.42 5.58 0.42 ;
		END
	END GND
	PIN VDD
		DIRECTION inout ;
		USE POWER ;
		PORT
			LAYER M1 ;
			RECT 0.0 5.78 5.58 6.62 ;
			LAYER M1 ;
			RECT 0.77 5.705 4.81 5.78 ;
			LAYER M1 ;
			RECT 0.775 5.46 4.81 5.705 ;
			LAYER M1 ;
			RECT 5.065 3.805 5.35 5.78 ;
			LAYER M1 ;
			RECT 0.775 3.525 5.35 3.805 ;
		END
	END VDD
	PIN in0
		DIRECTION input ;
		USE SIGNAL ;
		PORT
			LAYER M1 ;
			RECT 4.9 1.98 5.46 2.36 ;
			LAYER M1 ;
			RECT 5.12 1.86 5.4 1.98 ;
		END
		AntennaGateArea 2.3085 ;
	END in0
	OBS
	END
END MMI_NOR2D
MACRO MMI_NOR3A
	CLASS CORE ;
	FOREIGN MMI_NOR3A 0 0 ;
	SIZE 3.1 BY 6.2 ;
	SYMMETRY X Y ;
	SITE CORE1 ;
	PIN out
		DIRECTION output ;
		USE SIGNAL ;
		PORT
			LAYER M1 ;
			RECT 2.07 3.295 2.35 5.54 ;
			LAYER M1 ;
			RECT 2.095 3.02 2.29 3.295 ;
			LAYER M1 ;
			RECT 1.765 2.6 2.29 3.02 ;
			LAYER M1 ;
			RECT 1.765 1.76 1.96 2.6 ;
			LAYER M1 ;
			RECT 1.145 1.565 2.565 1.76 ;
			LAYER M1 ;
			RECT 1.145 1.35 1.34 1.565 ;
			LAYER M1 ;
			RECT 2.37 1.35 2.565 1.565 ;
			LAYER M1 ;
			RECT 1.11 1.035 1.39 1.35 ;
			LAYER M1 ;
			RECT 2.29 1.035 2.57 1.35 ;
		END
		AntennaDiffArea 1.2359 ;
	END out
	PIN in1
		DIRECTION input ;
		USE SIGNAL ;
		PORT
			LAYER M1 ;
			RECT 0.74 2.315 1.12 2.36 ;
			LAYER M1 ;
			RECT 0.74 2.31 1.55 2.315 ;
			LAYER M1 ;
			RECT 0.74 2.03 1.565 2.31 ;
			LAYER M1 ;
			RECT 0.74 1.98 1.12 2.03 ;
		END
		AntennaGateArea 0.405 ;
	END in1
	PIN GND
		DIRECTION inout ;
		USE GROUND ;
		PORT
			LAYER M1 ;
			RECT 0.52 1.165 0.8 1.35 ;
			LAYER M1 ;
			RECT 0.51 1.035 0.8 1.165 ;
			LAYER M1 ;
			RECT 1.7 1.165 1.98 1.35 ;
			LAYER M1 ;
			RECT 1.7 1.035 2.0 1.165 ;
			LAYER M1 ;
			RECT 0.51 0.42 0.795 1.035 ;
			LAYER M1 ;
			RECT 1.715 0.42 2.0 1.035 ;
			LAYER M1 ;
			RECT 0.0 -0.42 3.1 0.42 ;
		END
	END GND
	PIN in2
		DIRECTION input ;
		USE SIGNAL ;
		PORT
			LAYER M1 ;
			RECT 0.12 2.695 0.9 2.98 ;
			LAYER M1 ;
			RECT 0.12 2.6 0.5 2.695 ;
		END
		AntennaGateArea 0.405 ;
	END in2
	PIN VDD
		DIRECTION inout ;
		USE POWER ;
		PORT
			LAYER M1 ;
			RECT 0.0 5.78 3.1 6.62 ;
			LAYER M1 ;
			RECT 0.735 5.255 1.02 5.78 ;
			LAYER M1 ;
			RECT 0.74 3.295 1.02 5.255 ;
		END
	END VDD
	PIN in0
		DIRECTION input ;
		USE SIGNAL ;
		PORT
			LAYER M1 ;
			RECT 2.6 2.315 2.98 2.36 ;
			LAYER M1 ;
			RECT 2.275 2.31 2.98 2.315 ;
			LAYER M1 ;
			RECT 2.165 2.03 2.98 2.31 ;
			LAYER M1 ;
			RECT 2.6 1.98 2.98 2.03 ;
		END
		AntennaGateArea 0.405 ;
	END in0
	OBS
	END
END MMI_NOR3A
MACRO MMI_NOR3B
	CLASS CORE ;
	FOREIGN MMI_NOR3B 0 0 ;
	SIZE 4.96 BY 6.2 ;
	SYMMETRY X Y ;
	SITE CORE1 ;
	PIN out
		DIRECTION output ;
		USE SIGNAL ;
		PORT
			LAYER M1 ;
			RECT 0.52 3.695 0.8 4.975 ;
			LAYER M1 ;
			RECT 3.195 3.695 3.475 4.975 ;
			LAYER M1 ;
			RECT 0.305 3.505 3.475 3.695 ;
			LAYER M1 ;
			RECT 0.305 2.36 0.5 3.505 ;
			LAYER M1 ;
			RECT 0.12 1.98 0.5 2.36 ;
			LAYER M1 ;
			RECT 0.305 1.97 0.5 1.98 ;
			LAYER M1 ;
			RECT 0.305 1.965 2.135 1.97 ;
			LAYER M1 ;
			RECT 0.305 1.775 2.17 1.965 ;
			LAYER M1 ;
			RECT 0.695 1.265 0.975 1.775 ;
			LAYER M1 ;
			RECT 1.89 1.265 2.17 1.775 ;
		END
		AntennaDiffArea 1.92885 ;
	END out
	PIN in1
		DIRECTION input ;
		USE SIGNAL ;
		PORT
			LAYER M1 ;
			RECT 2.17 2.995 3.995 3.165 ;
			LAYER M1 ;
			RECT 1.49 2.98 3.995 2.995 ;
			LAYER M1 ;
			RECT 1.49 2.97 4.04 2.98 ;
			LAYER M1 ;
			RECT 1.49 2.715 2.71 2.97 ;
			LAYER M1 ;
			RECT 1.98 2.6 2.36 2.715 ;
			LAYER M1 ;
			RECT 3.76 2.7 4.04 2.97 ;
		END
		AntennaGateArea 0.8085 ;
	END in1
	PIN GND
		DIRECTION inout ;
		USE GROUND ;
		PORT
			LAYER M1 ;
			RECT 1.285 0.42 1.565 1.545 ;
			LAYER M1 ;
			RECT 2.48 0.42 2.76 1.965 ;
			LAYER M1 ;
			RECT 0.0 -0.42 4.96 0.42 ;
		END
	END GND
	PIN in2
		DIRECTION input ;
		USE SIGNAL ;
		PORT
			LAYER M1 ;
			RECT 4.33 2.98 4.61 3.06 ;
			LAYER M1 ;
			RECT 4.33 2.78 4.84 2.98 ;
			LAYER M1 ;
			RECT 4.46 2.6 4.84 2.78 ;
			LAYER M1 ;
			RECT 4.46 1.745 4.655 2.6 ;
			LAYER M1 ;
			RECT 3.085 1.555 4.655 1.745 ;
			LAYER M1 ;
			RECT 3.085 1.295 3.275 1.555 ;
			LAYER M1 ;
			RECT 2.995 1.015 3.275 1.295 ;
		END
		AntennaGateArea 0.8085 ;
	END in2
	PIN VDD
		DIRECTION inout ;
		USE POWER ;
		PORT
			LAYER M1 ;
			RECT 0.0 5.78 4.96 6.62 ;
			LAYER M1 ;
			RECT 1.865 3.915 2.145 5.78 ;
			LAYER M1 ;
			RECT 4.525 3.505 4.805 5.78 ;
		END
	END VDD
	PIN in0
		DIRECTION input ;
		USE SIGNAL ;
		PORT
			LAYER M1 ;
			RECT 0.72 3.005 1.0 3.285 ;
			LAYER M1 ;
			RECT 0.81 2.45 1.0 3.005 ;
			LAYER M1 ;
			RECT 0.81 2.365 1.17 2.45 ;
			LAYER M1 ;
			RECT 3.155 2.365 3.435 2.58 ;
			LAYER M1 ;
			RECT 0.81 2.36 3.435 2.365 ;
			LAYER M1 ;
			RECT 0.81 2.175 3.6 2.36 ;
			LAYER M1 ;
			RECT 0.89 2.17 1.17 2.175 ;
			LAYER M1 ;
			RECT 3.22 1.98 3.6 2.175 ;
		END
		AntennaGateArea 0.8085 ;
	END in0
	OBS
	END
END MMI_NOR3B
MACRO MMI_OA21B
	CLASS CORE ;
	FOREIGN MMI_OA21B 0 0 ;
	SIZE 3.72 BY 6.2 ;
	SYMMETRY X Y ;
	SITE CORE1 ;
	PIN out
		DIRECTION output ;
		USE SIGNAL ;
		PORT
			LAYER M1 ;
			RECT 3.145 3.78 3.425 5.25 ;
			LAYER M1 ;
			RECT 3.235 2.36 3.425 3.78 ;
			LAYER M1 ;
			RECT 3.22 1.98 3.6 2.36 ;
			LAYER M1 ;
			RECT 3.235 1.555 3.425 1.98 ;
			LAYER M1 ;
			RECT 3.145 0.855 3.425 1.555 ;
		END
		AntennaDiffArea 0.91245 ;
	END out
	PIN in1
		DIRECTION input ;
		USE SIGNAL ;
		PORT
			LAYER M1 ;
			RECT 2.545 2.08 2.98 2.36 ;
			LAYER M1 ;
			RECT 2.6 1.98 2.98 2.08 ;
		END
		AntennaGateArea 0.3465 ;
	END in1
	PIN GND
		DIRECTION inout ;
		USE GROUND ;
		PORT
			LAYER M1 ;
			RECT 0.16 0.42 0.44 1.555 ;
			LAYER M1 ;
			RECT 2.555 0.42 2.835 1.555 ;
			LAYER M1 ;
			RECT 0.0 -0.42 3.72 0.42 ;
		END
	END GND
	PIN in2
		DIRECTION input ;
		USE SIGNAL ;
		PORT
			LAYER M1 ;
			RECT 1.36 2.93 1.74 2.98 ;
			LAYER M1 ;
			RECT 1.36 2.885 1.945 2.93 ;
			LAYER M1 ;
			RECT 0.93 2.695 1.945 2.885 ;
			LAYER M1 ;
			RECT 0.355 2.31 0.635 2.35 ;
			LAYER M1 ;
			RECT 0.93 2.31 1.125 2.695 ;
			LAYER M1 ;
			RECT 1.36 2.65 1.945 2.695 ;
			LAYER M1 ;
			RECT 1.36 2.6 1.74 2.65 ;
			LAYER M1 ;
			RECT 0.355 2.115 1.125 2.31 ;
			LAYER M1 ;
			RECT 0.355 2.07 0.635 2.115 ;
		END
		AntennaGateArea 0.3465 ;
	END in2
	PIN VDD
		DIRECTION inout ;
		USE POWER ;
		PORT
			LAYER M1 ;
			RECT 0.0 5.78 3.72 6.62 ;
			LAYER M1 ;
			RECT 0.16 3.78 0.44 5.78 ;
			LAYER M1 ;
			RECT 1.755 3.78 2.035 5.78 ;
			LAYER M1 ;
			RECT 2.555 3.78 2.835 5.78 ;
		END
	END VDD
	PIN in0
		DIRECTION input ;
		USE SIGNAL ;
		PORT
			LAYER M1 ;
			RECT 0.12 2.93 0.5 2.98 ;
			LAYER M1 ;
			RECT 0.12 2.885 0.635 2.93 ;
			LAYER M1 ;
			RECT 0.12 2.695 0.69 2.885 ;
			LAYER M1 ;
			RECT 0.12 2.65 0.635 2.695 ;
			LAYER M1 ;
			RECT 0.12 2.6 0.5 2.65 ;
		END
		AntennaGateArea 0.231 ;
	END in0
	OBS
		LAYER M1 ;
		RECT 0.795 3.78 1.075 5.25 ;
		LAYER M1 ;
		RECT 0.88 3.465 1.075 3.78 ;
		LAYER M1 ;
		RECT 0.88 3.27 2.345 3.465 ;
		LAYER M1 ;
		RECT 2.15 2.885 2.345 3.27 ;
		LAYER M1 ;
		RECT 2.75 2.885 3.03 2.93 ;
		LAYER M1 ;
		RECT 2.15 2.695 3.03 2.885 ;
		LAYER M1 ;
		RECT 2.15 2.31 2.345 2.695 ;
		LAYER M1 ;
		RECT 2.75 2.65 3.03 2.695 ;
		LAYER M1 ;
		RECT 1.43 2.115 2.345 2.31 ;
		LAYER M1 ;
		RECT 1.43 1.555 1.62 2.115 ;
		LAYER M1 ;
		RECT 0.75 1.05 1.03 1.555 ;
		LAYER M1 ;
		RECT 1.34 1.275 1.62 1.555 ;
		LAYER M1 ;
		RECT 1.965 1.05 2.245 1.555 ;
		LAYER M1 ;
		RECT 0.75 0.855 2.245 1.05 ;
	END
END MMI_OA21B
MACRO MMI_OA21C
	CLASS CORE ;
	FOREIGN MMI_OA21C 0 0 ;
	SIZE 3.72 BY 6.2 ;
	SYMMETRY X Y ;
	SITE CORE1 ;
	PIN out
		DIRECTION output ;
		USE SIGNAL ;
		PORT
			LAYER M1 ;
			RECT 0.765 3.705 1.045 4.985 ;
			LAYER M1 ;
			RECT 0.75 3.515 1.045 3.705 ;
			LAYER M1 ;
			RECT 0.75 3.3 0.945 3.515 ;
			LAYER M1 ;
			RECT 0.265 3.11 0.945 3.3 ;
			LAYER M1 ;
			RECT 0.265 2.98 0.5 3.11 ;
			LAYER M1 ;
			RECT 0.12 2.6 0.5 2.98 ;
			LAYER M1 ;
			RECT 0.265 2.385 0.455 2.6 ;
			LAYER M1 ;
			RECT 0.245 0.915 0.525 2.385 ;
		END
		AntennaDiffArea 1.2859 ;
	END out
	PIN in1
		DIRECTION input ;
		USE SIGNAL ;
		PORT
			LAYER M1 ;
			RECT 2.6 2.925 2.98 2.98 ;
			LAYER M1 ;
			RECT 2.58 2.645 2.98 2.925 ;
			LAYER M1 ;
			RECT 2.6 2.6 2.98 2.645 ;
		END
		AntennaGateArea 0.468 ;
	END in1
	PIN GND
		DIRECTION inout ;
		USE GROUND ;
		PORT
			LAYER M1 ;
			RECT 0.835 0.42 1.115 2.385 ;
			LAYER M1 ;
			RECT 2.625 0.42 2.905 2.0 ;
			LAYER M1 ;
			RECT 0.0 -0.42 3.72 0.42 ;
		END
	END GND
	PIN in2
		DIRECTION input ;
		USE SIGNAL ;
		PORT
			LAYER M1 ;
			RECT 3.22 2.6 3.6 2.98 ;
		END
		AntennaGateArea 0.468 ;
	END in2
	PIN VDD
		DIRECTION inout ;
		USE POWER ;
		PORT
			LAYER M1 ;
			RECT 0.0 5.78 3.72 6.62 ;
			LAYER M1 ;
			RECT 0.175 3.515 0.455 5.78 ;
			LAYER M1 ;
			RECT 1.36 4.985 1.64 5.78 ;
			LAYER M1 ;
			RECT 1.355 4.485 1.64 4.985 ;
			LAYER M1 ;
			RECT 1.355 3.925 1.635 4.485 ;
			LAYER M1 ;
			RECT 3.025 3.515 3.305 5.78 ;
		END
	END VDD
	PIN in0
		DIRECTION input ;
		USE SIGNAL ;
		PORT
			LAYER M1 ;
			RECT 1.98 2.975 2.36 2.98 ;
			LAYER M1 ;
			RECT 1.875 2.695 2.36 2.975 ;
			LAYER M1 ;
			RECT 1.98 2.6 2.36 2.695 ;
		END
		AntennaGateArea 0.312 ;
	END in0
	OBS
		LAYER M1 ;
		RECT 2.065 3.64 2.345 5.525 ;
		LAYER M1 ;
		RECT 1.445 3.515 2.345 3.64 ;
		LAYER M1 ;
		RECT 1.445 3.45 2.34 3.515 ;
		LAYER M1 ;
		RECT 1.445 2.93 1.635 3.45 ;
		LAYER M1 ;
		RECT 1.165 2.65 1.635 2.93 ;
		LAYER M1 ;
		RECT 1.445 2.0 1.635 2.65 ;
		LAYER M1 ;
		RECT 2.12 2.205 3.41 2.4 ;
		LAYER M1 ;
		RECT 2.12 2.0 2.315 2.205 ;
		LAYER M1 ;
		RECT 3.22 2.0 3.41 2.205 ;
		LAYER M1 ;
		RECT 1.445 1.03 1.725 2.0 ;
		LAYER M1 ;
		RECT 2.035 1.03 2.315 2.0 ;
		LAYER M1 ;
		RECT 3.215 1.03 3.495 2.0 ;
	END
END MMI_OA21C
MACRO MMI_OA22B
	CLASS CORE ;
	FOREIGN MMI_OA22B 0 0 ;
	SIZE 3.72 BY 6.2 ;
	SYMMETRY X Y ;
	SITE CORE1 ;
	PIN out
		DIRECTION output ;
		USE SIGNAL ;
		PORT
			LAYER M1 ;
			RECT 0.16 4.03 0.44 5.5 ;
			LAYER M1 ;
			RECT 0.2 3.6 0.395 4.03 ;
			LAYER M1 ;
			RECT 0.12 3.22 0.5 3.6 ;
			LAYER M1 ;
			RECT 0.16 1.64 0.355 3.22 ;
			LAYER M1 ;
			RECT 0.16 0.94 0.44 1.64 ;
		END
		AntennaDiffArea 0.91245 ;
	END out
	PIN in1
		DIRECTION input ;
		USE SIGNAL ;
		PORT
			LAYER M1 ;
			RECT 3.26 3.6 3.575 3.61 ;
			LAYER M1 ;
			RECT 3.22 3.22 3.6 3.6 ;
			LAYER M1 ;
			RECT 1.65 2.42 1.93 2.51 ;
			LAYER M1 ;
			RECT 3.375 2.42 3.565 3.22 ;
			LAYER M1 ;
			RECT 1.65 2.23 3.565 2.42 ;
		END
		AntennaGateArea 0.3465 ;
	END in1
	PIN GND
		DIRECTION inout ;
		USE GROUND ;
		PORT
			LAYER M1 ;
			RECT 0.865 0.42 1.145 1.64 ;
			LAYER M1 ;
			RECT 3.225 0.42 3.505 1.64 ;
			LAYER M1 ;
			RECT 0.0 -0.42 3.72 0.42 ;
		END
	END GND
	PIN in2
		DIRECTION input ;
		USE SIGNAL ;
		PORT
			LAYER M1 ;
			RECT 1.94 3.0 2.22 3.08 ;
			LAYER M1 ;
			RECT 1.94 2.9 3.11 3.0 ;
			LAYER M1 ;
			RECT 1.94 2.805 3.165 2.9 ;
			LAYER M1 ;
			RECT 1.94 2.8 2.22 2.805 ;
			LAYER M1 ;
			RECT 2.615 2.625 3.165 2.805 ;
			LAYER M1 ;
			RECT 2.885 2.62 3.165 2.625 ;
		END
		AntennaGateArea 0.3465 ;
	END in2
	PIN VDD
		DIRECTION inout ;
		USE POWER ;
		PORT
			LAYER M1 ;
			RECT 0.0 5.78 3.72 6.62 ;
			LAYER M1 ;
			RECT 0.765 4.44 1.045 5.78 ;
			LAYER M1 ;
			RECT 2.7 4.03 2.98 5.78 ;
		END
	END VDD
	PIN in3
		DIRECTION input ;
		USE SIGNAL ;
		PORT
			LAYER M1 ;
			RECT 1.36 3.505 1.74 3.6 ;
			LAYER M1 ;
			RECT 1.16 3.225 1.74 3.505 ;
			LAYER M1 ;
			RECT 1.36 3.22 1.74 3.225 ;
		END
		AntennaGateArea 0.3465 ;
	END in3
	PIN in0
		DIRECTION input ;
		USE SIGNAL ;
		PORT
			LAYER M1 ;
			RECT 2.6 3.505 2.98 3.6 ;
			LAYER M1 ;
			RECT 2.51 3.225 2.98 3.505 ;
			LAYER M1 ;
			RECT 2.6 3.22 2.98 3.225 ;
		END
		AntennaGateArea 0.3465 ;
	END in0
	OBS
		LAYER M1 ;
		RECT 1.725 4.44 2.005 5.5 ;
		LAYER M1 ;
		RECT 1.725 4.225 1.92 4.44 ;
		LAYER M1 ;
		RECT 0.755 4.03 1.92 4.225 ;
		LAYER M1 ;
		RECT 0.755 2.97 0.945 4.03 ;
		LAYER M1 ;
		RECT 0.565 2.69 0.945 2.97 ;
		LAYER M1 ;
		RECT 0.755 2.03 0.945 2.69 ;
		LAYER M1 ;
		RECT 0.755 1.84 2.255 2.03 ;
		LAYER M1 ;
		RECT 2.06 1.64 2.255 1.84 ;
		LAYER M1 ;
		RECT 1.455 1.13 1.735 1.64 ;
		LAYER M1 ;
		RECT 2.045 1.36 2.325 1.64 ;
		LAYER M1 ;
		RECT 2.635 1.13 2.915 1.64 ;
		LAYER M1 ;
		RECT 1.455 0.94 2.915 1.13 ;
	END
END MMI_OA22B
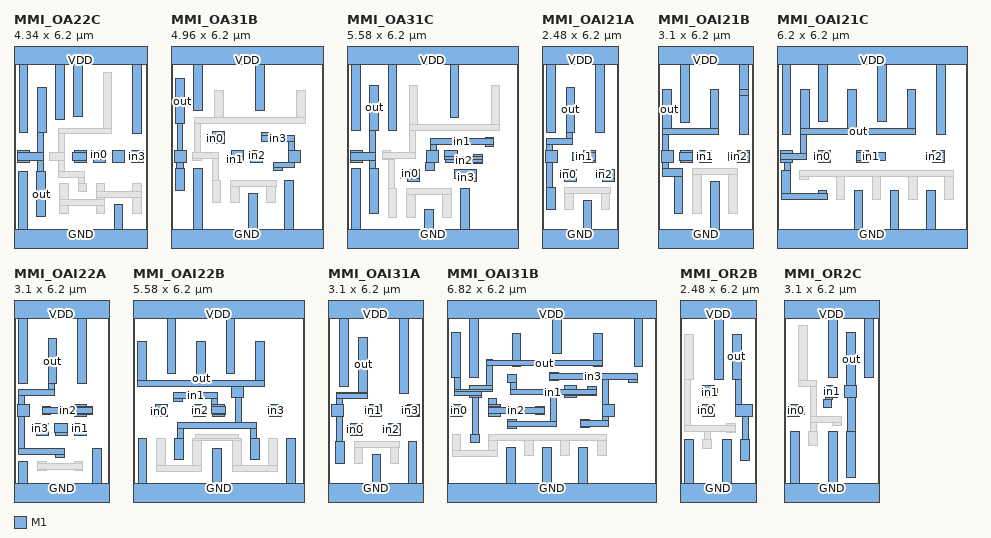
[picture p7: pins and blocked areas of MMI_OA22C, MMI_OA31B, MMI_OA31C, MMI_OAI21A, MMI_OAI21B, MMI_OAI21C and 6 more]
MACRO MMI_OA22C
	CLASS CORE ;
	FOREIGN MMI_OA22C 0 0 ;
	SIZE 4.34 BY 6.2 ;
	SYMMETRY X Y ;
	SITE CORE1 ;
	PIN out
		DIRECTION output ;
		USE SIGNAL ;
		PORT
			LAYER M1 ;
			RECT 0.765 3.58 1.045 5.05 ;
			LAYER M1 ;
			RECT 0.12 2.93 0.5 2.98 ;
			LAYER M1 ;
			RECT 0.765 2.93 0.955 3.58 ;
			LAYER M1 ;
			RECT 0.12 2.655 0.955 2.93 ;
			LAYER M1 ;
			RECT 0.12 2.6 0.5 2.655 ;
			LAYER M1 ;
			RECT 0.765 2.295 0.955 2.655 ;
			LAYER M1 ;
			RECT 0.75 0.825 1.03 2.295 ;
		END
		AntennaDiffArea 1.2859 ;
	END out
	PIN in1
		DIRECTION input ;
		USE SIGNAL ;
		PORT
			LAYER M1 ;
			RECT 1.98 2.93 2.36 2.98 ;
			LAYER M1 ;
			RECT 1.895 2.65 2.36 2.93 ;
			LAYER M1 ;
			RECT 1.98 2.6 2.36 2.65 ;
		END
		AntennaGateArea 0.468 ;
	END in1
	PIN GND
		DIRECTION inout ;
		USE GROUND ;
		PORT
			LAYER M1 ;
			RECT 0.16 0.42 0.44 2.295 ;
			LAYER M1 ;
			RECT 3.27 0.42 3.55 1.225 ;
			LAYER M1 ;
			RECT 0.0 -0.42 4.34 0.42 ;
		END
	END GND
	PIN in2
		DIRECTION input ;
		USE SIGNAL ;
		PORT
			LAYER M1 ;
			RECT 3.22 2.6 3.6 2.98 ;
		END
		AntennaGateArea 0.468 ;
	END in2
	PIN VDD
		DIRECTION inout ;
		USE POWER ;
		PORT
			LAYER M1 ;
			RECT 0.0 5.78 4.34 6.62 ;
			LAYER M1 ;
			RECT 0.175 3.58 0.455 5.78 ;
			LAYER M1 ;
			RECT 1.355 3.99 1.635 5.78 ;
			LAYER M1 ;
			RECT 1.945 4.085 2.225 5.78 ;
			LAYER M1 ;
			RECT 3.875 3.525 4.155 5.78 ;
		END
	END VDD
	PIN in3
		DIRECTION input ;
		USE SIGNAL ;
		PORT
			LAYER M1 ;
			RECT 3.84 2.6 4.22 2.98 ;
		END
		AntennaGateArea 0.468 ;
	END in3
	PIN in0
		DIRECTION input ;
		USE SIGNAL ;
		PORT
			LAYER M1 ;
			RECT 2.565 2.7 2.98 2.98 ;
			LAYER M1 ;
			RECT 2.6 2.6 2.98 2.7 ;
		END
		AntennaGateArea 0.468 ;
	END in0
	OBS
		LAYER M1 ;
		RECT 2.915 3.715 3.195 5.535 ;
		LAYER M1 ;
		RECT 1.465 3.525 3.195 3.715 ;
		LAYER M1 ;
		RECT 1.465 2.935 1.66 3.525 ;
		LAYER M1 ;
		RECT 1.155 2.65 1.66 2.935 ;
		LAYER M1 ;
		RECT 1.465 2.31 1.66 2.65 ;
		LAYER M1 ;
		RECT 1.465 2.115 2.29 2.31 ;
		LAYER M1 ;
		RECT 2.095 1.915 2.29 2.115 ;
		LAYER M1 ;
		RECT 1.5 1.375 1.78 1.915 ;
		LAYER M1 ;
		RECT 2.09 1.635 2.37 1.915 ;
		LAYER M1 ;
		RECT 2.68 1.64 2.96 1.915 ;
		LAYER M1 ;
		RECT 3.875 1.64 4.155 1.915 ;
		LAYER M1 ;
		RECT 2.68 1.45 4.155 1.64 ;
		LAYER M1 ;
		RECT 2.68 1.375 2.96 1.45 ;
		LAYER M1 ;
		RECT 1.49 1.18 2.96 1.375 ;
		LAYER M1 ;
		RECT 1.5 0.945 1.78 1.18 ;
		LAYER M1 ;
		RECT 2.68 0.945 2.96 1.18 ;
		LAYER M1 ;
		RECT 3.875 0.945 4.155 1.45 ;
	END
END MMI_OA22C
MACRO MMI_OA31B
	CLASS CORE ;
	FOREIGN MMI_OA31B 0 0 ;
	SIZE 4.96 BY 6.2 ;
	SYMMETRY X Y ;
	SITE CORE1 ;
	PIN out
		DIRECTION output ;
		USE SIGNAL ;
		PORT
			LAYER M1 ;
			RECT 0.16 3.865 0.44 5.335 ;
			LAYER M1 ;
			RECT 0.2 2.98 0.39 3.865 ;
			LAYER M1 ;
			RECT 0.12 2.6 0.5 2.98 ;
			LAYER M1 ;
			RECT 0.175 2.385 0.415 2.6 ;
			LAYER M1 ;
			RECT 0.16 1.685 0.44 2.385 ;
		END
		AntennaDiffArea 0.91245 ;
	END out
	PIN in1
		DIRECTION input ;
		USE SIGNAL ;
		PORT
			LAYER M1 ;
			RECT 1.98 2.805 2.36 2.98 ;
			LAYER M1 ;
			RECT 1.83 2.6 2.36 2.805 ;
			LAYER M1 ;
			RECT 1.83 2.525 2.11 2.6 ;
		END
		AntennaGateArea 0.462 ;
	END in1
	PIN GND
		DIRECTION inout ;
		USE GROUND ;
		PORT
			LAYER M1 ;
			RECT 0.75 0.42 1.03 2.385 ;
			LAYER M1 ;
			RECT 2.53 0.42 2.81 1.575 ;
			LAYER M1 ;
			RECT 3.71 0.42 3.99 1.995 ;
			LAYER M1 ;
			RECT 0.0 -0.42 4.96 0.42 ;
		END
	END GND
	PIN in2
		DIRECTION input ;
		USE SIGNAL ;
		PORT
			LAYER M1 ;
			RECT 2.6 2.975 2.98 2.98 ;
			LAYER M1 ;
			RECT 2.6 2.695 3.03 2.975 ;
			LAYER M1 ;
			RECT 2.6 2.6 2.98 2.695 ;
		END
		AntennaGateArea 0.462 ;
	END in2
	PIN VDD
		DIRECTION inout ;
		USE POWER ;
		PORT
			LAYER M1 ;
			RECT 0.0 5.78 4.96 6.62 ;
			LAYER M1 ;
			RECT 0.75 4.275 1.03 5.78 ;
			LAYER M1 ;
			RECT 2.765 4.275 3.045 5.78 ;
		END
	END VDD
	PIN in3
		DIRECTION input ;
		USE SIGNAL ;
		PORT
			LAYER M1 ;
			RECT 2.96 3.475 3.24 3.565 ;
			LAYER M1 ;
			RECT 2.96 3.285 4.035 3.475 ;
			LAYER M1 ;
			RECT 3.095 3.28 4.035 3.285 ;
			LAYER M1 ;
			RECT 3.84 2.98 4.035 3.28 ;
			LAYER M1 ;
			RECT 3.84 2.605 4.22 2.98 ;
			LAYER M1 ;
			RECT 3.355 2.6 4.22 2.605 ;
			LAYER M1 ;
			RECT 3.355 2.415 4.035 2.6 ;
			LAYER M1 ;
			RECT 3.355 2.325 3.635 2.415 ;
		END
		AntennaGateArea 0.462 ;
	END in3
	PIN in0
		DIRECTION input ;
		USE SIGNAL ;
		PORT
			LAYER M1 ;
			RECT 1.36 3.51 1.74 3.6 ;
			LAYER M1 ;
			RECT 1.155 3.23 1.74 3.51 ;
			LAYER M1 ;
			RECT 1.36 3.22 1.74 3.23 ;
		END
		AntennaGateArea 0.231 ;
	END in0
	OBS
		LAYER M1 ;
		RECT 1.435 4.055 1.715 4.95 ;
		LAYER M1 ;
		RECT 4.095 4.055 4.375 4.95 ;
		LAYER M1 ;
		RECT 0.755 3.865 4.375 4.055 ;
		LAYER M1 ;
		RECT 0.755 2.93 0.95 3.865 ;
		LAYER M1 ;
		RECT 0.705 2.735 1.55 2.93 ;
		LAYER M1 ;
		RECT 0.705 2.65 0.985 2.735 ;
		LAYER M1 ;
		RECT 1.355 1.995 1.55 2.735 ;
		LAYER M1 ;
		RECT 1.945 1.995 3.435 2.0 ;
		LAYER M1 ;
		RECT 1.35 1.295 1.63 1.995 ;
		LAYER M1 ;
		RECT 1.94 1.805 3.435 1.995 ;
		LAYER M1 ;
		RECT 1.94 1.295 2.22 1.805 ;
		LAYER M1 ;
		RECT 3.12 1.295 3.4 1.805 ;
	END
END MMI_OA31B
MACRO MMI_OA31C
	CLASS CORE ;
	FOREIGN MMI_OA31C 0 0 ;
	SIZE 5.58 BY 6.2 ;
	SYMMETRY X Y ;
	SITE CORE1 ;
	PIN out
		DIRECTION output ;
		USE SIGNAL ;
		PORT
			LAYER M1 ;
			RECT 0.75 3.64 1.03 5.11 ;
			LAYER M1 ;
			RECT 0.12 2.93 0.5 2.98 ;
			LAYER M1 ;
			RECT 0.75 2.93 0.94 3.64 ;
			LAYER M1 ;
			RECT 0.12 2.65 0.94 2.93 ;
			LAYER M1 ;
			RECT 0.12 2.6 0.5 2.65 ;
			LAYER M1 ;
			RECT 0.75 2.395 0.94 2.65 ;
			LAYER M1 ;
			RECT 0.75 0.925 1.03 2.395 ;
		END
		AntennaDiffArea 1.2859 ;
	END out
	PIN in1
		DIRECTION input ;
		USE SIGNAL ;
		PORT
			LAYER M1 ;
			RECT 4.505 3.37 4.785 3.41 ;
			LAYER M1 ;
			RECT 2.72 3.18 4.785 3.37 ;
			LAYER M1 ;
			RECT 2.72 2.98 2.91 3.18 ;
			LAYER M1 ;
			RECT 4.505 3.13 4.785 3.18 ;
			LAYER M1 ;
			RECT 2.6 2.61 2.98 2.98 ;
			LAYER M1 ;
			RECT 2.565 2.6 2.98 2.61 ;
			LAYER M1 ;
			RECT 2.565 2.33 2.845 2.6 ;
		END
		AntennaGateArea 0.624 ;
	END in1
	PIN GND
		DIRECTION inout ;
		USE GROUND ;
		PORT
			LAYER M1 ;
			RECT 0.16 0.42 0.44 2.395 ;
			LAYER M1 ;
			RECT 2.53 0.42 2.81 1.07 ;
			LAYER M1 ;
			RECT 3.71 0.42 3.99 1.76 ;
			LAYER M1 ;
			RECT 0.0 -0.42 5.58 0.42 ;
		END
	END GND
	PIN in2
		DIRECTION input ;
		USE SIGNAL ;
		PORT
			LAYER M1 ;
			RECT 3.185 2.795 3.6 2.98 ;
			LAYER M1 ;
			RECT 4.135 2.795 4.415 2.84 ;
			LAYER M1 ;
			RECT 3.185 2.7 4.415 2.795 ;
			LAYER M1 ;
			RECT 3.22 2.6 4.415 2.7 ;
			LAYER M1 ;
			RECT 4.135 2.56 4.415 2.6 ;
		END
		AntennaGateArea 0.624 ;
	END in2
	PIN VDD
		DIRECTION inout ;
		USE POWER ;
		PORT
			LAYER M1 ;
			RECT 0.0 5.78 5.58 6.62 ;
			LAYER M1 ;
			RECT 0.16 3.64 0.44 5.78 ;
			LAYER M1 ;
			RECT 1.34 3.64 1.62 5.78 ;
			LAYER M1 ;
			RECT 3.365 4.055 3.645 5.78 ;
		END
	END VDD
	PIN in3
		DIRECTION input ;
		USE SIGNAL ;
		PORT
			LAYER M1 ;
			RECT 3.515 2.08 4.22 2.36 ;
			LAYER M1 ;
			RECT 3.84 1.98 4.22 2.08 ;
		END
		AntennaGateArea 0.624 ;
	END in3
	PIN in0
		DIRECTION input ;
		USE SIGNAL ;
		PORT
			LAYER M1 ;
			RECT 1.745 2.08 2.36 2.36 ;
			LAYER M1 ;
			RECT 1.98 1.98 2.36 2.08 ;
		END
		AntennaGateArea 0.312 ;
	END in0
	OBS
		LAYER M1 ;
		RECT 2.035 3.82 2.315 5.115 ;
		LAYER M1 ;
		RECT 4.7 3.82 4.98 5.115 ;
		LAYER M1 ;
		RECT 2.035 3.63 4.98 3.82 ;
		LAYER M1 ;
		RECT 2.035 3.625 2.315 3.63 ;
		LAYER M1 ;
		RECT 4.7 3.625 4.98 3.63 ;
		LAYER M1 ;
		RECT 1.155 2.93 1.435 2.97 ;
		LAYER M1 ;
		RECT 2.035 2.93 2.225 3.625 ;
		LAYER M1 ;
		RECT 1.155 2.735 2.225 2.93 ;
		LAYER M1 ;
		RECT 1.155 2.69 1.545 2.735 ;
		LAYER M1 ;
		RECT 1.35 1.76 1.545 2.69 ;
		LAYER M1 ;
		RECT 1.35 0.79 1.63 1.76 ;
		LAYER M1 ;
		RECT 1.94 1.735 2.22 1.76 ;
		LAYER M1 ;
		RECT 3.12 1.735 3.4 1.76 ;
		LAYER M1 ;
		RECT 1.94 1.54 3.4 1.735 ;
		LAYER M1 ;
		RECT 1.94 0.79 2.22 1.54 ;
		LAYER M1 ;
		RECT 3.12 0.79 3.4 1.54 ;
	END
END MMI_OA31C
MACRO MMI_OAI21A
	CLASS CORE ;
	FOREIGN MMI_OAI21A 0 0 ;
	SIZE 2.48 BY 6.2 ;
	SYMMETRY X Y ;
	SITE CORE1 ;
	PIN out
		DIRECTION output ;
		USE SIGNAL ;
		PORT
			LAYER M1 ;
			RECT 0.795 3.585 1.075 5.055 ;
			LAYER M1 ;
			RECT 0.795 3.385 0.985 3.585 ;
			LAYER M1 ;
			RECT 0.16 3.19 0.985 3.385 ;
			LAYER M1 ;
			RECT 0.16 2.98 0.355 3.19 ;
			LAYER M1 ;
			RECT 0.12 2.6 0.5 2.98 ;
			LAYER M1 ;
			RECT 0.16 1.765 0.355 2.6 ;
			LAYER M1 ;
			RECT 0.16 1.065 0.44 1.765 ;
		END
		AntennaDiffArea 0.98175 ;
	END out
	PIN in1
		DIRECTION input ;
		USE SIGNAL ;
		PORT
			LAYER M1 ;
			RECT 1.36 2.935 1.74 2.98 ;
			LAYER M1 ;
			RECT 1.11 2.93 1.74 2.935 ;
			LAYER M1 ;
			RECT 0.99 2.65 1.74 2.93 ;
			LAYER M1 ;
			RECT 1.36 2.6 1.74 2.65 ;
		END
		AntennaGateArea 0.3465 ;
	END in1
	PIN GND
		DIRECTION inout ;
		USE GROUND ;
		PORT
			LAYER M1 ;
			RECT 1.34 0.42 1.62 1.345 ;
			LAYER M1 ;
			RECT 0.0 -0.42 2.48 0.42 ;
		END
	END GND
	PIN in2
		DIRECTION input ;
		USE SIGNAL ;
		PORT
			LAYER M1 ;
			RECT 1.98 2.35 2.36 2.36 ;
			LAYER M1 ;
			RECT 1.7 2.07 2.36 2.35 ;
			LAYER M1 ;
			RECT 1.98 1.98 2.36 2.07 ;
		END
		AntennaGateArea 0.3465 ;
	END in2
	PIN VDD
		DIRECTION inout ;
		USE POWER ;
		PORT
			LAYER M1 ;
			RECT 0.0 5.78 2.48 6.62 ;
			LAYER M1 ;
			RECT 0.16 3.585 0.44 5.78 ;
			LAYER M1 ;
			RECT 1.755 3.585 2.035 5.78 ;
		END
	END VDD
	PIN in0
		DIRECTION input ;
		USE SIGNAL ;
		PORT
			LAYER M1 ;
			RECT 0.74 2.355 1.12 2.36 ;
			LAYER M1 ;
			RECT 0.555 2.075 1.12 2.355 ;
			LAYER M1 ;
			RECT 0.74 1.98 1.12 2.075 ;
		END
		AntennaGateArea 0.231 ;
	END in0
	OBS
		LAYER M1 ;
		RECT 0.755 1.765 2.245 1.77 ;
		LAYER M1 ;
		RECT 0.75 1.575 2.245 1.765 ;
		LAYER M1 ;
		RECT 0.75 1.065 1.03 1.575 ;
		LAYER M1 ;
		RECT 1.93 1.065 2.21 1.575 ;
	END
END MMI_OAI21A
MACRO MMI_OAI21B
	CLASS CORE ;
	FOREIGN MMI_OAI21B 0 0 ;
	SIZE 3.1 BY 6.2 ;
	SYMMETRY X Y ;
	SITE CORE1 ;
	PIN out
		DIRECTION output ;
		USE SIGNAL ;
		PORT
			LAYER M1 ;
			RECT 0.155 3.695 0.435 4.975 ;
			LAYER M1 ;
			RECT 1.705 3.695 1.985 4.975 ;
			LAYER M1 ;
			RECT 0.155 3.505 1.985 3.695 ;
			LAYER M1 ;
			RECT 0.155 2.98 0.35 3.505 ;
			LAYER M1 ;
			RECT 0.12 2.6 0.5 2.98 ;
			LAYER M1 ;
			RECT 0.155 2.395 0.35 2.6 ;
			LAYER M1 ;
			RECT 0.155 2.13 0.815 2.395 ;
			LAYER M1 ;
			RECT 0.535 0.925 0.815 2.13 ;
		END
		AntennaDiffArea 1.8942 ;
	END out
	PIN in1
		DIRECTION input ;
		USE SIGNAL ;
		PORT
			LAYER M1 ;
			RECT 1.36 2.93 1.74 2.98 ;
			LAYER M1 ;
			RECT 1.34 2.65 1.74 2.93 ;
			LAYER M1 ;
			RECT 1.36 2.6 1.74 2.65 ;
		END
		AntennaGateArea 0.693 ;
	END in1
	PIN GND
		DIRECTION inout ;
		USE GROUND ;
		PORT
			LAYER M1 ;
			RECT 1.715 0.42 1.995 1.985 ;
			LAYER M1 ;
			RECT 0.0 -0.42 3.1 0.42 ;
		END
	END GND
	PIN in2
		DIRECTION input ;
		USE SIGNAL ;
		PORT
			LAYER M1 ;
			RECT 2.6 2.93 2.98 2.98 ;
			LAYER M1 ;
			RECT 2.285 2.65 2.98 2.93 ;
			LAYER M1 ;
			RECT 2.6 2.6 2.98 2.65 ;
		END
		AntennaGateArea 0.693 ;
	END in2
	PIN VDD
		DIRECTION inout ;
		USE POWER ;
		PORT
			LAYER M1 ;
			RECT 0.0 5.78 3.1 6.62 ;
			LAYER M1 ;
			RECT 0.745 3.915 1.025 5.78 ;
			LAYER M1 ;
			RECT 2.67 4.975 2.95 5.78 ;
			LAYER M1 ;
			RECT 2.665 4.775 2.95 4.975 ;
			LAYER M1 ;
			RECT 2.665 3.505 2.945 4.775 ;
		END
	END VDD
	PIN in0
		DIRECTION input ;
		USE SIGNAL ;
		PORT
			LAYER M1 ;
			RECT 0.74 2.93 1.12 2.98 ;
			LAYER M1 ;
			RECT 0.7 2.65 1.12 2.93 ;
			LAYER M1 ;
			RECT 0.74 2.6 1.12 2.65 ;
		END
		AntennaGateArea 0.462 ;
	END in0
	OBS
		LAYER M1 ;
		RECT 1.125 2.205 2.595 2.395 ;
		LAYER M1 ;
		RECT 1.125 0.925 1.405 2.205 ;
		LAYER M1 ;
		RECT 2.315 0.925 2.595 2.205 ;
	END
END MMI_OAI21B
MACRO MMI_OAI21C
	CLASS CORE ;
	FOREIGN MMI_OAI21C 0 0 ;
	SIZE 6.2 BY 6.2 ;
	SYMMETRY X Y ;
	SITE CORE1 ;
	PIN out
		DIRECTION output ;
		USE SIGNAL ;
		PORT
			LAYER M1 ;
			RECT 0.765 3.7 1.045 4.98 ;
			LAYER M1 ;
			RECT 2.315 3.7 2.595 4.98 ;
			LAYER M1 ;
			RECT 4.245 3.7 4.525 4.98 ;
			LAYER M1 ;
			RECT 0.765 3.505 4.525 3.7 ;
			LAYER M1 ;
			RECT 0.12 2.885 0.5 2.98 ;
			LAYER M1 ;
			RECT 0.765 2.885 0.955 3.505 ;
			LAYER M1 ;
			RECT 0.12 2.695 0.955 2.885 ;
			LAYER M1 ;
			RECT 0.12 2.6 0.5 2.695 ;
			LAYER M1 ;
			RECT 0.245 2.34 0.435 2.6 ;
			LAYER M1 ;
			RECT 0.16 1.575 0.44 2.34 ;
			LAYER M1 ;
			RECT 1.34 1.575 1.62 1.665 ;
			LAYER M1 ;
			RECT 0.15 1.385 1.64 1.575 ;
		END
		AntennaDiffArea 2.888675 ;
	END out
	PIN in1
		DIRECTION input ;
		USE SIGNAL ;
		PORT
			LAYER M1 ;
			RECT 2.6 2.925 2.98 2.98 ;
			LAYER M1 ;
			RECT 2.6 2.645 3.53 2.925 ;
			LAYER M1 ;
			RECT 2.6 2.6 2.98 2.645 ;
		END
		AntennaGateArea 1.38525 ;
	END in1
	PIN GND
		DIRECTION inout ;
		USE GROUND ;
		PORT
			LAYER M1 ;
			RECT 2.52 0.42 2.8 1.665 ;
			LAYER M1 ;
			RECT 3.7 0.42 3.98 1.665 ;
			LAYER M1 ;
			RECT 4.88 0.42 5.16 1.665 ;
			LAYER M1 ;
			RECT 0.0 -0.42 6.2 0.42 ;
		END
	END GND
	PIN in2
		DIRECTION input ;
		USE SIGNAL ;
		PORT
			LAYER M1 ;
			RECT 5.08 2.925 5.46 2.98 ;
			LAYER M1 ;
			RECT 4.815 2.645 5.46 2.925 ;
			LAYER M1 ;
			RECT 5.08 2.6 5.46 2.645 ;
		END
		AntennaGateArea 1.38525 ;
	END in2
	PIN VDD
		DIRECTION inout ;
		USE POWER ;
		PORT
			LAYER M1 ;
			RECT 0.0 5.78 6.2 6.62 ;
			LAYER M1 ;
			RECT 0.175 3.51 0.455 5.78 ;
			LAYER M1 ;
			RECT 1.355 3.92 1.635 5.78 ;
			LAYER M1 ;
			RECT 3.28 3.92 3.56 5.78 ;
			LAYER M1 ;
			RECT 5.21 3.51 5.49 5.78 ;
		END
	END VDD
	PIN in0
		DIRECTION input ;
		USE SIGNAL ;
		PORT
			LAYER M1 ;
			RECT 1.36 2.925 1.74 2.98 ;
			LAYER M1 ;
			RECT 1.2 2.645 1.74 2.925 ;
			LAYER M1 ;
			RECT 1.36 2.6 1.74 2.645 ;
		END
		AntennaGateArea 0.92325 ;
	END in0
	OBS
		LAYER M1 ;
		RECT 0.75 2.15 5.75 2.34 ;
		LAYER M1 ;
		RECT 0.75 2.055 1.03 2.15 ;
		LAYER M1 ;
		RECT 1.93 1.385 2.21 2.15 ;
		LAYER M1 ;
		RECT 3.11 1.385 3.39 2.15 ;
		LAYER M1 ;
		RECT 4.29 1.385 4.57 2.15 ;
		LAYER M1 ;
		RECT 5.47 1.385 5.75 2.15 ;
	END
END MMI_OAI21C
MACRO MMI_OAI22A
	CLASS CORE ;
	FOREIGN MMI_OAI22A 0 0 ;
	SIZE 3.1 BY 6.2 ;
	SYMMETRY X Y ;
	SITE CORE1 ;
	PIN out
		DIRECTION output ;
		USE SIGNAL ;
		PORT
			LAYER M1 ;
			RECT 1.12 3.67 1.4 5.14 ;
			LAYER M1 ;
			RECT 1.12 3.465 1.31 3.67 ;
			LAYER M1 ;
			RECT 0.15 3.27 1.31 3.465 ;
			LAYER M1 ;
			RECT 0.15 2.98 0.345 3.27 ;
			LAYER M1 ;
			RECT 0.12 2.6 0.5 2.98 ;
			LAYER M1 ;
			RECT 0.15 1.54 0.345 2.6 ;
			LAYER M1 ;
			RECT 0.15 1.35 1.645 1.54 ;
			LAYER M1 ;
			RECT 1.365 1.26 1.645 1.35 ;
		END
		AntennaDiffArea 1.0241 ;
	END out
	PIN in1
		DIRECTION input ;
		USE SIGNAL ;
		PORT
			LAYER M1 ;
			RECT 1.98 2.35 2.36 2.36 ;
			LAYER M1 ;
			RECT 1.945 2.07 2.36 2.35 ;
			LAYER M1 ;
			RECT 1.98 1.98 2.36 2.07 ;
		END
		AntennaGateArea 0.3465 ;
	END in1
	PIN GND
		DIRECTION inout ;
		USE GROUND ;
		PORT
			LAYER M1 ;
			RECT 0.16 0.42 0.44 1.12 ;
			LAYER M1 ;
			RECT 2.56 0.42 2.84 1.54 ;
			LAYER M1 ;
			RECT 0.0 -0.42 3.1 0.42 ;
		END
	END GND
	PIN in2
		DIRECTION input ;
		USE SIGNAL ;
		PORT
			LAYER M1 ;
			RECT 1.98 2.93 2.36 2.98 ;
			LAYER M1 ;
			RECT 0.925 2.885 1.205 2.93 ;
			LAYER M1 ;
			RECT 1.98 2.885 2.57 2.93 ;
			LAYER M1 ;
			RECT 0.925 2.695 2.57 2.885 ;
			LAYER M1 ;
			RECT 0.925 2.65 1.205 2.695 ;
			LAYER M1 ;
			RECT 1.98 2.65 2.57 2.695 ;
			LAYER M1 ;
			RECT 1.98 2.6 2.36 2.65 ;
		END
		AntennaGateArea 0.3465 ;
	END in2
	PIN VDD
		DIRECTION inout ;
		USE POWER ;
		PORT
			LAYER M1 ;
			RECT 0.0 5.78 3.1 6.62 ;
			LAYER M1 ;
			RECT 0.16 3.67 0.44 5.78 ;
			LAYER M1 ;
			RECT 2.08 3.67 2.36 5.78 ;
		END
	END VDD
	PIN in3
		DIRECTION input ;
		USE SIGNAL ;
		PORT
			LAYER M1 ;
			RECT 0.74 2.35 1.12 2.36 ;
			LAYER M1 ;
			RECT 0.555 2.07 1.12 2.35 ;
			LAYER M1 ;
			RECT 0.74 1.98 1.12 2.07 ;
		END
		AntennaGateArea 0.3465 ;
	END in3
	PIN in0
		DIRECTION input ;
		USE SIGNAL ;
		PORT
			LAYER M1 ;
			RECT 1.36 2.35 1.74 2.36 ;
			LAYER M1 ;
			RECT 1.32 2.07 1.74 2.35 ;
			LAYER M1 ;
			RECT 1.36 1.98 1.74 2.07 ;
		END
		AntennaGateArea 0.3465 ;
	END in0
	OBS
		LAYER M1 ;
		RECT 0.765 1.055 1.045 1.12 ;
		LAYER M1 ;
		RECT 1.97 1.055 2.25 1.12 ;
		LAYER M1 ;
		RECT 0.765 0.86 2.25 1.055 ;
		LAYER M1 ;
		RECT 0.765 0.84 1.045 0.86 ;
		LAYER M1 ;
		RECT 1.97 0.84 2.25 0.86 ;
	END
END MMI_OAI22A
MACRO MMI_OAI22B
	CLASS CORE ;
	FOREIGN MMI_OAI22B 0 0 ;
	SIZE 5.58 BY 6.2 ;
	SYMMETRY X Y ;
	SITE CORE1 ;
	PIN out
		DIRECTION output ;
		USE SIGNAL ;
		PORT
			LAYER M1 ;
			RECT 0.16 3.76 0.44 5.045 ;
			LAYER M1 ;
			RECT 2.085 3.76 2.365 5.045 ;
			LAYER M1 ;
			RECT 4.005 3.76 4.285 5.045 ;
			LAYER M1 ;
			RECT 0.16 3.57 4.285 3.76 ;
			LAYER M1 ;
			RECT 3.22 3.22 3.6 3.57 ;
			LAYER M1 ;
			RECT 3.345 2.4 3.535 3.22 ;
			LAYER M1 ;
			RECT 1.445 2.21 4.03 2.4 ;
			LAYER M1 ;
			RECT 1.445 1.88 1.635 2.21 ;
			LAYER M1 ;
			RECT 3.84 1.88 4.03 2.21 ;
			LAYER M1 ;
			RECT 1.355 1.18 1.635 1.88 ;
			LAYER M1 ;
			RECT 3.835 1.18 4.115 1.88 ;
		END
		AntennaDiffArea 2.5718 ;
	END out
	PIN in1
		DIRECTION input ;
		USE SIGNAL ;
		PORT
			LAYER M1 ;
			RECT 1.32 3.18 2.76 3.37 ;
			LAYER M1 ;
			RECT 1.32 3.09 1.6 3.18 ;
			LAYER M1 ;
			RECT 2.57 2.98 2.76 3.18 ;
			LAYER M1 ;
			RECT 2.57 2.93 2.98 2.98 ;
			LAYER M1 ;
			RECT 2.57 2.695 3.005 2.93 ;
			LAYER M1 ;
			RECT 2.6 2.65 3.005 2.695 ;
			LAYER M1 ;
			RECT 2.6 2.6 2.98 2.65 ;
		END
		AntennaGateArea 0.693 ;
	END in1
	PIN GND
		DIRECTION inout ;
		USE GROUND ;
		PORT
			LAYER M1 ;
			RECT 0.175 0.42 0.455 1.88 ;
			LAYER M1 ;
			RECT 2.595 0.42 2.875 1.545 ;
			LAYER M1 ;
			RECT 5.015 0.42 5.295 1.88 ;
			LAYER M1 ;
			RECT 0.0 -0.42 5.58 0.42 ;
		END
	END GND
	PIN in2
		DIRECTION input ;
		USE SIGNAL ;
		PORT
			LAYER M1 ;
			RECT 1.98 2.6 2.36 2.98 ;
		END
		AntennaGateArea 0.693 ;
	END in2
	PIN VDD
		DIRECTION inout ;
		USE POWER ;
		PORT
			LAYER M1 ;
			RECT 0.0 5.78 5.58 6.62 ;
			LAYER M1 ;
			RECT 1.12 3.985 1.4 5.78 ;
			LAYER M1 ;
			RECT 3.045 3.985 3.325 5.78 ;
		END
	END VDD
	PIN in3
		DIRECTION input ;
		USE SIGNAL ;
		PORT
			LAYER M1 ;
			RECT 4.46 2.6 4.84 2.98 ;
		END
		AntennaGateArea 0.693 ;
	END in3
	PIN in0
		DIRECTION input ;
		USE SIGNAL ;
		PORT
			LAYER M1 ;
			RECT 0.74 2.885 1.12 2.98 ;
			LAYER M1 ;
			RECT 0.555 2.605 1.12 2.885 ;
			LAYER M1 ;
			RECT 0.815 2.6 1.12 2.605 ;
		END
		AntennaGateArea 0.693 ;
	END in0
	OBS
		LAYER M1 ;
		RECT 2.035 1.88 3.435 2.01 ;
		LAYER M1 ;
		RECT 0.765 0.98 1.045 1.88 ;
		LAYER M1 ;
		RECT 1.945 1.82 3.525 1.88 ;
		LAYER M1 ;
		RECT 1.945 0.98 2.225 1.82 ;
		LAYER M1 ;
		RECT 0.765 0.785 2.225 0.98 ;
		LAYER M1 ;
		RECT 3.245 0.98 3.525 1.82 ;
		LAYER M1 ;
		RECT 4.425 0.98 4.705 1.88 ;
		LAYER M1 ;
		RECT 3.245 0.785 4.705 0.98 ;
	END
END MMI_OAI22B
MACRO MMI_OAI31A
	CLASS CORE ;
	FOREIGN MMI_OAI31A 0 0 ;
	SIZE 3.1 BY 6.2 ;
	SYMMETRY X Y ;
	SITE CORE1 ;
	PIN out
		DIRECTION output ;
		USE SIGNAL ;
		PORT
			LAYER M1 ;
			RECT 1.01 3.385 1.29 5.185 ;
			LAYER M1 ;
			RECT 0.27 3.345 1.29 3.385 ;
			LAYER M1 ;
			RECT 0.27 3.195 1.285 3.345 ;
			LAYER M1 ;
			RECT 0.27 2.98 0.46 3.195 ;
			LAYER M1 ;
			RECT 0.12 2.6 0.5 2.98 ;
			LAYER M1 ;
			RECT 0.265 1.775 0.46 2.6 ;
			LAYER M1 ;
			RECT 0.26 1.075 0.54 1.775 ;
		END
		AntennaDiffArea 1.287875 ;
	END out
	PIN in1
		DIRECTION input ;
		USE SIGNAL ;
		PORT
			LAYER M1 ;
			RECT 1.36 2.92 1.74 2.98 ;
			LAYER M1 ;
			RECT 1.205 2.64 1.74 2.92 ;
			LAYER M1 ;
			RECT 1.36 2.6 1.74 2.64 ;
		END
		AntennaGateArea 0.46275 ;
	END in1
	PIN GND
		DIRECTION inout ;
		USE GROUND ;
		PORT
			LAYER M1 ;
			RECT 1.44 0.42 1.72 1.36 ;
			LAYER M1 ;
			RECT 2.62 0.42 2.9 1.775 ;
			LAYER M1 ;
			RECT 0.0 -0.42 3.1 0.42 ;
		END
	END GND
	PIN in2
		DIRECTION input ;
		USE SIGNAL ;
		PORT
			LAYER M1 ;
			RECT 1.98 2.305 2.36 2.36 ;
			LAYER M1 ;
			RECT 1.765 2.025 2.36 2.305 ;
			LAYER M1 ;
			RECT 1.98 1.98 2.36 2.025 ;
		END
		AntennaGateArea 0.46275 ;
	END in2
	PIN VDD
		DIRECTION inout ;
		USE POWER ;
		PORT
			LAYER M1 ;
			RECT 0.0 5.78 3.1 6.62 ;
			LAYER M1 ;
			RECT 0.375 3.585 0.655 5.78 ;
			LAYER M1 ;
			RECT 2.34 3.345 2.62 5.78 ;
		END
	END VDD
	PIN in3
		DIRECTION input ;
		USE SIGNAL ;
		PORT
			LAYER M1 ;
			RECT 2.6 2.94 2.98 2.98 ;
			LAYER M1 ;
			RECT 2.38 2.66 2.98 2.94 ;
			LAYER M1 ;
			RECT 2.575 2.615 2.98 2.66 ;
			LAYER M1 ;
			RECT 2.6 2.6 2.98 2.615 ;
		END
		AntennaGateArea 0.46275 ;
	END in3
	PIN in0
		DIRECTION input ;
		USE SIGNAL ;
		PORT
			LAYER M1 ;
			RECT 0.74 2.3 1.12 2.36 ;
			LAYER M1 ;
			RECT 0.66 2.02 1.12 2.3 ;
			LAYER M1 ;
			RECT 0.74 1.98 1.12 2.02 ;
		END
		AntennaGateArea 0.231 ;
	END in0
	OBS
		LAYER M1 ;
		RECT 0.85 1.585 2.345 1.775 ;
		LAYER M1 ;
		RECT 0.85 1.075 1.13 1.585 ;
		LAYER M1 ;
		RECT 2.03 1.075 2.31 1.585 ;
	END
END MMI_OAI31A
MACRO MMI_OAI31B
	CLASS CORE ;
	FOREIGN MMI_OAI31B 0 0 ;
	SIZE 6.82 BY 6.2 ;
	SYMMETRY X Y ;
	SITE CORE1 ;
	PIN out
		DIRECTION output ;
		USE SIGNAL ;
		PORT
			LAYER M1 ;
			RECT 0.16 3.865 0.44 5.335 ;
			LAYER M1 ;
			RECT 0.25 3.465 0.44 3.865 ;
			LAYER M1 ;
			RECT 1.29 4.435 1.485 4.445 ;
			LAYER M1 ;
			RECT 2.125 4.435 2.405 5.315 ;
			LAYER M1 ;
			RECT 4.785 4.435 5.065 5.315 ;
			LAYER M1 ;
			RECT 1.29 4.245 5.065 4.435 ;
			LAYER M1 ;
			RECT 1.29 3.6 1.485 4.245 ;
			LAYER M1 ;
			RECT 2.125 4.23 2.405 4.245 ;
			LAYER M1 ;
			RECT 4.785 4.23 5.065 4.245 ;
			LAYER M1 ;
			RECT 0.74 3.465 1.485 3.6 ;
			LAYER M1 ;
			RECT 0.25 3.405 1.485 3.465 ;
			LAYER M1 ;
			RECT 0.25 3.27 1.12 3.405 ;
			LAYER M1 ;
			RECT 0.74 3.22 1.12 3.27 ;
			LAYER M1 ;
			RECT 0.845 2.01 1.04 3.22 ;
			LAYER M1 ;
			RECT 0.765 1.73 1.045 2.01 ;
		END
		AntennaDiffArea 1.9635 ;
	END out
	PIN in1
		DIRECTION input ;
		USE SIGNAL ;
		PORT
			LAYER M1 ;
			RECT 1.99 3.7 2.27 3.98 ;
			LAYER M1 ;
			RECT 2.08 3.49 2.27 3.7 ;
			LAYER M1 ;
			RECT 3.84 3.49 4.22 3.6 ;
			LAYER M1 ;
			RECT 2.08 3.465 4.22 3.49 ;
			LAYER M1 ;
			RECT 4.59 3.465 4.87 3.57 ;
			LAYER M1 ;
			RECT 2.08 3.3 4.87 3.465 ;
			LAYER M1 ;
			RECT 1.99 2.445 2.27 2.49 ;
			LAYER M1 ;
			RECT 3.37 2.445 3.565 3.3 ;
			LAYER M1 ;
			RECT 3.84 3.29 4.87 3.3 ;
			LAYER M1 ;
			RECT 3.84 3.27 4.8 3.29 ;
			LAYER M1 ;
			RECT 3.84 3.22 4.22 3.27 ;
			LAYER M1 ;
			RECT 1.99 2.255 3.565 2.445 ;
			LAYER M1 ;
			RECT 1.99 2.21 2.27 2.255 ;
		END
		AntennaGateArea 0.924 ;
	END in1
	PIN GND
		DIRECTION inout ;
		USE GROUND ;
		PORT
			LAYER M1 ;
			RECT 1.945 0.42 2.225 1.59 ;
			LAYER M1 ;
			RECT 3.125 0.42 3.405 1.59 ;
			LAYER M1 ;
			RECT 4.305 0.42 4.585 1.59 ;
			LAYER M1 ;
			RECT 0.0 -0.42 6.82 0.42 ;
		END
	END GND
	PIN in2
		DIRECTION input ;
		USE SIGNAL ;
		PORT
			LAYER M1 ;
			RECT 1.35 2.98 1.63 3.19 ;
			LAYER M1 ;
			RECT 1.35 2.91 1.74 2.98 ;
			LAYER M1 ;
			RECT 1.36 2.885 1.74 2.91 ;
			LAYER M1 ;
			RECT 2.89 2.885 3.17 2.93 ;
			LAYER M1 ;
			RECT 1.36 2.695 3.17 2.885 ;
			LAYER M1 ;
			RECT 1.36 2.6 1.74 2.695 ;
			LAYER M1 ;
			RECT 2.89 2.65 3.17 2.695 ;
		END
		AntennaGateArea 0.924 ;
	END in2
	PIN VDD
		DIRECTION inout ;
		USE POWER ;
		PORT
			LAYER M1 ;
			RECT 0.0 5.78 6.82 6.62 ;
			LAYER M1 ;
			RECT 0.75 3.865 1.03 5.78 ;
			LAYER M1 ;
			RECT 3.455 4.64 3.735 5.78 ;
			LAYER M1 ;
			RECT 6.115 4.23 6.395 5.78 ;
		END
	END VDD
	PIN in3
		DIRECTION input ;
		USE SIGNAL ;
		PORT
			LAYER M1 ;
			RECT 3.355 3.995 3.635 4.045 ;
			LAYER M1 ;
			RECT 3.355 3.805 6.2 3.995 ;
			LAYER M1 ;
			RECT 3.355 3.765 3.635 3.805 ;
			LAYER M1 ;
			RECT 5.08 2.98 5.275 3.805 ;
			LAYER M1 ;
			RECT 5.92 3.715 6.2 3.805 ;
			LAYER M1 ;
			RECT 5.08 2.6 5.46 2.98 ;
			LAYER M1 ;
			RECT 4.355 2.465 4.635 2.51 ;
			LAYER M1 ;
			RECT 5.08 2.465 5.275 2.6 ;
			LAYER M1 ;
			RECT 4.355 2.275 5.275 2.465 ;
			LAYER M1 ;
			RECT 4.355 2.23 4.635 2.275 ;
		END
		AntennaGateArea 0.924 ;
	END in3
	PIN in0
		DIRECTION input ;
		USE SIGNAL ;
		PORT
			LAYER M1 ;
			RECT 0.12 2.93 0.5 2.98 ;
			LAYER M1 ;
			RECT 0.12 2.65 0.635 2.93 ;
			LAYER M1 ;
			RECT 0.12 2.6 0.5 2.65 ;
		END
		AntennaGateArea 0.462 ;
	END in0
	OBS
		LAYER M1 ;
		RECT 0.175 1.5 0.455 2.01 ;
		LAYER M1 ;
		RECT 1.355 1.82 5.19 2.01 ;
		LAYER M1 ;
		RECT 1.355 1.5 1.635 1.82 ;
		LAYER M1 ;
		RECT 0.17 1.305 1.64 1.5 ;
		LAYER M1 ;
		RECT 2.535 1.31 2.815 1.82 ;
		LAYER M1 ;
		RECT 3.715 1.31 3.995 1.82 ;
		LAYER M1 ;
		RECT 4.91 1.31 5.19 1.82 ;
	END
END MMI_OAI31B
MACRO MMI_OR2B
	CLASS CORE ;
	FOREIGN MMI_OR2B 0 0 ;
	SIZE 2.48 BY 6.2 ;
	SYMMETRY X Y ;
	SITE CORE1 ;
	PIN out
		DIRECTION output ;
		USE SIGNAL ;
		PORT
			LAYER M1 ;
			RECT 1.715 3.81 1.995 5.28 ;
			LAYER M1 ;
			RECT 1.8 2.98 1.995 3.81 ;
			LAYER M1 ;
			RECT 1.8 2.6 2.36 2.98 ;
			LAYER M1 ;
			RECT 2.03 1.85 2.22 2.6 ;
			LAYER M1 ;
			RECT 1.99 1.15 2.27 1.85 ;
		END
		AntennaDiffArea 0.91245 ;
	END out
	PIN in1
		DIRECTION input ;
		USE SIGNAL ;
		PORT
			LAYER M1 ;
			RECT 0.74 3.51 1.12 3.6 ;
			LAYER M1 ;
			RECT 0.74 3.23 1.225 3.51 ;
			LAYER M1 ;
			RECT 0.74 3.22 1.12 3.23 ;
		END
		AntennaGateArea 0.28875 ;
	END in1
	PIN GND
		DIRECTION inout ;
		USE GROUND ;
		PORT
			LAYER M1 ;
			RECT 0.16 0.42 0.44 1.85 ;
			LAYER M1 ;
			RECT 1.4 0.42 1.68 1.85 ;
			LAYER M1 ;
			RECT 0.0 -0.42 2.48 0.42 ;
		END
	END GND
	PIN VDD
		DIRECTION inout ;
		USE POWER ;
		PORT
			LAYER M1 ;
			RECT 0.0 5.78 2.48 6.62 ;
			LAYER M1 ;
			RECT 1.125 3.81 1.405 5.78 ;
		END
	END VDD
	PIN in0
		DIRECTION input ;
		USE SIGNAL ;
		PORT
			LAYER M1 ;
			RECT 0.74 2.93 1.12 2.98 ;
			LAYER M1 ;
			RECT 0.555 2.65 1.12 2.93 ;
			LAYER M1 ;
			RECT 0.74 2.6 1.12 2.65 ;
		END
		AntennaGateArea 0.28875 ;
	END in0
	OBS
		LAYER M1 ;
		RECT 0.16 3.81 0.44 5.28 ;
		LAYER M1 ;
		RECT 0.16 2.31 0.355 3.81 ;
		LAYER M1 ;
		RECT 1.52 2.31 1.8 2.35 ;
		LAYER M1 ;
		RECT 0.16 2.115 1.8 2.31 ;
		LAYER M1 ;
		RECT 0.795 1.85 0.985 2.115 ;
		LAYER M1 ;
		RECT 1.52 2.07 1.8 2.115 ;
		LAYER M1 ;
		RECT 0.75 1.535 1.03 1.85 ;
	END
END MMI_OR2B
MACRO MMI_OR2C
	CLASS CORE ;
	FOREIGN MMI_OR2C 0 0 ;
	SIZE 3.1 BY 6.2 ;
	SYMMETRY X Y ;
	SITE CORE1 ;
	PIN out
		DIRECTION output ;
		USE SIGNAL ;
		PORT
			LAYER M1 ;
			RECT 2.05 3.6 2.33 5.325 ;
			LAYER M1 ;
			RECT 1.98 3.22 2.36 3.6 ;
			LAYER M1 ;
			RECT 2.085 2.09 2.325 3.22 ;
			LAYER M1 ;
			RECT 2.05 0.62 2.33 2.09 ;
		END
		AntennaDiffArea 1.2859 ;
	END out
	PIN in1
		DIRECTION input ;
		USE SIGNAL ;
		PORT
			LAYER M1 ;
			RECT 1.36 3.22 1.74 3.6 ;
			LAYER M1 ;
			RECT 1.36 3.155 1.57 3.22 ;
			LAYER M1 ;
			RECT 1.285 3.145 1.57 3.155 ;
			LAYER M1 ;
			RECT 1.285 2.875 1.565 3.145 ;
		END
		AntennaGateArea 0.39 ;
	END in1
	PIN GND
		DIRECTION inout ;
		USE GROUND ;
		PORT
			LAYER M1 ;
			RECT 0.225 0.42 0.505 2.095 ;
			LAYER M1 ;
			RECT 1.46 0.42 1.74 2.09 ;
			LAYER M1 ;
			RECT 0.0 -0.42 3.1 0.42 ;
		END
	END GND
	PIN VDD
		DIRECTION inout ;
		USE POWER ;
		PORT
			LAYER M1 ;
			RECT 0.0 5.78 3.1 6.62 ;
			LAYER M1 ;
			RECT 1.46 3.855 1.74 5.78 ;
			LAYER M1 ;
			RECT 2.64 3.855 2.92 5.78 ;
		END
	END VDD
	PIN in0
		DIRECTION input ;
		USE SIGNAL ;
		PORT
			LAYER M1 ;
			RECT 0.12 2.93 0.5 2.98 ;
			LAYER M1 ;
			RECT 0.12 2.65 0.655 2.93 ;
			LAYER M1 ;
			RECT 0.12 2.6 0.5 2.65 ;
		END
		AntennaGateArea 0.39 ;
	END in0
	OBS
		LAYER M1 ;
		RECT 0.485 3.76 0.765 5.58 ;
		LAYER M1 ;
		RECT 0.485 3.57 1.06 3.76 ;
		LAYER M1 ;
		RECT 0.865 2.58 1.06 3.57 ;
		LAYER M1 ;
		RECT 0.865 2.39 1.86 2.58 ;
		LAYER M1 ;
		RECT 0.865 2.095 1.06 2.39 ;
		LAYER M1 ;
		RECT 1.58 2.3 1.86 2.39 ;
		LAYER M1 ;
		RECT 0.815 1.645 1.095 2.095 ;
	END
END MMI_OR2C
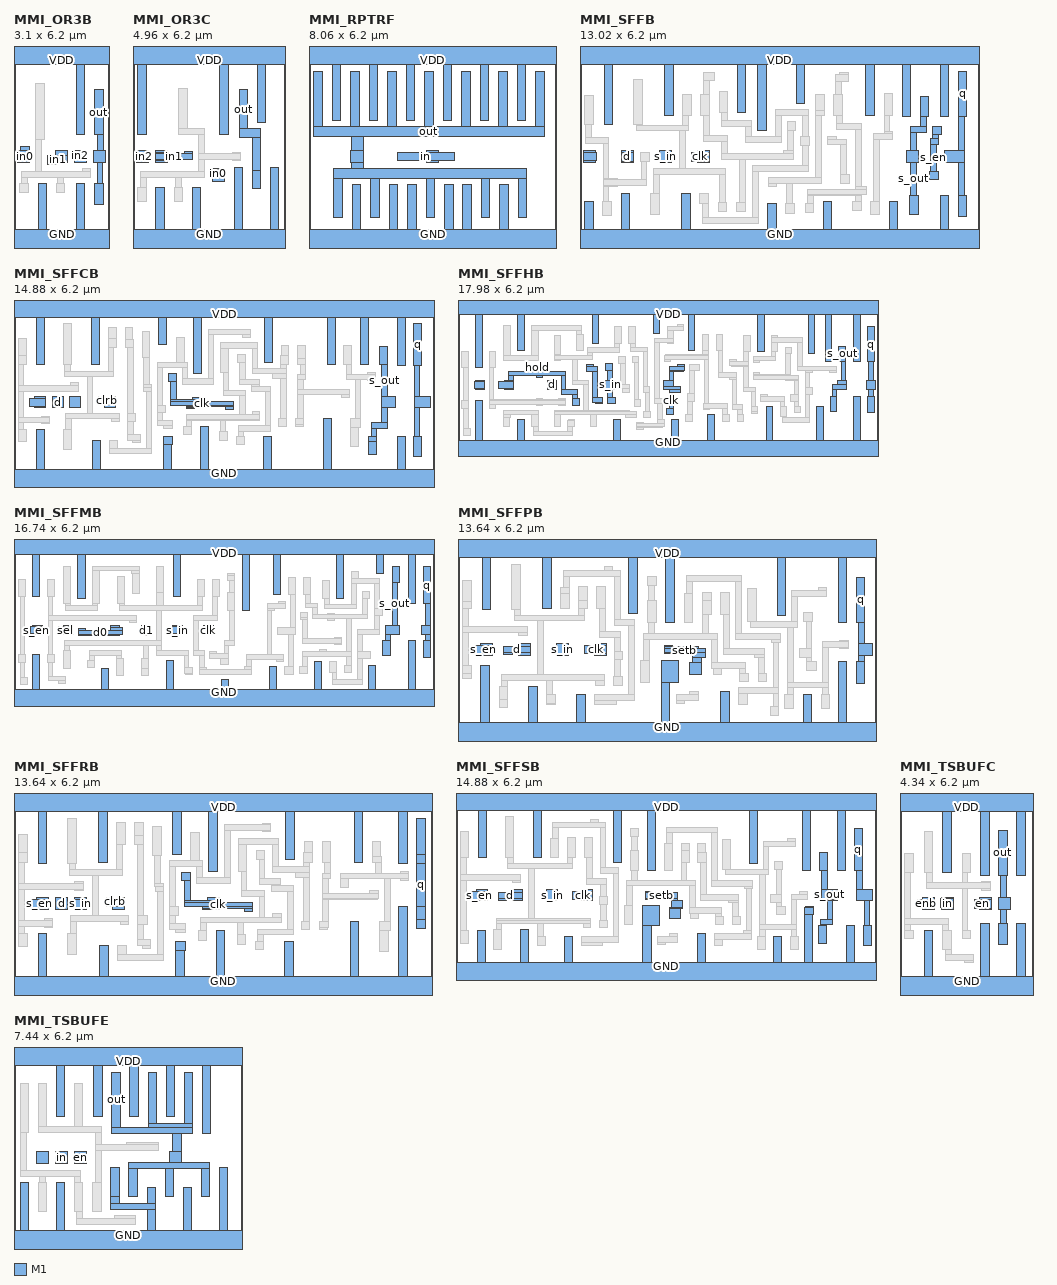
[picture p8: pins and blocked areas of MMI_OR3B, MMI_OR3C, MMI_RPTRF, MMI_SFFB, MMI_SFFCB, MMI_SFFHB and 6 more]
MACRO MMI_OR3B
	CLASS CORE ;
	FOREIGN MMI_OR3B 0 0 ;
	SIZE 3.1 BY 6.2 ;
	SYMMETRY X Y ;
	SITE CORE1 ;
	PIN out
		DIRECTION output ;
		USE SIGNAL ;
		PORT
			LAYER M1 ;
			RECT 2.625 3.505 2.905 4.975 ;
			LAYER M1 ;
			RECT 2.715 2.98 2.905 3.505 ;
			LAYER M1 ;
			RECT 2.6 2.6 2.98 2.98 ;
			LAYER M1 ;
			RECT 2.71 1.915 2.9 2.6 ;
			LAYER M1 ;
			RECT 2.625 1.215 2.905 1.915 ;
		END
		AntennaDiffArea 0.91245 ;
	END out
	PIN in1
		DIRECTION input ;
		USE SIGNAL ;
		PORT
			LAYER M1 ;
			RECT 1.36 2.815 1.74 2.98 ;
			LAYER M1 ;
			RECT 1.1 2.6 1.74 2.815 ;
			LAYER M1 ;
			RECT 1.1 2.535 1.38 2.6 ;
		END
		AntennaGateArea 0.405 ;
	END in1
	PIN GND
		DIRECTION inout ;
		USE GROUND ;
		PORT
			LAYER M1 ;
			RECT 0.785 0.42 1.065 1.915 ;
			LAYER M1 ;
			RECT 2.035 0.42 2.315 1.915 ;
			LAYER M1 ;
			RECT 0.0 -0.42 3.1 0.42 ;
		END
	END GND
	PIN in2
		DIRECTION input ;
		USE SIGNAL ;
		PORT
			LAYER M1 ;
			RECT 1.98 2.975 2.36 2.98 ;
			LAYER M1 ;
			RECT 1.94 2.695 2.36 2.975 ;
			LAYER M1 ;
			RECT 1.98 2.6 2.36 2.695 ;
		END
		AntennaGateArea 0.405 ;
	END in2
	PIN VDD
		DIRECTION inout ;
		USE POWER ;
		PORT
			LAYER M1 ;
			RECT 0.0 5.78 3.1 6.62 ;
			LAYER M1 ;
			RECT 2.035 3.505 2.315 5.78 ;
		END
	END VDD
	PIN in0
		DIRECTION input ;
		USE SIGNAL ;
		PORT
			LAYER M1 ;
			RECT 0.215 2.98 0.495 3.125 ;
			LAYER M1 ;
			RECT 0.12 2.6 0.5 2.98 ;
		END
		AntennaGateArea 0.405 ;
	END in0
	OBS
		LAYER M1 ;
		RECT 0.705 3.345 0.985 5.185 ;
		LAYER M1 ;
		RECT 0.705 2.315 0.895 3.345 ;
		LAYER M1 ;
		RECT 2.23 2.315 2.51 2.4 ;
		LAYER M1 ;
		RECT 0.23 2.12 2.51 2.315 ;
		LAYER M1 ;
		RECT 0.23 1.915 0.425 2.12 ;
		LAYER M1 ;
		RECT 1.415 1.915 1.61 2.12 ;
		LAYER M1 ;
		RECT 0.195 1.6 0.475 1.915 ;
		LAYER M1 ;
		RECT 1.375 1.6 1.655 1.915 ;
	END
END MMI_OR3B
MACRO MMI_OR3C
	CLASS CORE ;
	FOREIGN MMI_OR3C 0 0 ;
	SIZE 4.96 BY 6.2 ;
	SYMMETRY X Y ;
	SITE CORE1 ;
	PIN out
		DIRECTION output ;
		USE SIGNAL ;
		PORT
			LAYER M1 ;
			RECT 3.465 3.69 3.745 4.975 ;
			LAYER M1 ;
			RECT 3.465 3.405 4.175 3.69 ;
			LAYER M1 ;
			RECT 3.89 2.34 4.175 3.405 ;
			LAYER M1 ;
			RECT 3.89 1.73 4.17 2.34 ;
		END
		AntennaDiffArea 1.0395 ;
	END out
	PIN in1
		DIRECTION input ;
		USE SIGNAL ;
		PORT
			LAYER M1 ;
			RECT 0.74 2.93 1.12 2.98 ;
			LAYER M1 ;
			RECT 0.725 2.885 1.12 2.93 ;
			LAYER M1 ;
			RECT 1.665 2.885 1.945 2.96 ;
			LAYER M1 ;
			RECT 0.725 2.695 1.945 2.885 ;
			LAYER M1 ;
			RECT 0.725 2.65 1.12 2.695 ;
			LAYER M1 ;
			RECT 1.665 2.68 1.945 2.695 ;
			LAYER M1 ;
			RECT 0.74 2.6 1.12 2.65 ;
		END
		AntennaGateArea 0.546 ;
	END in1
	PIN GND
		DIRECTION inout ;
		USE GROUND ;
		PORT
			LAYER M1 ;
			RECT 0.75 0.42 1.03 1.78 ;
			LAYER M1 ;
			RECT 1.93 0.42 2.21 1.78 ;
			LAYER M1 ;
			RECT 3.3 0.42 3.58 2.43 ;
			LAYER M1 ;
			RECT 4.48 0.42 4.76 2.43 ;
			LAYER M1 ;
			RECT 0.0 -0.42 4.96 0.42 ;
		END
	END GND
	PIN in2
		DIRECTION input ;
		USE SIGNAL ;
		PORT
			LAYER M1 ;
			RECT 0.12 2.6 0.5 2.98 ;
		END
		AntennaGateArea 0.546 ;
	END in2
	PIN VDD
		DIRECTION inout ;
		USE POWER ;
		PORT
			LAYER M1 ;
			RECT 0.0 5.78 4.96 6.62 ;
			LAYER M1 ;
			RECT 0.16 3.505 0.44 5.78 ;
			LAYER M1 ;
			RECT 2.82 3.505 3.1 5.78 ;
			LAYER M1 ;
			RECT 4.055 3.915 4.335 5.78 ;
		END
	END VDD
	PIN in0
		DIRECTION input ;
		USE SIGNAL ;
		PORT
			LAYER M1 ;
			RECT 2.54 2.36 2.82 2.385 ;
			LAYER M1 ;
			RECT 2.54 2.105 2.98 2.36 ;
			LAYER M1 ;
			RECT 2.6 1.98 2.98 2.105 ;
		END
		AntennaGateArea 0.546 ;
	END in0
	OBS
		LAYER M1 ;
		RECT 1.49 3.695 1.77 4.995 ;
		LAYER M1 ;
		RECT 1.49 3.505 2.335 3.695 ;
		LAYER M1 ;
		RECT 2.145 2.885 2.335 3.505 ;
		LAYER M1 ;
		RECT 3.24 2.885 3.52 2.93 ;
		LAYER M1 ;
		RECT 2.145 2.695 3.52 2.885 ;
		LAYER M1 ;
		RECT 2.145 2.31 2.335 2.695 ;
		LAYER M1 ;
		RECT 3.24 2.65 3.52 2.695 ;
		LAYER M1 ;
		RECT 0.25 2.115 2.335 2.31 ;
		LAYER M1 ;
		RECT 0.25 1.78 0.44 2.115 ;
		LAYER M1 ;
		RECT 1.385 1.78 1.575 2.115 ;
		LAYER M1 ;
		RECT 0.16 1.33 0.44 1.78 ;
		LAYER M1 ;
		RECT 1.34 1.33 1.62 1.78 ;
	END
END MMI_OR3C
MACRO MMI_RPTRF
	CLASS CORE ;
	FOREIGN MMI_RPTRF 0 0 ;
	SIZE 8.06 BY 6.2 ;
	SYMMETRY X Y ;
	SITE CORE1 ;
	PIN out
		DIRECTION output ;
		USE SIGNAL ;
		PORT
			LAYER M1 ;
			RECT 0.15 3.765 0.435 5.575 ;
			LAYER M1 ;
			RECT 1.36 3.765 1.64 5.575 ;
			LAYER M1 ;
			RECT 2.565 3.765 2.85 5.575 ;
			LAYER M1 ;
			RECT 3.77 3.765 4.055 5.575 ;
			LAYER M1 ;
			RECT 4.98 3.765 5.265 5.575 ;
			LAYER M1 ;
			RECT 6.185 3.765 6.47 5.575 ;
			LAYER M1 ;
			RECT 7.39 3.765 7.675 5.575 ;
			LAYER M1 ;
			RECT 0.15 3.43 7.675 3.765 ;
			LAYER M1 ;
			RECT 1.39 2.98 1.77 3.43 ;
			LAYER M1 ;
			RECT 1.36 2.6 1.77 2.98 ;
			LAYER M1 ;
			RECT 1.39 2.395 1.77 2.6 ;
			LAYER M1 ;
			RECT 0.8 2.075 7.11 2.395 ;
			LAYER M1 ;
			RECT 0.8 0.785 1.085 2.075 ;
			LAYER M1 ;
			RECT 2.01 0.785 2.295 2.075 ;
			LAYER M1 ;
			RECT 3.82 0.785 4.105 2.075 ;
			LAYER M1 ;
			RECT 5.62 0.785 5.905 2.075 ;
			LAYER M1 ;
			RECT 6.825 0.785 7.11 2.075 ;
		END
		AntennaDiffArea 9.6763 ;
	END out
	PIN GND
		DIRECTION inout ;
		USE GROUND ;
		PORT
			LAYER M1 ;
			RECT 1.41 0.42 1.695 1.875 ;
			LAYER M1 ;
			RECT 2.615 0.42 2.9 1.875 ;
			LAYER M1 ;
			RECT 3.215 0.42 3.5 1.875 ;
			LAYER M1 ;
			RECT 4.425 0.42 4.71 1.875 ;
			LAYER M1 ;
			RECT 5.015 0.42 5.3 1.875 ;
			LAYER M1 ;
			RECT 6.22 0.42 6.505 1.875 ;
			LAYER M1 ;
			RECT 0.0 -0.42 8.06 0.42 ;
		END
	END GND
	PIN VDD
		DIRECTION inout ;
		USE POWER ;
		PORT
			LAYER M1 ;
			RECT 0.0 5.78 8.06 6.62 ;
			LAYER M1 ;
			RECT 0.755 3.97 1.04 5.78 ;
			LAYER M1 ;
			RECT 1.96 3.97 2.245 5.78 ;
			LAYER M1 ;
			RECT 3.17 3.97 3.455 5.78 ;
			LAYER M1 ;
			RECT 4.375 3.97 4.66 5.78 ;
			LAYER M1 ;
			RECT 5.58 3.97 5.865 5.78 ;
			LAYER M1 ;
			RECT 6.79 3.97 7.075 5.78 ;
		END
	END VDD
	PIN in
		DIRECTION input ;
		USE SIGNAL ;
		PORT
			LAYER M1 ;
			RECT 3.84 2.93 4.22 2.98 ;
			LAYER M1 ;
			RECT 2.895 2.65 4.735 2.93 ;
			LAYER M1 ;
			RECT 3.84 2.6 4.22 2.65 ;
		END
		AntennaGateArea 5.556 ;
	END in
	OBS
	END
END MMI_RPTRF
MACRO MMI_SFFB
	CLASS CORE ;
	FOREIGN MMI_SFFB 0 0 ;
	SIZE 13.02 BY 6.2 ;
	SYMMETRY X Y ;
	SITE CORE1 ;
	PIN d
		DIRECTION input ;
		USE SIGNAL ;
		PORT
			LAYER M1 ;
			RECT 1.36 2.92 1.74 2.98 ;
			LAYER M1 ;
			RECT 1.35 2.64 1.74 2.92 ;
			LAYER M1 ;
			RECT 1.36 2.6 1.74 2.64 ;
		END
		AntennaGateArea 0.3465 ;
	END d
	PIN GND
		DIRECTION inout ;
		USE GROUND ;
		PORT
			LAYER M1 ;
			RECT 0.155 0.42 0.435 1.315 ;
			LAYER M1 ;
			RECT 1.34 0.42 1.62 1.595 ;
			LAYER M1 ;
			RECT 3.31 0.42 3.59 1.575 ;
			LAYER M1 ;
			RECT 6.12 0.42 6.4 1.26 ;
			LAYER M1 ;
			RECT 7.935 0.42 8.215 1.31 ;
			LAYER M1 ;
			RECT 10.085 0.42 10.365 1.335 ;
			LAYER M1 ;
			RECT 11.755 0.42 12.035 1.52 ;
			LAYER M1 ;
			RECT 0.0 -0.42 13.025 0.42 ;
		END
	END GND
	PIN q
		DIRECTION output ;
		USE SIGNAL ;
		PORT
			LAYER M1 ;
			RECT 12.345 4.105 12.625 5.575 ;
			LAYER M1 ;
			RECT 12.35 2.98 12.545 4.105 ;
			LAYER M1 ;
			RECT 11.905 2.6 12.545 2.98 ;
			LAYER M1 ;
			RECT 12.35 1.52 12.545 2.6 ;
			LAYER M1 ;
			RECT 12.345 0.82 12.625 1.52 ;
		END
		AntennaDiffArea 0.91245 ;
	END q
	PIN s_in
		DIRECTION input ;
		USE SIGNAL ;
		PORT
			LAYER M1 ;
			RECT 2.6 2.6 2.98 2.98 ;
		END
		AntennaGateArea 0.17325 ;
	END s_in
	PIN s_en
		DIRECTION input ;
		USE SIGNAL ;
		PORT
			LAYER M1 ;
			RECT 11.5 3.505 11.78 3.785 ;
			LAYER M1 ;
			RECT 11.5 3.37 11.69 3.505 ;
			LAYER M1 ;
			RECT 11.445 3.175 11.69 3.37 ;
			LAYER M1 ;
			RECT 0.12 2.93 0.5 2.98 ;
			LAYER M1 ;
			RECT 0.12 2.65 0.54 2.93 ;
			LAYER M1 ;
			RECT 0.12 2.6 0.5 2.65 ;
			LAYER M1 ;
			RECT 11.445 2.31 11.64 3.175 ;
			LAYER M1 ;
			RECT 11.415 2.03 11.695 2.31 ;
		END
		AntennaGateArea 0.72675 ;
	END s_en
	PIN VDD
		DIRECTION inout ;
		USE POWER ;
		PORT
			LAYER M1 ;
			RECT 0.0 5.78 13.025 6.62 ;
			LAYER M1 ;
			RECT 0.785 3.845 1.065 5.78 ;
			LAYER M1 ;
			RECT 2.755 4.115 3.035 5.78 ;
			LAYER M1 ;
			RECT 5.135 4.215 5.415 5.78 ;
			LAYER M1 ;
			RECT 5.805 3.645 6.085 5.78 ;
			LAYER M1 ;
			RECT 7.05 4.52 7.33 5.78 ;
			LAYER M1 ;
			RECT 9.33 4.135 9.61 5.78 ;
			LAYER M1 ;
			RECT 10.515 4.105 10.795 5.78 ;
			LAYER M1 ;
			RECT 11.755 4.105 12.035 5.78 ;
		END
	END VDD
	PIN s_out
		DIRECTION output ;
		USE SIGNAL ;
		PORT
			LAYER M1 ;
			RECT 11.105 4.105 11.385 4.74 ;
			LAYER M1 ;
			RECT 11.105 3.765 11.295 4.105 ;
			LAYER M1 ;
			RECT 10.78 3.575 11.295 3.765 ;
			LAYER M1 ;
			RECT 10.78 2.98 10.975 3.575 ;
			LAYER M1 ;
			RECT 10.665 2.6 11.04 2.98 ;
			LAYER M1 ;
			RECT 10.78 1.52 10.975 2.6 ;
			LAYER M1 ;
			RECT 10.75 0.885 11.03 1.52 ;
		END
		AntennaDiffArea 0.588675 ;
	END s_out
	PIN clk
		DIRECTION input ;
		USE CLOCK ;
		PORT
			LAYER M1 ;
			RECT 3.84 2.92 4.22 2.98 ;
			LAYER M1 ;
			RECT 3.64 2.64 4.22 2.92 ;
			LAYER M1 ;
			RECT 3.84 2.6 4.22 2.64 ;
		END
		AntennaGateArea 0.44625 ;
	END clk
	OBS
		LAYER M1 ;
		RECT 0.155 3.845 0.435 4.78 ;
		LAYER M1 ;
		RECT 1.745 3.845 2.025 5.315 ;
		LAYER M1 ;
		RECT 4.02 5.255 4.39 5.535 ;
		LAYER M1 ;
		RECT 4.02 4.815 4.215 5.255 ;
		LAYER M1 ;
		RECT 3.345 4.115 3.625 4.815 ;
		LAYER M1 ;
		RECT 3.935 4.115 4.215 4.815 ;
		LAYER M1 ;
		RECT 4.545 4.215 4.825 4.915 ;
		LAYER M1 ;
		RECT 0.18 3.41 0.375 3.845 ;
		LAYER M1 ;
		RECT 1.835 3.815 2.025 3.845 ;
		LAYER M1 ;
		RECT 3.345 3.815 3.54 4.115 ;
		LAYER M1 ;
		RECT 1.835 3.625 3.54 3.815 ;
		LAYER M1 ;
		RECT 0.18 3.22 0.945 3.41 ;
		LAYER M1 ;
		RECT 0.755 2.075 0.945 3.22 ;
		LAYER M1 ;
		RECT 1.99 2.64 2.27 2.92 ;
		LAYER M1 ;
		RECT 0.755 2.055 1.215 2.075 ;
		LAYER M1 ;
		RECT 1.995 2.055 2.185 2.64 ;
		LAYER M1 ;
		RECT 3.24 2.4 3.43 3.625 ;
		LAYER M1 ;
		RECT 4.02 3.47 4.215 4.115 ;
		LAYER M1 ;
		RECT 4.625 3.965 4.82 4.215 ;
		LAYER M1 ;
		RECT 4.625 3.77 5.58 3.965 ;
		LAYER M1 ;
		RECT 4.02 3.275 4.8 3.47 ;
		LAYER M1 ;
		RECT 4.61 2.88 4.8 3.275 ;
		LAYER M1 ;
		RECT 5.385 3.445 5.58 3.77 ;
		LAYER M1 ;
		RECT 8.47 5.455 8.75 5.53 ;
		LAYER M1 ;
		RECT 8.34 5.25 8.75 5.455 ;
		LAYER M1 ;
		RECT 8.34 4.815 8.535 5.25 ;
		LAYER M1 ;
		RECT 6.375 4.125 7.44 4.315 ;
		LAYER M1 ;
		RECT 7.695 4.305 7.975 4.815 ;
		LAYER M1 ;
		RECT 6.375 3.445 6.565 4.125 ;
		LAYER M1 ;
		RECT 5.385 3.25 6.565 3.445 ;
		LAYER M1 ;
		RECT 6.765 3.645 7.045 3.925 ;
		LAYER M1 ;
		RECT 6.765 2.97 6.96 3.645 ;
		LAYER M1 ;
		RECT 7.25 3.445 7.44 4.125 ;
		LAYER M1 ;
		RECT 7.685 4.115 7.975 4.305 ;
		LAYER M1 ;
		RECT 8.285 4.115 8.565 4.815 ;
		LAYER M1 ;
		RECT 9.92 4.135 10.2 4.835 ;
		LAYER M1 ;
		RECT 7.205 3.165 7.485 3.445 ;
		LAYER M1 ;
		RECT 6.63 2.88 6.96 2.97 ;
		LAYER M1 ;
		RECT 4.61 2.69 6.96 2.88 ;
		LAYER M1 ;
		RECT 0.755 1.86 2.185 2.055 ;
		LAYER M1 ;
		RECT 2.395 2.21 4.735 2.4 ;
		LAYER M1 ;
		RECT 0.755 1.795 1.215 1.86 ;
		LAYER M1 ;
		RECT 0.755 1.315 0.945 1.795 ;
		LAYER M1 ;
		RECT 2.395 1.595 2.59 2.21 ;
		LAYER M1 ;
		RECT 0.745 0.88 1.025 1.315 ;
		LAYER M1 ;
		RECT 2.31 0.895 2.59 1.595 ;
		LAYER M1 ;
		RECT 3.9 1.26 4.18 1.575 ;
		LAYER M1 ;
		RECT 4.54 1.29 4.735 2.21 ;
		LAYER M1 ;
		RECT 5.195 1.29 5.385 2.69 ;
		LAYER M1 ;
		RECT 7.25 2.49 7.44 3.165 ;
		LAYER M1 ;
		RECT 3.985 0.81 4.18 1.26 ;
		LAYER M1 ;
		RECT 4.515 1.01 4.795 1.29 ;
		LAYER M1 ;
		RECT 5.105 1.01 5.385 1.29 ;
		LAYER M1 ;
		RECT 5.64 2.3 7.44 2.49 ;
		LAYER M1 ;
		RECT 5.64 0.81 5.83 2.3 ;
		LAYER M1 ;
		RECT 7.685 2.1 7.875 4.115 ;
		LAYER M1 ;
		RECT 8.37 3.855 8.565 4.115 ;
		LAYER M1 ;
		RECT 8.37 3.66 9.185 3.855 ;
		LAYER M1 ;
		RECT 8.09 3.36 8.37 3.45 ;
		LAYER M1 ;
		RECT 8.09 3.17 8.69 3.36 ;
		LAYER M1 ;
		RECT 6.22 2.095 7.875 2.1 ;
		LAYER M1 ;
		RECT 6.135 1.91 7.875 2.095 ;
		LAYER M1 ;
		RECT 8.495 2.195 8.69 3.17 ;
		LAYER M1 ;
		RECT 8.495 1.915 8.79 2.195 ;
		LAYER M1 ;
		RECT 6.135 1.815 6.415 1.91 ;
		LAYER M1 ;
		RECT 6.75 1.26 6.94 1.91 ;
		LAYER M1 ;
		RECT 8.99 1.815 9.185 3.66 ;
		LAYER M1 ;
		RECT 9.925 3.62 10.115 4.135 ;
		LAYER M1 ;
		RECT 9.92 3.53 10.2 3.62 ;
		LAYER M1 ;
		RECT 9.57 3.34 10.2 3.53 ;
		LAYER M1 ;
		RECT 8.99 1.71 9.36 1.815 ;
		LAYER M1 ;
		RECT 7.43 1.535 9.36 1.71 ;
		LAYER M1 ;
		RECT 7.43 1.515 9.185 1.535 ;
		LAYER M1 ;
		RECT 3.985 0.62 5.83 0.81 ;
		LAYER M1 ;
		RECT 6.71 0.945 6.99 1.26 ;
		LAYER M1 ;
		RECT 7.43 1.255 7.625 1.515 ;
		LAYER M1 ;
		RECT 8.99 1.31 9.185 1.515 ;
		LAYER M1 ;
		RECT 9.57 1.335 9.765 3.34 ;
		LAYER M1 ;
		RECT 7.345 0.975 7.625 1.255 ;
		LAYER M1 ;
		RECT 8.905 1.03 9.185 1.31 ;
		LAYER M1 ;
		RECT 9.495 0.885 9.775 1.335 ;
	END
END MMI_SFFB
MACRO MMI_SFFCB
	CLASS CORE ;
	FOREIGN MMI_SFFCB 0 0 ;
	SIZE 14.88 BY 6.2 ;
	SYMMETRY X Y ;
	SITE CORE1 ;
	PIN d
		DIRECTION input ;
		USE SIGNAL ;
		PORT
			LAYER M1 ;
			RECT 1.36 2.6 1.74 2.98 ;
		END
		AntennaGateArea 0.3465 ;
	END d
	PIN GND
		DIRECTION inout ;
		USE GROUND ;
		PORT
			LAYER M1 ;
			RECT 0.79 0.42 1.07 1.82 ;
			LAYER M1 ;
			RECT 2.795 0.42 3.075 1.435 ;
			LAYER M1 ;
			RECT 5.3 1.28 5.615 1.56 ;
			LAYER M1 ;
			RECT 5.31 0.42 5.59 1.28 ;
			LAYER M1 ;
			RECT 6.6 0.42 6.88 1.945 ;
			LAYER M1 ;
			RECT 8.83 0.42 9.11 1.57 ;
			LAYER M1 ;
			RECT 10.965 0.42 11.245 2.21 ;
			LAYER M1 ;
			RECT 13.58 0.42 13.86 1.58 ;
			LAYER M1 ;
			RECT 0.0 -0.42 14.885 0.42 ;
		END
	END GND
	PIN q
		DIRECTION output ;
		USE SIGNAL ;
		PORT
			LAYER M1 ;
			RECT 14.17 4.105 14.45 5.575 ;
			LAYER M1 ;
			RECT 14.175 2.98 14.37 4.105 ;
			LAYER M1 ;
			RECT 14.175 2.6 14.76 2.98 ;
			LAYER M1 ;
			RECT 14.175 1.58 14.37 2.6 ;
			LAYER M1 ;
			RECT 14.17 0.88 14.45 1.58 ;
		END
		AntennaDiffArea 0.91245 ;
	END q
	PIN s_en
		DIRECTION input ;
		USE SIGNAL ;
		PORT
			LAYER M1 ;
			RECT 0.74 2.93 1.12 2.98 ;
			LAYER M1 ;
			RECT 0.555 2.65 1.12 2.93 ;
			LAYER M1 ;
			RECT 0.74 2.6 1.12 2.65 ;
		END
		AntennaGateArea 0.72675 ;
	END s_en
	PIN s_in
		DIRECTION input ;
		USE SIGNAL ;
		PORT
			LAYER M1 ;
			RECT 1.98 2.6 2.36 2.98 ;
		END
		AntennaGateArea 0.17325 ;
	END s_in
	PIN VDD
		DIRECTION inout ;
		USE POWER ;
		PORT
			LAYER M1 ;
			RECT 0.0 5.78 14.885 6.62 ;
			LAYER M1 ;
			RECT 0.79 4.11 1.07 5.78 ;
			LAYER M1 ;
			RECT 2.755 4.115 3.035 5.78 ;
			LAYER M1 ;
			RECT 5.125 4.82 5.405 5.78 ;
			LAYER M1 ;
			RECT 6.36 3.825 6.64 5.78 ;
			LAYER M1 ;
			RECT 8.87 4.2 9.15 5.78 ;
			LAYER M1 ;
			RECT 11.1 4.115 11.38 5.78 ;
			LAYER M1 ;
			RECT 12.28 4.115 12.56 5.78 ;
			LAYER M1 ;
			RECT 13.58 4.105 13.86 5.78 ;
		END
	END VDD
	PIN s_out
		DIRECTION output ;
		USE SIGNAL ;
		PORT
			LAYER M1 ;
			RECT 12.945 4.115 13.225 4.75 ;
			LAYER M1 ;
			RECT 13.025 2.98 13.22 4.115 ;
			LAYER M1 ;
			RECT 13.025 2.6 13.52 2.98 ;
			LAYER M1 ;
			RECT 13.025 2.07 13.22 2.6 ;
			LAYER M1 ;
			RECT 12.665 1.875 13.22 2.07 ;
			LAYER M1 ;
			RECT 12.665 1.585 12.86 1.875 ;
			LAYER M1 ;
			RECT 12.575 1.41 12.86 1.585 ;
			LAYER M1 ;
			RECT 12.575 0.95 12.855 1.41 ;
		END
		AntennaDiffArea 0.59925 ;
	END s_out
	PIN clk
		DIRECTION input ;
		USE CLOCK ;
		PORT
			LAYER M1 ;
			RECT 5.475 3.525 5.755 3.805 ;
			LAYER M1 ;
			RECT 5.56 2.875 5.755 3.525 ;
			LAYER M1 ;
			RECT 6.32 2.875 6.7 2.975 ;
			LAYER M1 ;
			RECT 5.56 2.83 6.7 2.875 ;
			LAYER M1 ;
			RECT 5.56 2.68 7.79 2.83 ;
			LAYER M1 ;
			RECT 6.115 2.635 7.79 2.68 ;
			LAYER M1 ;
			RECT 6.115 2.595 6.7 2.635 ;
			LAYER M1 ;
			RECT 6.115 2.585 6.395 2.595 ;
			LAYER M1 ;
			RECT 7.51 2.55 7.79 2.635 ;
		END
		AntennaGateArea 0.44625 ;
	END clk
	PIN clrb
		DIRECTION input ;
		USE SIGNAL ;
		PORT
			LAYER M1 ;
			RECT 2.99 2.7 3.6 2.98 ;
			LAYER M1 ;
			RECT 3.22 2.6 3.6 2.7 ;
		END
		AntennaGateArea 0.498 ;
	END clrb
	OBS
		LAYER M1 ;
		RECT 0.16 4.455 0.44 5.045 ;
		LAYER M1 ;
		RECT 0.15 4.11 0.44 4.455 ;
		LAYER M1 ;
		RECT 1.75 4.11 2.03 5.58 ;
		LAYER M1 ;
		RECT 3.345 5.035 3.625 5.425 ;
		LAYER M1 ;
		RECT 3.335 4.725 3.625 5.035 ;
		LAYER M1 ;
		RECT 3.935 5.02 4.215 5.425 ;
		LAYER M1 ;
		RECT 3.935 4.725 4.225 5.02 ;
		LAYER M1 ;
		RECT 0.15 3.375 0.345 4.11 ;
		LAYER M1 ;
		RECT 1.8 3.885 1.995 4.11 ;
		LAYER M1 ;
		RECT 3.335 3.885 3.53 4.725 ;
		LAYER M1 ;
		RECT 1.8 3.695 3.53 3.885 ;
		LAYER M1 ;
		RECT 1.99 3.375 2.27 3.495 ;
		LAYER M1 ;
		RECT 0.15 3.18 2.27 3.375 ;
		LAYER M1 ;
		RECT 0.15 2.25 0.345 3.18 ;
		LAYER M1 ;
		RECT 2.59 2.395 2.785 3.695 ;
		LAYER M1 ;
		RECT 4.03 2.4 4.225 4.725 ;
		LAYER M1 ;
		RECT 4.535 4.37 4.815 5.305 ;
		LAYER M1 ;
		RECT 4.6 3.435 4.795 4.37 ;
		LAYER M1 ;
		RECT 5.76 4.195 6.04 5.09 ;
		LAYER M1 ;
		RECT 5.085 4.005 6.16 4.195 ;
		LAYER M1 ;
		RECT 4.6 3.33 4.885 3.435 ;
		LAYER M1 ;
		RECT 4.605 3.155 4.885 3.33 ;
		LAYER M1 ;
		RECT 3.445 2.395 3.725 2.4 ;
		LAYER M1 ;
		RECT 0.985 2.25 1.265 2.3 ;
		LAYER M1 ;
		RECT 0.15 2.055 1.265 2.25 ;
		LAYER M1 ;
		RECT 0.15 1.825 0.345 2.055 ;
		LAYER M1 ;
		RECT 0.985 2.02 1.265 2.055 ;
		LAYER M1 ;
		RECT 1.84 2.2 3.725 2.395 ;
		LAYER M1 ;
		RECT 0.15 1.39 0.44 1.825 ;
		LAYER M1 ;
		RECT 1.84 1.82 2.03 2.2 ;
		LAYER M1 ;
		RECT 3.445 2.12 3.725 2.2 ;
		LAYER M1 ;
		RECT 4.03 2.12 4.315 2.4 ;
		LAYER M1 ;
		RECT 1.75 1.12 2.03 1.82 ;
		LAYER M1 ;
		RECT 4.03 1.635 4.225 2.12 ;
		LAYER M1 ;
		RECT 4.03 1.435 4.49 1.635 ;
		LAYER M1 ;
		RECT 3.385 1.155 3.665 1.435 ;
		LAYER M1 ;
		RECT 4.21 1.355 4.49 1.435 ;
		LAYER M1 ;
		RECT 4.69 1.155 4.88 3.155 ;
		LAYER M1 ;
		RECT 5.085 2.69 5.275 4.005 ;
		LAYER M1 ;
		RECT 5.965 3.625 6.16 4.005 ;
		LAYER M1 ;
		RECT 6.88 5.185 8.385 5.38 ;
		LAYER M1 ;
		RECT 6.88 3.625 7.075 5.185 ;
		LAYER M1 ;
		RECT 8.105 5.1 8.385 5.185 ;
		LAYER M1 ;
		RECT 7.505 4.89 8.635 4.895 ;
		LAYER M1 ;
		RECT 7.32 4.7 8.635 4.89 ;
		LAYER M1 ;
		RECT 7.32 3.83 7.6 4.7 ;
		LAYER M1 ;
		RECT 7.91 4.2 8.19 4.48 ;
		LAYER M1 ;
		RECT 5.965 3.43 7.075 3.625 ;
		LAYER M1 ;
		RECT 7.41 3.22 7.6 3.83 ;
		LAYER M1 ;
		RECT 7.995 3.61 8.185 4.2 ;
		LAYER M1 ;
		RECT 8.445 4.0 8.635 4.7 ;
		LAYER M1 ;
		RECT 9.46 4.445 9.74 4.815 ;
		LAYER M1 ;
		RECT 9.455 4.115 9.74 4.445 ;
		LAYER M1 ;
		RECT 10.05 4.35 10.33 4.815 ;
		LAYER M1 ;
		RECT 10.05 4.115 10.34 4.35 ;
		LAYER M1 ;
		RECT 11.69 4.115 11.97 4.815 ;
		LAYER M1 ;
		RECT 9.455 4.0 9.645 4.115 ;
		LAYER M1 ;
		RECT 8.445 3.81 9.645 4.0 ;
		LAYER M1 ;
		RECT 9.175 3.64 9.645 3.81 ;
		LAYER M1 ;
		RECT 10.15 3.785 10.34 4.115 ;
		LAYER M1 ;
		RECT 7.995 3.42 8.695 3.61 ;
		LAYER M1 ;
		RECT 8.41 3.365 8.695 3.42 ;
		LAYER M1 ;
		RECT 7.41 3.03 8.19 3.22 ;
		LAYER M1 ;
		RECT 8.41 3.175 9.105 3.365 ;
		LAYER M1 ;
		RECT 8.5 3.17 9.105 3.175 ;
		LAYER M1 ;
		RECT 5.08 2.41 5.36 2.69 ;
		LAYER M1 ;
		RECT 5.085 2.15 5.275 2.41 ;
		LAYER M1 ;
		RECT 8.0 2.35 8.19 3.03 ;
		LAYER M1 ;
		RECT 8.435 2.35 8.715 2.46 ;
		LAYER M1 ;
		RECT 6.095 2.18 8.715 2.35 ;
		LAYER M1 ;
		RECT 6.095 2.16 8.705 2.18 ;
		LAYER M1 ;
		RECT 5.085 1.96 5.615 2.15 ;
		LAYER M1 ;
		RECT 5.3 1.87 5.615 1.96 ;
		LAYER M1 ;
		RECT 6.095 1.945 6.29 2.16 ;
		LAYER M1 ;
		RECT 6.01 1.63 6.29 1.945 ;
		LAYER M1 ;
		RECT 3.385 0.965 4.88 1.155 ;
		LAYER M1 ;
		RECT 7.3 1.765 7.49 2.16 ;
		LAYER M1 ;
		RECT 8.915 1.96 9.105 3.17 ;
		LAYER M1 ;
		RECT 9.455 2.21 9.645 3.64 ;
		LAYER M1 ;
		RECT 10.055 3.59 10.34 3.785 ;
		LAYER M1 ;
		RECT 11.77 3.785 11.965 4.115 ;
		LAYER M1 ;
		RECT 12.535 3.785 12.815 3.835 ;
		LAYER M1 ;
		RECT 11.77 3.59 12.815 3.785 ;
		LAYER M1 ;
		RECT 10.055 3.245 10.25 3.59 ;
		LAYER M1 ;
		RECT 10.055 3.24 11.765 3.245 ;
		LAYER M1 ;
		RECT 10.055 3.05 11.88 3.24 ;
		LAYER M1 ;
		RECT 10.055 2.21 10.25 3.05 ;
		LAYER M1 ;
		RECT 11.6 2.96 11.88 3.05 ;
		LAYER M1 ;
		RECT 12.09 2.21 12.28 3.59 ;
		LAYER M1 ;
		RECT 12.535 3.555 12.815 3.59 ;
		LAYER M1 ;
		RECT 7.955 1.77 9.105 1.96 ;
		LAYER M1 ;
		RECT 9.37 1.93 9.65 2.21 ;
		LAYER M1 ;
		RECT 9.96 2.005 10.25 2.21 ;
		LAYER M1 ;
		RECT 9.96 1.93 10.24 2.005 ;
		LAYER M1 ;
		RECT 7.28 1.45 7.56 1.765 ;
		LAYER M1 ;
		RECT 7.955 1.57 8.145 1.77 ;
		LAYER M1 ;
		RECT 7.87 1.29 8.15 1.57 ;
		LAYER M1 ;
		RECT 11.935 1.895 12.28 2.21 ;
		LAYER M1 ;
		RECT 11.935 1.24 12.215 1.895 ;
	END
END MMI_SFFCB
MACRO MMI_SFFHB
	CLASS CORE ;
	FOREIGN MMI_SFFHB 0 0 ;
	SIZE 17.98 BY 6.2 ;
	SYMMETRY X Y ;
	SITE CORE1 ;
	PIN d
		DIRECTION input ;
		USE SIGNAL ;
		PORT
			LAYER M1 ;
			RECT 3.84 2.6 4.22 2.98 ;
		END
		AntennaGateArea 0.3465 ;
	END d
	PIN GND
		DIRECTION inout ;
		USE GROUND ;
		PORT
			LAYER M1 ;
			RECT 0.75 0.42 1.03 2.105 ;
			LAYER M1 ;
			RECT 2.55 0.42 2.83 1.29 ;
			LAYER M1 ;
			RECT 6.67 0.42 6.95 1.315 ;
			LAYER M1 ;
			RECT 9.14 0.42 9.42 1.305 ;
			LAYER M1 ;
			RECT 10.7 0.42 10.98 1.5 ;
			LAYER M1 ;
			RECT 13.2 0.42 13.48 1.875 ;
			LAYER M1 ;
			RECT 15.35 0.42 15.63 1.87 ;
			LAYER M1 ;
			RECT 16.94 0.42 17.22 2.285 ;
			LAYER M1 ;
			RECT 0.0 -0.42 17.985 0.42 ;
		END
	END GND
	PIN q
		DIRECTION output ;
		USE SIGNAL ;
		PORT
			LAYER M1 ;
			RECT 17.53 3.8 17.81 5.27 ;
			LAYER M1 ;
			RECT 17.575 2.98 17.77 3.8 ;
			LAYER M1 ;
			RECT 17.48 2.6 17.86 2.98 ;
			LAYER M1 ;
			RECT 17.575 2.285 17.77 2.6 ;
			LAYER M1 ;
			RECT 17.53 1.585 17.81 2.285 ;
		END
		AntennaDiffArea 0.91245 ;
	END q
	PIN s_in
		DIRECTION input ;
		USE SIGNAL ;
		PORT
			LAYER M1 ;
			RECT 6.315 3.42 6.6 3.7 ;
			LAYER M1 ;
			RECT 6.405 2.98 6.6 3.42 ;
			LAYER M1 ;
			RECT 6.32 2.6 6.7 2.98 ;
			LAYER M1 ;
			RECT 6.405 2.26 6.6 2.6 ;
			LAYER M1 ;
			RECT 6.405 1.98 6.755 2.26 ;
		END
		AntennaGateArea 0.17325 ;
	END s_in
	PIN s_en
		DIRECTION input ;
		USE SIGNAL ;
		PORT
			LAYER M1 ;
			RECT 5.515 3.57 5.795 3.665 ;
			LAYER M1 ;
			RECT 5.515 3.375 5.96 3.57 ;
			LAYER M1 ;
			RECT 0.74 2.93 1.12 2.98 ;
			LAYER M1 ;
			RECT 0.7 2.65 1.12 2.93 ;
			LAYER M1 ;
			RECT 0.74 2.6 1.12 2.65 ;
			LAYER M1 ;
			RECT 5.77 2.26 5.96 3.375 ;
			LAYER M1 ;
			RECT 5.77 2.025 6.185 2.26 ;
			LAYER M1 ;
			RECT 5.905 1.98 6.185 2.025 ;
		END
		AntennaGateArea 0.9045 ;
	END s_en
	PIN VDD
		DIRECTION inout ;
		USE POWER ;
		PORT
			LAYER M1 ;
			RECT 0.0 5.78 17.985 6.62 ;
			LAYER M1 ;
			RECT 0.75 3.52 1.03 5.78 ;
			LAYER M1 ;
			RECT 2.55 4.25 2.83 5.78 ;
			LAYER M1 ;
			RECT 5.755 4.58 6.035 5.78 ;
			LAYER M1 ;
			RECT 8.36 4.995 8.64 5.78 ;
			LAYER M1 ;
			RECT 9.865 4.27 10.145 5.78 ;
			LAYER M1 ;
			RECT 12.825 4.22 13.105 5.78 ;
			LAYER M1 ;
			RECT 14.99 4.115 15.27 5.78 ;
			LAYER M1 ;
			RECT 15.72 3.8 16.0 5.78 ;
			LAYER M1 ;
			RECT 16.94 3.8 17.22 5.78 ;
		END
	END VDD
	PIN s_out
		DIRECTION output ;
		USE SIGNAL ;
		PORT
			LAYER M1 ;
			RECT 16.31 3.8 16.59 4.435 ;
			LAYER M1 ;
			RECT 16.4 2.98 16.59 3.8 ;
			LAYER M1 ;
			RECT 16.245 2.795 16.62 2.98 ;
			LAYER M1 ;
			RECT 16.025 2.6 16.62 2.795 ;
			LAYER M1 ;
			RECT 16.025 2.285 16.215 2.6 ;
			LAYER M1 ;
			RECT 15.94 1.65 16.22 2.285 ;
		END
		AntennaDiffArea 0.588675 ;
	END s_out
	PIN clk
		DIRECTION input ;
		USE CLOCK ;
		PORT
			LAYER M1 ;
			RECT 9.395 3.575 9.675 3.68 ;
			LAYER M1 ;
			RECT 9.035 3.4 9.675 3.575 ;
			LAYER M1 ;
			RECT 9.035 3.38 9.64 3.4 ;
			LAYER M1 ;
			RECT 9.035 2.98 9.225 3.38 ;
			LAYER M1 ;
			RECT 8.805 2.725 9.225 2.98 ;
			LAYER M1 ;
			RECT 8.805 2.6 9.505 2.725 ;
			LAYER M1 ;
			RECT 9.035 2.445 9.505 2.6 ;
			LAYER M1 ;
			RECT 9.035 1.785 9.225 2.445 ;
			LAYER M1 ;
			RECT 8.945 1.505 9.225 1.785 ;
		END
		AntennaGateArea 0.44625 ;
	END clk
	PIN hold
		DIRECTION input ;
		USE SIGNAL ;
		PORT
			LAYER M1 ;
			RECT 2.165 3.18 4.615 3.375 ;
			LAYER M1 ;
			RECT 2.165 2.98 2.36 3.18 ;
			LAYER M1 ;
			RECT 3.34 3.09 3.62 3.18 ;
			LAYER M1 ;
			RECT 1.98 2.925 2.36 2.98 ;
			LAYER M1 ;
			RECT 1.75 2.645 2.36 2.925 ;
			LAYER M1 ;
			RECT 1.98 2.6 2.36 2.645 ;
			LAYER M1 ;
			RECT 4.425 2.585 4.615 3.18 ;
			LAYER M1 ;
			RECT 4.425 2.39 5.095 2.585 ;
			LAYER M1 ;
			RECT 4.9 2.195 5.095 2.39 ;
			LAYER M1 ;
			RECT 4.9 1.915 5.18 2.195 ;
		END
		AntennaGateArea 0.51975 ;
	END hold
	OBS
		LAYER M1 ;
		RECT 0.16 3.52 0.44 4.22 ;
		LAYER M1 ;
		RECT 1.34 3.52 1.62 4.22 ;
		LAYER M1 ;
		RECT 1.955 4.04 2.235 5.315 ;
		LAYER M1 ;
		RECT 3.145 5.125 5.27 5.315 ;
		LAYER M1 ;
		RECT 3.145 4.04 3.435 5.125 ;
		LAYER M1 ;
		RECT 5.08 4.925 5.27 5.125 ;
		LAYER M1 ;
		RECT 1.955 3.845 3.435 4.04 ;
		LAYER M1 ;
		RECT 4.115 4.08 4.395 4.91 ;
		LAYER M1 ;
		RECT 5.08 4.255 5.36 4.925 ;
		LAYER M1 ;
		RECT 6.72 4.58 7.0 5.28 ;
		LAYER M1 ;
		RECT 7.31 4.58 7.59 5.28 ;
		LAYER M1 ;
		RECT 9.385 5.295 9.665 5.385 ;
		LAYER M1 ;
		RECT 8.955 5.28 9.665 5.295 ;
		LAYER M1 ;
		RECT 8.95 5.105 9.665 5.28 ;
		LAYER M1 ;
		RECT 8.95 4.78 9.23 5.105 ;
		LAYER M1 ;
		RECT 6.72 4.38 6.915 4.58 ;
		LAYER M1 ;
		RECT 5.565 4.19 6.915 4.38 ;
		LAYER M1 ;
		RECT 7.4 4.395 7.59 4.58 ;
		LAYER M1 ;
		RECT 8.415 4.59 9.23 4.78 ;
		LAYER M1 ;
		RECT 7.4 4.205 8.13 4.395 ;
		LAYER M1 ;
		RECT 4.115 4.055 4.4 4.08 ;
		LAYER M1 ;
		RECT 5.565 4.055 5.76 4.19 ;
		LAYER M1 ;
		RECT 4.115 3.865 5.76 4.055 ;
		LAYER M1 ;
		RECT 4.115 3.85 4.395 3.865 ;
		LAYER M1 ;
		RECT 0.245 2.105 0.435 3.52 ;
		LAYER M1 ;
		RECT 1.345 2.155 1.535 3.52 ;
		LAYER M1 ;
		RECT 4.91 2.98 5.105 3.865 ;
		LAYER M1 ;
		RECT 6.885 3.71 7.165 3.99 ;
		LAYER M1 ;
		RECT 7.46 3.725 7.74 4.005 ;
		LAYER M1 ;
		RECT 4.91 2.79 5.57 2.98 ;
		LAYER M1 ;
		RECT 3.355 2.155 3.635 2.195 ;
		LAYER M1 ;
		RECT 4.32 2.155 4.6 2.19 ;
		LAYER M1 ;
		RECT 1.345 2.105 4.6 2.155 ;
		LAYER M1 ;
		RECT 0.16 1.79 0.44 2.105 ;
		LAYER M1 ;
		RECT 0.245 0.905 0.435 1.79 ;
		LAYER M1 ;
		RECT 0.245 0.625 0.525 0.905 ;
		LAYER M1 ;
		RECT 1.34 1.96 4.6 2.105 ;
		LAYER M1 ;
		RECT 1.34 1.79 1.62 1.96 ;
		LAYER M1 ;
		RECT 3.355 1.915 3.635 1.96 ;
		LAYER M1 ;
		RECT 4.32 1.91 4.6 1.96 ;
		LAYER M1 ;
		RECT 5.38 1.71 5.57 2.79 ;
		LAYER M1 ;
		RECT 6.975 2.81 7.165 3.71 ;
		LAYER M1 ;
		RECT 6.975 2.62 7.325 2.81 ;
		LAYER M1 ;
		RECT 7.045 2.445 7.325 2.62 ;
		LAYER M1 ;
		RECT 7.54 2.155 7.735 3.725 ;
		LAYER M1 ;
		RECT 7.94 2.725 8.13 4.205 ;
		LAYER M1 ;
		RECT 7.935 2.445 8.215 2.725 ;
		LAYER M1 ;
		RECT 7.54 1.875 7.82 2.155 ;
		LAYER M1 ;
		RECT 1.945 1.7 2.225 1.71 ;
		LAYER M1 ;
		RECT 3.15 1.7 3.43 1.71 ;
		LAYER M1 ;
		RECT 1.945 1.51 3.435 1.7 ;
		LAYER M1 ;
		RECT 1.945 1.41 2.23 1.51 ;
		LAYER M1 ;
		RECT 1.945 1.01 2.225 1.41 ;
		LAYER M1 ;
		RECT 3.15 1.01 3.435 1.51 ;
		LAYER M1 ;
		RECT 4.12 1.66 7.34 1.71 ;
		LAYER M1 ;
		RECT 8.02 1.66 8.215 2.445 ;
		LAYER M1 ;
		RECT 8.415 2.185 8.605 4.59 ;
		LAYER M1 ;
		RECT 8.95 4.58 9.23 4.59 ;
		LAYER M1 ;
		RECT 10.46 4.245 10.74 4.945 ;
		LAYER M1 ;
		RECT 11.05 4.245 11.33 4.945 ;
		LAYER M1 ;
		RECT 10.46 4.07 10.73 4.245 ;
		LAYER M1 ;
		RECT 8.87 4.055 10.73 4.07 ;
		LAYER M1 ;
		RECT 8.825 3.885 10.73 4.055 ;
		LAYER M1 ;
		RECT 8.825 3.88 10.735 3.885 ;
		LAYER M1 ;
		RECT 8.825 3.775 9.105 3.88 ;
		LAYER M1 ;
		RECT 9.915 3.4 10.325 3.68 ;
		LAYER M1 ;
		RECT 8.415 1.995 8.745 2.185 ;
		LAYER M1 ;
		RECT 4.12 1.52 7.64 1.66 ;
		LAYER M1 ;
		RECT 4.12 1.01 4.4 1.52 ;
		LAYER M1 ;
		RECT 4.71 1.28 4.99 1.285 ;
		LAYER M1 ;
		RECT 3.245 0.81 3.435 1.01 ;
		LAYER M1 ;
		RECT 4.7 1.005 4.99 1.28 ;
		LAYER M1 ;
		RECT 4.7 0.81 4.895 1.005 ;
		LAYER M1 ;
		RECT 5.67 1.0 5.95 1.52 ;
		LAYER M1 ;
		RECT 7.15 1.38 7.64 1.52 ;
		LAYER M1 ;
		RECT 7.95 1.38 8.23 1.66 ;
		LAYER M1 ;
		RECT 3.245 0.62 4.895 0.81 ;
		LAYER M1 ;
		RECT 8.55 1.305 8.745 1.995 ;
		LAYER M1 ;
		RECT 9.915 2.41 10.105 3.4 ;
		LAYER M1 ;
		RECT 9.825 2.075 10.105 2.41 ;
		LAYER M1 ;
		RECT 9.825 1.5 10.02 2.075 ;
		LAYER M1 ;
		RECT 10.54 1.995 10.735 3.88 ;
		LAYER M1 ;
		RECT 11.135 3.31 11.33 4.245 ;
		LAYER M1 ;
		RECT 12.235 4.22 12.515 4.92 ;
		LAYER M1 ;
		RECT 13.415 4.815 13.695 4.92 ;
		LAYER M1 ;
		RECT 13.415 4.62 14.735 4.815 ;
		LAYER M1 ;
		RECT 13.415 4.22 13.695 4.62 ;
		LAYER M1 ;
		RECT 11.64 3.78 11.92 3.885 ;
		LAYER M1 ;
		RECT 12.235 3.78 12.43 4.22 ;
		LAYER M1 ;
		RECT 13.42 4.015 13.61 4.22 ;
		LAYER M1 ;
		RECT 14.01 4.115 14.29 4.395 ;
		LAYER M1 ;
		RECT 11.64 3.605 12.43 3.78 ;
		LAYER M1 ;
		RECT 12.63 3.825 13.61 4.015 ;
		LAYER M1 ;
		RECT 12.63 3.735 12.91 3.825 ;
		LAYER M1 ;
		RECT 11.69 3.585 12.43 3.605 ;
		LAYER M1 ;
		RECT 11.64 3.31 11.92 3.315 ;
		LAYER M1 ;
		RECT 11.135 3.115 11.925 3.31 ;
		LAYER M1 ;
		RECT 11.64 3.035 11.925 3.115 ;
		LAYER M1 ;
		RECT 10.505 1.975 10.785 1.995 ;
		LAYER M1 ;
		RECT 10.505 1.785 11.525 1.975 ;
		LAYER M1 ;
		RECT 10.505 1.715 10.785 1.785 ;
		LAYER M1 ;
		RECT 11.33 1.535 11.525 1.785 ;
		LAYER M1 ;
		RECT 11.73 1.93 11.925 3.035 ;
		LAYER M1 ;
		RECT 12.235 2.68 12.43 3.585 ;
		LAYER M1 ;
		RECT 12.63 3.22 12.91 3.315 ;
		LAYER M1 ;
		RECT 14.035 3.22 14.23 4.115 ;
		LAYER M1 ;
		RECT 14.545 3.595 14.735 4.62 ;
		LAYER M1 ;
		RECT 14.545 3.4 16.195 3.595 ;
		LAYER M1 ;
		RECT 12.63 3.18 14.23 3.22 ;
		LAYER M1 ;
		RECT 14.875 3.31 15.16 3.4 ;
		LAYER M1 ;
		RECT 15.915 3.315 16.195 3.4 ;
		LAYER M1 ;
		RECT 12.63 3.035 14.595 3.18 ;
		LAYER M1 ;
		RECT 12.68 3.025 14.595 3.035 ;
		LAYER M1 ;
		RECT 14.035 2.985 14.595 3.025 ;
		LAYER M1 ;
		RECT 12.235 2.49 12.745 2.68 ;
		LAYER M1 ;
		RECT 11.73 1.74 12.16 1.93 ;
		LAYER M1 ;
		RECT 7.655 1.15 7.935 1.16 ;
		LAYER M1 ;
		RECT 8.55 1.15 8.83 1.305 ;
		LAYER M1 ;
		RECT 7.655 0.99 8.83 1.15 ;
		LAYER M1 ;
		RECT 7.655 0.955 8.745 0.99 ;
		LAYER M1 ;
		RECT 7.655 0.88 7.935 0.955 ;
		LAYER M1 ;
		RECT 9.74 1.22 10.02 1.5 ;
		LAYER M1 ;
		RECT 11.33 1.22 11.61 1.535 ;
		LAYER M1 ;
		RECT 11.965 1.505 12.16 1.74 ;
		LAYER M1 ;
		RECT 12.555 1.875 12.745 2.49 ;
		LAYER M1 ;
		RECT 14.4 2.355 14.595 2.985 ;
		LAYER M1 ;
		RECT 12.955 2.27 13.235 2.355 ;
		LAYER M1 ;
		RECT 12.955 2.08 13.985 2.27 ;
		LAYER M1 ;
		RECT 12.955 2.075 13.235 2.08 ;
		LAYER M1 ;
		RECT 13.795 1.875 13.985 2.08 ;
		LAYER M1 ;
		RECT 14.215 2.075 14.595 2.355 ;
		LAYER M1 ;
		RECT 12.555 1.665 12.84 1.875 ;
		LAYER M1 ;
		RECT 12.56 1.56 12.84 1.665 ;
		LAYER M1 ;
		RECT 11.96 1.225 12.24 1.505 ;
		LAYER M1 ;
		RECT 13.79 1.425 14.07 1.875 ;
		LAYER M1 ;
		RECT 14.4 1.87 14.595 2.075 ;
		LAYER M1 ;
		RECT 14.875 2.66 15.065 3.31 ;
		LAYER M1 ;
		RECT 14.875 2.38 15.155 2.66 ;
		LAYER M1 ;
		RECT 14.39 1.59 14.67 1.87 ;
		LAYER M1 ;
		RECT 13.875 1.385 14.07 1.425 ;
		LAYER M1 ;
		RECT 14.875 1.385 15.065 2.38 ;
		LAYER M1 ;
		RECT 13.875 1.195 15.065 1.385 ;
	END
END MMI_SFFHB
MACRO MMI_SFFMB
	CLASS CORE ;
	FOREIGN MMI_SFFMB 0 0 ;
	SIZE 16.74 BY 6.2 ;
	SYMMETRY X Y ;
	SITE CORE1 ;
	PIN d0
		DIRECTION input ;
		USE SIGNAL ;
		PORT
			LAYER M1 ;
			RECT 3.84 2.885 4.22 2.98 ;
			LAYER M1 ;
			RECT 2.565 2.755 2.845 2.84 ;
			LAYER M1 ;
			RECT 3.84 2.755 4.305 2.885 ;
			LAYER M1 ;
			RECT 2.565 2.605 4.305 2.755 ;
			LAYER M1 ;
			RECT 2.565 2.565 4.22 2.605 ;
			LAYER M1 ;
			RECT 2.565 2.56 2.845 2.565 ;
		END
		AntennaGateArea 0.3465 ;
	END d0
	PIN sel
		DIRECTION input ;
		USE SIGNAL ;
		PORT
			LAYER M1 ;
			RECT 1.98 2.93 2.36 2.98 ;
			LAYER M1 ;
			RECT 1.755 2.65 2.36 2.93 ;
			LAYER M1 ;
			RECT 1.98 2.6 2.36 2.65 ;
		END
		AntennaGateArea 0.51975 ;
	END sel
	PIN GND
		DIRECTION inout ;
		USE GROUND ;
		PORT
			LAYER M1 ;
			RECT 0.75 0.42 1.03 1.82 ;
			LAYER M1 ;
			RECT 3.505 0.42 3.785 1.25 ;
			LAYER M1 ;
			RECT 6.07 0.42 6.35 1.575 ;
			LAYER M1 ;
			RECT 8.265 0.42 8.545 0.835 ;
			LAYER M1 ;
			RECT 10.175 0.42 10.455 1.335 ;
			LAYER M1 ;
			RECT 11.995 0.42 12.275 1.54 ;
			LAYER M1 ;
			RECT 14.135 0.42 14.415 1.375 ;
			LAYER M1 ;
			RECT 15.715 0.42 15.995 2.39 ;
			LAYER M1 ;
			RECT 0.0 -0.42 16.745 0.42 ;
		END
	END GND
	PIN q
		DIRECTION output ;
		USE SIGNAL ;
		PORT
			LAYER M1 ;
			RECT 16.305 3.845 16.585 5.315 ;
			LAYER M1 ;
			RECT 16.395 2.98 16.585 3.845 ;
			LAYER M1 ;
			RECT 16.24 2.6 16.62 2.98 ;
			LAYER M1 ;
			RECT 16.395 2.39 16.585 2.6 ;
			LAYER M1 ;
			RECT 16.305 1.69 16.585 2.39 ;
		END
		AntennaDiffArea 0.91245 ;
	END q
	PIN s_in
		DIRECTION input ;
		USE SIGNAL ;
		PORT
			LAYER M1 ;
			RECT 6.32 2.915 6.7 2.98 ;
			LAYER M1 ;
			RECT 6.32 2.635 6.735 2.915 ;
			LAYER M1 ;
			RECT 6.32 2.6 6.7 2.635 ;
		END
		AntennaGateArea 0.17325 ;
	END s_in
	PIN s_en
		DIRECTION input ;
		USE SIGNAL ;
		PORT
			LAYER M1 ;
			RECT 0.74 2.93 1.12 2.98 ;
			LAYER M1 ;
			RECT 0.64 2.65 1.12 2.93 ;
			LAYER M1 ;
			RECT 0.74 2.6 1.12 2.65 ;
		END
		AntennaGateArea 0.9045 ;
	END s_en
	PIN d1
		DIRECTION input ;
		USE SIGNAL ;
		PORT
			LAYER M1 ;
			RECT 5.08 2.6 5.46 2.98 ;
			LAYER M1 ;
			RECT 5.175 2.565 5.455 2.6 ;
		END
		AntennaGateArea 0.3465 ;
	END d1
	PIN VDD
		DIRECTION inout ;
		USE POWER ;
		PORT
			LAYER M1 ;
			RECT 0.0 5.78 16.745 6.62 ;
			LAYER M1 ;
			RECT 0.75 4.115 1.03 5.78 ;
			LAYER M1 ;
			RECT 2.55 4.065 2.83 5.78 ;
			LAYER M1 ;
			RECT 6.345 4.115 6.625 5.78 ;
			LAYER M1 ;
			RECT 9.09 3.565 9.37 5.78 ;
			LAYER M1 ;
			RECT 10.345 4.19 10.625 5.78 ;
			LAYER M1 ;
			RECT 12.87 4.065 13.15 5.78 ;
			LAYER M1 ;
			RECT 14.465 5.03 14.745 5.78 ;
			LAYER M1 ;
			RECT 15.715 3.845 15.995 5.78 ;
		END
	END VDD
	PIN s_out
		DIRECTION output ;
		USE SIGNAL ;
		PORT
			LAYER M1 ;
			RECT 15.075 4.68 15.355 5.315 ;
			LAYER M1 ;
			RECT 15.075 2.98 15.27 4.68 ;
			LAYER M1 ;
			RECT 14.8 2.6 15.38 2.98 ;
			LAYER M1 ;
			RECT 14.8 2.39 14.99 2.6 ;
			LAYER M1 ;
			RECT 14.705 1.755 14.99 2.39 ;
		END
		AntennaDiffArea 0.588675 ;
	END s_out
	PIN clk
		DIRECTION input ;
		USE CLOCK ;
		PORT
			LAYER M1 ;
			RECT 7.56 2.6 7.94 2.98 ;
		END
		AntennaGateArea 0.44625 ;
	END clk
	OBS
		LAYER M1 ;
		RECT 0.16 4.115 0.44 4.815 ;
		LAYER M1 ;
		RECT 1.34 4.115 1.62 4.815 ;
		LAYER M1 ;
		RECT 0.245 1.82 0.435 4.115 ;
		LAYER M1 ;
		RECT 1.36 3.37 1.55 4.115 ;
		LAYER M1 ;
		RECT 1.955 3.845 2.235 5.315 ;
		LAYER M1 ;
		RECT 3.145 5.31 4.895 5.34 ;
		LAYER M1 ;
		RECT 3.145 5.145 4.99 5.31 ;
		LAYER M1 ;
		RECT 2.04 3.76 2.235 3.845 ;
		LAYER M1 ;
		RECT 3.145 3.845 3.425 5.145 ;
		LAYER M1 ;
		RECT 4.7 5.055 4.99 5.145 ;
		LAYER M1 ;
		RECT 4.12 3.845 4.4 4.905 ;
		LAYER M1 ;
		RECT 4.71 4.25 4.99 5.055 ;
		LAYER M1 ;
		RECT 5.67 4.265 5.95 5.315 ;
		LAYER M1 ;
		RECT 3.145 3.76 3.34 3.845 ;
		LAYER M1 ;
		RECT 2.04 3.57 3.34 3.76 ;
		LAYER M1 ;
		RECT 4.205 3.765 4.4 3.845 ;
		LAYER M1 ;
		RECT 5.665 3.765 5.95 4.265 ;
		LAYER M1 ;
		RECT 8.49 4.96 8.77 5.06 ;
		LAYER M1 ;
		RECT 7.31 4.115 7.59 4.815 ;
		LAYER M1 ;
		RECT 7.9 4.115 8.18 4.815 ;
		LAYER M1 ;
		RECT 8.49 4.78 8.775 4.96 ;
		LAYER M1 ;
		RECT 8.58 4.265 8.775 4.78 ;
		LAYER M1 ;
		RECT 7.315 3.765 7.505 4.115 ;
		LAYER M1 ;
		RECT 4.205 3.57 7.505 3.765 ;
		LAYER M1 ;
		RECT 1.36 3.18 4.88 3.37 ;
		LAYER M1 ;
		RECT 1.36 1.82 1.55 3.18 ;
		LAYER M1 ;
		RECT 4.6 3.09 4.88 3.18 ;
		LAYER M1 ;
		RECT 5.665 2.36 5.86 3.57 ;
		LAYER M1 ;
		RECT 7.9 3.37 8.095 4.115 ;
		LAYER M1 ;
		RECT 8.5 3.565 8.78 4.265 ;
		LAYER M1 ;
		RECT 10.935 4.19 11.215 4.89 ;
		LAYER M1 ;
		RECT 11.525 4.19 11.815 4.89 ;
		LAYER M1 ;
		RECT 10.54 3.845 10.82 3.935 ;
		LAYER M1 ;
		RECT 10.09 3.655 10.82 3.845 ;
		LAYER M1 ;
		RECT 10.09 3.565 10.375 3.655 ;
		LAYER M1 ;
		RECT 7.17 3.18 8.095 3.37 ;
		LAYER M1 ;
		RECT 2.03 2.17 5.86 2.36 ;
		LAYER M1 ;
		RECT 2.03 1.955 2.225 2.17 ;
		LAYER M1 ;
		RECT 0.16 1.505 0.44 1.82 ;
		LAYER M1 ;
		RECT 0.245 0.905 0.435 1.505 ;
		LAYER M1 ;
		RECT 0.245 0.625 0.545 0.905 ;
		LAYER M1 ;
		RECT 1.34 1.505 1.62 1.82 ;
		LAYER M1 ;
		RECT 1.36 0.955 1.55 1.505 ;
		LAYER M1 ;
		RECT 1.955 1.255 2.235 1.955 ;
		LAYER M1 ;
		RECT 3.0 1.78 4.285 1.97 ;
		LAYER M1 ;
		RECT 3.0 1.575 3.195 1.78 ;
		LAYER M1 ;
		RECT 2.915 1.295 3.195 1.575 ;
		LAYER M1 ;
		RECT 3.0 1.29 3.195 1.295 ;
		LAYER M1 ;
		RECT 4.095 1.67 4.285 1.78 ;
		LAYER M1 ;
		RECT 5.17 1.67 5.365 2.17 ;
		LAYER M1 ;
		RECT 5.665 1.97 5.86 2.17 ;
		LAYER M1 ;
		RECT 7.17 1.975 7.36 3.18 ;
		LAYER M1 ;
		RECT 8.58 2.365 8.775 3.565 ;
		LAYER M1 ;
		RECT 8.37 2.17 8.775 2.365 ;
		LAYER M1 ;
		RECT 5.665 1.78 6.97 1.97 ;
		LAYER M1 ;
		RECT 7.17 1.78 7.6 1.975 ;
		LAYER M1 ;
		RECT 1.36 0.765 2.055 0.955 ;
		LAYER M1 ;
		RECT 1.775 0.675 2.055 0.765 ;
		LAYER M1 ;
		RECT 4.095 0.97 4.375 1.67 ;
		LAYER M1 ;
		RECT 5.065 1.265 5.365 1.67 ;
		LAYER M1 ;
		RECT 5.065 0.97 5.345 1.265 ;
		LAYER M1 ;
		RECT 6.78 1.31 6.97 1.78 ;
		LAYER M1 ;
		RECT 7.41 1.31 7.6 1.78 ;
		LAYER M1 ;
		RECT 7.81 1.84 8.09 1.925 ;
		LAYER M1 ;
		RECT 8.37 1.84 8.565 2.17 ;
		LAYER M1 ;
		RECT 7.81 1.645 8.565 1.84 ;
		LAYER M1 ;
		RECT 10.09 1.815 10.28 3.565 ;
		LAYER M1 ;
		RECT 11.02 2.905 11.21 4.19 ;
		LAYER M1 ;
		RECT 11.625 3.865 11.815 4.19 ;
		LAYER M1 ;
		RECT 12.28 4.065 12.56 4.765 ;
		LAYER M1 ;
		RECT 13.445 4.83 13.725 5.125 ;
		LAYER M1 ;
		RECT 13.44 4.64 14.55 4.83 ;
		LAYER M1 ;
		RECT 11.625 3.67 12.095 3.865 ;
		LAYER M1 ;
		RECT 11.415 3.3 11.695 3.47 ;
		LAYER M1 ;
		RECT 11.905 3.425 12.095 3.67 ;
		LAYER M1 ;
		RECT 12.37 3.82 12.56 4.065 ;
		LAYER M1 ;
		RECT 13.44 3.82 13.635 4.64 ;
		LAYER M1 ;
		RECT 12.37 3.63 13.635 3.82 ;
		LAYER M1 ;
		RECT 13.875 4.055 14.155 4.335 ;
		LAYER M1 ;
		RECT 12.48 3.425 12.76 3.43 ;
		LAYER M1 ;
		RECT 13.875 3.425 14.07 4.055 ;
		LAYER M1 ;
		RECT 11.415 3.19 11.7 3.3 ;
		LAYER M1 ;
		RECT 11.905 3.23 14.07 3.425 ;
		LAYER M1 ;
		RECT 14.355 3.635 14.55 4.64 ;
		LAYER M1 ;
		RECT 14.355 3.355 14.67 3.635 ;
		LAYER M1 ;
		RECT 10.78 2.9 11.21 2.905 ;
		LAYER M1 ;
		RECT 10.5 2.625 11.21 2.9 ;
		LAYER M1 ;
		RECT 10.5 2.62 11.145 2.625 ;
		LAYER M1 ;
		RECT 8.25 1.425 8.565 1.645 ;
		LAYER M1 ;
		RECT 9.255 1.625 10.755 1.815 ;
		LAYER M1 ;
		RECT 9.255 1.33 9.45 1.625 ;
		LAYER M1 ;
		RECT 10.475 1.535 10.755 1.625 ;
		LAYER M1 ;
		RECT 10.955 1.335 11.145 2.62 ;
		LAYER M1 ;
		RECT 11.505 2.45 11.7 3.19 ;
		LAYER M1 ;
		RECT 12.48 3.15 12.76 3.23 ;
		LAYER M1 ;
		RECT 12.775 2.45 13.055 2.49 ;
		LAYER M1 ;
		RECT 11.505 2.255 13.055 2.45 ;
		LAYER M1 ;
		RECT 12.775 2.21 13.055 2.255 ;
		LAYER M1 ;
		RECT 12.19 1.935 12.47 2.02 ;
		LAYER M1 ;
		RECT 13.26 1.935 13.45 3.23 ;
		LAYER M1 ;
		RECT 14.355 2.815 14.55 3.355 ;
		LAYER M1 ;
		RECT 6.78 1.04 7.1 1.31 ;
		LAYER M1 ;
		RECT 6.82 1.03 7.1 1.04 ;
		LAYER M1 ;
		RECT 7.41 1.225 7.69 1.31 ;
		LAYER M1 ;
		RECT 9.17 1.225 9.45 1.33 ;
		LAYER M1 ;
		RECT 7.41 1.035 9.45 1.225 ;
		LAYER M1 ;
		RECT 7.41 1.03 7.69 1.035 ;
		LAYER M1 ;
		RECT 10.765 1.02 11.145 1.335 ;
		LAYER M1 ;
		RECT 11.495 1.745 13.45 1.935 ;
		LAYER M1 ;
		RECT 11.495 1.33 11.685 1.745 ;
		LAYER M1 ;
		RECT 12.19 1.74 12.47 1.745 ;
		LAYER M1 ;
		RECT 11.395 1.075 11.685 1.33 ;
		LAYER M1 ;
		RECT 11.395 1.05 11.675 1.075 ;
		LAYER M1 ;
		RECT 10.955 1.015 11.145 1.02 ;
		LAYER M1 ;
		RECT 12.585 1.09 12.865 1.54 ;
		LAYER M1 ;
		RECT 13.26 1.375 13.45 1.745 ;
		LAYER M1 ;
		RECT 13.705 2.625 14.55 2.815 ;
		LAYER M1 ;
		RECT 13.705 1.92 13.9 2.625 ;
		LAYER M1 ;
		RECT 13.705 1.635 14.225 1.92 ;
		LAYER M1 ;
		RECT 13.175 1.095 13.455 1.375 ;
		LAYER M1 ;
		RECT 12.675 0.81 12.865 1.09 ;
		LAYER M1 ;
		RECT 13.705 0.81 13.9 1.635 ;
		LAYER M1 ;
		RECT 12.675 0.62 13.9 0.81 ;
	END
END MMI_SFFMB
MACRO MMI_SFFPB
	CLASS CORE ;
	FOREIGN MMI_SFFPB 0 0 ;
	SIZE 13.64 BY 6.2 ;
	SYMMETRY X Y ;
	SITE CORE1 ;
	PIN d
		DIRECTION input ;
		USE SIGNAL ;
		PORT
			LAYER M1 ;
			RECT 1.5 2.88 1.78 2.9 ;
			LAYER M1 ;
			RECT 1.98 2.88 2.36 2.98 ;
			LAYER M1 ;
			RECT 1.5 2.685 2.36 2.88 ;
			LAYER M1 ;
			RECT 1.5 2.62 1.78 2.685 ;
			LAYER M1 ;
			RECT 1.98 2.6 2.36 2.685 ;
		END
		AntennaGateArea 0.3465 ;
	END d
	PIN GND
		DIRECTION inout ;
		USE GROUND ;
		PORT
			LAYER M1 ;
			RECT 0.75 0.42 1.03 2.28 ;
			LAYER M1 ;
			RECT 6.625 1.72 7.205 2.42 ;
			LAYER M1 ;
			RECT 2.3 0.42 2.58 1.585 ;
			LAYER M1 ;
			RECT 3.865 0.42 4.145 1.315 ;
			LAYER M1 ;
			RECT 6.625 0.42 6.91 1.72 ;
			LAYER M1 ;
			RECT 8.57 0.42 8.85 1.43 ;
			LAYER M1 ;
			RECT 11.26 0.42 11.54 1.33 ;
			LAYER M1 ;
			RECT 12.41 0.42 12.69 2.39 ;
			LAYER M1 ;
			RECT 0.0 -0.42 13.645 0.42 ;
		END
	END GND
	PIN q
		DIRECTION output ;
		USE SIGNAL ;
		PORT
			LAYER M1 ;
			RECT 13.0 3.68 13.28 5.15 ;
			LAYER M1 ;
			RECT 13.075 2.98 13.27 3.68 ;
			LAYER M1 ;
			RECT 13.075 2.6 13.52 2.98 ;
			LAYER M1 ;
			RECT 13.075 2.39 13.27 2.6 ;
			LAYER M1 ;
			RECT 13.0 1.69 13.28 2.39 ;
		END
		AntennaDiffArea 0.91245 ;
	END q
	PIN s_in
		DIRECTION input ;
		USE SIGNAL ;
		PORT
			LAYER M1 ;
			RECT 3.22 2.6 3.6 2.98 ;
		END
		AntennaGateArea 0.17325 ;
	END s_in
	PIN s_en
		DIRECTION input ;
		USE SIGNAL ;
		PORT
			LAYER M1 ;
			RECT 0.74 2.93 1.12 2.98 ;
			LAYER M1 ;
			RECT 0.555 2.65 1.12 2.93 ;
			LAYER M1 ;
			RECT 0.74 2.6 1.12 2.65 ;
		END
		AntennaGateArea 0.51525 ;
	END s_en
	PIN VDD
		DIRECTION inout ;
		USE POWER ;
		PORT
			LAYER M1 ;
			RECT 0.0 5.78 13.645 6.62 ;
			LAYER M1 ;
			RECT 0.795 4.11 1.075 5.78 ;
			LAYER M1 ;
			RECT 2.755 4.115 3.035 5.78 ;
			LAYER M1 ;
			RECT 5.575 3.96 5.855 5.78 ;
			LAYER M1 ;
			RECT 6.775 3.675 7.055 5.78 ;
			LAYER M1 ;
			RECT 10.415 3.9 10.695 5.78 ;
			LAYER M1 ;
			RECT 12.41 3.68 12.69 5.78 ;
		END
	END VDD
	PIN setb
		DIRECTION input ;
		USE SIGNAL ;
		PORT
			LAYER M1 ;
			RECT 6.73 2.88 7.01 2.93 ;
			LAYER M1 ;
			RECT 6.73 2.815 7.84 2.88 ;
			LAYER M1 ;
			RECT 6.73 2.685 8.065 2.815 ;
			LAYER M1 ;
			RECT 6.73 2.65 7.01 2.685 ;
			LAYER M1 ;
			RECT 7.645 2.535 8.065 2.685 ;
			LAYER M1 ;
			RECT 7.645 2.36 7.94 2.535 ;
			LAYER M1 ;
			RECT 7.565 1.98 7.94 2.36 ;
		END
		AntennaGateArea 0.4575 ;
	END setb
	PIN clk
		DIRECTION input ;
		USE CLOCK ;
		PORT
			LAYER M1 ;
			RECT 4.46 2.93 4.84 2.98 ;
			LAYER M1 ;
			RECT 4.15 2.925 4.84 2.93 ;
			LAYER M1 ;
			RECT 4.14 2.645 4.84 2.925 ;
			LAYER M1 ;
			RECT 4.46 2.6 4.84 2.645 ;
		END
		AntennaGateArea 0.44625 ;
	END clk
	OBS
		LAYER M1 ;
		RECT 0.16 4.35 0.44 5.05 ;
		LAYER M1 ;
		RECT 0.15 4.115 0.44 4.35 ;
		LAYER M1 ;
		RECT 0.15 3.525 0.345 4.115 ;
		LAYER M1 ;
		RECT 1.755 4.11 2.035 5.58 ;
		LAYER M1 ;
		RECT 4.77 5.365 5.05 5.49 ;
		LAYER M1 ;
		RECT 3.445 5.175 5.295 5.365 ;
		LAYER M1 ;
		RECT 3.445 4.815 3.635 5.175 ;
		LAYER M1 ;
		RECT 3.345 4.615 3.635 4.815 ;
		LAYER M1 ;
		RECT 3.345 4.115 3.625 4.615 ;
		LAYER M1 ;
		RECT 3.945 4.375 4.225 4.835 ;
		LAYER M1 ;
		RECT 3.94 4.135 4.225 4.375 ;
		LAYER M1 ;
		RECT 4.535 4.135 4.815 4.835 ;
		LAYER M1 ;
		RECT 1.84 3.915 2.035 4.11 ;
		LAYER M1 ;
		RECT 3.94 3.915 4.13 4.135 ;
		LAYER M1 ;
		RECT 1.84 3.725 4.13 3.915 ;
		LAYER M1 ;
		RECT 0.15 3.335 2.27 3.525 ;
		LAYER M1 ;
		RECT 0.15 2.28 0.345 3.335 ;
		LAYER M1 ;
		RECT 1.99 3.245 2.27 3.335 ;
		LAYER M1 ;
		RECT 0.15 2.0 0.44 2.28 ;
		LAYER M1 ;
		RECT 0.16 1.845 0.44 2.0 ;
		LAYER M1 ;
		RECT 2.58 1.985 2.775 3.725 ;
		LAYER M1 ;
		RECT 4.625 3.37 4.815 4.135 ;
		LAYER M1 ;
		RECT 5.105 3.76 5.295 5.175 ;
		LAYER M1 ;
		RECT 6.185 4.885 6.465 5.165 ;
		LAYER M1 ;
		RECT 6.23 4.375 6.425 4.885 ;
		LAYER M1 ;
		RECT 5.105 3.57 5.765 3.76 ;
		LAYER M1 ;
		RECT 6.185 3.675 6.465 4.375 ;
		LAYER M1 ;
		RECT 7.465 5.01 9.245 5.205 ;
		LAYER M1 ;
		RECT 7.465 4.61 7.66 5.01 ;
		LAYER M1 ;
		RECT 7.38 3.675 7.66 4.61 ;
		LAYER M1 ;
		RECT 7.98 4.375 8.26 4.635 ;
		LAYER M1 ;
		RECT 7.975 3.935 8.26 4.375 ;
		LAYER M1 ;
		RECT 8.57 3.935 8.85 4.635 ;
		LAYER M1 ;
		RECT 4.625 3.18 5.31 3.37 ;
		LAYER M1 ;
		RECT 5.12 2.735 5.31 3.18 ;
		LAYER M1 ;
		RECT 5.095 2.455 5.375 2.735 ;
		LAYER M1 ;
		RECT 1.435 1.98 2.775 1.985 ;
		LAYER M1 ;
		RECT 1.435 1.79 4.78 1.98 ;
		LAYER M1 ;
		RECT 5.12 1.91 5.31 2.455 ;
		LAYER M1 ;
		RECT 1.435 1.585 1.625 1.79 ;
		LAYER M1 ;
		RECT 2.58 1.785 4.78 1.79 ;
		LAYER M1 ;
		RECT 1.34 1.145 1.625 1.585 ;
		LAYER M1 ;
		RECT 1.34 0.885 1.62 1.145 ;
		LAYER M1 ;
		RECT 2.89 1.315 3.085 1.785 ;
		LAYER M1 ;
		RECT 4.5 1.63 4.78 1.785 ;
		LAYER M1 ;
		RECT 5.09 1.63 5.37 1.91 ;
		LAYER M1 ;
		RECT 4.895 1.315 5.175 1.32 ;
		LAYER M1 ;
		RECT 5.575 1.315 5.765 3.57 ;
		LAYER M1 ;
		RECT 6.23 3.325 6.425 3.675 ;
		LAYER M1 ;
		RECT 7.975 3.325 8.165 3.935 ;
		LAYER M1 ;
		RECT 6.05 3.13 8.455 3.325 ;
		LAYER M1 ;
		RECT 6.05 2.42 6.245 3.13 ;
		LAYER M1 ;
		RECT 5.965 1.72 6.245 2.42 ;
		LAYER M1 ;
		RECT 8.265 2.35 8.455 3.13 ;
		LAYER M1 ;
		RECT 8.655 2.81 8.85 3.935 ;
		LAYER M1 ;
		RECT 9.055 3.305 9.245 5.01 ;
		LAYER M1 ;
		RECT 9.445 3.705 9.725 4.765 ;
		LAYER M1 ;
		RECT 11.76 4.715 12.04 4.805 ;
		LAYER M1 ;
		RECT 10.895 4.525 12.04 4.715 ;
		LAYER M1 ;
		RECT 9.53 3.695 9.725 3.705 ;
		LAYER M1 ;
		RECT 10.895 3.695 11.085 4.525 ;
		LAYER M1 ;
		RECT 11.285 3.705 11.565 3.985 ;
		LAYER M1 ;
		RECT 9.53 3.505 11.085 3.695 ;
		LAYER M1 ;
		RECT 9.055 3.115 10.525 3.305 ;
		LAYER M1 ;
		RECT 10.245 3.025 10.525 3.115 ;
		LAYER M1 ;
		RECT 9.675 2.81 9.955 2.825 ;
		LAYER M1 ;
		RECT 8.655 2.62 9.995 2.81 ;
		LAYER M1 ;
		RECT 9.675 2.545 9.995 2.62 ;
		LAYER M1 ;
		RECT 8.265 2.16 9.39 2.35 ;
		LAYER M1 ;
		RECT 8.325 1.965 8.605 2.16 ;
		LAYER M1 ;
		RECT 9.195 2.02 9.39 2.16 ;
		LAYER M1 ;
		RECT 9.8 2.02 9.995 2.545 ;
		LAYER M1 ;
		RECT 9.195 1.755 9.485 2.02 ;
		LAYER M1 ;
		RECT 9.205 1.74 9.485 1.755 ;
		LAYER M1 ;
		RECT 9.795 1.74 10.075 2.02 ;
		LAYER M1 ;
		RECT 2.89 1.03 3.18 1.315 ;
		LAYER M1 ;
		RECT 2.9 1.0 3.18 1.03 ;
		LAYER M1 ;
		RECT 4.455 1.125 5.765 1.315 ;
		LAYER M1 ;
		RECT 4.455 1.0 5.18 1.125 ;
		LAYER M1 ;
		RECT 4.5 0.995 5.18 1.0 ;
		LAYER M1 ;
		RECT 10.28 1.54 10.47 3.025 ;
		LAYER M1 ;
		RECT 7.56 1.31 7.84 1.425 ;
		LAYER M1 ;
		RECT 7.125 1.12 7.85 1.31 ;
		LAYER M1 ;
		RECT 7.125 1.03 7.405 1.12 ;
		LAYER M1 ;
		RECT 9.16 1.345 10.47 1.54 ;
		LAYER M1 ;
		RECT 9.16 0.995 9.44 1.345 ;
		LAYER M1 ;
		RECT 10.28 0.925 10.47 1.345 ;
		LAYER M1 ;
		RECT 10.755 1.725 10.95 3.505 ;
		LAYER M1 ;
		RECT 11.36 2.825 11.55 3.705 ;
		LAYER M1 ;
		RECT 12.465 3.05 12.745 3.1 ;
		LAYER M1 ;
		RECT 11.15 2.545 11.55 2.825 ;
		LAYER M1 ;
		RECT 11.36 2.39 11.55 2.545 ;
		LAYER M1 ;
		RECT 11.9 2.86 12.745 3.05 ;
		LAYER M1 ;
		RECT 11.36 2.11 11.69 2.39 ;
		LAYER M1 ;
		RECT 11.9 1.725 12.095 2.86 ;
		LAYER M1 ;
		RECT 12.465 2.82 12.745 2.86 ;
		LAYER M1 ;
		RECT 10.755 1.535 12.095 1.725 ;
		LAYER M1 ;
		RECT 10.755 1.33 10.95 1.535 ;
		LAYER M1 ;
		RECT 11.9 1.33 12.095 1.535 ;
		LAYER M1 ;
		RECT 10.19 0.645 10.47 0.925 ;
		LAYER M1 ;
		RECT 10.67 0.88 10.95 1.33 ;
		LAYER M1 ;
		RECT 11.85 0.88 12.13 1.33 ;
	END
END MMI_SFFPB
MACRO MMI_SFFRB
	CLASS CORE ;
	FOREIGN MMI_SFFRB 0 0 ;
	SIZE 13.64 BY 6.2 ;
	SYMMETRY X Y ;
	SITE CORE1 ;
	PIN d
		DIRECTION input ;
		USE SIGNAL ;
		PORT
			LAYER M1 ;
			RECT 1.36 2.6 1.74 2.98 ;
		END
		AntennaGateArea 0.3465 ;
	END d
	PIN GND
		DIRECTION inout ;
		USE GROUND ;
		PORT
			LAYER M1 ;
			RECT 0.785 0.42 1.065 1.82 ;
			LAYER M1 ;
			RECT 2.8 0.42 3.08 1.435 ;
			LAYER M1 ;
			RECT 5.265 1.265 5.58 1.545 ;
			LAYER M1 ;
			RECT 5.28 0.42 5.56 1.265 ;
			LAYER M1 ;
			RECT 6.6 0.42 6.88 1.91 ;
			LAYER M1 ;
			RECT 8.83 0.42 9.11 1.565 ;
			LAYER M1 ;
			RECT 10.965 0.42 11.245 2.21 ;
			LAYER M1 ;
			RECT 12.555 0.42 12.835 2.685 ;
			LAYER M1 ;
			RECT 0.0 -0.42 13.645 0.42 ;
		END
	END GND
	PIN q
		DIRECTION output ;
		USE SIGNAL ;
		PORT
			LAYER M1 ;
			RECT 13.145 4.38 13.425 5.58 ;
			LAYER M1 ;
			RECT 13.145 4.11 13.435 4.38 ;
			LAYER M1 ;
			RECT 13.15 2.685 13.435 4.11 ;
			LAYER M1 ;
			RECT 13.145 2.26 13.435 2.685 ;
			LAYER M1 ;
			RECT 13.145 1.985 13.425 2.26 ;
		END
		AntennaDiffArea 0.91245 ;
	END q
	PIN s_en
		DIRECTION input ;
		USE SIGNAL ;
		PORT
			LAYER M1 ;
			RECT 0.74 2.93 1.12 2.98 ;
			LAYER M1 ;
			RECT 0.545 2.65 1.12 2.93 ;
			LAYER M1 ;
			RECT 0.74 2.6 1.12 2.65 ;
		END
		AntennaGateArea 0.51525 ;
	END s_en
	PIN s_in
		DIRECTION input ;
		USE SIGNAL ;
		PORT
			LAYER M1 ;
			RECT 1.98 2.925 2.36 2.98 ;
			LAYER M1 ;
			RECT 1.98 2.645 2.37 2.925 ;
			LAYER M1 ;
			RECT 1.98 2.6 2.36 2.645 ;
		END
		AntennaGateArea 0.17325 ;
	END s_in
	PIN VDD
		DIRECTION inout ;
		USE POWER ;
		PORT
			LAYER M1 ;
			RECT 0.0 5.78 13.645 6.62 ;
			LAYER M1 ;
			RECT 0.79 4.11 1.07 5.78 ;
			LAYER M1 ;
			RECT 2.76 4.115 3.04 5.78 ;
			LAYER M1 ;
			RECT 5.17 4.395 5.45 5.78 ;
			LAYER M1 ;
			RECT 6.35 3.825 6.63 5.78 ;
			LAYER M1 ;
			RECT 8.875 4.235 9.155 5.78 ;
			LAYER M1 ;
			RECT 11.1 4.115 11.38 5.78 ;
			LAYER M1 ;
			RECT 12.555 4.11 12.835 5.78 ;
		END
	END VDD
	PIN clk
		DIRECTION input ;
		USE CLOCK ;
		PORT
			LAYER M1 ;
			RECT 5.475 3.525 5.755 3.805 ;
			LAYER M1 ;
			RECT 5.555 2.875 5.75 3.525 ;
			LAYER M1 ;
			RECT 6.32 2.875 6.7 2.98 ;
			LAYER M1 ;
			RECT 5.555 2.825 6.7 2.875 ;
			LAYER M1 ;
			RECT 5.555 2.68 7.79 2.825 ;
			LAYER M1 ;
			RECT 6.135 2.63 7.79 2.68 ;
			LAYER M1 ;
			RECT 6.135 2.6 6.7 2.63 ;
			LAYER M1 ;
			RECT 6.135 2.585 6.415 2.6 ;
			LAYER M1 ;
			RECT 7.51 2.545 7.79 2.63 ;
		END
		AntennaGateArea 0.44625 ;
	END clk
	PIN clrb
		DIRECTION input ;
		USE SIGNAL ;
		PORT
			LAYER M1 ;
			RECT 3.02 2.7 3.6 2.98 ;
			LAYER M1 ;
			RECT 3.22 2.6 3.6 2.7 ;
		END
		AntennaGateArea 0.498 ;
	END clrb
	OBS
		LAYER M1 ;
		RECT 0.16 4.455 0.44 5.05 ;
		LAYER M1 ;
		RECT 0.15 4.115 0.44 4.455 ;
		LAYER M1 ;
		RECT 0.15 3.445 0.345 4.115 ;
		LAYER M1 ;
		RECT 1.75 4.11 2.03 5.58 ;
		LAYER M1 ;
		RECT 3.35 4.725 3.63 5.425 ;
		LAYER M1 ;
		RECT 3.94 5.02 4.22 5.425 ;
		LAYER M1 ;
		RECT 3.94 4.725 4.225 5.02 ;
		LAYER M1 ;
		RECT 1.8 3.89 1.995 4.11 ;
		LAYER M1 ;
		RECT 3.35 3.89 3.545 4.725 ;
		LAYER M1 ;
		RECT 1.8 3.7 3.545 3.89 ;
		LAYER M1 ;
		RECT 1.99 3.445 2.27 3.495 ;
		LAYER M1 ;
		RECT 0.15 3.25 2.27 3.445 ;
		LAYER M1 ;
		RECT 0.15 2.25 0.345 3.25 ;
		LAYER M1 ;
		RECT 1.99 3.215 2.27 3.25 ;
		LAYER M1 ;
		RECT 2.575 2.4 2.77 3.7 ;
		LAYER M1 ;
		RECT 4.03 2.4 4.225 4.725 ;
		LAYER M1 ;
		RECT 4.535 4.37 4.815 5.305 ;
		LAYER M1 ;
		RECT 4.6 3.45 4.795 4.37 ;
		LAYER M1 ;
		RECT 5.76 4.195 6.04 5.095 ;
		LAYER M1 ;
		RECT 5.085 4.005 6.15 4.195 ;
		LAYER M1 ;
		RECT 4.6 3.33 4.885 3.45 ;
		LAYER M1 ;
		RECT 4.605 3.17 4.885 3.33 ;
		LAYER M1 ;
		RECT 0.99 2.25 1.27 2.3 ;
		LAYER M1 ;
		RECT 0.15 2.055 1.27 2.25 ;
		LAYER M1 ;
		RECT 0.15 1.825 0.345 2.055 ;
		LAYER M1 ;
		RECT 0.99 2.02 1.27 2.055 ;
		LAYER M1 ;
		RECT 1.85 2.205 3.75 2.4 ;
		LAYER M1 ;
		RECT 0.15 1.39 0.43 1.825 ;
		LAYER M1 ;
		RECT 1.85 1.82 2.04 2.205 ;
		LAYER M1 ;
		RECT 3.47 2.12 3.75 2.205 ;
		LAYER M1 ;
		RECT 4.03 2.12 4.34 2.4 ;
		LAYER M1 ;
		RECT 1.76 1.12 2.04 1.82 ;
		LAYER M1 ;
		RECT 4.03 1.625 4.225 2.12 ;
		LAYER M1 ;
		RECT 4.03 1.61 4.4 1.625 ;
		LAYER M1 ;
		RECT 4.03 1.435 4.465 1.61 ;
		LAYER M1 ;
		RECT 3.39 1.13 3.67 1.435 ;
		LAYER M1 ;
		RECT 4.185 1.33 4.465 1.435 ;
		LAYER M1 ;
		RECT 4.675 1.13 4.865 3.17 ;
		LAYER M1 ;
		RECT 5.085 2.69 5.275 4.005 ;
		LAYER M1 ;
		RECT 5.955 3.625 6.15 4.005 ;
		LAYER M1 ;
		RECT 8.105 5.38 8.385 5.41 ;
		LAYER M1 ;
		RECT 6.88 5.185 8.385 5.38 ;
		LAYER M1 ;
		RECT 6.88 3.625 7.075 5.185 ;
		LAYER M1 ;
		RECT 8.105 5.13 8.385 5.185 ;
		LAYER M1 ;
		RECT 7.32 4.715 8.635 4.91 ;
		LAYER M1 ;
		RECT 7.32 3.85 7.6 4.715 ;
		LAYER M1 ;
		RECT 7.91 4.235 8.19 4.515 ;
		LAYER M1 ;
		RECT 5.955 3.43 7.075 3.625 ;
		LAYER M1 ;
		RECT 7.41 3.215 7.6 3.85 ;
		LAYER M1 ;
		RECT 7.995 3.605 8.185 4.235 ;
		LAYER M1 ;
		RECT 8.445 3.995 8.635 4.715 ;
		LAYER M1 ;
		RECT 9.465 4.445 9.745 4.815 ;
		LAYER M1 ;
		RECT 9.455 4.115 9.745 4.445 ;
		LAYER M1 ;
		RECT 10.055 4.115 10.335 4.815 ;
		LAYER M1 ;
		RECT 11.69 4.32 11.97 4.815 ;
		LAYER M1 ;
		RECT 11.69 4.115 11.98 4.32 ;
		LAYER M1 ;
		RECT 9.455 3.995 9.645 4.115 ;
		LAYER M1 ;
		RECT 8.445 3.805 9.645 3.995 ;
		LAYER M1 ;
		RECT 9.175 3.64 9.645 3.805 ;
		LAYER M1 ;
		RECT 10.14 3.785 10.33 4.115 ;
		LAYER M1 ;
		RECT 11.785 3.785 11.98 4.115 ;
		LAYER M1 ;
		RECT 12.605 3.785 12.885 3.835 ;
		LAYER M1 ;
		RECT 7.995 3.415 8.695 3.605 ;
		LAYER M1 ;
		RECT 8.41 3.365 8.695 3.415 ;
		LAYER M1 ;
		RECT 7.41 3.025 8.19 3.215 ;
		LAYER M1 ;
		RECT 8.41 3.175 9.105 3.365 ;
		LAYER M1 ;
		RECT 8.5 3.17 9.105 3.175 ;
		LAYER M1 ;
		RECT 5.075 2.41 5.355 2.69 ;
		LAYER M1 ;
		RECT 5.085 2.145 5.275 2.41 ;
		LAYER M1 ;
		RECT 8.0 2.345 8.19 3.025 ;
		LAYER M1 ;
		RECT 8.435 2.345 8.715 2.455 ;
		LAYER M1 ;
		RECT 6.09 2.175 8.715 2.345 ;
		LAYER M1 ;
		RECT 6.09 2.155 8.705 2.175 ;
		LAYER M1 ;
		RECT 5.085 1.955 5.585 2.145 ;
		LAYER M1 ;
		RECT 5.265 1.855 5.58 1.955 ;
		LAYER M1 ;
		RECT 6.09 1.91 6.285 2.155 ;
		LAYER M1 ;
		RECT 6.01 1.595 6.29 1.91 ;
		LAYER M1 ;
		RECT 3.385 0.94 4.865 1.13 ;
		LAYER M1 ;
		RECT 7.3 1.765 7.49 2.155 ;
		LAYER M1 ;
		RECT 8.915 1.955 9.105 3.17 ;
		LAYER M1 ;
		RECT 9.455 2.21 9.645 3.64 ;
		LAYER M1 ;
		RECT 10.055 3.59 10.33 3.785 ;
		LAYER M1 ;
		RECT 10.645 3.59 12.885 3.785 ;
		LAYER M1 ;
		RECT 10.055 3.125 10.25 3.59 ;
		LAYER M1 ;
		RECT 10.645 3.325 10.925 3.59 ;
		LAYER M1 ;
		RECT 11.6 3.125 11.88 3.225 ;
		LAYER M1 ;
		RECT 10.055 2.945 11.88 3.125 ;
		LAYER M1 ;
		RECT 10.055 2.93 11.86 2.945 ;
		LAYER M1 ;
		RECT 10.055 2.21 10.25 2.93 ;
		LAYER M1 ;
		RECT 12.08 2.21 12.27 3.59 ;
		LAYER M1 ;
		RECT 12.605 3.555 12.885 3.59 ;
		LAYER M1 ;
		RECT 7.96 1.765 9.105 1.955 ;
		LAYER M1 ;
		RECT 9.37 1.93 9.65 2.21 ;
		LAYER M1 ;
		RECT 9.96 2.005 10.25 2.21 ;
		LAYER M1 ;
		RECT 9.96 1.93 10.24 2.005 ;
		LAYER M1 ;
		RECT 7.28 1.45 7.56 1.765 ;
		LAYER M1 ;
		RECT 7.96 1.565 8.15 1.765 ;
		LAYER M1 ;
		RECT 7.87 1.285 8.15 1.565 ;
		LAYER M1 ;
		RECT 11.935 1.895 12.27 2.21 ;
		LAYER M1 ;
		RECT 11.935 1.24 12.215 1.895 ;
	END
END MMI_SFFRB
MACRO MMI_SFFSB
	CLASS CORE ;
	FOREIGN MMI_SFFSB 0 0 ;
	SIZE 14.88 BY 6.2 ;
	SYMMETRY X Y ;
	SITE CORE1 ;
	PIN d
		DIRECTION input ;
		USE SIGNAL ;
		PORT
			LAYER M1 ;
			RECT 1.5 2.88 1.78 2.9 ;
			LAYER M1 ;
			RECT 1.98 2.88 2.36 2.98 ;
			LAYER M1 ;
			RECT 1.5 2.685 2.36 2.88 ;
			LAYER M1 ;
			RECT 1.5 2.62 1.78 2.685 ;
			LAYER M1 ;
			RECT 1.98 2.6 2.36 2.685 ;
		END
		AntennaGateArea 0.3465 ;
	END d
	PIN GND
		DIRECTION inout ;
		USE GROUND ;
		PORT
			LAYER M1 ;
			RECT 6.625 1.735 7.205 2.44 ;
			LAYER M1 ;
			RECT 12.37 2.365 12.65 2.39 ;
			LAYER M1 ;
			RECT 12.355 2.11 12.65 2.365 ;
			LAYER M1 ;
			RECT 0.75 0.42 1.03 1.525 ;
			LAYER M1 ;
			RECT 2.3 0.42 2.58 1.585 ;
			LAYER M1 ;
			RECT 3.85 0.42 4.13 1.315 ;
			LAYER M1 ;
			RECT 6.625 0.42 6.91 1.735 ;
			LAYER M1 ;
			RECT 8.57 0.42 8.85 1.43 ;
			LAYER M1 ;
			RECT 11.26 0.42 11.54 1.335 ;
			LAYER M1 ;
			RECT 12.355 0.42 12.635 2.11 ;
			LAYER M1 ;
			RECT 13.835 0.42 14.115 1.71 ;
			LAYER M1 ;
			RECT 0.0 -0.42 14.885 0.42 ;
		END
	END GND
	PIN q
		DIRECTION output ;
		USE SIGNAL ;
		PORT
			LAYER M1 ;
			RECT 14.105 3.68 14.385 5.15 ;
			LAYER M1 ;
			RECT 14.19 2.98 14.385 3.68 ;
			LAYER M1 ;
			RECT 14.19 2.605 14.76 2.98 ;
			LAYER M1 ;
			RECT 14.47 1.71 14.66 2.605 ;
			LAYER M1 ;
			RECT 14.425 1.01 14.705 1.71 ;
		END
		AntennaDiffArea 0.91245 ;
	END q
	PIN s_in
		DIRECTION input ;
		USE SIGNAL ;
		PORT
			LAYER M1 ;
			RECT 3.22 2.6 3.6 2.98 ;
		END
		AntennaGateArea 0.17325 ;
	END s_in
	PIN s_en
		DIRECTION input ;
		USE SIGNAL ;
		PORT
			LAYER M1 ;
			RECT 0.74 2.93 1.12 2.98 ;
			LAYER M1 ;
			RECT 0.555 2.65 1.12 2.93 ;
			LAYER M1 ;
			RECT 0.74 2.6 1.12 2.65 ;
		END
		AntennaGateArea 0.72675 ;
	END s_en
	PIN VDD
		DIRECTION inout ;
		USE POWER ;
		PORT
			LAYER M1 ;
			RECT 0.0 5.78 14.885 6.62 ;
			LAYER M1 ;
			RECT 0.79 4.11 1.07 5.78 ;
			LAYER M1 ;
			RECT 2.755 4.115 3.035 5.78 ;
			LAYER M1 ;
			RECT 5.59 3.96 5.87 5.78 ;
			LAYER M1 ;
			RECT 6.775 3.675 7.055 5.78 ;
			LAYER M1 ;
			RECT 10.41 3.91 10.69 5.78 ;
			LAYER M1 ;
			RECT 12.28 3.68 12.56 5.78 ;
			LAYER M1 ;
			RECT 13.515 3.68 13.795 5.78 ;
		END
	END VDD
	PIN s_out
		DIRECTION output ;
		USE SIGNAL ;
		PORT
			LAYER M1 ;
			RECT 12.87 3.68 13.15 4.315 ;
			LAYER M1 ;
			RECT 12.96 2.98 13.15 3.68 ;
			LAYER M1 ;
			RECT 12.96 2.655 13.52 2.98 ;
			LAYER M1 ;
			RECT 13.11 2.6 13.52 2.655 ;
			LAYER M1 ;
			RECT 13.145 1.93 13.335 2.6 ;
			LAYER M1 ;
			RECT 12.925 1.74 13.335 1.93 ;
			LAYER M1 ;
			RECT 12.925 1.715 13.115 1.74 ;
			LAYER M1 ;
			RECT 12.835 1.08 13.115 1.715 ;
		END
		AntennaDiffArea 0.588675 ;
	END s_out
	PIN setb
		DIRECTION input ;
		USE SIGNAL ;
		PORT
			LAYER M1 ;
			RECT 6.73 2.88 7.01 2.93 ;
			LAYER M1 ;
			RECT 6.73 2.685 7.84 2.88 ;
			LAYER M1 ;
			RECT 6.73 2.65 7.01 2.685 ;
			LAYER M1 ;
			RECT 7.645 2.61 7.84 2.685 ;
			LAYER M1 ;
			RECT 7.645 2.36 8.03 2.61 ;
			LAYER M1 ;
			RECT 7.56 2.33 8.03 2.36 ;
			LAYER M1 ;
			RECT 7.56 1.98 7.94 2.33 ;
		END
		AntennaGateArea 0.4575 ;
	END setb
	PIN clk
		DIRECTION input ;
		USE CLOCK ;
		PORT
			LAYER M1 ;
			RECT 4.46 2.93 4.84 2.98 ;
			LAYER M1 ;
			RECT 4.15 2.925 4.84 2.93 ;
			LAYER M1 ;
			RECT 4.14 2.645 4.84 2.925 ;
			LAYER M1 ;
			RECT 4.46 2.6 4.84 2.645 ;
		END
		AntennaGateArea 0.44625 ;
	END clk
	OBS
		LAYER M1 ;
		RECT 0.16 4.11 0.44 5.045 ;
		LAYER M1 ;
		RECT 1.75 4.11 2.03 5.58 ;
		LAYER M1 ;
		RECT 4.78 5.365 5.06 5.49 ;
		LAYER M1 ;
		RECT 3.43 5.175 5.295 5.365 ;
		LAYER M1 ;
		RECT 3.43 4.815 3.62 5.175 ;
		LAYER M1 ;
		RECT 3.345 4.115 3.625 4.815 ;
		LAYER M1 ;
		RECT 3.95 4.135 4.23 4.835 ;
		LAYER M1 ;
		RECT 4.54 4.135 4.82 4.835 ;
		LAYER M1 ;
		RECT 0.16 3.515 0.355 4.11 ;
		LAYER M1 ;
		RECT 1.835 3.915 2.03 4.11 ;
		LAYER M1 ;
		RECT 3.955 3.915 4.145 4.135 ;
		LAYER M1 ;
		RECT 1.835 3.725 4.145 3.915 ;
		LAYER M1 ;
		RECT 1.99 3.515 2.27 3.525 ;
		LAYER M1 ;
		RECT 0.16 3.325 2.27 3.515 ;
		LAYER M1 ;
		RECT 0.16 1.525 0.355 3.325 ;
		LAYER M1 ;
		RECT 1.99 3.245 2.27 3.325 ;
		LAYER M1 ;
		RECT 2.58 1.98 2.775 3.725 ;
		LAYER M1 ;
		RECT 4.63 3.37 4.82 4.135 ;
		LAYER M1 ;
		RECT 5.105 3.76 5.295 5.175 ;
		LAYER M1 ;
		RECT 6.185 4.885 6.465 5.165 ;
		LAYER M1 ;
		RECT 6.23 4.375 6.425 4.885 ;
		LAYER M1 ;
		RECT 5.105 3.57 5.765 3.76 ;
		LAYER M1 ;
		RECT 6.185 3.675 6.465 4.375 ;
		LAYER M1 ;
		RECT 7.465 5.01 9.25 5.205 ;
		LAYER M1 ;
		RECT 7.465 4.61 7.66 5.01 ;
		LAYER M1 ;
		RECT 7.38 3.675 7.66 4.61 ;
		LAYER M1 ;
		RECT 7.98 4.375 8.26 4.635 ;
		LAYER M1 ;
		RECT 7.975 3.935 8.26 4.375 ;
		LAYER M1 ;
		RECT 8.57 4.29 8.85 4.635 ;
		LAYER M1 ;
		RECT 8.57 3.935 8.86 4.29 ;
		LAYER M1 ;
		RECT 4.63 3.18 5.325 3.37 ;
		LAYER M1 ;
		RECT 5.135 2.735 5.325 3.18 ;
		LAYER M1 ;
		RECT 5.095 2.455 5.375 2.735 ;
		LAYER M1 ;
		RECT 1.43 1.91 4.775 1.98 ;
		LAYER M1 ;
		RECT 5.135 1.91 5.325 2.455 ;
		LAYER M1 ;
		RECT 1.43 1.785 4.78 1.91 ;
		LAYER M1 ;
		RECT 1.43 1.585 1.62 1.785 ;
		LAYER M1 ;
		RECT 0.16 1.09 0.44 1.525 ;
		LAYER M1 ;
		RECT 1.34 0.885 1.62 1.585 ;
		LAYER M1 ;
		RECT 2.89 1.315 3.085 1.785 ;
		LAYER M1 ;
		RECT 4.5 1.63 4.78 1.785 ;
		LAYER M1 ;
		RECT 5.09 1.63 5.37 1.91 ;
		LAYER M1 ;
		RECT 5.575 1.315 5.765 3.57 ;
		LAYER M1 ;
		RECT 6.23 3.325 6.425 3.675 ;
		LAYER M1 ;
		RECT 7.975 3.325 8.165 3.935 ;
		LAYER M1 ;
		RECT 6.05 3.13 8.47 3.325 ;
		LAYER M1 ;
		RECT 6.05 2.44 6.245 3.13 ;
		LAYER M1 ;
		RECT 5.965 1.74 6.245 2.44 ;
		LAYER M1 ;
		RECT 2.89 1.0 3.17 1.315 ;
		LAYER M1 ;
		RECT 4.44 1.125 5.765 1.315 ;
		LAYER M1 ;
		RECT 8.28 2.35 8.47 3.13 ;
		LAYER M1 ;
		RECT 8.67 2.81 8.86 3.935 ;
		LAYER M1 ;
		RECT 9.06 3.3 9.25 5.01 ;
		LAYER M1 ;
		RECT 9.45 3.71 9.73 4.77 ;
		LAYER M1 ;
		RECT 11.76 4.7 12.04 4.79 ;
		LAYER M1 ;
		RECT 10.89 4.51 12.04 4.7 ;
		LAYER M1 ;
		RECT 9.535 3.705 9.73 3.71 ;
		LAYER M1 ;
		RECT 10.89 3.705 11.08 4.51 ;
		LAYER M1 ;
		RECT 11.28 3.705 11.56 3.985 ;
		LAYER M1 ;
		RECT 9.535 3.515 11.08 3.705 ;
		LAYER M1 ;
		RECT 10.215 3.3 10.495 3.31 ;
		LAYER M1 ;
		RECT 9.06 3.105 10.495 3.3 ;
		LAYER M1 ;
		RECT 10.215 3.03 10.495 3.105 ;
		LAYER M1 ;
		RECT 9.64 2.81 9.92 2.825 ;
		LAYER M1 ;
		RECT 8.67 2.62 9.995 2.81 ;
		LAYER M1 ;
		RECT 9.64 2.545 9.995 2.62 ;
		LAYER M1 ;
		RECT 8.28 2.16 9.39 2.35 ;
		LAYER M1 ;
		RECT 8.325 1.965 8.605 2.16 ;
		LAYER M1 ;
		RECT 9.195 2.02 9.39 2.16 ;
		LAYER M1 ;
		RECT 9.8 2.02 9.995 2.545 ;
		LAYER M1 ;
		RECT 9.195 1.755 9.485 2.02 ;
		LAYER M1 ;
		RECT 9.205 1.74 9.485 1.755 ;
		LAYER M1 ;
		RECT 9.795 1.74 10.075 2.02 ;
		LAYER M1 ;
		RECT 4.44 1.0 5.18 1.125 ;
		LAYER M1 ;
		RECT 10.28 1.54 10.47 3.03 ;
		LAYER M1 ;
		RECT 10.19 1.43 10.47 1.54 ;
		LAYER M1 ;
		RECT 7.56 1.315 7.84 1.425 ;
		LAYER M1 ;
		RECT 7.125 1.125 7.84 1.315 ;
		LAYER M1 ;
		RECT 7.125 1.035 7.405 1.125 ;
		LAYER M1 ;
		RECT 9.16 1.235 10.47 1.43 ;
		LAYER M1 ;
		RECT 10.755 1.75 10.95 3.515 ;
		LAYER M1 ;
		RECT 11.355 2.825 11.545 3.705 ;
		LAYER M1 ;
		RECT 11.155 2.545 11.545 2.825 ;
		LAYER M1 ;
		RECT 12.175 2.82 12.455 2.91 ;
		LAYER M1 ;
		RECT 11.355 2.39 11.545 2.545 ;
		LAYER M1 ;
		RECT 11.89 2.63 12.455 2.82 ;
		LAYER M1 ;
		RECT 11.89 2.625 12.43 2.63 ;
		LAYER M1 ;
		RECT 11.355 2.11 11.69 2.39 ;
		LAYER M1 ;
		RECT 11.89 1.75 12.08 2.625 ;
		LAYER M1 ;
		RECT 10.755 1.56 12.08 1.75 ;
		LAYER M1 ;
		RECT 10.755 1.335 10.95 1.56 ;
		LAYER M1 ;
		RECT 11.89 1.335 12.08 1.56 ;
		LAYER M1 ;
		RECT 9.16 0.995 9.44 1.235 ;
		LAYER M1 ;
		RECT 10.67 0.885 10.95 1.335 ;
		LAYER M1 ;
		RECT 11.85 0.885 12.13 1.335 ;
	END
END MMI_SFFSB
MACRO MMI_TSBUFC
	CLASS CORE ;
	FOREIGN MMI_TSBUFC 0 0 ;
	SIZE 4.34 BY 6.2 ;
	SYMMETRY X Y ;
	SITE CORE1 ;
	PIN out
		DIRECTION output ;
		USE SIGNAL ;
		PORT
			LAYER M1 ;
			RECT 3.215 3.715 3.495 5.185 ;
			LAYER M1 ;
			RECT 3.295 2.98 3.485 3.715 ;
			LAYER M1 ;
			RECT 3.22 2.6 3.6 2.98 ;
			LAYER M1 ;
			RECT 3.295 2.14 3.485 2.6 ;
			LAYER M1 ;
			RECT 3.215 1.44 3.495 2.14 ;
		END
		AntennaDiffArea 1.0164 ;
	END out
	PIN GND
		DIRECTION inout ;
		USE GROUND ;
		PORT
			LAYER M1 ;
			RECT 0.795 0.42 1.075 1.915 ;
			LAYER M1 ;
			RECT 2.625 0.42 2.905 2.14 ;
			LAYER M1 ;
			RECT 3.805 0.42 4.085 2.14 ;
			LAYER M1 ;
			RECT 0.0 -0.42 4.34 0.42 ;
		END
	END GND
	PIN enb
		DIRECTION input ;
		USE SIGNAL ;
		PORT
			LAYER M1 ;
			RECT 0.74 2.93 1.12 2.98 ;
			LAYER M1 ;
			RECT 0.555 2.65 1.12 2.93 ;
			LAYER M1 ;
			RECT 0.74 2.6 1.12 2.65 ;
		END
		AntennaGateArea 0.15825 ;
	END enb
	PIN VDD
		DIRECTION inout ;
		USE POWER ;
		PORT
			LAYER M1 ;
			RECT 0.0 5.78 4.34 6.62 ;
			LAYER M1 ;
			RECT 1.385 3.8 1.665 5.78 ;
			LAYER M1 ;
			RECT 2.625 3.715 2.905 5.78 ;
			LAYER M1 ;
			RECT 3.805 3.715 4.085 5.78 ;
		END
	END VDD
	PIN en
		DIRECTION input ;
		USE SIGNAL ;
		PORT
			LAYER M1 ;
			RECT 2.6 2.92 2.98 2.98 ;
			LAYER M1 ;
			RECT 2.425 2.64 2.98 2.92 ;
			LAYER M1 ;
			RECT 2.6 2.6 2.98 2.64 ;
		END
		AntennaGateArea 0.15825 ;
	END en
	PIN in
		DIRECTION input ;
		USE SIGNAL ;
		PORT
			LAYER M1 ;
			RECT 1.36 2.94 1.74 2.98 ;
			LAYER M1 ;
			RECT 1.33 2.66 1.74 2.94 ;
			LAYER M1 ;
			RECT 1.36 2.6 1.74 2.66 ;
		END
		AntennaGateArea 0.31725 ;
	END in
	OBS
		LAYER M1 ;
		RECT 0.16 3.8 0.44 4.435 ;
		LAYER M1 ;
		RECT 0.795 3.8 1.075 5.14 ;
		LAYER M1 ;
		RECT 2.025 3.8 2.305 4.435 ;
		LAYER M1 ;
		RECT 0.16 2.31 0.35 3.8 ;
		LAYER M1 ;
		RECT 0.88 3.465 1.075 3.8 ;
		LAYER M1 ;
		RECT 2.025 3.465 2.215 3.8 ;
		LAYER M1 ;
		RECT 2.67 3.465 2.95 3.51 ;
		LAYER M1 ;
		RECT 0.88 3.27 2.95 3.465 ;
		LAYER M1 ;
		RECT 0.16 2.115 1.58 2.31 ;
		LAYER M1 ;
		RECT 0.16 1.915 0.35 2.115 ;
		LAYER M1 ;
		RECT 1.385 1.915 1.58 2.115 ;
		LAYER M1 ;
		RECT 2.025 1.92 2.215 3.27 ;
		LAYER M1 ;
		RECT 2.67 3.23 2.95 3.27 ;
		LAYER M1 ;
		RECT 0.16 1.635 0.44 1.915 ;
		LAYER M1 ;
		RECT 1.385 1.28 1.665 1.915 ;
		LAYER M1 ;
		RECT 2.025 1.64 2.305 1.92 ;
		LAYER M1 ;
		RECT 1.475 1.13 1.665 1.28 ;
		LAYER M1 ;
		RECT 1.475 0.935 2.385 1.13 ;
		LAYER M1 ;
		RECT 2.105 0.85 2.385 0.935 ;
	END
END MMI_TSBUFC
MACRO MMI_TSBUFE
	CLASS CORE ;
	FOREIGN MMI_TSBUFE 0 0 ;
	SIZE 7.44 BY 6.2 ;
	SYMMETRY X Y ;
	SITE CORE1 ;
	PIN out
		DIRECTION output ;
		USE SIGNAL ;
		PORT
			LAYER M1 ;
			RECT 3.195 3.775 3.475 5.57 ;
			LAYER M1 ;
			RECT 4.375 3.895 4.655 5.57 ;
			LAYER M1 ;
			RECT 5.555 3.895 5.835 5.57 ;
			LAYER M1 ;
			RECT 4.375 3.775 5.835 3.895 ;
			LAYER M1 ;
			RECT 3.195 3.585 5.835 3.775 ;
			LAYER M1 ;
			RECT 5.17 2.98 5.455 3.585 ;
			LAYER M1 ;
			RECT 5.08 2.625 5.46 2.98 ;
			LAYER M1 ;
			RECT 3.75 2.435 6.39 2.625 ;
			LAYER M1 ;
			RECT 3.75 1.525 4.03 2.435 ;
			LAYER M1 ;
			RECT 4.93 1.525 5.21 2.435 ;
			LAYER M1 ;
			RECT 6.11 1.525 6.39 2.435 ;
		END
		AntennaDiffArea 4.0656 ;
	END out
	PIN GND
		DIRECTION inout ;
		USE GROUND ;
		PORT
			LAYER M1 ;
			RECT 0.2 0.42 0.48 1.985 ;
			LAYER M1 ;
			RECT 1.38 0.42 1.66 1.985 ;
			LAYER M1 ;
			RECT 3.16 1.525 3.44 2.48 ;
			LAYER M1 ;
			RECT 3.15 1.3 3.435 1.525 ;
			LAYER M1 ;
			RECT 4.34 1.3 4.62 1.805 ;
			LAYER M1 ;
			RECT 3.15 1.105 4.62 1.3 ;
			LAYER M1 ;
			RECT 4.34 0.42 4.62 1.105 ;
			LAYER M1 ;
			RECT 5.52 0.42 5.8 1.805 ;
			LAYER M1 ;
			RECT 6.7 0.42 6.98 2.48 ;
			LAYER M1 ;
			RECT 0.0 -0.42 7.44 0.42 ;
		END
	END GND
	PIN enb
		DIRECTION input ;
		USE SIGNAL ;
		PORT
			LAYER M1 ;
			RECT 0.74 2.6 1.12 2.98 ;
		END
		AntennaGateArea 0.40725 ;
	END enb
	PIN VDD
		DIRECTION inout ;
		USE POWER ;
		PORT
			LAYER M1 ;
			RECT 0.0 5.78 7.44 6.62 ;
			LAYER M1 ;
			RECT 1.38 4.14 1.66 5.78 ;
			LAYER M1 ;
			RECT 2.605 4.115 2.885 5.78 ;
			LAYER M1 ;
			RECT 3.785 4.115 4.065 5.78 ;
			LAYER M1 ;
			RECT 4.965 4.115 5.245 5.78 ;
			LAYER M1 ;
			RECT 6.145 3.585 6.425 5.78 ;
		END
	END VDD
	PIN en
		DIRECTION input ;
		USE SIGNAL ;
		PORT
			LAYER M1 ;
			RECT 1.98 2.6 2.36 2.98 ;
		END
		AntennaGateArea 0.40725 ;
	END en
	PIN in
		DIRECTION input ;
		USE SIGNAL ;
		PORT
			LAYER M1 ;
			RECT 1.36 2.6 1.74 2.98 ;
		END
		AntennaGateArea 0.8145 ;
	END in
	OBS
		LAYER M1 ;
		RECT 0.2 3.6 0.48 5.205 ;
		LAYER M1 ;
		RECT 0.79 3.79 1.07 5.205 ;
		LAYER M1 ;
		RECT 1.97 3.79 2.25 5.205 ;
		LAYER M1 ;
		RECT 0.79 3.6 2.84 3.79 ;
		LAYER M1 ;
		RECT 0.2 2.375 0.395 3.6 ;
		LAYER M1 ;
		RECT 2.645 3.205 2.84 3.6 ;
		LAYER M1 ;
		RECT 3.655 3.205 4.715 3.295 ;
		LAYER M1 ;
		RECT 2.645 3.015 4.715 3.205 ;
		LAYER M1 ;
		RECT 0.2 2.185 2.16 2.375 ;
		LAYER M1 ;
		RECT 0.83 1.985 1.025 2.185 ;
		LAYER M1 ;
		RECT 1.97 1.985 2.16 2.185 ;
		LAYER M1 ;
		RECT 2.645 1.985 2.84 3.015 ;
		LAYER M1 ;
		RECT 0.79 1.015 1.07 1.985 ;
		LAYER M1 ;
		RECT 1.97 1.015 2.25 1.985 ;
		LAYER M1 ;
		RECT 2.56 1.015 2.84 1.985 ;
		LAYER M1 ;
		RECT 2.055 0.815 2.25 1.015 ;
		LAYER M1 ;
		RECT 3.295 0.815 3.965 0.9 ;
		LAYER M1 ;
		RECT 2.055 0.62 3.97 0.815 ;
	END
END MMI_TSBUFE
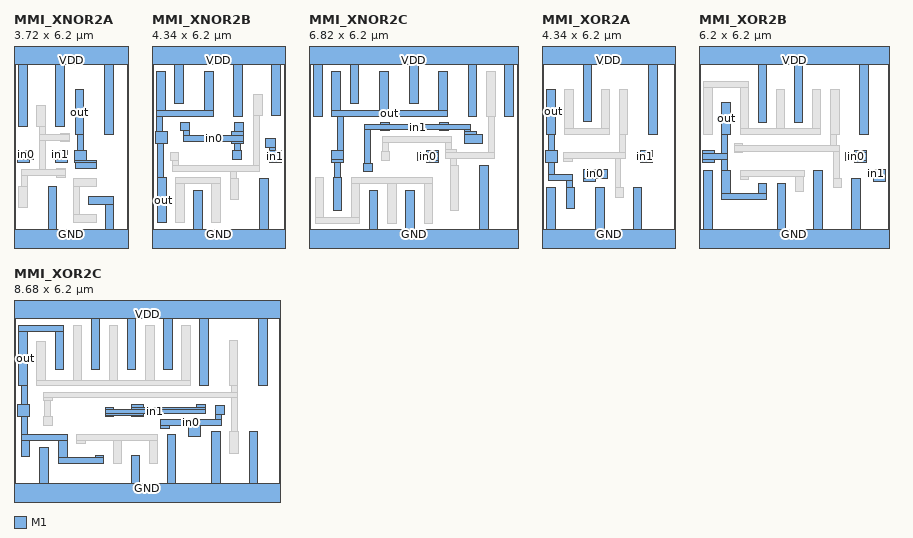
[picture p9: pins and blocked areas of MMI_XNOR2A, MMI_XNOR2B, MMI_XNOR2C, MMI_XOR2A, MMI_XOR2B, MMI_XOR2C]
MACRO MMI_XNOR2A
	CLASS CORE ;
	FOREIGN MMI_XNOR2A 0 0 ;
	SIZE 3.72 BY 6.2 ;
	SYMMETRY X Y ;
	SITE CORE1 ;
	PIN out
		DIRECTION output ;
		USE SIGNAL ;
		PORT
			LAYER M1 ;
			RECT 1.995 3.505 2.275 4.975 ;
			LAYER M1 ;
			RECT 2.07 2.98 2.265 3.505 ;
			LAYER M1 ;
			RECT 1.98 2.675 2.36 2.98 ;
			LAYER M1 ;
			RECT 1.98 2.6 2.7 2.675 ;
			LAYER M1 ;
			RECT 2.0 2.395 2.7 2.6 ;
		END
		AntennaDiffArea 0.9856 ;
	END out
	PIN in1
		DIRECTION input ;
		USE SIGNAL ;
		PORT
			LAYER M1 ;
			RECT 1.27 2.7 1.74 2.98 ;
			LAYER M1 ;
			RECT 1.36 2.6 1.74 2.7 ;
		END
		AntennaGateArea 0.5775 ;
	END in1
	PIN GND
		DIRECTION inout ;
		USE GROUND ;
		PORT
			LAYER M1 ;
			RECT 1.12 0.42 1.4 1.82 ;
			LAYER M1 ;
			RECT 2.42 1.215 3.255 1.495 ;
			LAYER M1 ;
			RECT 2.97 0.42 3.255 1.215 ;
			LAYER M1 ;
			RECT 0.0 -0.42 3.72 0.42 ;
		END
	END GND
	PIN VDD
		DIRECTION inout ;
		USE POWER ;
		PORT
			LAYER M1 ;
			RECT 0.0 5.78 3.72 6.62 ;
			LAYER M1 ;
			RECT 0.16 3.755 0.44 5.78 ;
			LAYER M1 ;
			RECT 1.355 3.755 1.635 5.78 ;
			LAYER M1 ;
			RECT 2.96 3.505 3.24 5.78 ;
		END
	END VDD
	PIN in0
		DIRECTION input ;
		USE SIGNAL ;
		PORT
			LAYER M1 ;
			RECT 0.12 2.7 0.635 2.98 ;
			LAYER M1 ;
			RECT 0.12 2.6 0.5 2.7 ;
		END
		AntennaGateArea 0.5775 ;
	END in0
	OBS
		LAYER M1 ;
		RECT 0.75 3.755 1.03 4.455 ;
		LAYER M1 ;
		RECT 0.84 3.505 1.03 3.755 ;
		LAYER M1 ;
		RECT 1.515 3.505 1.795 3.55 ;
		LAYER M1 ;
		RECT 0.84 3.315 1.795 3.505 ;
		LAYER M1 ;
		RECT 0.84 2.35 1.03 3.315 ;
		LAYER M1 ;
		RECT 1.515 3.27 1.795 3.315 ;
		LAYER M1 ;
		RECT 1.385 2.35 1.665 2.395 ;
		LAYER M1 ;
		RECT 0.245 2.16 1.665 2.35 ;
		LAYER M1 ;
		RECT 0.245 1.82 0.435 2.16 ;
		LAYER M1 ;
		RECT 1.385 2.115 1.665 2.16 ;
		LAYER M1 ;
		RECT 0.16 1.12 0.44 1.82 ;
		LAYER M1 ;
		RECT 1.95 1.805 2.7 2.085 ;
		LAYER M1 ;
		RECT 1.95 0.905 2.14 1.805 ;
		LAYER M1 ;
		RECT 1.95 0.625 2.7 0.905 ;
	END
END MMI_XNOR2A
MACRO MMI_XNOR2B
	CLASS CORE ;
	FOREIGN MMI_XNOR2B 0 0 ;
	SIZE 4.34 BY 6.2 ;
	SYMMETRY X Y ;
	SITE CORE1 ;
	PIN out
		DIRECTION output ;
		USE SIGNAL ;
		PORT
			LAYER M1 ;
			RECT 0.16 4.3 0.44 5.58 ;
			LAYER M1 ;
			RECT 1.715 4.3 1.995 5.58 ;
			LAYER M1 ;
			RECT 0.16 4.11 1.995 4.3 ;
			LAYER M1 ;
			RECT 0.16 3.6 0.355 4.11 ;
			LAYER M1 ;
			RECT 0.12 3.22 0.5 3.6 ;
			LAYER M1 ;
			RECT 0.185 2.095 0.38 3.22 ;
			LAYER M1 ;
			RECT 0.185 0.625 0.465 2.095 ;
		END
		AntennaDiffArea 1.8942 ;
	END out
	PIN in1
		DIRECTION input ;
		USE SIGNAL ;
		PORT
			LAYER M1 ;
			RECT 3.71 3.1 4.035 3.38 ;
			LAYER M1 ;
			RECT 3.84 2.98 4.035 3.1 ;
			LAYER M1 ;
			RECT 3.84 2.6 4.22 2.98 ;
		END
		AntennaGateArea 0.924 ;
	END in1
	PIN GND
		DIRECTION inout ;
		USE GROUND ;
		PORT
			LAYER M1 ;
			RECT 1.365 0.42 1.645 1.685 ;
			LAYER M1 ;
			RECT 3.515 0.42 3.795 2.085 ;
			LAYER M1 ;
			RECT 0.0 -0.42 4.34 0.42 ;
		END
	END GND
	PIN VDD
		DIRECTION inout ;
		USE POWER ;
		PORT
			LAYER M1 ;
			RECT 0.0 5.78 4.34 6.62 ;
			LAYER M1 ;
			RECT 0.75 4.52 1.03 5.78 ;
			LAYER M1 ;
			RECT 2.675 4.11 2.955 5.78 ;
			LAYER M1 ;
			RECT 3.905 4.115 4.185 5.78 ;
		END
	END VDD
	PIN in0
		DIRECTION input ;
		USE SIGNAL ;
		PORT
			LAYER M1 ;
			RECT 0.945 3.63 1.225 3.91 ;
			LAYER M1 ;
			RECT 1.035 3.465 1.225 3.63 ;
			LAYER M1 ;
			RECT 2.69 3.6 2.97 3.91 ;
			LAYER M1 ;
			RECT 2.6 3.465 2.98 3.6 ;
			LAYER M1 ;
			RECT 1.035 3.27 2.98 3.465 ;
			LAYER M1 ;
			RECT 2.6 3.22 2.98 3.27 ;
			LAYER M1 ;
			RECT 2.705 2.97 2.9 3.22 ;
			LAYER M1 ;
			RECT 2.64 2.69 2.92 2.97 ;
		END
		AntennaGateArea 0.924 ;
	END in0
	OBS
		LAYER M1 ;
		RECT 3.315 4.115 3.595 4.815 ;
		LAYER M1 ;
		RECT 0.59 2.65 0.87 2.93 ;
		LAYER M1 ;
		RECT 0.68 2.49 0.87 2.65 ;
		LAYER M1 ;
		RECT 3.315 2.49 3.505 4.115 ;
		LAYER M1 ;
		RECT 0.68 2.295 3.505 2.49 ;
		LAYER M1 ;
		RECT 0.775 1.905 2.235 2.095 ;
		LAYER M1 ;
		RECT 0.775 0.625 1.055 1.905 ;
		LAYER M1 ;
		RECT 1.955 0.625 2.235 1.905 ;
		LAYER M1 ;
		RECT 2.555 2.085 2.745 2.295 ;
		LAYER M1 ;
		RECT 2.555 1.385 2.835 2.085 ;
	END
END MMI_XNOR2B
MACRO MMI_XNOR2C
	CLASS CORE ;
	FOREIGN MMI_XNOR2C 0 0 ;
	SIZE 6.82 BY 6.2 ;
	SYMMETRY X Y ;
	SITE CORE1 ;
	PIN out
		DIRECTION output ;
		USE SIGNAL ;
		PORT
			LAYER M1 ;
			RECT 0.75 4.3 1.03 5.58 ;
			LAYER M1 ;
			RECT 2.315 4.3 2.595 5.58 ;
			LAYER M1 ;
			RECT 4.24 4.3 4.52 5.58 ;
			LAYER M1 ;
			RECT 0.75 4.11 4.52 4.3 ;
			LAYER M1 ;
			RECT 0.945 2.98 1.135 4.11 ;
			LAYER M1 ;
			RECT 0.74 2.695 1.135 2.98 ;
			LAYER M1 ;
			RECT 0.74 2.6 1.12 2.695 ;
			LAYER M1 ;
			RECT 0.845 2.09 1.04 2.6 ;
			LAYER M1 ;
			RECT 0.79 1.03 1.07 2.09 ;
		END
		AntennaDiffArea 2.7104 ;
	END out
	PIN in1
		DIRECTION input ;
		USE SIGNAL ;
		PORT
			LAYER M1 ;
			RECT 2.345 3.845 2.625 3.91 ;
			LAYER M1 ;
			RECT 4.27 3.85 4.55 3.91 ;
			LAYER M1 ;
			RECT 4.27 3.845 5.275 3.85 ;
			LAYER M1 ;
			RECT 1.825 3.655 5.275 3.845 ;
			LAYER M1 ;
			RECT 1.825 2.57 2.015 3.655 ;
			LAYER M1 ;
			RECT 2.345 3.63 2.625 3.655 ;
			LAYER M1 ;
			RECT 4.27 3.63 4.55 3.655 ;
			LAYER M1 ;
			RECT 5.08 3.6 5.275 3.655 ;
			LAYER M1 ;
			RECT 5.08 3.5 5.46 3.6 ;
			LAYER M1 ;
			RECT 5.08 3.22 5.655 3.5 ;
			LAYER M1 ;
			RECT 1.78 2.29 2.06 2.57 ;
		END
		AntennaGateArea 1.848 ;
	END in1
	PIN GND
		DIRECTION inout ;
		USE GROUND ;
		PORT
			LAYER M1 ;
			RECT 1.97 0.42 2.25 1.68 ;
			LAYER M1 ;
			RECT 3.15 0.42 3.43 1.68 ;
			LAYER M1 ;
			RECT 5.57 0.42 5.85 2.505 ;
			LAYER M1 ;
			RECT 0.0 -0.42 6.82 0.42 ;
		END
	END GND
	PIN VDD
		DIRECTION inout ;
		USE POWER ;
		PORT
			LAYER M1 ;
			RECT 0.0 5.78 6.82 6.62 ;
			LAYER M1 ;
			RECT 0.16 4.11 0.44 5.78 ;
			LAYER M1 ;
			RECT 1.34 4.52 1.62 5.78 ;
			LAYER M1 ;
			RECT 3.28 4.52 3.56 5.78 ;
			LAYER M1 ;
			RECT 5.2 4.11 5.48 5.78 ;
			LAYER M1 ;
			RECT 6.38 4.11 6.66 5.78 ;
		END
	END VDD
	PIN in0
		DIRECTION input ;
		USE SIGNAL ;
		PORT
			LAYER M1 ;
			RECT 3.84 2.93 4.22 2.98 ;
			LAYER M1 ;
			RECT 3.53 2.65 4.22 2.93 ;
			LAYER M1 ;
			RECT 3.84 2.6 4.22 2.65 ;
		END
		AntennaGateArea 1.848 ;
	END in0
	OBS
		LAYER M1 ;
		RECT 5.79 4.11 6.07 5.58 ;
		LAYER M1 ;
		RECT 2.4 3.235 4.665 3.43 ;
		LAYER M1 ;
		RECT 2.4 2.94 2.595 3.235 ;
		LAYER M1 ;
		RECT 4.47 3.005 4.665 3.235 ;
		LAYER M1 ;
		RECT 2.36 2.66 2.64 2.94 ;
		LAYER M1 ;
		RECT 4.47 2.905 4.8 3.005 ;
		LAYER M1 ;
		RECT 5.87 2.905 6.06 4.11 ;
		LAYER M1 ;
		RECT 4.47 2.71 6.06 2.905 ;
		LAYER M1 ;
		RECT 4.61 2.505 4.8 2.71 ;
		LAYER M1 ;
		RECT 0.2 0.815 0.48 2.09 ;
		LAYER M1 ;
		RECT 1.38 1.9 4.035 2.09 ;
		LAYER M1 ;
		RECT 1.38 0.815 1.66 1.9 ;
		LAYER M1 ;
		RECT 0.2 0.62 1.66 0.815 ;
		LAYER M1 ;
		RECT 2.56 0.62 2.84 1.9 ;
		LAYER M1 ;
		RECT 3.755 0.62 4.035 1.9 ;
		LAYER M1 ;
		RECT 4.61 1.035 4.89 2.505 ;
	END
END MMI_XNOR2C
MACRO MMI_XOR2A
	CLASS CORE ;
	FOREIGN MMI_XOR2A 0 0 ;
	SIZE 4.34 BY 6.2 ;
	SYMMETRY X Y ;
	SITE CORE1 ;
	PIN out
		DIRECTION output ;
		USE SIGNAL ;
		PORT
			LAYER M1 ;
			RECT 0.16 3.51 0.44 4.98 ;
			LAYER M1 ;
			RECT 0.22 2.98 0.41 3.51 ;
			LAYER M1 ;
			RECT 0.12 2.6 0.5 2.98 ;
			LAYER M1 ;
			RECT 0.22 2.19 0.41 2.6 ;
			LAYER M1 ;
			RECT 0.22 2.0 0.985 2.19 ;
			LAYER M1 ;
			RECT 0.795 1.78 0.985 2.0 ;
			LAYER M1 ;
			RECT 0.795 1.08 1.075 1.78 ;
		END
		AntennaDiffArea 0.9471 ;
	END out
	PIN in1
		DIRECTION input ;
		USE SIGNAL ;
		PORT
			LAYER M1 ;
			RECT 3.22 2.93 3.6 2.98 ;
			LAYER M1 ;
			RECT 3.11 2.65 3.6 2.93 ;
			LAYER M1 ;
			RECT 3.22 2.6 3.6 2.65 ;
		END
		AntennaGateArea 0.63525 ;
	END in1
	PIN GND
		DIRECTION inout ;
		USE GROUND ;
		PORT
			LAYER M1 ;
			RECT 0.16 0.42 0.44 1.78 ;
			LAYER M1 ;
			RECT 1.755 0.42 2.035 1.78 ;
			LAYER M1 ;
			RECT 2.975 0.42 3.255 1.78 ;
			LAYER M1 ;
			RECT 0.0 -0.42 4.34 0.42 ;
		END
	END GND
	PIN VDD
		DIRECTION inout ;
		USE POWER ;
		PORT
			LAYER M1 ;
			RECT 0.0 5.78 4.34 6.62 ;
			LAYER M1 ;
			RECT 1.34 3.92 1.62 5.78 ;
			LAYER M1 ;
			RECT 3.48 3.51 3.76 5.78 ;
		END
	END VDD
	PIN in0
		DIRECTION input ;
		USE SIGNAL ;
		PORT
			LAYER M1 ;
			RECT 1.36 2.08 2.125 2.36 ;
			LAYER M1 ;
			RECT 1.36 1.98 1.74 2.08 ;
		END
		AntennaGateArea 0.63525 ;
	END in0
	OBS
		LAYER M1 ;
		RECT 0.75 3.7 1.03 4.98 ;
		LAYER M1 ;
		RECT 1.93 3.7 2.21 4.98 ;
		LAYER M1 ;
		RECT 0.75 3.505 2.21 3.7 ;
		LAYER M1 ;
		RECT 2.52 3.51 2.8 4.98 ;
		LAYER M1 ;
		RECT 0.705 2.915 0.985 2.92 ;
		LAYER M1 ;
		RECT 2.52 2.915 2.71 3.51 ;
		LAYER M1 ;
		RECT 0.705 2.725 2.71 2.915 ;
		LAYER M1 ;
		RECT 0.705 2.64 0.985 2.725 ;
		LAYER M1 ;
		RECT 2.385 1.78 2.575 2.725 ;
		LAYER M1 ;
		RECT 2.385 1.465 2.665 1.78 ;
	END
END MMI_XOR2A
MACRO MMI_XOR2B
	CLASS CORE ;
	FOREIGN MMI_XOR2B 0 0 ;
	SIZE 6.2 BY 6.2 ;
	SYMMETRY X Y ;
	SITE CORE1 ;
	PIN out
		DIRECTION output ;
		USE SIGNAL ;
		PORT
			LAYER M1 ;
			RECT 0.75 3.505 1.03 4.565 ;
			LAYER M1 ;
			RECT 0.12 2.885 0.5 2.98 ;
			LAYER M1 ;
			RECT 0.75 2.885 0.94 3.505 ;
			LAYER M1 ;
			RECT 0.12 2.695 0.94 2.885 ;
			LAYER M1 ;
			RECT 0.12 2.6 0.5 2.695 ;
			LAYER M1 ;
			RECT 0.75 2.335 0.94 2.695 ;
			LAYER M1 ;
			RECT 0.75 1.575 1.03 2.335 ;
			LAYER M1 ;
			RECT 1.93 1.575 2.21 1.915 ;
			LAYER M1 ;
			RECT 0.75 1.385 2.21 1.575 ;
		END
		AntennaDiffArea 1.32055 ;
	END out
	PIN in1
		DIRECTION input ;
		USE SIGNAL ;
		PORT
			LAYER M1 ;
			RECT 5.49 2.36 5.77 2.375 ;
			LAYER M1 ;
			RECT 5.49 2.095 6.085 2.36 ;
			LAYER M1 ;
			RECT 5.705 1.98 6.085 2.095 ;
		END
		AntennaGateArea 0.98175 ;
	END in1
	PIN GND
		DIRECTION inout ;
		USE GROUND ;
		PORT
			LAYER M1 ;
			RECT 0.16 0.42 0.44 2.335 ;
			LAYER M1 ;
			RECT 2.555 0.42 2.835 1.915 ;
			LAYER M1 ;
			RECT 3.735 0.42 4.015 2.335 ;
			LAYER M1 ;
			RECT 4.975 0.42 5.255 2.085 ;
			LAYER M1 ;
			RECT 0.0 -0.42 6.2 0.42 ;
		END
	END GND
	PIN VDD
		DIRECTION inout ;
		USE POWER ;
		PORT
			LAYER M1 ;
			RECT 0.0 5.78 6.2 6.62 ;
			LAYER M1 ;
			RECT 1.93 3.915 2.21 5.78 ;
			LAYER M1 ;
			RECT 3.11 3.915 3.39 5.78 ;
			LAYER M1 ;
			RECT 5.25 3.505 5.53 5.78 ;
		END
	END VDD
	PIN in0
		DIRECTION input ;
		USE SIGNAL ;
		PORT
			LAYER M1 ;
			RECT 5.08 2.935 5.46 2.98 ;
			LAYER M1 ;
			RECT 5.06 2.93 5.46 2.935 ;
			LAYER M1 ;
			RECT 4.78 2.65 5.46 2.93 ;
			LAYER M1 ;
			RECT 5.08 2.6 5.46 2.65 ;
		END
		AntennaGateArea 0.98175 ;
	END in0
	OBS
		LAYER M1 ;
		RECT 0.16 5.035 1.62 5.23 ;
		LAYER M1 ;
		RECT 0.16 3.505 0.44 5.035 ;
		LAYER M1 ;
		RECT 1.34 3.695 1.62 5.035 ;
		LAYER M1 ;
		RECT 2.52 3.695 2.8 4.975 ;
		LAYER M1 ;
		RECT 3.7 3.695 3.98 4.975 ;
		LAYER M1 ;
		RECT 1.34 3.505 3.98 3.695 ;
		LAYER M1 ;
		RECT 4.29 3.505 4.57 4.975 ;
		LAYER M1 ;
		RECT 1.145 3.16 1.425 3.205 ;
		LAYER M1 ;
		RECT 4.29 3.16 4.48 3.505 ;
		LAYER M1 ;
		RECT 1.145 2.965 4.575 3.16 ;
		LAYER M1 ;
		RECT 1.145 2.925 1.425 2.965 ;
		LAYER M1 ;
		RECT 1.36 2.335 3.435 2.34 ;
		LAYER M1 ;
		RECT 1.34 2.145 3.435 2.335 ;
		LAYER M1 ;
		RECT 1.34 2.055 1.62 2.145 ;
		LAYER M1 ;
		RECT 3.145 1.635 3.425 2.145 ;
		LAYER M1 ;
		RECT 4.385 2.085 4.575 2.965 ;
		LAYER M1 ;
		RECT 4.385 1.77 4.665 2.085 ;
	END
END MMI_XOR2B
MACRO MMI_XOR2C
	CLASS CORE ;
	FOREIGN MMI_XOR2C 0 0 ;
	SIZE 8.68 BY 6.2 ;
	SYMMETRY X Y ;
	SITE CORE1 ;
	PIN out
		DIRECTION output ;
		USE SIGNAL ;
		PORT
			LAYER M1 ;
			RECT 0.15 5.38 1.62 5.575 ;
			LAYER M1 ;
			RECT 0.16 3.59 0.44 5.38 ;
			LAYER M1 ;
			RECT 1.34 4.12 1.62 5.38 ;
			LAYER M1 ;
			RECT 0.24 2.98 0.43 3.59 ;
			LAYER M1 ;
			RECT 0.12 2.6 0.5 2.98 ;
			LAYER M1 ;
			RECT 0.24 2.005 0.43 2.6 ;
			LAYER M1 ;
			RECT 0.24 1.81 1.745 2.005 ;
			LAYER M1 ;
			RECT 0.24 1.305 0.52 1.81 ;
			LAYER M1 ;
			RECT 1.465 1.245 1.745 1.81 ;
			LAYER M1 ;
			RECT 2.645 1.245 2.925 1.33 ;
			LAYER M1 ;
			RECT 1.455 1.05 2.925 1.245 ;
		END
		AntennaDiffArea 2.94525 ;
	END out
	PIN in1
		DIRECTION input ;
		USE SIGNAL ;
		PORT
			LAYER M1 ;
			RECT 3.84 2.885 4.22 2.98 ;
			LAYER M1 ;
			RECT 5.96 2.885 6.24 2.975 ;
			LAYER M1 ;
			RECT 2.98 2.83 3.26 2.875 ;
			LAYER M1 ;
			RECT 3.84 2.83 6.24 2.885 ;
			LAYER M1 ;
			RECT 2.98 2.695 6.24 2.83 ;
			LAYER M1 ;
			RECT 2.98 2.64 4.22 2.695 ;
			LAYER M1 ;
			RECT 2.98 2.595 3.26 2.64 ;
			LAYER M1 ;
			RECT 3.84 2.6 4.22 2.64 ;
		END
		AntennaGateArea 1.9635 ;
	END in1
	PIN GND
		DIRECTION inout ;
		USE GROUND ;
		PORT
			LAYER M1 ;
			RECT 0.83 0.42 1.11 1.585 ;
			LAYER M1 ;
			RECT 3.825 0.42 4.105 1.33 ;
			LAYER M1 ;
			RECT 5.005 0.42 5.285 2.005 ;
			LAYER M1 ;
			RECT 6.445 0.42 6.725 2.095 ;
			LAYER M1 ;
			RECT 7.67 0.42 7.95 2.095 ;
			LAYER M1 ;
			RECT 0.0 -0.42 8.68 0.42 ;
		END
	END GND
	PIN VDD
		DIRECTION inout ;
		USE POWER ;
		PORT
			LAYER M1 ;
			RECT 0.0 5.78 8.68 6.62 ;
			LAYER M1 ;
			RECT 2.52 4.12 2.8 5.78 ;
			LAYER M1 ;
			RECT 3.7 4.12 3.98 5.78 ;
			LAYER M1 ;
			RECT 4.88 4.12 5.16 5.78 ;
			LAYER M1 ;
			RECT 6.06 3.59 6.34 5.78 ;
			LAYER M1 ;
			RECT 7.98 3.59 8.26 5.78 ;
		END
	END VDD
	PIN in0
		DIRECTION input ;
		USE SIGNAL ;
		PORT
			LAYER M1 ;
			RECT 6.59 2.66 6.87 2.94 ;
			LAYER M1 ;
			RECT 6.59 2.49 6.785 2.66 ;
			LAYER M1 ;
			RECT 4.78 2.3 6.785 2.49 ;
			LAYER M1 ;
			RECT 4.78 2.21 5.06 2.3 ;
			LAYER M1 ;
			RECT 5.69 1.95 6.08 2.3 ;
		END
		AntennaGateArea 1.9635 ;
	END in0
	OBS
		LAYER M1 ;
		RECT 0.75 3.78 1.03 5.04 ;
		LAYER M1 ;
		RECT 1.93 3.78 2.21 5.575 ;
		LAYER M1 ;
		RECT 3.11 3.78 3.39 5.575 ;
		LAYER M1 ;
		RECT 4.29 3.78 4.57 5.575 ;
		LAYER M1 ;
		RECT 5.47 3.78 5.75 5.575 ;
		LAYER M1 ;
		RECT 0.75 3.59 5.75 3.78 ;
		LAYER M1 ;
		RECT 7.02 3.59 7.3 5.06 ;
		LAYER M1 ;
		RECT 7.105 3.39 7.3 3.59 ;
		LAYER M1 ;
		RECT 0.96 3.2 7.3 3.39 ;
		LAYER M1 ;
		RECT 0.96 3.11 1.24 3.2 ;
		LAYER M1 ;
		RECT 1.0 2.595 1.195 3.11 ;
		LAYER M1 ;
		RECT 0.96 2.315 1.24 2.595 ;
		LAYER M1 ;
		RECT 2.055 1.815 4.695 2.01 ;
		LAYER M1 ;
		RECT 2.055 1.72 2.335 1.815 ;
		LAYER M1 ;
		RECT 3.235 1.05 3.515 1.815 ;
		LAYER M1 ;
		RECT 4.415 1.05 4.695 1.815 ;
		LAYER M1 ;
		RECT 7.105 2.095 7.3 3.2 ;
		LAYER M1 ;
		RECT 7.035 1.395 7.315 2.095 ;
	END
END MMI_XOR2C
END LIBRARY
